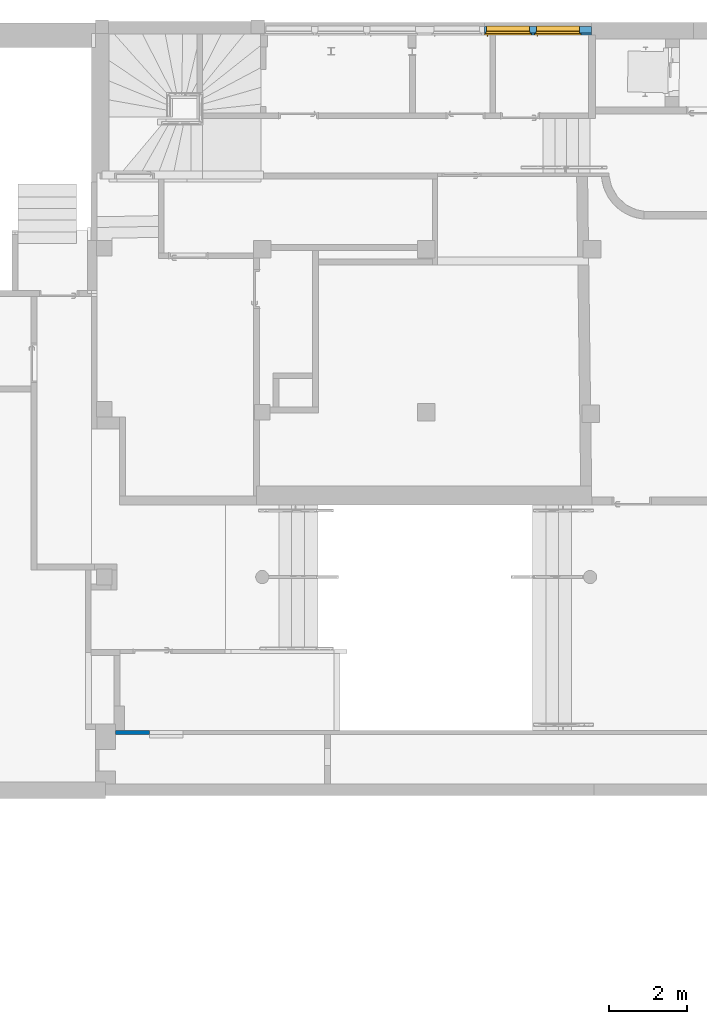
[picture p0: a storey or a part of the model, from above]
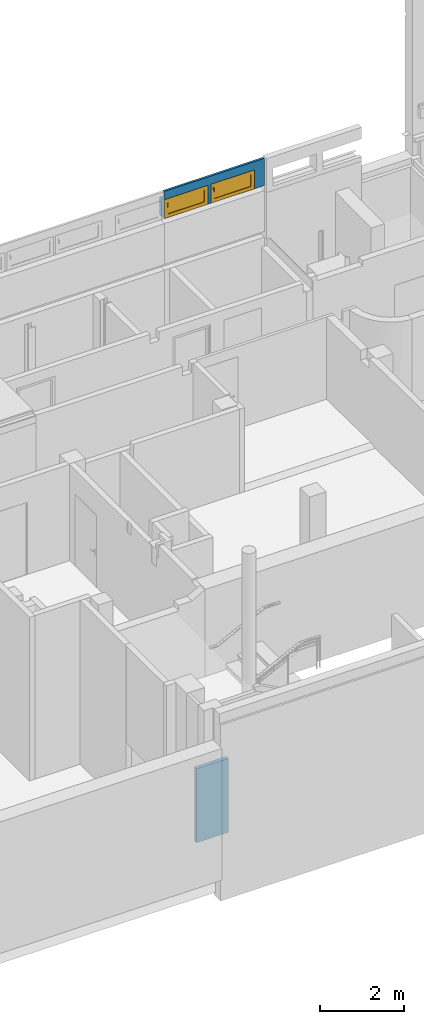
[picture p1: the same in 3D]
Properties of the parts of a building model (IFC4), part 1 of 8

# File
Description: ViewDefinition [ReferenceView_V1.2], ExchangeRequirement []
File name: 0001
Time: 2021-03-12T11:23:30
Author: Y.BENMESSAOUD, y.benmessaoud@geosolutions.pro
Organization: GEOSOLUTIONS
Written by: The EXPRESS Data Manager Version 5.02.0100.07 : 28 Aug 2013
Made in: 21.1.20.44 - Exporter 21.1.20.44 - Interface utilisateur alternative 21.1.20.44
Authorization: Y.B
Comment: STEP Physical File produced by: The EXPRESS Data Manager Version 5.02.0100.07 : 28 Aug 2013 * Module: EDMstepFileFactory/EDMstandAlone * Creation date: Fri Mar 12 11:23:30 2021 * Host: PC016 * Database: C:\Users\Y4B58~1.BEN\AppData\Local\Temp\75d09875-ea6d-4645-b1e7-cd248468171c\5325212e-278c-4a36-abae-7d6a19fac22a\ifc * Database version: 5507 * Database creation date: Fri Mar 12 11:21:37 2021 * Schema: IFC4 * Model: DataRepository.ifc * Model creation date: Fri Mar 12 11:21:38 2021 * Header model: DataRepository.ifc_HeaderModel * Header model creation date: Fri Mar 12 11:21:38 2021 * EDMuser: sdai-user * EDMgroup: sdai-group * License ID and type: 5605 : Permanent license. Expiry date: * EDMstepFileFactory options: 020000

# IfcProject, 0001
LongName: HOTEL CONSULAIRE; Phase: EXISTANT

# IfcSite, Default
RefLatitude: 50, 43, 39, 195556; RefLongitude: 1, 35, 57, 184839; RefElevation: 0 m
Pset_SiteCommon - Reference: Informations sur le projet

# IfcBuilding, HOTEL CONSULAIRE BOULOGNE SUR MER
LongName: HOTEL CONSULAIRE BOULOGNE SUR MER
Pset_BuildingCommon - Reference: Informations sur le projet; NumberOfStoreys: 7
Pset_BuildingElementProxyCommon - Reference: Informations sur le projet; IsExternal: no
Pset_BuildingStoreyCommon - Reference: Informations sur le projet; sets with these values: 2

# IfcBuildingStorey: Niveau:Ligne du Niveau (7)
In: HOTEL CONSULAIRE BOULOGNE SUR MER
Pset_BuildingStoreyCommon - Reference: Ligne du Niveau
Name | LongName | Elevation (m)
SS3 | SS3 | -5.02344
SS2 | SS2 | -4.01003
SS1 | SS1 | -2.70344
Demi-niveau | Demi-niveau | -1.4042
Niveau 0 | Niveau 0 | 1.31982e-13
Niveau 1 | Niveau 1 | 3.62153
Niveau 2 | Niveau 2 | 6.81974

# IfcBeam: Poutre rectangulaire - Béton:120X220 (9)
In: Niveau 0
Type - PredefinedType: BEAM; Material: Béton - Béton coulé sur place
Type - Pset_BeamCommon - IsExternal: no; LoadBearing: yes; Reference: 120X220
Type - Pset_EnvironmentalImpactIndicators - Reference: 120X220
Type - Pset_ReinforcementBarPitchOfBeam - Reference: 120X220
Pset_BeamCommon - Slope: 0 deg; Roll: 0 deg
Pset_EnvironmentalImpactIndicators - sets with these values: 2
Name (Poutre rectangulaire - Béton:120X220:...) | Span (m) | Length (m) | CrossSectionArea (m2) | OuterSurfaceArea (m2) | GrossSurfaceArea (m2) = NetSurfaceArea (m2) | GrossVolume (m3) = NetVolume (m3)
419842 | 0.91 | 0.12 | 0.343695 | 0.277296 | 0.687391 | 0.0246057
419898 | 0.91 | 0.12 | 0.343695 | 0.277296 | 0.687391 | 0.0246057
496445 | 3.734 | 3.70383 | 1.2857 | 2.5186 | 2.5714 | 0.097781
496534 | 1.556 | 1.56879 | 0.559788 | 1.06678 | 1.11958 | 0.041416
497781 | 3.808 | 3.8334 | 1.32976 | 2.60671 | 2.65951 | 0.101202
497919 | 3.809 | 3.8051 | 1.32013 | 2.58747 | 2.64027 | 0.100455
497978 | 1.556 | 1.5814 | 0.564076 | 1.07535 | 1.12815 | 0.041749
522441 | 2.453 | 2.39595 | 0.841024 | 1.62925 | 1.68205 | 0.0632531
522620 | 2.469 | 2.41269 | 0.846715 | 1.64063 | 1.69343 | 0.063695

# IfcBeam: Poutre rectangulaire - Béton:120X320 (2)
In: Niveau 0
Type - PredefinedType: BEAM; Material: Béton - Béton coulé sur place
Type - Pset_BeamCommon - IsExternal: no; LoadBearing: yes; Reference: 120X320
Type - Pset_EnvironmentalImpactIndicators - Reference: 120X320
Type - Pset_ReinforcementBarPitchOfBeam - Reference: 120X320
Pset_BeamCommon - Slope: 0 deg; Roll: 0 deg
Pset_EnvironmentalImpactIndicators - sets with these values: 2
Name (Poutre rectangulaire - Béton:120X320:...) | Span (m) | Length (m) | CrossSectionArea (m2) | OuterSurfaceArea (m2) | GrossSurfaceArea (m2) = NetSurfaceArea (m2) | GrossVolume (m3) = NetVolume (m3)
496558 | 3.69 | 3.7154 | 1.67318 | 3.26955 | 3.34635 | 0.142671
496571 | 3.673 | 3.6984 | 1.6657 | 3.25459 | 3.33139 | 0.142019

# IfcBeam: Poutre rectangulaire - Béton:150X180 (2)
In: Niveau 1
Type - PredefinedType: BEAM; Material: Béton - Béton coulé sur place
Type - Pset_BeamCommon - IsExternal: no; LoadBearing: yes; Reference: 150X180
Type - Pset_EnvironmentalImpactIndicators - Reference: 150X180
Type - Pset_ReinforcementBarPitchOfBeam - Reference: 150X180
Pset_BeamCommon - Slope: 0 deg; Roll: 0 deg
Pset_EnvironmentalImpactIndicators - sets with these values: 2
Name (Poutre rectangulaire - Béton:150X180:...) | Span (m) | Length (m) | CrossSectionArea (m2) | OuterSurfaceArea (m2) | GrossSurfaceArea (m2) = NetSurfaceArea (m2) | GrossVolume (m3) = NetVolume (m3)
509333 | 10.682 | 10.682 | 3.55206 | 7.05012 | 7.10412 | 0.288414
517769 | 10.69 | 10.6904 | 3.55483 | 7.05565 | 7.10965 | 0.28864

# IfcBeam: Poutre rectangulaire - Béton:150X320, Poutre rectangulaire - Béton:150X320:479398
In: SS1
Type - PredefinedType: BEAM; Material: Béton - Béton coulé sur place
Type - Pset_BeamCommon - IsExternal: no; LoadBearing: yes; Reference: 150X320
Type - Pset_EnvironmentalImpactIndicators - Reference: 150X320
Type - Pset_ReinforcementBarPitchOfBeam - Reference: 150X320
Pset_BeamCommon - Slope: 0 deg; Roll: 0 deg; Span: 3.882 m
Pset_EnvironmentalImpactIndicators - sets with these values: 2
Qto_BeamBaseQuantities - CrossSectionArea: 1.63884 m2; NetSurfaceArea: 3.27768 m2; NetVolume: 0.150758 m3

# IfcBeam: Poutre rectangulaire - Béton:150X350, Poutre rectangulaire - Béton:150X350:438477
In: SS1
Type - PredefinedType: BEAM; Material: Béton - Béton coulé sur place
Type - Pset_BeamCommon - IsExternal: no; LoadBearing: yes; Reference: 150X350
Type - Pset_EnvironmentalImpactIndicators - Reference: 150X350
Type - Pset_ReinforcementBarPitchOfBeam - Reference: 150X350
Pset_BeamCommon - Slope: 0 deg; Roll: 0 deg; Span: 1.591 m
Pset_EnvironmentalImpactIndicators - sets with these values: 2
Qto_BeamBaseQuantities - Length: 0.15 m; CrossSectionArea: 0.852494 m2; OuterSurfaceArea: 0.591723 m2; GrossSurfaceArea: 1.70499 m2; NetSurfaceArea: 1.70499 m2; GrossVolume: 0.0834949 m3; NetVolume: 0.0834949 m3

# IfcBeam: Poutre rectangulaire - Béton:150x120, Poutre rectangulaire - Béton:150x120:495247
In: Niveau 0
Type - PredefinedType: BEAM; Material: Béton - Béton coulé sur place
Type - Pset_BeamCommon - IsExternal: no; LoadBearing: yes; Reference: 150x120
Type - Pset_EnvironmentalImpactIndicators - Reference: 150x120
Type - Pset_ReinforcementBarPitchOfBeam - Reference: 150x120
Pset_BeamCommon - Slope: 0 deg; Roll: 0 deg; Span: 5.316 m
Pset_EnvironmentalImpactIndicators - sets with these values: 2
Qto_BeamBaseQuantities - CrossSectionArea: 1.45496 m2; NetSurfaceArea: 2.90992 m2; NetVolume: 0.0956999 m3

# IfcBeam: Poutre rectangulaire - Béton:180X320 (5)
In: SS1
Type - PredefinedType: BEAM; Material: Béton - Béton coulé sur place
Type - Pset_BeamCommon - IsExternal: no; LoadBearing: yes; Reference: 180X320
Type - Pset_EnvironmentalImpactIndicators - Reference: 180X320
Type - Pset_ReinforcementBarPitchOfBeam - Reference: 180X320
Pset_BeamCommon - Slope: 0 deg; Roll: 0 deg
Pset_EnvironmentalImpactIndicators - sets with these values: 2
Name (Poutre rectangulaire - Béton:180X320:...) | Span (m) | CrossSectionArea (m2) | NetSurfaceArea (m2) | NetVolume (m3)
438396 | 1.131 | 0.618873 | 1.23775 | 0.0576957
438448 | 1.591 | 0.85945 | 1.7189 | 0.0923731 | Qto_BeamBaseQuantities - Length: 1.6037 m; OuterSurfaceArea: 1.6037 m2; GrossSurfaceArea: 1.7189 m2; GrossVolume: 0.0923731 m3
438622 | 1.591 | 0.85945 | 1.7189 | 0.0923731 | Qto_BeamBaseQuantities - Length: 1.6037 m; OuterSurfaceArea: 1.6037 m2; GrossSurfaceArea: 1.7189 m2; GrossVolume: 0.0923731 m3
479470 | 3.848 | 1.99374 | 3.98748 | 0.216989
479620 | 3.883 | 1.86644 | 3.73288 | 0.197431

# IfcBeam: Poutre rectangulaire - Béton:180X480, Poutre rectangulaire - Béton:180X480:495458
In: SS1
Type - PredefinedType: BEAM; Material: Béton - Béton coulé sur place
Type - Pset_BeamCommon - IsExternal: no; LoadBearing: yes; Reference: 180X480
Type - Pset_EnvironmentalImpactIndicators - Reference: 180X480
Type - Pset_ReinforcementBarPitchOfBeam - Reference: 180X480
Pset_BeamCommon - Slope: 0 deg; Roll: 0 deg; Span: 2.795 m
Pset_EnvironmentalImpactIndicators - sets with these values: 2
Qto_BeamBaseQuantities - Length: 2.79514 m; CrossSectionArea: 1.93119 m2; OuterSurfaceArea: 3.68958 m2; GrossSurfaceArea: 3.86238 m2; NetSurfaceArea: 3.86238 m2; GrossVolume: 0.2415 m3; NetVolume: 0.2415 m3

# IfcBeam: Poutre rectangulaire - Béton:200x200, Poutre rectangulaire - Béton:200x200:466131
In: Demi-niveau
Type - PredefinedType: BEAM; Material: Béton - Béton coulé sur place
Type - Pset_BeamCommon - IsExternal: no; LoadBearing: yes; Reference: 200x200
Type - Pset_EnvironmentalImpactIndicators - Reference: 200x200
Type - Pset_ReinforcementBarPitchOfBeam - Reference: 200x200
Pset_BeamCommon - Slope: 0 deg; Roll: 0 deg; Span: 1.591 m
Pset_EnvironmentalImpactIndicators - sets with these values: 2
Qto_BeamBaseQuantities - CrossSectionArea: 0.681313 m2; NetSurfaceArea: 1.36263 m2; NetVolume: 0.0641282 m3

# IfcBeam: Poutre rectangulaire - Béton:200x300, Poutre rectangulaire - Béton:200x300:425816
In: SS1
Type - PredefinedType: BEAM; Material: Béton - Béton coulé sur place
Type - Pset_BeamCommon - IsExternal: no; LoadBearing: yes; Reference: 200x300
Type - Pset_EnvironmentalImpactIndicators - Reference: 200x300
Type - Pset_ReinforcementBarPitchOfBeam - Reference: 200x300
Pset_BeamCommon - Slope: 0 deg; Roll: 0 deg; Span: 3.853 m
Pset_EnvironmentalImpactIndicators - sets with these values: 2
Qto_BeamBaseQuantities - Length: 3.8784 m; CrossSectionArea: 1.97881 m2; OuterSurfaceArea: 3.83962 m2; GrossSurfaceArea: 3.95762 m2; NetSurfaceArea: 3.95762 m2; GrossVolume: 0.228826 m3; NetVolume: 0.228826 m3

# IfcBeam: Poutre rectangulaire - Béton:220x150 (6)
In: Niveau 2
Type - PredefinedType: BEAM; Material: Béton - Béton coulé sur place
Type - Pset_BeamCommon - IsExternal: no; LoadBearing: yes; Reference: 220x150
Type - Pset_EnvironmentalImpactIndicators - Reference: 220x150
Type - Pset_ReinforcementBarPitchOfBeam - Reference: 220x150
Pset_BeamCommon - Slope: 0 deg; Roll: 0 deg
Pset_EnvironmentalImpactIndicators - sets with these values: 2
Name (Poutre rectangulaire - Béton:220x150:...) | Span (m) | Length (m) | CrossSectionArea (m2) | OuterSurfaceArea (m2) | GrossSurfaceArea (m2) = NetSurfaceArea (m2) | GrossVolume (m3) = NetVolume (m3)
592660 | 3.119 | 3.33938 | 1.26857 | 2.47114 | 2.53714 | 0.1102
592949 | 3.961 | 4.18067 | 1.57985 | 3.09369 | 3.15969 | 0.137962
593402 | 0.841 | 1.06129 | 0.425677 | 0.785354 | 0.851354 | 0.0350225
593489 | 1.376 | 1.15584 | 0.460659 | 0.855319 | 0.921319 | 0.0381426
593530 | 2.823 | 2.60284 | 0.996049 | 1.9261 | 1.9921 | 0.0858936
593667 | 1.447 | 1.227 | 0.48699 | 0.90798 | 0.97398 | 0.040491

# IfcBeam: Poutre rectangulaire - Béton:220x280, Poutre rectangulaire - Béton:220x280:480112
In: SS1
Type - PredefinedType: BEAM; Material: Béton - Béton coulé sur place
Type - Pset_BeamCommon - IsExternal: no; LoadBearing: yes; Reference: 220x280
Type - Pset_EnvironmentalImpactIndicators - Reference: 220x280
Type - Pset_ReinforcementBarPitchOfBeam - Reference: 220x280
Pset_BeamCommon - Slope: 0 deg; Roll: 0 deg; Span: 1.591 m
Pset_EnvironmentalImpactIndicators - sets with these values: 2
Qto_BeamBaseQuantities - Length: 0.22 m; CrossSectionArea: 0.857457 m2; OuterSurfaceArea: 0.828896 m2; GrossSurfaceArea: 1.70888 m2; NetSurfaceArea: 1.71491 m2; GrossVolume: 0.0967978 m3; NetVolume: 0.0968062 m3

# IfcBeam: Poutre rectangulaire - Béton:250X200., Poutre rectangulaire - Béton:250X200.:419462
In: Niveau 0
Type - PredefinedType: BEAM; Material: Béton - Béton coulé sur place
Type - Pset_BeamCommon - IsExternal: no; LoadBearing: yes; Reference: 250X200.
Type - Pset_EnvironmentalImpactIndicators - Reference: 250X200.
Type - Pset_ReinforcementBarPitchOfBeam - Reference: 250X200.
Pset_BeamCommon - Slope: 0 deg; Roll: 0 deg; Span: 5.84 m
Pset_EnvironmentalImpactIndicators - sets with these values: 2
Qto_BeamBaseQuantities - CrossSectionArea: 2.6234 m2; NetSurfaceArea: 5.2468 m2; NetVolume: 0.277981 m3

# IfcBeam: Poutre rectangulaire - Béton:250X300 (5)
In: SS1
Type - PredefinedType: BEAM; Material: Béton - Béton coulé sur place
Type - Pset_BeamCommon - IsExternal: no; LoadBearing: yes; Reference: 250X300
Type - Pset_EnvironmentalImpactIndicators - Reference: 250X300
Type - Pset_ReinforcementBarPitchOfBeam - Reference: 250X300
Pset_BeamCommon - Slope: 0 deg; Roll: 0 deg
Pset_EnvironmentalImpactIndicators - sets with these values: 2
Name (Poutre rectangulaire - Béton:250X300:...) | Span (m) | CrossSectionArea (m2) | NetSurfaceArea (m2) | NetVolume (m3) | Length (m) | OuterSurfaceArea (m2) | GrossSurfaceArea (m2) | GrossVolume (m3)
443087 | 5.256 | 2.76931 | 5.53862 | 0.346448
445260 | 11.804 | 5.97533 | 11.9507 | 0.757745 | 0.25 | 2.00642 | 4.05524 | 0.256102
479332 | 9.543 | 4.8422 | 9.6844 | 0.59986
479349 | 3.93 | 2.00238 | 4.00476 | 0.239721 | 3.93 | 3.88277 | 4.00476 | 0.239721
479363 | 3.93 | 2.00865 | 4.01731 | 0.240495 | 3.9427 | 3.89531 | 4.01731 | 0.240495

# IfcBeam: Poutre rectangulaire - Béton:250X370, Poutre rectangulaire - Béton:250X370:483398
In: Demi-niveau
Type - PredefinedType: BEAM; Material: Béton - Béton coulé sur place
Type - Pset_BeamCommon - IsExternal: no; LoadBearing: yes; Reference: 250X370
Type - Pset_EnvironmentalImpactIndicators - Reference: 250X370
Type - Pset_ReinforcementBarPitchOfBeam - Reference: 250X370
Pset_BeamCommon - Slope: 0 deg; Roll: 0 deg; Span: 4.268 m
Pset_EnvironmentalImpactIndicators - sets with these values: 2
Qto_BeamBaseQuantities - CrossSectionArea: 2.74314 m2; NetSurfaceArea: 5.48628 m2; NetVolume: 0.371816 m3

# IfcBeam: Poutre rectangulaire - Béton:250X400 (2)
Type - PredefinedType: BEAM; Material: Béton - Béton coulé sur place
Type - Pset_BeamCommon - IsExternal: no; LoadBearing: yes; Reference: 250X400
Type - Pset_EnvironmentalImpactIndicators - Reference: 250X400
Type - Pset_ReinforcementBarPitchOfBeam - Reference: 250X400
Pset_BeamCommon - Slope: 0 deg; Roll: 0 deg
Pset_EnvironmentalImpactIndicators - sets with these values: 2
Name (Poutre rectangulaire - Béton:250X400:...) | In | Span (m) | CrossSectionArea (m2) | NetSurfaceArea (m2) | NetVolume (m3)
437257 | SS1 | 4.2 | 2.5859 | 5.1718 | 0.3741
494699 | Niveau 0 | 5.311 | 3.55705 | 7.1141 | 0.531137

# IfcBeam: Poutre rectangulaire - Béton:250x220 (3)
In: Niveau 0
Type - PredefinedType: BEAM; Material: Béton - Béton coulé sur place
Type - Pset_BeamCommon - IsExternal: no; LoadBearing: yes; Reference: 250x220
Type - Pset_EnvironmentalImpactIndicators - Reference: 250x220
Type - Pset_ReinforcementBarPitchOfBeam - Reference: 250x220
Pset_BeamCommon - Slope: 0 deg; Roll: 0 deg
Pset_EnvironmentalImpactIndicators - sets with these values: 2
Name (Poutre rectangulaire - Béton:250x220:...) | Span (m) | CrossSectionArea (m2) | NetSurfaceArea (m2) | NetVolume (m3) | Length (m) | OuterSurfaceArea (m2) | GrossSurfaceArea (m2) | GrossVolume (m3)
495977 | 12.18 | 5.63001 | 11.26 | 0.629502
496175 | 4.319 | 1.98275 | 3.9655 | 0.225588 | 4.1016 | 3.8555 | 3.9655 | 0.225588
496276 | 4.239 | 1.94515 | 3.8903 | 0.221188 | 4.0216 | 3.7803 | 3.8903 | 0.221188

# IfcBeam: Poutre rectangulaire - Béton:250x270 (2)
In: SS1
Type - PredefinedType: BEAM; Material: Béton - Béton coulé sur place
Type - Pset_BeamCommon - IsExternal: no; LoadBearing: yes; Reference: 250x270
Type - Pset_EnvironmentalImpactIndicators - Reference: 250x270
Type - Pset_ReinforcementBarPitchOfBeam - Reference: 250x270
Pset_BeamCommon - Slope: 0 deg; Roll: 0 deg
Pset_EnvironmentalImpactIndicators - sets with these values: 2
Name (Poutre rectangulaire - Béton:250x270:...) | Span (m) | Length (m) | CrossSectionArea (m2) | OuterSurfaceArea (m2) | GrossSurfaceArea (m2) | NetSurfaceArea (m2) | GrossVolume (m3) | NetVolume (m3)
443327 | 1.841 | 1.8664 | 0.877161 | 1.65733 | 1.75432 | 1.75432 | 0.090516 | 0.090516
479862 | 1.591 | 0.25 | 0.895841 | 0.936927 | 1.78483 | 1.79168 | 0.105988 | 0.105997

# IfcBeam: Poutre rectangulaire - Béton:250x320, Poutre rectangulaire - Béton:250x320:425621
In: SS1
Type - PredefinedType: BEAM; Material: Béton - Béton coulé sur place
Type - Pset_BeamCommon - IsExternal: no; LoadBearing: yes; Reference: 250x320
Type - Pset_EnvironmentalImpactIndicators - Reference: 250x320
Type - Pset_ReinforcementBarPitchOfBeam - Reference: 250x320
Pset_BeamCommon - Slope: 0 deg; Roll: 0 deg; Span: 1.618 m
Pset_EnvironmentalImpactIndicators - sets with these values: 2
Qto_BeamBaseQuantities - Length: 1.4307 m; CrossSectionArea: 0.895499 m2; OuterSurfaceArea: 1.631 m2; GrossSurfaceArea: 1.791 m2; NetSurfaceArea: 1.791 m2; GrossVolume: 0.114456 m3; NetVolume: 0.114456 m3

# IfcBeam: Poutre rectangulaire - Béton:250x340, Poutre rectangulaire - Béton:250x340:597369
In: Niveau 2
Type - PredefinedType: BEAM; Material: Béton - Béton coulé sur place
Type - Pset_BeamCommon - IsExternal: no; LoadBearing: yes; Reference: 250x340
Type - Pset_EnvironmentalImpactIndicators - Reference: 250x340
Type - Pset_ReinforcementBarPitchOfBeam - Reference: 250x340
Pset_BeamCommon - Slope: 0 deg; Roll: 0 deg; Span: 9.624 m
Pset_EnvironmentalImpactIndicators - sets with these values: 2
Qto_BeamBaseQuantities - Length: 0.25 m; CrossSectionArea: 5.77457 m2; OuterSurfaceArea: 5.00569 m2; GrossSurfaceArea: 11.5491 m2; NetSurfaceArea: 11.5491 m2; GrossVolume: 0.817932 m3; NetVolume: 0.817932 m3

# IfcBeam: Poutre rectangulaire - Béton:250x500, Poutre rectangulaire - Béton:250x500:485414
In: SS1
Type - PredefinedType: BEAM; Material: Béton - Béton coulé sur place
Type - Pset_BeamCommon - IsExternal: no; LoadBearing: yes; Reference: 250x500
Type - Pset_EnvironmentalImpactIndicators - Reference: 250x500
Type - Pset_ReinforcementBarPitchOfBeam - Reference: 250x500
Pset_BeamCommon - Slope: 0 deg; Roll: 0 deg; Span: 2.428 m
Pset_EnvironmentalImpactIndicators - sets with these values: 2
Qto_BeamBaseQuantities - CrossSectionArea: 1.79501 m2; NetSurfaceArea: 3.59001 m2; NetVolume: 0.272481 m3

# IfcBeam: Poutre rectangulaire - Béton:260X520 (2)
In: SS1
Type - PredefinedType: BEAM; Material: Béton - Béton coulé sur place
Type - Pset_BeamCommon - IsExternal: no; LoadBearing: yes; Reference: 260X520
Type - Pset_EnvironmentalImpactIndicators - Reference: 260X520
Type - Pset_ReinforcementBarPitchOfBeam - Reference: 260X520
Pset_BeamCommon - Slope: 0 deg; Roll: 0 deg; Span: 5.35 m
Pset_EnvironmentalImpactIndicators - sets with these values: 2
Name (Poutre rectangulaire - Béton:260X520:...) | CrossSectionArea (m2) | NetSurfaceArea (m2) | NetVolume (m3)
436179 | 4.25982 | 8.51964 | 0.617223
486168 | 4.32798 | 8.65596 | 0.714563

# IfcBeam: Poutre rectangulaire - Béton:270x650 (3)
In: Niveau 2
Type - PredefinedType: BEAM; Material: Béton - Béton coulé sur place
Type - Pset_BeamCommon - IsExternal: no; LoadBearing: yes; Reference: 270x650
Type - Pset_EnvironmentalImpactIndicators - Reference: 270x650
Type - Pset_ReinforcementBarPitchOfBeam - Reference: 270x650
Pset_BeamCommon - Slope: 0 deg; Roll: 0 deg
Pset_EnvironmentalImpactIndicators - sets with these values: 2
Name (Poutre rectangulaire - Béton:270x650:...) | Span (m) | Length (m) | CrossSectionArea (m2) | OuterSurfaceArea (m2) | GrossSurfaceArea (m2) | NetSurfaceArea (m2) | GrossVolume (m3) | NetVolume (m3)
568801 | 8.436 | 0.27 | 8.1341 | 5.08621 | 16.2682 | 16.2682 | 1.50957 | 1.50957
568870 | 8.436 | 0.27 | 8.1341 | 5.08621 | 16.2682 | 16.2682 | 1.50957 | 1.50957
580515 | 4.169 |  | 4.03435 |  |  | 8.0687 |  | 0.697556

# IfcBeam: Poutre rectangulaire - Béton:300X320, Poutre rectangulaire - Béton:300X320:485666
In: SS1
Type - PredefinedType: BEAM; Material: Béton - Béton coulé sur place
Type - Pset_BeamCommon - IsExternal: no; LoadBearing: yes; Reference: 300X320
Type - Pset_EnvironmentalImpactIndicators - Reference: 300X320
Type - Pset_ReinforcementBarPitchOfBeam - Reference: 300X320
Pset_BeamCommon - Slope: 0 deg; Roll: 0 deg; Span: 4.033 m
Pset_EnvironmentalImpactIndicators - sets with these values: 2
Qto_BeamBaseQuantities - CrossSectionArea: 2.44328 m2; NetSurfaceArea: 4.88656 m2; NetVolume: 0.252812 m3

# IfcBeam: Poutre rectangulaire - Béton:300X400 (3)
Type - PredefinedType: BEAM; Material: Béton - Béton coulé sur place
Type - Pset_BeamCommon - IsExternal: no; LoadBearing: yes; Reference: 300X400
Type - Pset_EnvironmentalImpactIndicators - Reference: 300X400
Type - Pset_ReinforcementBarPitchOfBeam - Reference: 300X400
Pset_BeamCommon - Slope: 0 deg; Roll: 0 deg
Pset_EnvironmentalImpactIndicators - sets with these values: 2
Name (Poutre rectangulaire - Béton:300X400:...) | In | Span (m) | CrossSectionArea (m2) | NetSurfaceArea (m2) | NetVolume (m3)
521220 | Demi-niveau | 4.409 | 3.18887 | 6.37774 | 0.519366
556946 | Niveau 2 | 4.409 | 3.22408 | 6.44816 | 0.532128 | Qto_BeamBaseQuantities - Length: 4.4344 m; OuterSurfaceArea: 6.20816 m2; GrossSurfaceArea: 6.44816 m2; GrossVolume: 0.532128 m3
587859 | Niveau 2 | 9.679 | 7.71486 | 15.4297 | 1.01394

# IfcBeam: Poutre rectangulaire - Béton:300x300, Poutre rectangulaire - Béton:300x300:449726
In: SS1
Type - PredefinedType: BEAM; Material: Béton - Béton coulé sur place
Type - Pset_BeamCommon - IsExternal: no; LoadBearing: yes; Reference: 300x300
Type - Pset_EnvironmentalImpactIndicators - Reference: 300x300
Type - Pset_ReinforcementBarPitchOfBeam - Reference: 300x300
Pset_BeamCommon - Slope: 0 deg; Roll: 0 deg; Span: 3.85 m
Pset_EnvironmentalImpactIndicators - sets with these values: 2
Qto_BeamBaseQuantities - Length: 3.84949 m; CrossSectionArea: 2.37476 m2; OuterSurfaceArea: 4.57312 m2; GrossSurfaceArea: 4.74952 m2; NetSurfaceArea: 4.74952 m2; GrossVolume: 0.339514 m3; NetVolume: 0.339514 m3

# IfcBeam: Poutre rectangulaire - Béton:300x340 (3)
In: Niveau 2
Type - PredefinedType: BEAM; Material: Béton - Béton coulé sur place
Type - Pset_BeamCommon - IsExternal: no; LoadBearing: yes; Reference: 300x340
Type - Pset_EnvironmentalImpactIndicators - Reference: 300x340
Type - Pset_ReinforcementBarPitchOfBeam - Reference: 300x340
Pset_BeamCommon - Slope: 0 deg; Roll: 0 deg
Pset_EnvironmentalImpactIndicators - sets with these values: 2
Name (Poutre rectangulaire - Béton:300x340:...) | Span (m) | Length (m) | CrossSectionArea (m2) | OuterSurfaceArea (m2) | GrossSurfaceArea (m2) = NetSurfaceArea (m2) | GrossVolume (m3) = NetVolume (m3)
565609 | 10.917 | 10.77 | 6.99483 | 13.7857 | 13.9897 | 1.09854
569971 | 11.121 | 10.9741 | 7.1254 | 14.0468 | 14.2508 | 1.11935
587700 | 9.235 | 9.1163 | 5.93643 | 11.6689 | 11.8729 | 0.929863

# IfcBeam: Poutre rectangulaire - Béton:320x340 (17)
Type - PredefinedType: BEAM; Material: Béton - Béton coulé sur place
Type - Pset_BeamCommon - IsExternal: no; LoadBearing: yes; Reference: 320x340
Type - Pset_EnvironmentalImpactIndicators - Reference: 320x340
Type - Pset_ReinforcementBarPitchOfBeam - Reference: 320x340
Pset_BeamCommon - Slope: 0 deg; Roll: 0 deg
Pset_EnvironmentalImpactIndicators - sets with these values: 2
Name (Poutre rectangulaire - Béton:320x340:...) | In | Span (m) | CrossSectionArea (m2) | NetSurfaceArea (m2) | NetVolume (m3) | Length (m) | OuterSurfaceArea (m2) | GrossSurfaceArea (m2) | GrossVolume (m3)
372262 | Niveau 0 | 19.81 | 13.3147 | 26.6294 | 2.12422
372480 | Niveau 0 | 8.46 | 5.5722 | 11.1444 | 0.835632 | 8.29 | 10.9428 | 11.1444 | 0.835632
372955 | Niveau 0 | 36.463 | 23.9854 | 47.9707 | 3.76658
372963 | Niveau 0 | 19.81 | 12.9652 | 25.9305 | 2.11936 | 19.4794 | 25.7129 | 25.9305 | 2.11936
373407 | Niveau 0 | 10.996 | 7.36643 | 14.7329 | 1.15006
395639 | Niveau 0 | 11.377 | 7.40403 | 14.8081 | 1.18467 | 10.6904 | 14.1113 | 14.3289 | 1.16311
507128 | Niveau 1 | 19.81 | 12.9583 | 25.9167 | 2.11283 | 19.4694 | 25.6997 | 25.9167 | 2.11283
507182 | Niveau 2 | 19.81 | 12.9586 | 25.9173 | 2.11827 | 19.4694 | 25.6997 | 25.9173 | 2.11827
507630 | Niveau 1 | 25.271 | 16.6752 | 33.3504 | 2.72304
507632 | Niveau 1 | 25.271 | 16.6752 | 33.3504 | 2.7309 | 0.32 | 16.2823 | 33.3504 | 2.7309
507637 | Niveau 2 | 25.271 | 16.6752 | 33.3504 | 2.73095 | 25.1006 | 33.1328 | 33.3504 | 2.73095
507639 | Niveau 2 | 25.271 | 16.6752 | 33.3504 | 2.73095 | 25.1006 | 33.1328 | 33.3504 | 2.73095
508130 | Niveau 1 | 19.81 | 12.9586 | 25.9173 | 2.11827 | 19.4694 | 25.6997 | 25.9173 | 2.11827
508134 | Niveau 2 | 19.64 | 12.9586 | 25.9173 | 2.11827 | 19.4694 | 25.6997 | 25.9173 | 2.11827
509055 | Niveau 2 | 10.682 | 7.15892 | 14.3178 | 1.1622 | 10.682 | 14.1002 | 14.3178 | 1.1622
517431 | Niveau 2 | 10.69 | 7.16445 | 14.3289 | 1.16311 | 10.6904 | 14.1113 | 14.3289 | 1.16311
578897 | Niveau 2 | 12.491 | 8.55065 | 17.1013 | 1.39163 | 12.7907 | 16.8837 | 17.1013 | 1.39163

# IfcBeam: Poutre rectangulaire - Béton:350X200., Poutre rectangulaire - Béton:350X200.:419564
In: Niveau 0
Type - PredefinedType: BEAM; Material: Béton - Béton coulé sur place
Type - Pset_BeamCommon - IsExternal: no; LoadBearing: yes; Reference: 350X200.
Type - Pset_EnvironmentalImpactIndicators - Reference: 350X200.
Type - Pset_ReinforcementBarPitchOfBeam - Reference: 350X200.
Pset_BeamCommon - Slope: 0 deg; Roll: 0 deg; Span: 1.42 m
Pset_EnvironmentalImpactIndicators - sets with these values: 2
Qto_BeamBaseQuantities - CrossSectionArea: 0.78773 m2; NetSurfaceArea: 1.57546 m2; NetVolume: 0.0808091 m3

# IfcBeam: Poutre rectangulaire - Béton:350x320, Poutre rectangulaire - Béton:350x320:499010
In: Niveau 0
Type - PredefinedType: BEAM; Material: Béton - Béton coulé sur place
Type - Pset_BeamCommon - IsExternal: no; LoadBearing: yes; Reference: 350x320
Type - Pset_EnvironmentalImpactIndicators - Reference: 350x320
Type - Pset_ReinforcementBarPitchOfBeam - Reference: 350x320
Pset_BeamCommon - Slope: 0 deg; Roll: 0 deg; Span: 4.021 m
Pset_EnvironmentalImpactIndicators - sets with these values: 2
Qto_BeamBaseQuantities - Length: 0.35 m; CrossSectionArea: 2.82144 m2; OuterSurfaceArea: 1.08842 m2; GrossSurfaceArea: 1.82628 m2; NetSurfaceArea: 5.64289 m2; GrossVolume: 0.129125 m3; NetVolume: 0.406841 m3

# IfcBeam: Poutre rectangulaire - Béton:360x640, Poutre rectangulaire - Béton:360x640:557096
In: Niveau 2
Type - PredefinedType: BEAM; Material: Béton - Béton coulé sur place
Type - Pset_BeamCommon - IsExternal: no; LoadBearing: yes; Reference: 360x640
Type - Pset_EnvironmentalImpactIndicators - Reference: 360x640
Type - Pset_ReinforcementBarPitchOfBeam - Reference: 360x640
Pset_BeamCommon - Slope: 0 deg; Roll: 0 deg; Span: 10.093 m
Pset_EnvironmentalImpactIndicators - sets with these values: 2
Qto_BeamBaseQuantities - Length: 3.79888 m; CrossSectionArea: 10.0369 m2; OuterSurfaceArea: 7.59776 m2; GrossSurfaceArea: 8.05856 m2; NetSurfaceArea: 20.0739 m2; GrossVolume: 0.875262 m3; NetVolume: 2.15326 m3

# IfcBeam: Poutre rectangulaire - Béton:360x720, Poutre rectangulaire - Béton:360x720:442139
In: SS1
Type - PredefinedType: BEAM; Material: Béton - Béton coulé sur place
Type - Pset_BeamCommon - IsExternal: no; LoadBearing: yes; Reference: 360x720
Type - Pset_EnvironmentalImpactIndicators - Reference: 360x720
Type - Pset_ReinforcementBarPitchOfBeam - Reference: 360x720
Pset_BeamCommon - Slope: 0 deg; Roll: 0 deg; Span: 1.355 m
Pset_EnvironmentalImpactIndicators - sets with these values: 2
Qto_BeamBaseQuantities - CrossSectionArea: 1.71607 m2; NetSurfaceArea: 3.43215 m2; NetVolume: 0.315977 m3

# IfcBeam: Poutre rectangulaire - Béton:380X610, Poutre rectangulaire - Béton:380X610:461217
In: Niveau 0
Type - PredefinedType: BEAM; Material: Béton - Béton coulé sur place
Type - Pset_BeamCommon - IsExternal: no; LoadBearing: yes; Reference: 380X610
Type - Pset_EnvironmentalImpactIndicators - Reference: 380X610
Type - Pset_ReinforcementBarPitchOfBeam - Reference: 380X610
Pset_BeamCommon - Slope: 0 deg; Roll: 0 deg; Span: 9.36 m
Pset_EnvironmentalImpactIndicators - sets with these values: 2
Qto_BeamBaseQuantities - Length: 9.3854 m; CrossSectionArea: 9.52335 m2; OuterSurfaceArea: 18.5831 m2; GrossSurfaceArea: 19.0467 m2; NetSurfaceArea: 19.0467 m2; GrossVolume: 2.17554 m3; NetVolume: 2.17554 m3

# IfcBeam: Poutre rectangulaire - Béton:400X360, Poutre rectangulaire - Béton:400X360:440370
In: SS1
Type - PredefinedType: BEAM; Material: Béton - Béton coulé sur place
Type - Pset_BeamCommon - IsExternal: no; LoadBearing: yes; Reference: 400X360
Type - Pset_EnvironmentalImpactIndicators - Reference: 400X360
Type - Pset_ReinforcementBarPitchOfBeam - Reference: 400X360
Pset_BeamCommon - Slope: 0 deg; Roll: 0 deg; Span: 4.158 m
Pset_EnvironmentalImpactIndicators - sets with these values: 2
Qto_BeamBaseQuantities - CrossSectionArea: 2.85493 m2; NetSurfaceArea: 5.70986 m2; NetVolume: 0.441436 m3

# IfcBeam: Poutre rectangulaire - Béton:400x220 (3)
In: Niveau 0
Type - PredefinedType: BEAM; Material: Béton - Béton coulé sur place
Type - Pset_BeamCommon - IsExternal: no; LoadBearing: yes; Reference: 400x220
Type - Pset_EnvironmentalImpactIndicators - Reference: 400x220
Type - Pset_ReinforcementBarPitchOfBeam - Reference: 400x220
Pset_BeamCommon - Slope: 0 deg; Roll: 0 deg
Pset_EnvironmentalImpactIndicators - sets with these values: 2
Name (Poutre rectangulaire - Béton:400x220:...) | Span (m) | CrossSectionArea (m2) | NetSurfaceArea (m2) | NetVolume (m3) | Length (m) | OuterSurfaceArea (m2) | GrossSurfaceArea (m2) | GrossVolume (m3)
498307 | 7.837 | 4.82404 | 9.64808 | 0.651843
498462 | 3.692 | 2.3772 | 4.75439 | 0.324918 | 3.69225 | 4.57839 | 4.75439 | 0.324918
498794 | 3.89 | 2.49957 | 4.99914 | 0.342287 | 3.88963 | 4.82314 | 4.99914 | 0.342287

# IfcBeam: Poutre rectangulaire - Béton:420X360, Poutre rectangulaire - Béton:420X360:439983
In: SS1
Type - PredefinedType: BEAM; Material: Béton - Béton coulé sur place
Type - Pset_BeamCommon - IsExternal: no; LoadBearing: yes; Reference: 420X360
Type - Pset_EnvironmentalImpactIndicators - Reference: 420X360
Type - Pset_ReinforcementBarPitchOfBeam - Reference: 420X360
Pset_BeamCommon - Slope: 0 deg; Roll: 0 deg; Span: 3.765 m
Pset_EnvironmentalImpactIndicators - sets with these values: 2
Qto_BeamBaseQuantities - CrossSectionArea: 3.05274 m2; NetSurfaceArea: 6.10548 m2; NetVolume: 0.455951 m3

# IfcBuildingElementProxy: Ascenseur 4 personnes - Mur:1000 x 880mm (6)
Type - Material: <Unnamed>
Type - Pset_BuildingElementProxyCommon - IsExternal: no; Reference: 1000 x 880mm
Type - Pset_EnvironmentalImpactIndicators - Reference: 1000 x 880mm
Name (Ascenseur 4 personnes - Mur:1000 x 880mm:...) | In
299243 | Niveau 0
399313 | Demi-niveau | Pset_EnvironmentalImpactIndicators - sets with these values: 2
443557 | SS3 | Pset_EnvironmentalImpactIndicators - sets with these values: 2
490950 | SS1
550221 | Niveau 1
560473 | Niveau 2

# IfcBuildingElementProxy: Corniche 2:Corniche 2, Corniche 2:Corniche 2:379713
In: Niveau 0
Type - Material: Plâtre
Type - Pset_BuildingElementProxyCommon - IsExternal: no; Reference: Corniche 2
Type - Pset_EnvironmentalImpactIndicators - Reference: Corniche 2

# IfcBuildingElementProxy: Corniche 3:Corniche 3, Corniche 3:Corniche 3:380022
In: Niveau 0
Type - Material: Plâtre
Type - Pset_BuildingElementProxyCommon - IsExternal: no; Reference: Corniche 3
Type - Pset_EnvironmentalImpactIndicators - Reference: Corniche 3

# IfcBuildingElementProxy: Corniche amphithéâtre 2:Corniche amphithéâtre 2, Corniche amphithéâtre 2:Corniche amphithéâtre 2:457076
In: SS1
Type - Material: peinture bleu
Type - Pset_BuildingElementProxyCommon - IsExternal: no; Reference: Corniche amphithéâtre 2
Type - Pset_EnvironmentalImpactIndicators - Reference: Corniche amphithéâtre 2

# IfcBuildingElementProxy: Corniche:Corniche, Corniche:Corniche:379482
In: Niveau 0
Type - Material: Plâtre
Type - Pset_BuildingElementProxyCommon - IsExternal: no; Reference: Corniche
Type - Pset_EnvironmentalImpactIndicators - Reference: Corniche

# IfcBuildingElementProxy: Décoration plafond1:Décoration plafond, Décoration plafond1:Décoration plafond:456437
In: SS1
Type - Material: peinture rouge
Type - Pset_BuildingElementProxyCommon - IsExternal: no; Reference: Décoration plafond
Type - Pset_EnvironmentalImpactIndicators - Reference: Décoration plafond

# IfcBuildingElementProxy: Décoration plafond2:Décoration plafond, Décoration plafond2:Décoration plafond:456461
In: SS1
Type - Material: peinture rouge
Type - Pset_BuildingElementProxyCommon - IsExternal: no; Reference: Décoration plafond
Type - Pset_EnvironmentalImpactIndicators - Reference: Décoration plafond

# IfcBuildingElementProxy: Décoration plafond3:Décoration plafond, Décoration plafond3:Décoration plafond:456527
In: SS1
Type - Material: peinture rouge
Type - Pset_BuildingElementProxyCommon - IsExternal: no; Reference: Décoration plafond
Type - Pset_EnvironmentalImpactIndicators - Reference: Décoration plafond

# IfcBuildingElementProxy: Décoration plafond:Décoration plafond, Décoration plafond:Décoration plafond:456410
In: SS1
Type - Material: peinture rouge
Type - Pset_BuildingElementProxyCommon - IsExternal: no; Reference: Décoration plafond
Type - Pset_EnvironmentalImpactIndicators - Reference: Décoration plafond

# IfcBuildingElementProxy: Elements de façade 2:Elements de façade 2, Elements de façade 2:Elements de façade 2:643688
In: Niveau 1
Type - Material: Finition Peinture - Blanc satiné
Type - Pset_BuildingElementProxyCommon - IsExternal: no; Reference: Elements de façade 2
Type - Pset_EnvironmentalImpactIndicators - Reference: Elements de façade 2

# IfcBuildingElementProxy: Elements de façade10:Elements de façade, Elements de façade10:Elements de façade:643491
In: Niveau 0
Type - Material: alu finifion bleu
Type - Pset_BuildingElementProxyCommon - IsExternal: no; Reference: Elements de façade
Type - Pset_EnvironmentalImpactIndicators - Reference: Elements de façade

# IfcBuildingElementProxy: Elements de façade11:Elements de façade, Elements de façade11:Elements de façade:643509
In: Niveau 0
Type - Material: alu finifion bleu
Type - Pset_BuildingElementProxyCommon - IsExternal: no; Reference: Elements de façade
Type - Pset_EnvironmentalImpactIndicators - Reference: Elements de façade

# IfcBuildingElementProxy: Elements de façade12:Elements de façade, Elements de façade12:Elements de façade:643527
In: Niveau 0
Type - Material: alu finifion bleu
Type - Pset_BuildingElementProxyCommon - IsExternal: no; Reference: Elements de façade
Type - Pset_EnvironmentalImpactIndicators - Reference: Elements de façade

# IfcBuildingElementProxy: Elements de façade1:Elements de façade, Elements de façade1:Elements de façade:643329
In: Niveau 0
Type - Material: alu finifion bleu
Type - Pset_BuildingElementProxyCommon - IsExternal: no; Reference: Elements de façade
Type - Pset_EnvironmentalImpactIndicators - Reference: Elements de façade

# IfcBuildingElementProxy: Elements de façade2:Elements de façade, Elements de façade2:Elements de façade:643347
In: Niveau 0
Type - Material: alu finifion bleu
Type - Pset_BuildingElementProxyCommon - IsExternal: no; Reference: Elements de façade
Type - Pset_EnvironmentalImpactIndicators - Reference: Elements de façade

# IfcBuildingElementProxy: Elements de façade3:Elements de façade, Elements de façade3:Elements de façade:643365
In: Niveau 0
Type - Material: alu finifion bleu
Type - Pset_BuildingElementProxyCommon - IsExternal: no; Reference: Elements de façade
Type - Pset_EnvironmentalImpactIndicators - Reference: Elements de façade

# IfcBuildingElementProxy: Elements de façade4:Elements de façade, Elements de façade4:Elements de façade:643383
In: Niveau 0
Type - Material: alu finifion bleu
Type - Pset_BuildingElementProxyCommon - IsExternal: no; Reference: Elements de façade
Type - Pset_EnvironmentalImpactIndicators - Reference: Elements de façade

# IfcBuildingElementProxy: Elements de façade5:Elements de façade, Elements de façade5:Elements de façade:643401
In: Niveau 0
Type - Material: alu finifion bleu
Type - Pset_BuildingElementProxyCommon - IsExternal: no; Reference: Elements de façade
Type - Pset_EnvironmentalImpactIndicators - Reference: Elements de façade

# IfcBuildingElementProxy: Elements de façade6:Elements de façade, Elements de façade6:Elements de façade:643419
In: Niveau 0
Type - Material: alu finifion bleu
Type - Pset_BuildingElementProxyCommon - IsExternal: no; Reference: Elements de façade
Type - Pset_EnvironmentalImpactIndicators - Reference: Elements de façade

# IfcBuildingElementProxy: Elements de façade7:Elements de façade, Elements de façade7:Elements de façade:643437
In: Niveau 0
Type - Material: alu finifion bleu
Type - Pset_BuildingElementProxyCommon - IsExternal: no; Reference: Elements de façade
Type - Pset_EnvironmentalImpactIndicators - Reference: Elements de façade

# IfcBuildingElementProxy: Elements de façade8:Elements de façade, Elements de façade8:Elements de façade:643455
In: Niveau 0
Type - Material: alu finifion bleu
Type - Pset_BuildingElementProxyCommon - IsExternal: no; Reference: Elements de façade
Type - Pset_EnvironmentalImpactIndicators - Reference: Elements de façade

# IfcBuildingElementProxy: Elements de façade9:Elements de façade, Elements de façade9:Elements de façade:643473
In: Niveau 0
Type - Material: alu finifion bleu
Type - Pset_BuildingElementProxyCommon - IsExternal: no; Reference: Elements de façade
Type - Pset_EnvironmentalImpactIndicators - Reference: Elements de façade

# IfcBuildingElementProxy: Elements de façade:Elements de façade, Elements de façade:Elements de façade:643255
In: Niveau 0
Type - Material: alu finifion bleu
Type - Pset_BuildingElementProxyCommon - IsExternal: no; Reference: Elements de façade
Type - Pset_EnvironmentalImpactIndicators - Reference: Elements de façade

# IfcBuildingElementProxy: Linteau:Linteau, Linteau:Linteau:587304
In: Niveau 2
Type - Material: <Unnamed>, Finition Peinture - Blanc satiné
Type - Pset_BuildingElementProxyCommon - IsExternal: no; LoadBearing: yes; Reference: Linteau
Type - Pset_EnvironmentalImpactIndicators - Reference: Linteau
Material: Finition Peinture - Blanc satiné

# IfcBuildingElementProxy: Modèles génériques 1:Modèles génériques 1, Modèles génériques 1:Modèles génériques 1:354576
In: Niveau 0
Type - Material: Bronze
Type - Pset_BuildingElementProxyCommon - IsExternal: no; Reference: Modèles génériques 1
Type - Pset_EnvironmentalImpactIndicators - Reference: Modèles génériques 1
Material: Bronze, Acier, carbone

# IfcBuildingElementProxy: Modèles génériques 2:Modèles génériques 1, Modèles génériques 2:Modèles génériques 1:356189
In: Niveau 0
Type - Material: Bronze
Type - Pset_BuildingElementProxyCommon - IsExternal: no; Reference: Modèles génériques 1
Type - Pset_EnvironmentalImpactIndicators - Reference: Modèles génériques 1
Material: Bronze, Acier, carbone

# IfcBuildingElementProxy: Modèles génériques 3:Modèles génériques 1, Modèles génériques 3:Modèles génériques 1:356473
In: Niveau 0
Type - Material: Bronze
Type - Pset_BuildingElementProxyCommon - IsExternal: no; Reference: Modèles génériques 1
Type - Pset_EnvironmentalImpactIndicators - Reference: Modèles génériques 1
Material: Bronze, Acier, carbone

# IfcBuildingElementProxy: Modèles génériques 4:Modèles génériques 1, Modèles génériques 4:Modèles génériques 1:356669
In: Niveau 0
Type - Material: Bronze
Type - Pset_BuildingElementProxyCommon - IsExternal: no; Reference: Modèles génériques 1
Type - Pset_EnvironmentalImpactIndicators - Reference: Modèles génériques 1
Material: Bronze, Acier, carbone

# IfcBuildingElementProxy: Modèles génériques 5:Modèles génériques 1, Modèles génériques 5:Modèles génériques 1:356865
In: Niveau 0
Type - Material: Bronze
Type - Pset_BuildingElementProxyCommon - IsExternal: no; Reference: Modèles génériques 1
Type - Pset_EnvironmentalImpactIndicators - Reference: Modèles génériques 1
Material: Bronze, Acier, carbone

# IfcBuildingElementProxy: cabine de projection:cabine de projection, cabine de projection:cabine de projection:460309
In: SS2
Type - Material: PEINTURE ROSE
Type - Pset_BuildingElementProxyCommon - IsExternal: no; Reference: cabine de projection
Type - Pset_EnvironmentalImpactIndicators - Reference: cabine de projection

# IfcBuildingElementProxy: corniche amphithéâtre:corniche amphithéâtre, corniche amphithéâtre:corniche amphithéâtre:456922
In: SS1
Type - Material: peinture bleu
Type - Pset_BuildingElementProxyCommon - IsExternal: no; Reference: corniche amphithéâtre
Type - Pset_EnvironmentalImpactIndicators - Reference: corniche amphithéâtre

# IfcBuildingElementProxy: demi cercle decoratif:demi cercle decoratif, demi cercle decoratif:demi cercle decoratif:643124
In: Niveau 1
Type - Material: peinture bleu
Type - Pset_BuildingElementProxyCommon - IsExternal: no; Reference: demi cercle decoratif
Type - Pset_EnvironmentalImpactIndicators - Reference: demi cercle decoratif

# IfcBuildingElementProxy: décoration1:décoration, décoration1:décoration:622694
In: Niveau 0
Type - Material: Finition Peinture - Blanc satiné
Type - Pset_BuildingElementProxyCommon - IsExternal: no; Reference: décoration
Type - Pset_EnvironmentalImpactIndicators - Reference: décoration

# IfcBuildingElementProxy: décoration2:décoration, décoration2:décoration:622711
In: Niveau 0
Type - Material: Finition Peinture - Blanc satiné
Type - Pset_BuildingElementProxyCommon - IsExternal: no; Reference: décoration
Type - Pset_EnvironmentalImpactIndicators - Reference: décoration

# IfcBuildingElementProxy: décoration3:décoration, décoration3:décoration:622728
In: Niveau 0
Type - Material: Finition Peinture - Blanc satiné
Type - Pset_BuildingElementProxyCommon - IsExternal: no; Reference: décoration
Type - Pset_EnvironmentalImpactIndicators - Reference: décoration

# IfcBuildingElementProxy: décoration4:décoration, décoration4:décoration:622745
In: Niveau 0
Type - Material: Finition Peinture - Blanc satiné
Type - Pset_BuildingElementProxyCommon - IsExternal: no; Reference: décoration
Type - Pset_EnvironmentalImpactIndicators - Reference: décoration

# IfcBuildingElementProxy: décoration5:décoration, décoration5:décoration:622851
In: Niveau 0
Type - Material: Finition Peinture - Blanc satiné
Type - Pset_BuildingElementProxyCommon - IsExternal: no; Reference: décoration
Type - Pset_EnvironmentalImpactIndicators - Reference: décoration

# IfcBuildingElementProxy: décoration6:décoration, décoration6:décoration:622873
In: Niveau 0
Type - Material: Finition Peinture - Blanc satiné
Type - Pset_BuildingElementProxyCommon - IsExternal: no; Reference: décoration
Type - Pset_EnvironmentalImpactIndicators - Reference: décoration

# IfcBuildingElementProxy: décoration7:décoration, décoration7:décoration:622908
In: Niveau 0
Type - Material: Finition Peinture - Blanc satiné
Type - Pset_BuildingElementProxyCommon - IsExternal: no; Reference: décoration
Type - Pset_EnvironmentalImpactIndicators - Reference: décoration

# IfcBuildingElementProxy: décoration8:décoration, décoration8:décoration:622925
In: Niveau 0
Type - Material: Finition Peinture - Blanc satiné
Type - Pset_BuildingElementProxyCommon - IsExternal: no; Reference: décoration
Type - Pset_EnvironmentalImpactIndicators - Reference: décoration

# IfcBuildingElementProxy: décoration9:décoration, décoration9:décoration:622942
In: Niveau 0
Type - Material: Finition Peinture - Blanc satiné
Type - Pset_BuildingElementProxyCommon - IsExternal: no; Reference: décoration
Type - Pset_EnvironmentalImpactIndicators - Reference: décoration

# IfcBuildingElementProxy: décoration:décoration, décoration:décoration:622560
In: Niveau 0
Type - Material: Finition Peinture - Blanc satiné
Type - Pset_BuildingElementProxyCommon - IsExternal: no; Reference: décoration
Type - Pset_EnvironmentalImpactIndicators - Reference: décoration

# IfcBuildingElementProxy: eléments de façade 3:eléments de façade 3, eléments de façade 3:eléments de façade 3:646533
In: Niveau 0
Type - Material: alu finifion bleu
Type - Pset_BuildingElementProxyCommon - IsExternal: no; Reference: eléments de façade 3
Type - Pset_EnvironmentalImpactIndicators - Reference: eléments de façade 3

# IfcColumn: Poteau HE-A:HEA180 (2)
In: SS3
Type - PredefinedType: COLUMN; Material: Acier structurel - S235
Type - Pset_ColumnCommon - IsExternal: no; LoadBearing: yes; Reference: HEA180
Type - Pset_EnvironmentalImpactIndicators - Reference: HEA180
Type - Pset_ReinforcementBarPitchOfColumn - Reference: HEA180
Qto_ColumnBaseQuantities - Length: 2.48 m; CrossSectionArea: 0.0480789 m2; OuterSurfaceArea: 8.64296 m2; GrossVolume: 0.0105946 m3
Pset_EnvironmentalImpactIndicators - sets with these values: 2
Name (Poteau HE-A:HEA180:...)
441759
441840

# IfcColumn: Poteau béton - Arrondi:200mm (10)
In: SS3
Type - PredefinedType: COLUMN; Material: Maçonnerie - Béton coulé sur place, Finition Peinture - Blanc satiné
Type - Pset_ColumnCommon - IsExternal: no; LoadBearing: yes; Reference: 200mm
Type - Pset_EnvironmentalImpactIndicators - Reference: 200mm
Type - Pset_ReinforcementBarPitchOfColumn - Reference: 200mm
Material: Finition Peinture - Blanc satiné
Pset_EnvironmentalImpactIndicators - sets with these values: 2
Name (Poteau béton - Arrondi:200mm:...) | CrossSectionArea (m2) | GrossVolume (m3)
455509 | 0.338046 | 0.178875 | Qto_ColumnBaseQuantities - Length: 5.69434 m; OuterSurfaceArea: 11.7384 m2; Pset_ColumnCommon - Slope: 0 deg
455679 | 0.338046 | 0.178875 | Qto_ColumnBaseQuantities - Length: 5.69434 m; OuterSurfaceArea: 11.7384 m2
455720 | 1.89378 | 0.176102
455735 | 1.89412 | 0.176092
455750 | 1.82134 | 0.174593
455798 | 1.83733 | 0.17664
455800 | 1.83733 | 0.17664
455802 | 0.338046 | 0.178875 | Qto_ColumnBaseQuantities - Length: 5.69434 m; OuterSurfaceArea: 11.7384 m2; Pset_ColumnCommon - Slope: 0 deg
455804 | 0.338046 | 0.178875 | Qto_ColumnBaseQuantities - Length: 5.69434 m; OuterSurfaceArea: 11.7384 m2; Pset_ColumnCommon - Slope: 0 deg
455806 | 1.83897 | 0.172958

# IfcColumn: Poteau béton - Arrondi:340 (16)
Type - PredefinedType: COLUMN; Material: Maçonnerie - Béton coulé sur place
Type - Pset_ColumnCommon - IsExternal: no; Reference: 340; LoadBearing: yes
Type - Pset_EnvironmentalImpactIndicators - Reference: 340
Type - Pset_ReinforcementBarPitchOfColumn - Reference: 340
Qto_ColumnBaseQuantities - CrossSectionArea: 0.977147 m2
Pset_EnvironmentalImpactIndicators - sets with these values: 2
Name (Poteau béton - Arrondi:340:...) | In | Length (m) | OuterSurfaceArea (m2) | GrossVolume (m3)
256860 | Niveau 0 | 3.44153 | 12.0605 | 0.312448 | Pset_ColumnCommon - Slope: 0 deg
256877 | Niveau 0 | 3.42153 | 11.9904 | 0.310633
256892 | Niveau 0 | 3.44153 | 12.0605 | 0.312448
256907 | Niveau 0 | 3.44153 | 12.0605 | 0.312448
256920 | Niveau 0 | 3.44153 | 12.0605 | 0.312448
256957 | Niveau 0 | 3.44153 | 12.0605 | 0.312448
256959 | Niveau 0 | 3.44153 | 12.0605 | 0.312448
256961 | Niveau 0 | 3.44153 | 12.0605 | 0.312448
418933 | SS3 | 4.75344 | 16.6579 | 0.431554
418971 | SS2 | 4.10003 | 14.3682 | 0.372232
418986 | SS3 | 4.75344 | 16.6579 | 0.431554
419020 | SS3 | 4.75344 | 16.6579 | 0.431554
419036 | SS3 | 4.75344 | 16.6579 | 0.431554
419053 | SS2 | 3.74003 | 13.1066 | 0.339555
520718 | Niveau 1 | 3.01021 | 10.549 | 0.273292 | Pset_ColumnCommon - Slope: 0 deg
555389 | Niveau 1 | 3.01021 | 10.549 | 0.273291 | Pset_ColumnCommon - Slope: 0 deg

# IfcColumn: Poteau béton - Arrondi:600mm, Poteau béton - Arrondi:600mm:461395
In: SS3
Type - PredefinedType: COLUMN; Material: Maçonnerie - Béton coulé sur place
Type - Pset_ColumnCommon - IsExternal: no; LoadBearing: yes; Reference: 600mm
Type - Pset_EnvironmentalImpactIndicators - Reference: 600mm
Type - Pset_ReinforcementBarPitchOfColumn - Reference: 600mm
Qto_ColumnBaseQuantities - Length: 4.18924 m; CrossSectionArea: 3.04331 m2; OuterSurfaceArea: 25.9072 m2; GrossVolume: 1.18446 m3
Pset_ColumnCommon - Slope: 0 deg
Pset_EnvironmentalImpactIndicators - sets with these values: 2

# IfcColumn: Poteau béton - Rectangulaire:190x210, Poteau béton - Rectangulaire:190x210:595335
In: Niveau 2
Type - PredefinedType: COLUMN; Material: Maçonnerie - Béton coulé sur place
Type - Pset_ColumnCommon - IsExternal: no; LoadBearing: yes; Reference: 190x210
Type - Pset_EnvironmentalImpactIndicators - Reference: 190x210
Type - Pset_ReinforcementBarPitchOfColumn - Reference: 190x210
Qto_ColumnBaseQuantities - Length: 2.718 m; CrossSectionArea: 0.42948 m2; OuterSurfaceArea: 7.13386 m2; GrossVolume: 0.108448 m3
Pset_ColumnCommon - Slope: 0 deg
Pset_EnvironmentalImpactIndicators - sets with these values: 2

# IfcColumn: Poteau béton - Rectangulaire:220x220, Poteau béton - Rectangulaire:220x220:575922
In: Niveau 2
Type - PredefinedType: COLUMN; Material: Maçonnerie - Béton coulé sur place
Type - Pset_ColumnCommon - IsExternal: no; LoadBearing: yes; Reference: 220x220
Type - Pset_EnvironmentalImpactIndicators - Reference: 220x220
Type - Pset_ReinforcementBarPitchOfColumn - Reference: 220x220
Qto_ColumnBaseQuantities - Length: 2.747 m; CrossSectionArea: 0.520973 m2; OuterSurfaceArea: 7.93097 m2; GrossVolume: 0.132955 m3
Pset_EnvironmentalImpactIndicators - sets with these values: 2

# IfcColumn: Poteau béton - Rectangulaire:250x300 (2)
In: SS1
Type - PredefinedType: COLUMN; Material: Maçonnerie - Béton coulé sur place
Type - Pset_ColumnCommon - IsExternal: no; LoadBearing: yes; Reference: 250x300
Type - Pset_EnvironmentalImpactIndicators - Reference: 250x300
Type - Pset_ReinforcementBarPitchOfColumn - Reference: 250x300
Qto_ColumnBaseQuantities - Length: 2.11945 m; CrossSectionArea: 0.807293 m2; OuterSurfaceArea: 7.64892 m2; GrossVolume: 0.158958 m3
Pset_EnvironmentalImpactIndicators - sets with these values: 2
Name (Poteau béton - Rectangulaire:250x300:...)
490255
490257

# IfcColumn: Poteau béton - Rectangulaire:270x270 (8)
In: Niveau 0
Type - PredefinedType: COLUMN; Material: Maçonnerie - Béton coulé sur place
Type - Pset_ColumnCommon - IsExternal: no; LoadBearing: yes; Reference: 270x270
Type - Pset_EnvironmentalImpactIndicators - Reference: 270x270
Type - Pset_ReinforcementBarPitchOfColumn - Reference: 270x270
Qto_ColumnBaseQuantities - CrossSectionArea: 0.784689 m2
Pset_EnvironmentalImpactIndicators - sets with these values: 2
Name (Poteau béton - Rectangulaire:270x270:...) | Length (m) | OuterSurfaceArea (m2) | GrossVolume (m3)
285984 | 3.37153 | 11.9464 | 0.245784
286092 | 3.07113 | 10.8819 | 0.223885
287235 | 3.40653 | 12.0704 | 0.248336
287267 | 3.44153 | 12.1944 | 0.250887 | Pset_ColumnCommon - Slope: 0 deg
556291 | 3.44153 | 12.1944 | 0.250887 | Pset_ColumnCommon - Slope: 0 deg
556342 | 3.44153 | 12.1944 | 0.250887
556361 | 3.44153 | 12.1944 | 0.250887
556380 | 3.44153 | 12.1944 | 0.250887

# IfcColumn: Poteau béton - Rectangulaire:270x350, Poteau béton - Rectangulaire:270x350:594999
In: Niveau 2
Type - PredefinedType: COLUMN; Material: Maçonnerie - Béton coulé sur place
Type - Pset_ColumnCommon - IsExternal: no; LoadBearing: yes; Reference: 270x350
Type - Pset_EnvironmentalImpactIndicators - Reference: 270x350
Type - Pset_ReinforcementBarPitchOfColumn - Reference: 270x350
Qto_ColumnBaseQuantities - CrossSectionArea: 1.88038 m2; GrossVolume: 0.271492 m3
Pset_EnvironmentalImpactIndicators - sets with these values: 2

# IfcColumn: Poteau béton - Rectangulaire:270x530 (4)
In: Niveau 2
Type - PredefinedType: COLUMN; Material: Maçonnerie - Béton coulé sur place
Type - Pset_ColumnCommon - IsExternal: no; LoadBearing: yes; Reference: 270x530
Type - Pset_EnvironmentalImpactIndicators - Reference: 270x530
Type - Pset_ReinforcementBarPitchOfColumn - Reference: 270x530
Pset_EnvironmentalImpactIndicators - sets with these values: 2
Name (Poteau béton - Rectangulaire:270x530:...) | CrossSectionArea (m2) | GrossVolume (m3)
578270 | 1.54032 | 0.348735 | Qto_ColumnBaseQuantities - Length: 2.437 m; OuterSurfaceArea: 12.7927 m2
578321 | 1.54032 | 0.348735 | Qto_ColumnBaseQuantities - Length: 2.437 m; OuterSurfaceArea: 12.7927 m2
578399 | 2.0927 | 0.344808
578547 | 2.16942 | 0.332685

# IfcColumn: Poteau béton - Rectangulaire:300x300 (6)
In: Niveau 1
Type - PredefinedType: COLUMN; Material: Maçonnerie - Béton coulé sur place
Type - Pset_ColumnCommon - IsExternal: no; LoadBearing: yes; Reference: 300x300
Type - Pset_EnvironmentalImpactIndicators - Reference: 300x300
Type - Pset_ReinforcementBarPitchOfColumn - Reference: 300x300
Qto_ColumnBaseQuantities - CrossSectionArea: 0.968752 m2
Pset_EnvironmentalImpactIndicators - sets with these values: 2
Name (Poteau béton - Rectangulaire:300x300:...) | Length (m) | OuterSurfaceArea (m2) | GrossVolume (m3)
555103 | 3.01021 | 11.8512 | 0.270919
555105 | 3.01021 | 11.8512 | 0.270919
555111 | 3.01021 | 11.8512 | 0.270919
555125 | 3.01021 | 11.8512 | 0.270919 | Pset_ColumnCommon - Slope: 0 deg
555131 | 3.01021 | 11.8512 | 0.270919
555619 | 3.01321 | 11.863 | 0.271189

# IfcColumn: Poteau béton - Rectangulaire:300x350, Poteau béton - Rectangulaire:300x350:587544
In: Niveau 2
Type - PredefinedType: COLUMN; Material: Maçonnerie - Béton coulé sur place, Finition Peinture - Blanc satiné
Type - Pset_ColumnCommon - IsExternal: no; LoadBearing: yes; Reference: 300x350
Type - Pset_EnvironmentalImpactIndicators - Reference: 300x350
Type - Pset_ReinforcementBarPitchOfColumn - Reference: 300x350
Material: Finition Peinture - Blanc satiné
Qto_ColumnBaseQuantities - Length: 2.747 m; CrossSectionArea: 1.13021 m2; OuterSurfaceArea: 11.7162 m2; GrossVolume: 0.288435 m3
Pset_ColumnCommon - Slope: 0 deg
Pset_EnvironmentalImpactIndicators - sets with these values: 2

# IfcColumn: Poteau béton - Rectangulaire:340x340 (7)
Type - PredefinedType: COLUMN; Material: Maçonnerie - Béton coulé sur place
Type - Pset_ColumnCommon - IsExternal: no; LoadBearing: yes; Reference: 340x340
Type - Pset_EnvironmentalImpactIndicators - Reference: 340x340
Type - Pset_ReinforcementBarPitchOfColumn - Reference: 340x340
Pset_EnvironmentalImpactIndicators - sets with these values: 2
Name (Poteau béton - Rectangulaire:340x340:...) | In | Length (m) | CrossSectionArea (m2) | OuterSurfaceArea (m2) | GrossVolume (m3)
306058 | SS2 | 10.892 | 1.24431 | 48.5996 | 1.25912
306181 | Niveau 0 | 6.852 | 1.24431 | 30.5732 | 0.792091
306273 | SS3 |  | 5.61514 |  | 0.932252
306316 | SS3 |  | 8.69269 |  | 1.44898
415134 | SS2 | 2.34113 | 1.24431 | 10.446 | 0.270635
555107 | Niveau 1 | 3.01021 | 1.24431 | 13.4314 | 0.347981
556712 | Niveau 1 | 3.01021 | 1.24431 | 13.4314 | 0.347981

# IfcColumn: Poteau béton - Rectangulaire:340x340 (6)
Type - PredefinedType: COLUMN; Material: Maçonnerie - Béton coulé sur place, Finition Peinture - Blanc satiné
Type - Pset_ColumnCommon - IsExternal: no; LoadBearing: yes; Reference: 340x340
Type - Pset_EnvironmentalImpactIndicators - Reference: 340x340
Type - Pset_ReinforcementBarPitchOfColumn - Reference: 340x340
Material: Finition Peinture - Blanc satiné
Pset_EnvironmentalImpactIndicators - sets with these values: 2
Name (Poteau béton - Rectangulaire:340x340:...) | In | CrossSectionArea (m2) | GrossVolume (m3) | Length (m) | OuterSurfaceArea (m2)
306235 | SS3 | 5.61514 | 0.932252
306345 | SS3 | 1.24431 | 1.45614 | 12.5963 | 56.2041
306509 | Niveau 0 | 1.24431 | 0.378189 | 3.27153 | 14.5974
306536 | Niveau 0 | 1.24431 | 0.792091 | 6.852 | 30.5732 | Pset_ColumnCommon - Slope: 0 deg
566305 | Niveau 2 | 1.24431 | 0.317553 | 2.747 | 12.257 | Pset_ColumnCommon - Slope: 0 deg
653874 | Demi-niveau | 1.24431 | 0.0738915 | 0.6392 | 2.85207 | Pset_ColumnCommon - Slope: 0 deg

# IfcColumn: Poteau béton - Rectangulaire:340x340, Poteau béton - Rectangulaire:340x340:306594
In: Niveau 0
Type - PredefinedType: COLUMN; Material: Maçonnerie - Béton coulé sur place, peinture bleu
Type - Pset_ColumnCommon - IsExternal: no; LoadBearing: yes; Reference: 340x340
Type - Pset_EnvironmentalImpactIndicators - Reference: 340x340
Type - Pset_ReinforcementBarPitchOfColumn - Reference: 340x340
Material: peinture bleu
Qto_ColumnBaseQuantities - Length: 6.852 m; CrossSectionArea: 1.24431 m2; OuterSurfaceArea: 30.5732 m2; GrossVolume: 0.792091 m3
Pset_ColumnCommon - Slope: 0 deg
Pset_EnvironmentalImpactIndicators - sets with these values: 2

# IfcColumn: Poteau béton - Rectangulaire:360x360, Poteau béton - Rectangulaire:360x360:556828
In: Niveau 1
Type - PredefinedType: COLUMN; Material: Maçonnerie - Béton coulé sur place
Type - Pset_ColumnCommon - IsExternal: no; LoadBearing: yes; Reference: 360x360
Type - Pset_EnvironmentalImpactIndicators - Reference: 360x360
Type - Pset_ReinforcementBarPitchOfColumn - Reference: 360x360
Qto_ColumnBaseQuantities - Length: 3.01021 m; CrossSectionArea: 1.395 m2; OuterSurfaceArea: 14.2215 m2; GrossVolume: 0.390124 m3
Pset_EnvironmentalImpactIndicators - sets with these values: 2

# IfcColumn: Poteau béton - Rectangulaire:400x400 (11)
Type - PredefinedType: COLUMN; Material: Maçonnerie - Béton coulé sur place
Type - Pset_ColumnCommon - IsExternal: no; LoadBearing: yes; Reference: 400x400
Type - Pset_EnvironmentalImpactIndicators - Reference: 400x400
Type - Pset_ReinforcementBarPitchOfColumn - Reference: 400x400
Pset_EnvironmentalImpactIndicators - sets with these values: 2
Name (Poteau béton - Rectangulaire:400x400:...) | In | Length (m) | CrossSectionArea (m2) | OuterSurfaceArea (m2) | GrossVolume (m3) | Slope (deg)
424825 | SS3 | 2.75 | 1.72223 | 14.4357 | 0.44 | 0
425199 | SS3 |  | 2.516 |  | 0.457676 | 0
425296 | SS3 | 2.795 | 1.72223 | 14.6719 | 0.4472
450037 | SS3 | 2.15 | 1.72223 | 11.2861 | 0.73335
480302 | SS1 | 2.43344 | 1.72223 | 12.7739 | 0.43895
480308 | SS1 |  | 1.95075 |  | 0.356347 | 0
480314 | SS1 |  | 1.94346 |  | 0.355233 | 0
555068 | SS3 | 4.79344 | 1.72223 | 25.1624 | 0.76695 | 0
556071 | Niveau 1 |  | 2.58124 |  | 0.482715 | 0
557549 | Niveau 1 | 3.04521 | 1.72223 | 15.9854 | 0.487234 | 0
557604 | Niveau 1 | 3.04521 | 1.72223 | 15.9854 | 0.487234

# IfcColumn: Poteau béton - Rectangulaire:450X450 (11)
Type - PredefinedType: COLUMN; Material: Maçonnerie - Béton coulé sur place
Type - Pset_ColumnCommon - IsExternal: no; LoadBearing: yes; Reference: 450X450
Type - Pset_EnvironmentalImpactIndicators - Reference: 450X450
Type - Pset_ReinforcementBarPitchOfColumn - Reference: 450X450
Pset_EnvironmentalImpactIndicators - sets with these values: 2
Name (Poteau béton - Rectangulaire:450X450:...) | In | Length (m) | CrossSectionArea (m2) | OuterSurfaceArea (m2) | GrossVolume (m3)
425126 | SS3 | 2.442 | 2.17969 | 14.4213 | 0.494505
425245 | SS3 |  | 2.86166 |  | 0.541534
425249 | SS3 | 2.795 | 2.17969 | 16.5059 | 0.565987
448976 | SS3 |  | 2.42032 |  | 0.494295 | Pset_ColumnCommon - Slope: 0 deg
480312 | SS1 |  | 2.1815 |  | 0.439245 | Pset_ColumnCommon - Slope: 0 deg
481469 | SS1 | 2.11945 | 2.17969 | 12.5164 | 0.429188 | Pset_ColumnCommon - Slope: 0 deg
481580 | SS1 | 2.11945 | 2.17969 | 12.5164 | 0.429188
481659 | SS3 | 2.11945 | 2.17969 | 12.5164 | 0.928146
481908 | SS1 | 2.11945 | 2.17969 | 12.5164 | 0.429188
497210 | SS3 | 2.464 | 2.17969 | 14.5512 | 0.49896 | Pset_ColumnCommon - Slope: 0 deg
498830 | SS3 | 2.11945 | 2.17969 | 12.5164 | 0.928146

# IfcColumn: Poteau béton - Rectangulaire:500X450, Poteau béton - Rectangulaire:500X450:498562
In: SS1
Type - PredefinedType: COLUMN; Material: Maçonnerie - Béton coulé sur place
Type - Pset_ColumnCommon - IsExternal: no; LoadBearing: yes; Reference: 500X450
Type - Pset_EnvironmentalImpactIndicators - Reference: 500X450
Type - Pset_ReinforcementBarPitchOfColumn - Reference: 500X450
Qto_ColumnBaseQuantities - Length: 2.11945 m; CrossSectionArea: 2.42188 m2; OuterSurfaceArea: 13.2118 m2; GrossVolume: 0.476875 m3
Pset_ColumnCommon - Slope: 0 deg
Pset_EnvironmentalImpactIndicators - sets with these values: 2

# IfcColumn: Poteaux porteurs 100:Poteaux porteurs 1, Poteaux porteurs 100:Poteaux porteurs 1:655382
In: Demi-niveau
Type - PredefinedType: COLUMN; Material: <Unnamed>, Finition Peinture - Blanc satiné
Type - Pset_ColumnCommon - IsExternal: no; LoadBearing: yes; Reference: Poteaux porteurs 1
Type - Pset_EnvironmentalImpactIndicators - Reference: Poteaux porteurs 1
Type - Pset_ReinforcementBarPitchOfColumn - Reference: Poteaux porteurs 1
Material: Finition Peinture - Blanc satiné
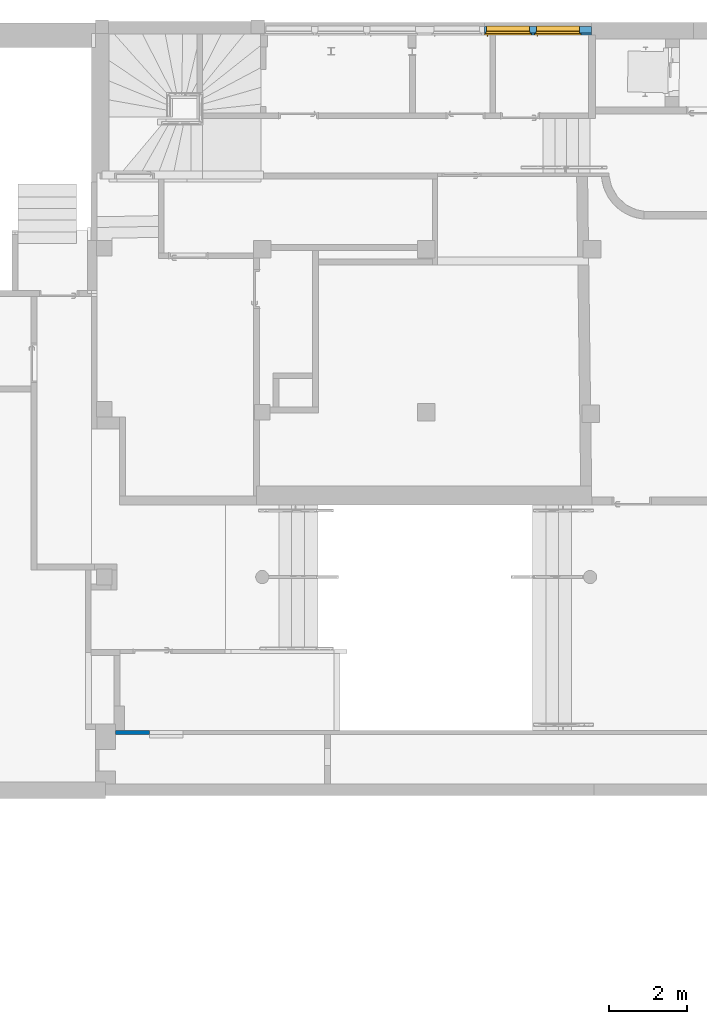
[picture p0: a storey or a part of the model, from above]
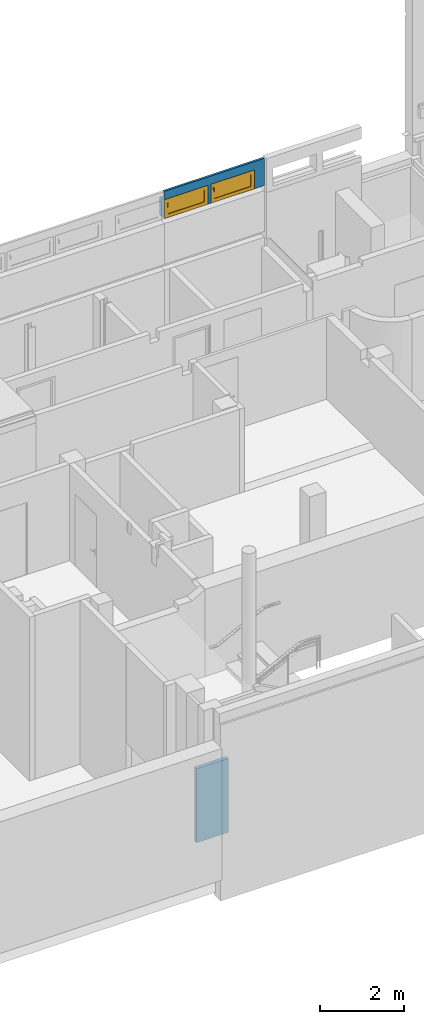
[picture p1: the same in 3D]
Properties of the parts of a building model (IFC4), part 2 of 8

# IfcColumn: Poteaux porteurs 100:Poteaux porteurs 1, Poteaux porteurs 100:Poteaux porteurs 1:655382
Qto_ColumnBaseQuantities - Length: 0.929588 m; CrossSectionArea: 0.329107 m2; OuterSurfaceArea: 2.2709 m2; GrossVolume: 0.0284222 m3
Pset_ColumnCommon - Slope: 0 deg
Pset_EnvironmentalImpactIndicators - sets with these values: 2

# IfcColumn: Poteaux porteurs 101:Poteaux porteurs 1, Poteaux porteurs 101:Poteaux porteurs 1:655401
In: Demi-niveau
Type - PredefinedType: COLUMN; Material: <Unnamed>, Finition Peinture - Blanc satiné
Type - Pset_ColumnCommon - IsExternal: no; LoadBearing: yes; Reference: Poteaux porteurs 1
Type - Pset_EnvironmentalImpactIndicators - Reference: Poteaux porteurs 1
Type - Pset_ReinforcementBarPitchOfColumn - Reference: Poteaux porteurs 1
Material: Finition Peinture - Blanc satiné
Qto_ColumnBaseQuantities - Length: 0.929588 m; CrossSectionArea: 0.329107 m2; OuterSurfaceArea: 2.2709 m2; GrossVolume: 0.0284222 m3
Pset_ColumnCommon - Slope: 0 deg
Pset_EnvironmentalImpactIndicators - sets with these values: 2

# IfcColumn: Poteaux porteurs 102:Poteaux porteurs 1, Poteaux porteurs 102:Poteaux porteurs 1:655420
In: Demi-niveau
Type - PredefinedType: COLUMN; Material: <Unnamed>, Finition Peinture - Blanc satiné
Type - Pset_ColumnCommon - IsExternal: no; LoadBearing: yes; Reference: Poteaux porteurs 1
Type - Pset_EnvironmentalImpactIndicators - Reference: Poteaux porteurs 1
Type - Pset_ReinforcementBarPitchOfColumn - Reference: Poteaux porteurs 1
Material: Finition Peinture - Blanc satiné
Qto_ColumnBaseQuantities - Length: 0.929588 m; CrossSectionArea: 0.329107 m2; OuterSurfaceArea: 2.2709 m2; GrossVolume: 0.0284222 m3
Pset_ColumnCommon - Slope: 0 deg
Pset_EnvironmentalImpactIndicators - sets with these values: 2

# IfcColumn: Poteaux porteurs 103:Poteaux porteurs 1, Poteaux porteurs 103:Poteaux porteurs 1:655448
In: Demi-niveau
Type - PredefinedType: COLUMN; Material: <Unnamed>, Finition Peinture - Blanc satiné
Type - Pset_ColumnCommon - IsExternal: no; LoadBearing: yes; Reference: Poteaux porteurs 1
Type - Pset_EnvironmentalImpactIndicators - Reference: Poteaux porteurs 1
Type - Pset_ReinforcementBarPitchOfColumn - Reference: Poteaux porteurs 1
Material: Finition Peinture - Blanc satiné
Qto_ColumnBaseQuantities - Length: 0.929588 m; CrossSectionArea: 0.329107 m2; OuterSurfaceArea: 2.2709 m2; GrossVolume: 0.0284222 m3
Pset_ColumnCommon - Slope: 0 deg
Pset_EnvironmentalImpactIndicators - sets with these values: 2

# IfcColumn: Poteaux porteurs 104:Poteaux porteurs 1, Poteaux porteurs 104:Poteaux porteurs 1:655476
In: Demi-niveau
Type - PredefinedType: COLUMN; Material: <Unnamed>, Finition Peinture - Blanc satiné
Type - Pset_ColumnCommon - IsExternal: no; LoadBearing: yes; Reference: Poteaux porteurs 1
Type - Pset_EnvironmentalImpactIndicators - Reference: Poteaux porteurs 1
Type - Pset_ReinforcementBarPitchOfColumn - Reference: Poteaux porteurs 1
Material: Finition Peinture - Blanc satiné
Qto_ColumnBaseQuantities - Length: 0.929588 m; CrossSectionArea: 0.329107 m2; OuterSurfaceArea: 2.2709 m2; GrossVolume: 0.0284222 m3
Pset_ColumnCommon - Slope: 0 deg
Pset_EnvironmentalImpactIndicators - sets with these values: 2

# IfcColumn: Poteaux porteurs 105:Poteaux porteurs 1, Poteaux porteurs 105:Poteaux porteurs 1:655937
In: Demi-niveau
Type - PredefinedType: COLUMN; Material: <Unnamed>, Finition Peinture - Blanc satiné
Type - Pset_ColumnCommon - IsExternal: no; LoadBearing: yes; Reference: Poteaux porteurs 1
Type - Pset_EnvironmentalImpactIndicators - Reference: Poteaux porteurs 1
Type - Pset_ReinforcementBarPitchOfColumn - Reference: Poteaux porteurs 1
Material: Finition Peinture - Blanc satiné
Qto_ColumnBaseQuantities - Length: 0.929588 m; CrossSectionArea: 0.29649 m2; OuterSurfaceArea: 2.11977 m2; GrossVolume: 0.0256053 m3
Pset_ColumnCommon - Slope: 0 deg
Pset_EnvironmentalImpactIndicators - sets with these values: 2

# IfcColumn: Poteaux porteurs 106:Poteaux porteurs 1, Poteaux porteurs 106:Poteaux porteurs 1:656002
In: Demi-niveau
Type - PredefinedType: COLUMN; Material: <Unnamed>, Finition Peinture - Blanc satiné
Type - Pset_ColumnCommon - IsExternal: no; LoadBearing: yes; Reference: Poteaux porteurs 1
Type - Pset_EnvironmentalImpactIndicators - Reference: Poteaux porteurs 1
Type - Pset_ReinforcementBarPitchOfColumn - Reference: Poteaux porteurs 1
Material: Finition Peinture - Blanc satiné
Qto_ColumnBaseQuantities - Length: 0.929588 m; CrossSectionArea: 0.29649 m2; OuterSurfaceArea: 2.11977 m2; GrossVolume: 0.0256053 m3
Pset_ColumnCommon - Slope: 0 deg
Pset_EnvironmentalImpactIndicators - sets with these values: 2

# IfcColumn: Poteaux porteurs 107:Poteaux porteurs 1, Poteaux porteurs 107:Poteaux porteurs 1:656056
In: Demi-niveau
Type - PredefinedType: COLUMN; Material: Finition Peinture - Blanc satiné, <Unnamed>
Type - Pset_ColumnCommon - IsExternal: no; LoadBearing: yes; Reference: Poteaux porteurs 1
Type - Pset_EnvironmentalImpactIndicators - Reference: Poteaux porteurs 1
Type - Pset_ReinforcementBarPitchOfColumn - Reference: Poteaux porteurs 1
Material: Finition Peinture - Blanc satiné
Qto_ColumnBaseQuantities - Length: 0.929588 m; CrossSectionArea: 0.29649 m2; OuterSurfaceArea: 2.11977 m2; GrossVolume: 0.0256053 m3
Pset_ColumnCommon - Slope: 0 deg
Pset_EnvironmentalImpactIndicators - sets with these values: 2

# IfcColumn: Poteaux porteurs 108:Poteaux porteurs 1, Poteaux porteurs 108:Poteaux porteurs 1:656073
In: Demi-niveau
Type - PredefinedType: COLUMN; Material: Finition Peinture - Blanc satiné, <Unnamed>
Type - Pset_ColumnCommon - IsExternal: no; LoadBearing: yes; Reference: Poteaux porteurs 1
Type - Pset_EnvironmentalImpactIndicators - Reference: Poteaux porteurs 1
Type - Pset_ReinforcementBarPitchOfColumn - Reference: Poteaux porteurs 1
Material: Finition Peinture - Blanc satiné
Qto_ColumnBaseQuantities - Length: 0.929588 m; CrossSectionArea: 0.29649 m2; OuterSurfaceArea: 2.11977 m2; GrossVolume: 0.0256053 m3
Pset_ColumnCommon - Slope: 0 deg
Pset_EnvironmentalImpactIndicators - sets with these values: 2

# IfcColumn: Poteaux porteurs 109:Poteaux porteurs 1, Poteaux porteurs 109:Poteaux porteurs 1:656090
In: Demi-niveau
Type - PredefinedType: COLUMN; Material: Finition Peinture - Blanc satiné, <Unnamed>
Type - Pset_ColumnCommon - IsExternal: no; LoadBearing: yes; Reference: Poteaux porteurs 1
Type - Pset_EnvironmentalImpactIndicators - Reference: Poteaux porteurs 1
Type - Pset_ReinforcementBarPitchOfColumn - Reference: Poteaux porteurs 1
Material: Finition Peinture - Blanc satiné
Qto_ColumnBaseQuantities - Length: 0.929588 m; CrossSectionArea: 0.29649 m2; OuterSurfaceArea: 2.11977 m2; GrossVolume: 0.0256053 m3
Pset_ColumnCommon - Slope: 0 deg
Pset_EnvironmentalImpactIndicators - sets with these values: 2

# IfcColumn: Poteaux porteurs 10:Poteaux porteurs 1, Poteaux porteurs 10:Poteaux porteurs 1:357879
In: Demi-niveau
Type - PredefinedType: COLUMN; Material: Finition Peinture - Blanc satiné, <Unnamed>
Type - Pset_ColumnCommon - IsExternal: no; LoadBearing: yes; Reference: Poteaux porteurs 1
Type - Pset_EnvironmentalImpactIndicators - Reference: Poteaux porteurs 1
Type - Pset_ReinforcementBarPitchOfColumn - Reference: Poteaux porteurs 1
Material: Finition Peinture - Blanc satiné
Qto_ColumnBaseQuantities - Length: 3.2711 m; CrossSectionArea: 0.623638 m2; OuterSurfaceArea: 10.8188 m2; GrossVolume: 0.189521 m3
Pset_EnvironmentalImpactIndicators - sets with these values: 2

# IfcColumn: Poteaux porteurs 110:Poteaux porteurs 1, Poteaux porteurs 110:Poteaux porteurs 1:656107
In: Demi-niveau
Type - PredefinedType: COLUMN; Material: Finition Peinture - Blanc satiné, <Unnamed>
Type - Pset_ColumnCommon - IsExternal: no; LoadBearing: yes; Reference: Poteaux porteurs 1
Type - Pset_EnvironmentalImpactIndicators - Reference: Poteaux porteurs 1
Type - Pset_ReinforcementBarPitchOfColumn - Reference: Poteaux porteurs 1
Material: Finition Peinture - Blanc satiné
Qto_ColumnBaseQuantities - Length: 0.929588 m; CrossSectionArea: 0.29649 m2; OuterSurfaceArea: 2.11977 m2; GrossVolume: 0.0256053 m3
Pset_ColumnCommon - Slope: 0 deg
Pset_EnvironmentalImpactIndicators - sets with these values: 2

# IfcColumn: Poteaux porteurs 11:Poteaux porteurs 1, Poteaux porteurs 11:Poteaux porteurs 1:357900
In: Demi-niveau
Type - PredefinedType: COLUMN; Material: <Unnamed>, Finition Peinture - Blanc satiné
Type - Pset_ColumnCommon - IsExternal: no; LoadBearing: yes; Reference: Poteaux porteurs 1
Type - Pset_EnvironmentalImpactIndicators - Reference: Poteaux porteurs 1
Type - Pset_ReinforcementBarPitchOfColumn - Reference: Poteaux porteurs 1
Material: Finition Peinture - Blanc satiné
Qto_ColumnBaseQuantities - Length: 3.2711 m; CrossSectionArea: 0.623638 m2; OuterSurfaceArea: 10.8188 m2; GrossVolume: 0.189521 m3
Pset_EnvironmentalImpactIndicators - sets with these values: 2

# IfcColumn: Poteaux porteurs 12:Poteaux porteurs 1, Poteaux porteurs 12:Poteaux porteurs 1:357921
In: Demi-niveau
Type - PredefinedType: COLUMN; Material: Finition Peinture - Blanc satiné, <Unnamed>
Type - Pset_ColumnCommon - IsExternal: no; LoadBearing: yes; Reference: Poteaux porteurs 1
Type - Pset_EnvironmentalImpactIndicators - Reference: Poteaux porteurs 1
Type - Pset_ReinforcementBarPitchOfColumn - Reference: Poteaux porteurs 1
Material: Finition Peinture - Blanc satiné
Qto_ColumnBaseQuantities - Length: 3.2711 m; CrossSectionArea: 0.623638 m2; OuterSurfaceArea: 10.8188 m2; GrossVolume: 0.189521 m3
Pset_EnvironmentalImpactIndicators - sets with these values: 2

# IfcColumn: Poteaux porteurs 13:Poteaux porteurs 1, Poteaux porteurs 13:Poteaux porteurs 1:357942
In: Demi-niveau
Type - PredefinedType: COLUMN; Material: <Unnamed>, Finition Peinture - Blanc satiné
Type - Pset_ColumnCommon - IsExternal: no; LoadBearing: yes; Reference: Poteaux porteurs 1
Type - Pset_EnvironmentalImpactIndicators - Reference: Poteaux porteurs 1
Type - Pset_ReinforcementBarPitchOfColumn - Reference: Poteaux porteurs 1
Material: Finition Peinture - Blanc satiné
Qto_ColumnBaseQuantities - Length: 3.2711 m; CrossSectionArea: 0.623638 m2; OuterSurfaceArea: 10.8188 m2; GrossVolume: 0.189521 m3
Pset_EnvironmentalImpactIndicators - sets with these values: 2

# IfcColumn: Poteaux porteurs 14:Poteaux porteurs 1, Poteaux porteurs 14:Poteaux porteurs 1:398773
In: Demi-niveau
Type - PredefinedType: COLUMN; Material: Finition Peinture - Blanc satiné, <Unnamed>
Type - Pset_ColumnCommon - IsExternal: no; LoadBearing: yes; Reference: Poteaux porteurs 1
Type - Pset_EnvironmentalImpactIndicators - Reference: Poteaux porteurs 1
Type - Pset_ReinforcementBarPitchOfColumn - Reference: Poteaux porteurs 1
Material: Finition Peinture - Blanc satiné
Qto_ColumnBaseQuantities - Length: 3.2711 m; CrossSectionArea: 0.623638 m2; OuterSurfaceArea: 10.8188 m2; GrossVolume: 0.189521 m3
Pset_EnvironmentalImpactIndicators - sets with these values: 2

# IfcColumn: Poteaux porteurs 15:Poteaux porteurs 1, Poteaux porteurs 15:Poteaux porteurs 1:398824
In: Demi-niveau
Type - PredefinedType: COLUMN; Material: Finition Peinture - Blanc satiné, <Unnamed>
Type - Pset_ColumnCommon - IsExternal: no; LoadBearing: yes; Reference: Poteaux porteurs 1
Type - Pset_EnvironmentalImpactIndicators - Reference: Poteaux porteurs 1
Type - Pset_ReinforcementBarPitchOfColumn - Reference: Poteaux porteurs 1
Material: Finition Peinture - Blanc satiné
Qto_ColumnBaseQuantities - Length: 3.2711 m; CrossSectionArea: 0.623638 m2; OuterSurfaceArea: 10.8188 m2; GrossVolume: 0.189521 m3
Pset_EnvironmentalImpactIndicators - sets with these values: 2

# IfcColumn: Poteaux porteurs 16:Poteaux porteurs 1, Poteaux porteurs 16:Poteaux porteurs 1:398909
In: Demi-niveau
Type - PredefinedType: COLUMN; Material: Finition Peinture - Blanc satiné, <Unnamed>
Type - Pset_ColumnCommon - IsExternal: no; LoadBearing: yes; Reference: Poteaux porteurs 1
Type - Pset_EnvironmentalImpactIndicators - Reference: Poteaux porteurs 1
Type - Pset_ReinforcementBarPitchOfColumn - Reference: Poteaux porteurs 1
Material: Finition Peinture - Blanc satiné
Qto_ColumnBaseQuantities - Length: 2.45153 m; CrossSectionArea: 0.623638 m2; OuterSurfaceArea: 8.10818 m2; GrossVolume: 0.142036 m3
Pset_EnvironmentalImpactIndicators - sets with these values: 2

# IfcColumn: Poteaux porteurs 17:Poteaux porteurs 1, Poteaux porteurs 17:Poteaux porteurs 1:398985
In: Demi-niveau
Type - PredefinedType: COLUMN; Material: <Unnamed>, Finition Peinture - Blanc satiné
Type - Pset_ColumnCommon - IsExternal: no; LoadBearing: yes; Reference: Poteaux porteurs 1
Type - Pset_EnvironmentalImpactIndicators - Reference: Poteaux porteurs 1
Type - Pset_ReinforcementBarPitchOfColumn - Reference: Poteaux porteurs 1
Material: Finition Peinture - Blanc satiné
Qto_ColumnBaseQuantities - Length: 2.45153 m; CrossSectionArea: 0.623638 m2; OuterSurfaceArea: 8.10818 m2; GrossVolume: 0.142036 m3
Pset_EnvironmentalImpactIndicators - sets with these values: 2

# IfcColumn: Poteaux porteurs 18:Poteaux porteurs 1, Poteaux porteurs 18:Poteaux porteurs 1:399006
In: Demi-niveau
Type - PredefinedType: COLUMN; Material: <Unnamed>, Finition Peinture - Blanc satiné
Type - Pset_ColumnCommon - IsExternal: no; LoadBearing: yes; Reference: Poteaux porteurs 1
Type - Pset_EnvironmentalImpactIndicators - Reference: Poteaux porteurs 1
Type - Pset_ReinforcementBarPitchOfColumn - Reference: Poteaux porteurs 1
Material: Finition Peinture - Blanc satiné
Qto_ColumnBaseQuantities - Length: 2.45153 m; CrossSectionArea: 0.623638 m2; OuterSurfaceArea: 8.10818 m2; GrossVolume: 0.142036 m3
Pset_EnvironmentalImpactIndicators - sets with these values: 2

# IfcColumn: Poteaux porteurs 19:Poteaux porteurs 1, Poteaux porteurs 19:Poteaux porteurs 1:399027
In: Demi-niveau
Type - PredefinedType: COLUMN; Material: <Unnamed>, Finition Peinture - Blanc satiné
Type - Pset_ColumnCommon - IsExternal: no; LoadBearing: yes; Reference: Poteaux porteurs 1
Type - Pset_EnvironmentalImpactIndicators - Reference: Poteaux porteurs 1
Type - Pset_ReinforcementBarPitchOfColumn - Reference: Poteaux porteurs 1
Material: Finition Peinture - Blanc satiné
Qto_ColumnBaseQuantities - Length: 2.45153 m; CrossSectionArea: 0.623638 m2; OuterSurfaceArea: 8.10818 m2; GrossVolume: 0.142036 m3
Pset_EnvironmentalImpactIndicators - sets with these values: 2

# IfcColumn: Poteaux porteurs 1:Poteaux porteurs 1, Poteaux porteurs 1:Poteaux porteurs 1:309158
In: Demi-niveau
Type - PredefinedType: COLUMN; Material: Finition Peinture - Blanc satiné, <Unnamed>
Type - Pset_ColumnCommon - IsExternal: no; LoadBearing: yes; Reference: Poteaux porteurs 1
Type - Pset_EnvironmentalImpactIndicators - Reference: Poteaux porteurs 1
Type - Pset_ReinforcementBarPitchOfColumn - Reference: Poteaux porteurs 1
Material: Finition Peinture - Blanc satiné
Qto_ColumnBaseQuantities - Length: 3.27113 m; CrossSectionArea: 0.623638 m2; OuterSurfaceArea: 10.8189 m2; GrossVolume: 0.189522 m3
Pset_EnvironmentalImpactIndicators - sets with these values: 2

# IfcColumn: Poteaux porteurs 20:Poteaux porteurs 20, Poteaux porteurs 20:Poteaux porteurs 20:406368
In: SS2
Type - PredefinedType: COLUMN; Material: <Unnamed>, Béton - Béton coulé sur place
Type - Pset_ColumnCommon - IsExternal: no; LoadBearing: yes; Reference: Poteaux porteurs 20
Type - Pset_EnvironmentalImpactIndicators - Reference: Poteaux porteurs 20
Type - Pset_ReinforcementBarPitchOfColumn - Reference: Poteaux porteurs 20
Material: Béton - Béton coulé sur place
Qto_ColumnBaseQuantities - Length: 2.34115 m; CrossSectionArea: 1.68686 m2; OuterSurfaceArea: 13.1422 m2; GrossVolume: 0.366893 m3
Pset_EnvironmentalImpactIndicators - sets with these values: 2

# IfcColumn: Poteaux porteurs 21:Poteaux porteurs 20, Poteaux porteurs 21:Poteaux porteurs 20:406536
In: SS2
Type - PredefinedType: COLUMN; Material: <Unnamed>, Béton - Béton coulé sur place
Type - Pset_ColumnCommon - IsExternal: no; LoadBearing: yes; Reference: Poteaux porteurs 20
Type - Pset_EnvironmentalImpactIndicators - Reference: Poteaux porteurs 20
Type - Pset_ReinforcementBarPitchOfColumn - Reference: Poteaux porteurs 20
Material: Béton - Béton coulé sur place
Qto_ColumnBaseQuantities - Length: 2.34115 m; CrossSectionArea: 1.68686 m2; OuterSurfaceArea: 13.1422 m2; GrossVolume: 0.366893 m3
Pset_EnvironmentalImpactIndicators - sets with these values: 2

# IfcColumn: Poteaux porteurs 22:Poteaux porteurs 22, Poteaux porteurs 22:Poteaux porteurs 22:495063
In: SS1
Type - PredefinedType: COLUMN; Material: <Unnamed>, Béton - Béton coulé sur place
Type - Pset_ColumnCommon - IsExternal: no; LoadBearing: yes; Reference: Poteaux porteurs 22
Type - Pset_EnvironmentalImpactIndicators - Reference: Poteaux porteurs 22
Type - Pset_ReinforcementBarPitchOfColumn - Reference: Poteaux porteurs 22
Material: Béton - Béton coulé sur place
Qto_ColumnBaseQuantities - Length: 2.13945 m; CrossSectionArea: 0.331322 m2; OuterSurfaceArea: 4.83519 m2; GrossVolume: 0.0658539 m3
Pset_EnvironmentalImpactIndicators - sets with these values: 2

# IfcColumn: Poteaux porteurs 23:Poteaux porteurs 1, Poteaux porteurs 23:Poteaux porteurs 1:506848
In: Niveau 0
Type - PredefinedType: COLUMN; Material: Finition Peinture - Blanc satiné, <Unnamed>
Type - Pset_ColumnCommon - IsExternal: no; LoadBearing: yes; Reference: Poteaux porteurs 1
Type - Pset_EnvironmentalImpactIndicators - Reference: Poteaux porteurs 1
Type - Pset_ReinforcementBarPitchOfColumn - Reference: Poteaux porteurs 1
Material: Finition Peinture - Blanc satiné
Qto_ColumnBaseQuantities - Length: 2.9009 m; CrossSectionArea: 0.623638 m2; OuterSurfaceArea: 9.59442 m2; GrossVolume: 0.168072 m3
Pset_EnvironmentalImpactIndicators - sets with these values: 2

# IfcColumn: Poteaux porteurs 24:Poteaux porteurs 1, Poteaux porteurs 24:Poteaux porteurs 1:506863
In: Niveau 0
Type - PredefinedType: COLUMN; Material: Finition Peinture - Blanc satiné, <Unnamed>
Type - Pset_ColumnCommon - IsExternal: no; LoadBearing: yes; Reference: Poteaux porteurs 1
Type - Pset_EnvironmentalImpactIndicators - Reference: Poteaux porteurs 1
Type - Pset_ReinforcementBarPitchOfColumn - Reference: Poteaux porteurs 1
Material: Finition Peinture - Blanc satiné
Qto_ColumnBaseQuantities - Length: 2.9009 m; CrossSectionArea: 0.623638 m2; OuterSurfaceArea: 9.59442 m2; GrossVolume: 0.168072 m3
Pset_EnvironmentalImpactIndicators - sets with these values: 2

# IfcColumn: Poteaux porteurs 25:Poteaux porteurs 1, Poteaux porteurs 25:Poteaux porteurs 1:506878
In: Niveau 0
Type - PredefinedType: COLUMN; Material: <Unnamed>, Finition Peinture - Blanc satiné
Type - Pset_ColumnCommon - IsExternal: no; LoadBearing: yes; Reference: Poteaux porteurs 1
Type - Pset_EnvironmentalImpactIndicators - Reference: Poteaux porteurs 1
Type - Pset_ReinforcementBarPitchOfColumn - Reference: Poteaux porteurs 1
Material: Finition Peinture - Blanc satiné
Qto_ColumnBaseQuantities - Length: 2.9009 m; CrossSectionArea: 0.623638 m2; OuterSurfaceArea: 9.59442 m2; GrossVolume: 0.168072 m3
Pset_EnvironmentalImpactIndicators - sets with these values: 2

# IfcColumn: Poteaux porteurs 26:Poteaux porteurs 1, Poteaux porteurs 26:Poteaux porteurs 1:506893
In: Niveau 0
Type - PredefinedType: COLUMN; Material: <Unnamed>, Finition Peinture - Blanc satiné
Type - Pset_ColumnCommon - IsExternal: no; LoadBearing: yes; Reference: Poteaux porteurs 1
Type - Pset_EnvironmentalImpactIndicators - Reference: Poteaux porteurs 1
Type - Pset_ReinforcementBarPitchOfColumn - Reference: Poteaux porteurs 1
Material: Finition Peinture - Blanc satiné
Qto_ColumnBaseQuantities - Length: 2.9009 m; CrossSectionArea: 0.623638 m2; OuterSurfaceArea: 9.59442 m2; GrossVolume: 0.168072 m3
Pset_EnvironmentalImpactIndicators - sets with these values: 2

# IfcColumn: Poteaux porteurs 27:Poteaux porteurs 1, Poteaux porteurs 27:Poteaux porteurs 1:506908
In: Niveau 0
Type - PredefinedType: COLUMN; Material: <Unnamed>, Finition Peinture - Blanc satiné
Type - Pset_ColumnCommon - IsExternal: no; LoadBearing: yes; Reference: Poteaux porteurs 1
Type - Pset_EnvironmentalImpactIndicators - Reference: Poteaux porteurs 1
Type - Pset_ReinforcementBarPitchOfColumn - Reference: Poteaux porteurs 1
Material: Finition Peinture - Blanc satiné
Qto_ColumnBaseQuantities - Length: 2.9009 m; CrossSectionArea: 0.623638 m2; OuterSurfaceArea: 9.59442 m2; GrossVolume: 0.168072 m3
Pset_EnvironmentalImpactIndicators - sets with these values: 2

# IfcColumn: Poteaux porteurs 28:Poteaux porteurs 1, Poteaux porteurs 28:Poteaux porteurs 1:506923
In: Niveau 0
Type - PredefinedType: COLUMN; Material: <Unnamed>, Finition Peinture - Blanc satiné
Type - Pset_ColumnCommon - IsExternal: no; LoadBearing: yes; Reference: Poteaux porteurs 1
Type - Pset_EnvironmentalImpactIndicators - Reference: Poteaux porteurs 1
Type - Pset_ReinforcementBarPitchOfColumn - Reference: Poteaux porteurs 1
Material: Finition Peinture - Blanc satiné
Qto_ColumnBaseQuantities - Length: 2.9009 m; CrossSectionArea: 0.623638 m2; OuterSurfaceArea: 9.59442 m2; GrossVolume: 0.168072 m3
Pset_EnvironmentalImpactIndicators - sets with these values: 2

# IfcColumn: Poteaux porteurs 29:Poteaux porteurs 1, Poteaux porteurs 29:Poteaux porteurs 1:506938
In: Niveau 0
Type - PredefinedType: COLUMN; Material: Finition Peinture - Blanc satiné, <Unnamed>
Type - Pset_ColumnCommon - IsExternal: no; LoadBearing: yes; Reference: Poteaux porteurs 1
Type - Pset_EnvironmentalImpactIndicators - Reference: Poteaux porteurs 1
Type - Pset_ReinforcementBarPitchOfColumn - Reference: Poteaux porteurs 1
Material: Finition Peinture - Blanc satiné
Qto_ColumnBaseQuantities - Length: 2.9009 m; CrossSectionArea: 0.623638 m2; OuterSurfaceArea: 9.59442 m2; GrossVolume: 0.168072 m3
Pset_EnvironmentalImpactIndicators - sets with these values: 2

# IfcColumn: Poteaux porteurs 2:Poteaux porteurs 1, Poteaux porteurs 2:Poteaux porteurs 1:357680
In: Demi-niveau
Type - PredefinedType: COLUMN; Material: <Unnamed>, Finition Peinture - Blanc satiné
Type - Pset_ColumnCommon - IsExternal: no; LoadBearing: yes; Reference: Poteaux porteurs 1
Type - Pset_EnvironmentalImpactIndicators - Reference: Poteaux porteurs 1
Type - Pset_ReinforcementBarPitchOfColumn - Reference: Poteaux porteurs 1
Material: Finition Peinture - Blanc satiné
Qto_ColumnBaseQuantities - Length: 3.2711 m; CrossSectionArea: 0.623638 m2; OuterSurfaceArea: 10.8188 m2; GrossVolume: 0.189521 m3
Pset_EnvironmentalImpactIndicators - sets with these values: 2

# IfcColumn: Poteaux porteurs 30:Poteaux porteurs 1, Poteaux porteurs 30:Poteaux porteurs 1:506953
In: Niveau 0
Type - PredefinedType: COLUMN; Material: <Unnamed>, Finition Peinture - Blanc satiné
Type - Pset_ColumnCommon - IsExternal: no; LoadBearing: yes; Reference: Poteaux porteurs 1
Type - Pset_EnvironmentalImpactIndicators - Reference: Poteaux porteurs 1
Type - Pset_ReinforcementBarPitchOfColumn - Reference: Poteaux porteurs 1
Material: Finition Peinture - Blanc satiné
Qto_ColumnBaseQuantities - Length: 2.9009 m; CrossSectionArea: 0.623638 m2; OuterSurfaceArea: 9.59442 m2; GrossVolume: 0.168072 m3
Pset_EnvironmentalImpactIndicators - sets with these values: 2

# IfcColumn: Poteaux porteurs 31:Poteaux porteurs 1, Poteaux porteurs 31:Poteaux porteurs 1:506968
In: Niveau 0
Type - PredefinedType: COLUMN; Material: <Unnamed>, Finition Peinture - Blanc satiné
Type - Pset_ColumnCommon - IsExternal: no; LoadBearing: yes; Reference: Poteaux porteurs 1
Type - Pset_EnvironmentalImpactIndicators - Reference: Poteaux porteurs 1
Type - Pset_ReinforcementBarPitchOfColumn - Reference: Poteaux porteurs 1
Material: Finition Peinture - Blanc satiné
Qto_ColumnBaseQuantities - Length: 2.9009 m; CrossSectionArea: 0.623638 m2; OuterSurfaceArea: 9.59442 m2; GrossVolume: 0.168072 m3
Pset_EnvironmentalImpactIndicators - sets with these values: 2

# IfcColumn: Poteaux porteurs 32:Poteaux porteurs 1, Poteaux porteurs 32:Poteaux porteurs 1:506983
In: Niveau 0
Type - PredefinedType: COLUMN; Material: <Unnamed>, Finition Peinture - Blanc satiné
Type - Pset_ColumnCommon - IsExternal: no; LoadBearing: yes; Reference: Poteaux porteurs 1
Type - Pset_EnvironmentalImpactIndicators - Reference: Poteaux porteurs 1
Type - Pset_ReinforcementBarPitchOfColumn - Reference: Poteaux porteurs 1
Material: Finition Peinture - Blanc satiné
Qto_ColumnBaseQuantities - Length: 2.9009 m; CrossSectionArea: 0.623638 m2; OuterSurfaceArea: 9.59442 m2; GrossVolume: 0.168072 m3
Pset_EnvironmentalImpactIndicators - sets with these values: 2

# IfcColumn: Poteaux porteurs 33:Poteaux porteurs 1, Poteaux porteurs 33:Poteaux porteurs 1:506998
In: Niveau 0
Type - PredefinedType: COLUMN; Material: Finition Peinture - Blanc satiné, <Unnamed>
Type - Pset_ColumnCommon - IsExternal: no; LoadBearing: yes; Reference: Poteaux porteurs 1
Type - Pset_EnvironmentalImpactIndicators - Reference: Poteaux porteurs 1
Type - Pset_ReinforcementBarPitchOfColumn - Reference: Poteaux porteurs 1
Material: Finition Peinture - Blanc satiné
Qto_ColumnBaseQuantities - Length: 2.9009 m; CrossSectionArea: 0.623638 m2; OuterSurfaceArea: 9.59442 m2; GrossVolume: 0.168072 m3
Pset_EnvironmentalImpactIndicators - sets with these values: 2

# IfcColumn: Poteaux porteurs 34:Poteaux porteurs 1, Poteaux porteurs 34:Poteaux porteurs 1:507478
In: Niveau 0
Type - PredefinedType: COLUMN; Material: <Unnamed>, Finition Peinture - Blanc satiné
Type - Pset_ColumnCommon - IsExternal: no; LoadBearing: yes; Reference: Poteaux porteurs 1
Type - Pset_EnvironmentalImpactIndicators - Reference: Poteaux porteurs 1
Type - Pset_ReinforcementBarPitchOfColumn - Reference: Poteaux porteurs 1
Material: Finition Peinture - Blanc satiné
Qto_ColumnBaseQuantities - Length: 2.9009 m; CrossSectionArea: 0.623638 m2; OuterSurfaceArea: 9.59442 m2; GrossVolume: 0.168072 m3
Pset_EnvironmentalImpactIndicators - sets with these values: 2

# IfcColumn: Poteaux porteurs 35:Poteaux porteurs 1, Poteaux porteurs 35:Poteaux porteurs 1:507499
In: Niveau 0
Type - PredefinedType: COLUMN; Material: Finition Peinture - Blanc satiné, <Unnamed>
Type - Pset_ColumnCommon - IsExternal: no; LoadBearing: yes; Reference: Poteaux porteurs 1
Type - Pset_EnvironmentalImpactIndicators - Reference: Poteaux porteurs 1
Type - Pset_ReinforcementBarPitchOfColumn - Reference: Poteaux porteurs 1
Material: Finition Peinture - Blanc satiné
Qto_ColumnBaseQuantities - Length: 2.9009 m; CrossSectionArea: 0.623638 m2; OuterSurfaceArea: 9.59442 m2; GrossVolume: 0.168072 m3
Pset_EnvironmentalImpactIndicators - sets with these values: 2

# IfcColumn: Poteaux porteurs 36:Poteaux porteurs 1, Poteaux porteurs 36:Poteaux porteurs 1:508338
In: Niveau 0
Type - PredefinedType: COLUMN; Material: Finition Peinture - Blanc satiné, <Unnamed>
Type - Pset_ColumnCommon - IsExternal: no; LoadBearing: yes; Reference: Poteaux porteurs 1
Type - Pset_EnvironmentalImpactIndicators - Reference: Poteaux porteurs 1
Type - Pset_ReinforcementBarPitchOfColumn - Reference: Poteaux porteurs 1
Material: Finition Peinture - Blanc satiné
Qto_ColumnBaseQuantities - Length: 2.90087 m; CrossSectionArea: 0.623638 m2; OuterSurfaceArea: 9.59434 m2; GrossVolume: 0.16807 m3
Pset_EnvironmentalImpactIndicators - sets with these values: 2

# IfcColumn: Poteaux porteurs 37:Poteaux porteurs 1, Poteaux porteurs 37:Poteaux porteurs 1:508601
In: Niveau 0
Type - PredefinedType: COLUMN; Material: Finition Peinture - Blanc satiné, <Unnamed>
Type - Pset_ColumnCommon - IsExternal: no; LoadBearing: yes; Reference: Poteaux porteurs 1
Type - Pset_EnvironmentalImpactIndicators - Reference: Poteaux porteurs 1
Type - Pset_ReinforcementBarPitchOfColumn - Reference: Poteaux porteurs 1
Material: Finition Peinture - Blanc satiné
Qto_ColumnBaseQuantities - Length: 2.90087 m; CrossSectionArea: 0.623638 m2; OuterSurfaceArea: 9.59434 m2; GrossVolume: 0.16807 m3
Pset_EnvironmentalImpactIndicators - sets with these values: 2

# IfcColumn: Poteaux porteurs 38:Poteaux porteurs 1, Poteaux porteurs 38:Poteaux porteurs 1:508655
In: Niveau 0
Type - PredefinedType: COLUMN; Material: <Unnamed>, Finition Peinture - Blanc satiné
Type - Pset_ColumnCommon - IsExternal: no; LoadBearing: yes; Reference: Poteaux porteurs 1
Type - Pset_EnvironmentalImpactIndicators - Reference: Poteaux porteurs 1
Type - Pset_ReinforcementBarPitchOfColumn - Reference: Poteaux porteurs 1
Material: Finition Peinture - Blanc satiné
Qto_ColumnBaseQuantities - Length: 2.90087 m; CrossSectionArea: 0.623638 m2; OuterSurfaceArea: 9.59434 m2; GrossVolume: 0.16807 m3
Pset_EnvironmentalImpactIndicators - sets with these values: 2

# IfcColumn: Poteaux porteurs 39:Poteaux porteurs 1, Poteaux porteurs 39:Poteaux porteurs 1:508674
In: Niveau 0
Type - PredefinedType: COLUMN; Material: Finition Peinture - Blanc satiné, <Unnamed>
Type - Pset_ColumnCommon - IsExternal: no; LoadBearing: yes; Reference: Poteaux porteurs 1
Type - Pset_EnvironmentalImpactIndicators - Reference: Poteaux porteurs 1
Type - Pset_ReinforcementBarPitchOfColumn - Reference: Poteaux porteurs 1
Material: Finition Peinture - Blanc satiné
Qto_ColumnBaseQuantities - Length: 2.90087 m; CrossSectionArea: 0.623638 m2; OuterSurfaceArea: 9.59434 m2; GrossVolume: 0.16807 m3
Pset_EnvironmentalImpactIndicators - sets with these values: 2

# IfcColumn: Poteaux porteurs 3:Poteaux porteurs 1, Poteaux porteurs 3:Poteaux porteurs 1:309352
In: Demi-niveau
Type - PredefinedType: COLUMN; Material: Finition Peinture - Blanc satiné, <Unnamed>
Type - Pset_ColumnCommon - IsExternal: no; LoadBearing: yes; Reference: Poteaux porteurs 1
Type - Pset_EnvironmentalImpactIndicators - Reference: Poteaux porteurs 1
Type - Pset_ReinforcementBarPitchOfColumn - Reference: Poteaux porteurs 1
Material: Finition Peinture - Blanc satiné
Qto_ColumnBaseQuantities - Length: 3.27113 m; CrossSectionArea: 0.623638 m2; OuterSurfaceArea: 10.8189 m2; GrossVolume: 0.189522 m3
Pset_EnvironmentalImpactIndicators - sets with these values: 2

# IfcColumn: Poteaux porteurs 40:Poteaux porteurs 1, Poteaux porteurs 40:Poteaux porteurs 1:508693
In: Niveau 0
Type - PredefinedType: COLUMN; Material: <Unnamed>, Finition Peinture - Blanc satiné
Type - Pset_ColumnCommon - IsExternal: no; LoadBearing: yes; Reference: Poteaux porteurs 1
Type - Pset_EnvironmentalImpactIndicators - Reference: Poteaux porteurs 1
Type - Pset_ReinforcementBarPitchOfColumn - Reference: Poteaux porteurs 1
Material: Finition Peinture - Blanc satiné
Qto_ColumnBaseQuantities - Length: 2.90087 m; CrossSectionArea: 0.623638 m2; OuterSurfaceArea: 9.59434 m2; GrossVolume: 0.16807 m3
Pset_EnvironmentalImpactIndicators - sets with these values: 2

# IfcColumn: Poteaux porteurs 41:Poteaux porteurs 1, Poteaux porteurs 41:Poteaux porteurs 1:508712
In: Niveau 0
Type - PredefinedType: COLUMN; Material: <Unnamed>, Finition Peinture - Blanc satiné
Type - Pset_ColumnCommon - IsExternal: no; LoadBearing: yes; Reference: Poteaux porteurs 1
Type - Pset_EnvironmentalImpactIndicators - Reference: Poteaux porteurs 1
Type - Pset_ReinforcementBarPitchOfColumn - Reference: Poteaux porteurs 1
Material: Finition Peinture - Blanc satiné
Qto_ColumnBaseQuantities - Length: 2.90087 m; CrossSectionArea: 0.623638 m2; OuterSurfaceArea: 9.59434 m2; GrossVolume: 0.16807 m3
Pset_EnvironmentalImpactIndicators - sets with these values: 2

# IfcColumn: Poteaux porteurs 42:Poteaux porteurs 1, Poteaux porteurs 42:Poteaux porteurs 1:508731
In: Niveau 0
Type - PredefinedType: COLUMN; Material: Finition Peinture - Blanc satiné, <Unnamed>
Type - Pset_ColumnCommon - IsExternal: no; LoadBearing: yes; Reference: Poteaux porteurs 1
Type - Pset_EnvironmentalImpactIndicators - Reference: Poteaux porteurs 1
Type - Pset_ReinforcementBarPitchOfColumn - Reference: Poteaux porteurs 1
Material: Finition Peinture - Blanc satiné
Qto_ColumnBaseQuantities - Length: 2.90087 m; CrossSectionArea: 0.623638 m2; OuterSurfaceArea: 9.59434 m2; GrossVolume: 0.16807 m3
Pset_EnvironmentalImpactIndicators - sets with these values: 2

# IfcColumn: Poteaux porteurs 43:Poteaux porteurs 1, Poteaux porteurs 43:Poteaux porteurs 1:508750
In: Niveau 0
Type - PredefinedType: COLUMN; Material: <Unnamed>, Finition Peinture - Blanc satiné
Type - Pset_ColumnCommon - IsExternal: no; LoadBearing: yes; Reference: Poteaux porteurs 1
Type - Pset_EnvironmentalImpactIndicators - Reference: Poteaux porteurs 1
Type - Pset_ReinforcementBarPitchOfColumn - Reference: Poteaux porteurs 1
Material: Finition Peinture - Blanc satiné
Qto_ColumnBaseQuantities - Length: 2.90087 m; CrossSectionArea: 0.623638 m2; OuterSurfaceArea: 9.59434 m2; GrossVolume: 0.16807 m3
Pset_EnvironmentalImpactIndicators - sets with these values: 2

# IfcColumn: Poteaux porteurs 44:Poteaux porteurs 1, Poteaux porteurs 44:Poteaux porteurs 1:508769
In: Niveau 0
Type - PredefinedType: COLUMN; Material: <Unnamed>, Finition Peinture - Blanc satiné
Type - Pset_ColumnCommon - IsExternal: no; LoadBearing: yes; Reference: Poteaux porteurs 1
Type - Pset_EnvironmentalImpactIndicators - Reference: Poteaux porteurs 1
Type - Pset_ReinforcementBarPitchOfColumn - Reference: Poteaux porteurs 1
Material: Finition Peinture - Blanc satiné
Qto_ColumnBaseQuantities - Length: 2.90087 m; CrossSectionArea: 0.623638 m2; OuterSurfaceArea: 9.59434 m2; GrossVolume: 0.16807 m3
Pset_EnvironmentalImpactIndicators - sets with these values: 2

# IfcColumn: Poteaux porteurs 45:Poteaux porteurs 1, Poteaux porteurs 45:Poteaux porteurs 1:508788
In: Niveau 0
Type - PredefinedType: COLUMN; Material: Finition Peinture - Blanc satiné, <Unnamed>
Type - Pset_ColumnCommon - IsExternal: no; LoadBearing: yes; Reference: Poteaux porteurs 1
Type - Pset_EnvironmentalImpactIndicators - Reference: Poteaux porteurs 1
Type - Pset_ReinforcementBarPitchOfColumn - Reference: Poteaux porteurs 1
Material: Finition Peinture - Blanc satiné
Qto_ColumnBaseQuantities - Length: 2.90087 m; CrossSectionArea: 0.623638 m2; OuterSurfaceArea: 9.59434 m2; GrossVolume: 0.16807 m3
Pset_EnvironmentalImpactIndicators - sets with these values: 2

# IfcColumn: Poteaux porteurs 46:Poteaux porteurs 1, Poteaux porteurs 46:Poteaux porteurs 1:508807
In: Niveau 0
Type - PredefinedType: COLUMN; Material: Finition Peinture - Blanc satiné, <Unnamed>
Type - Pset_ColumnCommon - IsExternal: no; LoadBearing: yes; Reference: Poteaux porteurs 1
Type - Pset_EnvironmentalImpactIndicators - Reference: Poteaux porteurs 1
Type - Pset_ReinforcementBarPitchOfColumn - Reference: Poteaux porteurs 1
Material: Finition Peinture - Blanc satiné
Qto_ColumnBaseQuantities - Length: 2.90087 m; CrossSectionArea: 0.623638 m2; OuterSurfaceArea: 9.59434 m2; GrossVolume: 0.16807 m3
Pset_EnvironmentalImpactIndicators - sets with these values: 2

# IfcColumn: Poteaux porteurs 47:Poteaux porteurs 1, Poteaux porteurs 47:Poteaux porteurs 1:508826
In: Niveau 0
Type - PredefinedType: COLUMN; Material: <Unnamed>, Finition Peinture - Blanc satiné
Type - Pset_ColumnCommon - IsExternal: no; LoadBearing: yes; Reference: Poteaux porteurs 1
Type - Pset_EnvironmentalImpactIndicators - Reference: Poteaux porteurs 1
Type - Pset_ReinforcementBarPitchOfColumn - Reference: Poteaux porteurs 1
Material: Finition Peinture - Blanc satiné
Qto_ColumnBaseQuantities - Length: 2.90087 m; CrossSectionArea: 0.623638 m2; OuterSurfaceArea: 9.59434 m2; GrossVolume: 0.16807 m3
Pset_EnvironmentalImpactIndicators - sets with these values: 2

# IfcColumn: Poteaux porteurs 48:Poteaux porteurs 1, Poteaux porteurs 48:Poteaux porteurs 1:508845
In: Niveau 0
Type - PredefinedType: COLUMN; Material: Finition Peinture - Blanc satiné, <Unnamed>
Type - Pset_ColumnCommon - IsExternal: no; LoadBearing: yes; Reference: Poteaux porteurs 1
Type - Pset_EnvironmentalImpactIndicators - Reference: Poteaux porteurs 1
Type - Pset_ReinforcementBarPitchOfColumn - Reference: Poteaux porteurs 1
Material: Finition Peinture - Blanc satiné
Qto_ColumnBaseQuantities - Length: 2.90087 m; CrossSectionArea: 0.623638 m2; OuterSurfaceArea: 9.59434 m2; GrossVolume: 0.16807 m3
Pset_EnvironmentalImpactIndicators - sets with these values: 2

# IfcColumn: Poteaux porteurs 49:Poteaux porteurs 1, Poteaux porteurs 49:Poteaux porteurs 1:508864
In: Niveau 0
Type - PredefinedType: COLUMN; Material: <Unnamed>, Finition Peinture - Blanc satiné
Type - Pset_ColumnCommon - IsExternal: no; LoadBearing: yes; Reference: Poteaux porteurs 1
Type - Pset_EnvironmentalImpactIndicators - Reference: Poteaux porteurs 1
Type - Pset_ReinforcementBarPitchOfColumn - Reference: Poteaux porteurs 1
Material: Finition Peinture - Blanc satiné
Qto_ColumnBaseQuantities - Length: 2.90087 m; CrossSectionArea: 0.623638 m2; OuterSurfaceArea: 9.59434 m2; GrossVolume: 0.16807 m3
Pset_EnvironmentalImpactIndicators - sets with these values: 2

# IfcColumn: Poteaux porteurs 4:Poteaux porteurs 1, Poteaux porteurs 4:Poteaux porteurs 1:357591
In: Demi-niveau
Type - PredefinedType: COLUMN; Material: Finition Peinture - Blanc satiné, <Unnamed>
Type - Pset_ColumnCommon - IsExternal: no; LoadBearing: yes; Reference: Poteaux porteurs 1
Type - Pset_EnvironmentalImpactIndicators - Reference: Poteaux porteurs 1
Type - Pset_ReinforcementBarPitchOfColumn - Reference: Poteaux porteurs 1
Material: Finition Peinture - Blanc satiné
Qto_ColumnBaseQuantities - Length: 3.2711 m; CrossSectionArea: 0.623638 m2; OuterSurfaceArea: 10.8188 m2; GrossVolume: 0.189521 m3
Pset_EnvironmentalImpactIndicators - sets with these values: 2

# IfcColumn: Poteaux porteurs 50:Poteaux porteurs 1, Poteaux porteurs 50:Poteaux porteurs 1:508883
In: Niveau 0
Type - PredefinedType: COLUMN; Material: Finition Peinture - Blanc satiné, <Unnamed>
Type - Pset_ColumnCommon - IsExternal: no; LoadBearing: yes; Reference: Poteaux porteurs 1
Type - Pset_EnvironmentalImpactIndicators - Reference: Poteaux porteurs 1
Type - Pset_ReinforcementBarPitchOfColumn - Reference: Poteaux porteurs 1
Material: Finition Peinture - Blanc satiné
Qto_ColumnBaseQuantities - Length: 2.90087 m; CrossSectionArea: 0.623638 m2; OuterSurfaceArea: 9.59434 m2; GrossVolume: 0.16807 m3
Pset_EnvironmentalImpactIndicators - sets with these values: 2

# IfcColumn: Poteaux porteurs 51:Poteaux porteurs 1, Poteaux porteurs 51:Poteaux porteurs 1:508902
In: Niveau 0
Type - PredefinedType: COLUMN; Material: <Unnamed>, Finition Peinture - Blanc satiné
Type - Pset_ColumnCommon - IsExternal: no; LoadBearing: yes; Reference: Poteaux porteurs 1
Type - Pset_EnvironmentalImpactIndicators - Reference: Poteaux porteurs 1
Type - Pset_ReinforcementBarPitchOfColumn - Reference: Poteaux porteurs 1
Material: Finition Peinture - Blanc satiné
Qto_ColumnBaseQuantities - Length: 2.90087 m; CrossSectionArea: 0.623638 m2; OuterSurfaceArea: 9.59434 m2; GrossVolume: 0.16807 m3
Pset_EnvironmentalImpactIndicators - sets with these values: 2

# IfcColumn: Poteaux porteurs 52:Poteaux porteurs 1, Poteaux porteurs 52:Poteaux porteurs 1:516546
In: Niveau 0
Type - PredefinedType: COLUMN; Material: Finition Peinture - Blanc satiné, <Unnamed>
Type - Pset_ColumnCommon - IsExternal: no; LoadBearing: yes; Reference: Poteaux porteurs 1
Type - Pset_EnvironmentalImpactIndicators - Reference: Poteaux porteurs 1
Type - Pset_ReinforcementBarPitchOfColumn - Reference: Poteaux porteurs 1
Material: Finition Peinture - Blanc satiné
Qto_ColumnBaseQuantities - Length: 3.988 m; CrossSectionArea: 0.623638 m2; OuterSurfaceArea: 13.1899 m2; GrossVolume: 0.231056 m3
Pset_EnvironmentalImpactIndicators - sets with these values: 2

# IfcColumn: Poteaux porteurs 53:Poteaux porteurs 1, Poteaux porteurs 53:Poteaux porteurs 1:516644
In: Niveau 0
Type - PredefinedType: COLUMN; Material: Finition Peinture - Blanc satiné, <Unnamed>
Type - Pset_ColumnCommon - IsExternal: no; LoadBearing: yes; Reference: Poteaux porteurs 1
Type - Pset_EnvironmentalImpactIndicators - Reference: Poteaux porteurs 1
Type - Pset_ReinforcementBarPitchOfColumn - Reference: Poteaux porteurs 1
Material: Finition Peinture - Blanc satiné
Qto_ColumnBaseQuantities - Length: 2.90087 m; CrossSectionArea: 0.623638 m2; OuterSurfaceArea: 9.59434 m2; GrossVolume: 0.16807 m3
Pset_EnvironmentalImpactIndicators - sets with these values: 2

# IfcColumn: Poteaux porteurs 54:Poteaux porteurs 1, Poteaux porteurs 54:Poteaux porteurs 1:516659
In: Niveau 0
Type - PredefinedType: COLUMN; Material: <Unnamed>, Finition Peinture - Blanc satiné
Type - Pset_ColumnCommon - IsExternal: no; LoadBearing: yes; Reference: Poteaux porteurs 1
Type - Pset_EnvironmentalImpactIndicators - Reference: Poteaux porteurs 1
Type - Pset_ReinforcementBarPitchOfColumn - Reference: Poteaux porteurs 1
Material: Finition Peinture - Blanc satiné
Qto_ColumnBaseQuantities - Length: 2.90087 m; CrossSectionArea: 0.623638 m2; OuterSurfaceArea: 9.59434 m2; GrossVolume: 0.16807 m3
Pset_EnvironmentalImpactIndicators - sets with these values: 2

# IfcColumn: Poteaux porteurs 55:Poteaux porteurs 1, Poteaux porteurs 55:Poteaux porteurs 1:516674
In: Niveau 0
Type - PredefinedType: COLUMN; Material: <Unnamed>, Finition Peinture - Blanc satiné
Type - Pset_ColumnCommon - IsExternal: no; LoadBearing: yes; Reference: Poteaux porteurs 1
Type - Pset_EnvironmentalImpactIndicators - Reference: Poteaux porteurs 1
Type - Pset_ReinforcementBarPitchOfColumn - Reference: Poteaux porteurs 1
Material: Finition Peinture - Blanc satiné
Qto_ColumnBaseQuantities - Length: 3.988 m; CrossSectionArea: 0.623638 m2; OuterSurfaceArea: 13.1899 m2; GrossVolume: 0.231056 m3
Pset_EnvironmentalImpactIndicators - sets with these values: 2

# IfcColumn: Poteaux porteurs 56:Poteaux porteurs 1, Poteaux porteurs 56:Poteaux porteurs 1:516689
In: Niveau 0
Type - PredefinedType: COLUMN; Material: Finition Peinture - Blanc satiné, <Unnamed>
Type - Pset_ColumnCommon - IsExternal: no; LoadBearing: yes; Reference: Poteaux porteurs 1
Type - Pset_EnvironmentalImpactIndicators - Reference: Poteaux porteurs 1
Type - Pset_ReinforcementBarPitchOfColumn - Reference: Poteaux porteurs 1
Material: Finition Peinture - Blanc satiné
Qto_ColumnBaseQuantities - Length: 3.988 m; CrossSectionArea: 0.623638 m2; OuterSurfaceArea: 13.1899 m2; GrossVolume: 0.231056 m3
Pset_EnvironmentalImpactIndicators - sets with these values: 2

# IfcColumn: Poteaux porteurs 57:Poteaux porteurs 1, Poteaux porteurs 57:Poteaux porteurs 1:516704
In: Niveau 0
Type - PredefinedType: COLUMN; Material: Finition Peinture - Blanc satiné, <Unnamed>
Type - Pset_ColumnCommon - IsExternal: no; LoadBearing: yes; Reference: Poteaux porteurs 1
Type - Pset_EnvironmentalImpactIndicators - Reference: Poteaux porteurs 1
Type - Pset_ReinforcementBarPitchOfColumn - Reference: Poteaux porteurs 1
Material: Finition Peinture - Blanc satiné
Qto_ColumnBaseQuantities - Length: 3.988 m; CrossSectionArea: 0.623638 m2; OuterSurfaceArea: 13.1899 m2; GrossVolume: 0.231056 m3
Pset_EnvironmentalImpactIndicators - sets with these values: 2

# IfcColumn: Poteaux porteurs 58:Poteaux porteurs 1, Poteaux porteurs 58:Poteaux porteurs 1:516761
In: Niveau 0
Type - PredefinedType: COLUMN; Material: <Unnamed>, Finition Peinture - Blanc satiné
Type - Pset_ColumnCommon - IsExternal: no; LoadBearing: yes; Reference: Poteaux porteurs 1
Type - Pset_EnvironmentalImpactIndicators - Reference: Poteaux porteurs 1
Type - Pset_ReinforcementBarPitchOfColumn - Reference: Poteaux porteurs 1
Material: Finition Peinture - Blanc satiné
Qto_ColumnBaseQuantities - Length: 2.90087 m; CrossSectionArea: 0.623638 m2; OuterSurfaceArea: 9.59434 m2; GrossVolume: 0.16807 m3
Pset_EnvironmentalImpactIndicators - sets with these values: 2

# IfcColumn: Poteaux porteurs 59:Poteaux porteurs 1, Poteaux porteurs 59:Poteaux porteurs 1:516812
In: Niveau 0
Type - PredefinedType: COLUMN; Material: Finition Peinture - Blanc satiné, <Unnamed>
Type - Pset_ColumnCommon - IsExternal: no; LoadBearing: yes; Reference: Poteaux porteurs 1
Type - Pset_EnvironmentalImpactIndicators - Reference: Poteaux porteurs 1
Type - Pset_ReinforcementBarPitchOfColumn - Reference: Poteaux porteurs 1
Material: Finition Peinture - Blanc satiné
Qto_ColumnBaseQuantities - Length: 2.90087 m; CrossSectionArea: 0.623638 m2; OuterSurfaceArea: 9.59434 m2; GrossVolume: 0.16807 m3
Pset_EnvironmentalImpactIndicators - sets with these values: 2

# IfcColumn: Poteaux porteurs 5:Poteaux porteurs 1, Poteaux porteurs 5:Poteaux porteurs 1:357795
In: Demi-niveau
Type - PredefinedType: COLUMN; Material: Finition Peinture - Blanc satiné, <Unnamed>
Type - Pset_ColumnCommon - IsExternal: no; LoadBearing: yes; Reference: Poteaux porteurs 1
Type - Pset_EnvironmentalImpactIndicators - Reference: Poteaux porteurs 1
Type - Pset_ReinforcementBarPitchOfColumn - Reference: Poteaux porteurs 1
Material: Finition Peinture - Blanc satiné
Qto_ColumnBaseQuantities - Length: 3.2711 m; CrossSectionArea: 0.623638 m2; OuterSurfaceArea: 10.8188 m2; GrossVolume: 0.189521 m3
Pset_EnvironmentalImpactIndicators - sets with these values: 2

# IfcColumn: Poteaux porteurs 60:Poteaux porteurs 1, Poteaux porteurs 60:Poteaux porteurs 1:516863
In: Niveau 0
Type - PredefinedType: COLUMN; Material: <Unnamed>, Finition Peinture - Blanc satiné
Type - Pset_ColumnCommon - IsExternal: no; LoadBearing: yes; Reference: Poteaux porteurs 1
Type - Pset_EnvironmentalImpactIndicators - Reference: Poteaux porteurs 1
Type - Pset_ReinforcementBarPitchOfColumn - Reference: Poteaux porteurs 1
Material: Finition Peinture - Blanc satiné
Qto_ColumnBaseQuantities - Length: 2.90087 m; CrossSectionArea: 0.623638 m2; OuterSurfaceArea: 9.59434 m2; GrossVolume: 0.16807 m3
Pset_EnvironmentalImpactIndicators - sets with these values: 2

# IfcColumn: Poteaux porteurs 61:Poteaux porteurs 1, Poteaux porteurs 61:Poteaux porteurs 1:517021
In: Niveau 0
Type - PredefinedType: COLUMN; Material: Finition Peinture - Blanc satiné, <Unnamed>
Type - Pset_ColumnCommon - IsExternal: no; LoadBearing: yes; Reference: Poteaux porteurs 1
Type - Pset_EnvironmentalImpactIndicators - Reference: Poteaux porteurs 1
Type - Pset_ReinforcementBarPitchOfColumn - Reference: Poteaux porteurs 1
Material: Finition Peinture - Blanc satiné
Qto_ColumnBaseQuantities - Length: 2.90087 m; CrossSectionArea: 0.623638 m2; OuterSurfaceArea: 9.59434 m2; GrossVolume: 0.16807 m3
Pset_EnvironmentalImpactIndicators - sets with these values: 2

# IfcColumn: Poteaux porteurs 62:Poteaux porteurs 1, Poteaux porteurs 62:Poteaux porteurs 1:517036
In: Niveau 0
Type - PredefinedType: COLUMN; Material: Finition Peinture - Blanc satiné, <Unnamed>
Type - Pset_ColumnCommon - IsExternal: no; LoadBearing: yes; Reference: Poteaux porteurs 1
Type - Pset_EnvironmentalImpactIndicators - Reference: Poteaux porteurs 1
Type - Pset_ReinforcementBarPitchOfColumn - Reference: Poteaux porteurs 1
Material: Finition Peinture - Blanc satiné
Qto_ColumnBaseQuantities - Length: 2.90087 m; CrossSectionArea: 0.623638 m2; OuterSurfaceArea: 9.59434 m2; GrossVolume: 0.16807 m3
Pset_EnvironmentalImpactIndicators - sets with these values: 2

# IfcColumn: Poteaux porteurs 63:Poteaux porteurs 1, Poteaux porteurs 63:Poteaux porteurs 1:517051
In: Niveau 0
Type - PredefinedType: COLUMN; Material: <Unnamed>, Finition Peinture - Blanc satiné
Type - Pset_ColumnCommon - IsExternal: no; LoadBearing: yes; Reference: Poteaux porteurs 1
Type - Pset_EnvironmentalImpactIndicators - Reference: Poteaux porteurs 1
Type - Pset_ReinforcementBarPitchOfColumn - Reference: Poteaux porteurs 1
Material: Finition Peinture - Blanc satiné
Qto_ColumnBaseQuantities - Length: 2.90087 m; CrossSectionArea: 0.623638 m2; OuterSurfaceArea: 9.59434 m2; GrossVolume: 0.16807 m3
Pset_EnvironmentalImpactIndicators - sets with these values: 2

# IfcColumn: Poteaux porteurs 64:Poteaux porteurs 1, Poteaux porteurs 64:Poteaux porteurs 1:517066
In: Niveau 0
Type - PredefinedType: COLUMN; Material: <Unnamed>, Finition Peinture - Blanc satiné
Type - Pset_ColumnCommon - IsExternal: no; LoadBearing: yes; Reference: Poteaux porteurs 1
Type - Pset_EnvironmentalImpactIndicators - Reference: Poteaux porteurs 1
Type - Pset_ReinforcementBarPitchOfColumn - Reference: Poteaux porteurs 1
Material: Finition Peinture - Blanc satiné
Qto_ColumnBaseQuantities - Length: 2.90087 m; CrossSectionArea: 0.623638 m2; OuterSurfaceArea: 9.59434 m2; GrossVolume: 0.16807 m3
Pset_EnvironmentalImpactIndicators - sets with these values: 2

# IfcColumn: Poteaux porteurs 65:Poteaux porteurs 1, Poteaux porteurs 65:Poteaux porteurs 1:517100
In: Niveau 0
Type - PredefinedType: COLUMN; Material: <Unnamed>, Finition Peinture - Blanc satiné
Type - Pset_ColumnCommon - IsExternal: no; LoadBearing: yes; Reference: Poteaux porteurs 1
Type - Pset_EnvironmentalImpactIndicators - Reference: Poteaux porteurs 1
Type - Pset_ReinforcementBarPitchOfColumn - Reference: Poteaux porteurs 1
Material: Finition Peinture - Blanc satiné
Qto_ColumnBaseQuantities - Length: 2.90087 m; CrossSectionArea: 0.623638 m2; OuterSurfaceArea: 9.59434 m2; GrossVolume: 0.16807 m3
Pset_EnvironmentalImpactIndicators - sets with these values: 2

# IfcColumn: Poteaux porteurs 66:Poteaux porteurs 1, Poteaux porteurs 66:Poteaux porteurs 1:517115
In: Niveau 0
Type - PredefinedType: COLUMN; Material: <Unnamed>, Finition Peinture - Blanc satiné
Type - Pset_ColumnCommon - IsExternal: no; LoadBearing: yes; Reference: Poteaux porteurs 1
Type - Pset_EnvironmentalImpactIndicators - Reference: Poteaux porteurs 1
Type - Pset_ReinforcementBarPitchOfColumn - Reference: Poteaux porteurs 1
Material: Finition Peinture - Blanc satiné
Qto_ColumnBaseQuantities - Length: 2.90087 m; CrossSectionArea: 0.623638 m2; OuterSurfaceArea: 9.59434 m2; GrossVolume: 0.16807 m3
Pset_EnvironmentalImpactIndicators - sets with these values: 2

# IfcColumn: Poteaux porteurs 67:Poteaux porteurs 1, Poteaux porteurs 67:Poteaux porteurs 1:517152
In: Niveau 0
Type - PredefinedType: COLUMN; Material: Finition Peinture - Blanc satiné, <Unnamed>
Type - Pset_ColumnCommon - IsExternal: no; LoadBearing: yes; Reference: Poteaux porteurs 1
Type - Pset_EnvironmentalImpactIndicators - Reference: Poteaux porteurs 1
Type - Pset_ReinforcementBarPitchOfColumn - Reference: Poteaux porteurs 1
Material: Finition Peinture - Blanc satiné
Qto_ColumnBaseQuantities - Length: 2.90087 m; CrossSectionArea: 0.623638 m2; OuterSurfaceArea: 9.59434 m2; GrossVolume: 0.16807 m3
Pset_EnvironmentalImpactIndicators - sets with these values: 2

# IfcColumn: Poteaux porteurs 68:Poteaux porteurs 1, Poteaux porteurs 68:Poteaux porteurs 1:517171
In: Niveau 0
Type - PredefinedType: COLUMN; Material: <Unnamed>, Finition Peinture - Blanc satiné
Type - Pset_ColumnCommon - IsExternal: no; LoadBearing: yes; Reference: Poteaux porteurs 1
Type - Pset_EnvironmentalImpactIndicators - Reference: Poteaux porteurs 1
Type - Pset_ReinforcementBarPitchOfColumn - Reference: Poteaux porteurs 1
Material: Finition Peinture - Blanc satiné
Qto_ColumnBaseQuantities - Length: 2.90087 m; CrossSectionArea: 0.623638 m2; OuterSurfaceArea: 9.59434 m2; GrossVolume: 0.16807 m3
Pset_EnvironmentalImpactIndicators - sets with these values: 2

# IfcColumn: Poteaux porteurs 69:Poteaux porteurs 1, Poteaux porteurs 69:Poteaux porteurs 1:517190
In: Niveau 0
Type - PredefinedType: COLUMN; Material: <Unnamed>, Finition Peinture - Blanc satiné
Type - Pset_ColumnCommon - IsExternal: no; LoadBearing: yes; Reference: Poteaux porteurs 1
Type - Pset_EnvironmentalImpactIndicators - Reference: Poteaux porteurs 1
Type - Pset_ReinforcementBarPitchOfColumn - Reference: Poteaux porteurs 1
Material: Finition Peinture - Blanc satiné
Qto_ColumnBaseQuantities - Length: 2.90087 m; CrossSectionArea: 0.623638 m2; OuterSurfaceArea: 9.59434 m2; GrossVolume: 0.16807 m3
Pset_EnvironmentalImpactIndicators - sets with these values: 2

# IfcColumn: Poteaux porteurs 6:Poteaux porteurs 1, Poteaux porteurs 6:Poteaux porteurs 1:357722
In: Demi-niveau
Type - PredefinedType: COLUMN; Material: <Unnamed>, Finition Peinture - Blanc satiné
Type - Pset_ColumnCommon - IsExternal: no; LoadBearing: yes; Reference: Poteaux porteurs 1
Type - Pset_EnvironmentalImpactIndicators - Reference: Poteaux porteurs 1
Type - Pset_ReinforcementBarPitchOfColumn - Reference: Poteaux porteurs 1
Material: Finition Peinture - Blanc satiné
Qto_ColumnBaseQuantities - Length: 3.2711 m; CrossSectionArea: 0.623638 m2; OuterSurfaceArea: 10.8188 m2; GrossVolume: 0.189521 m3
Pset_EnvironmentalImpactIndicators - sets with these values: 2

# IfcColumn: Poteaux porteurs 70:Poteaux porteurs 1, Poteaux porteurs 70:Poteaux porteurs 1:517209
In: Niveau 0
Type - PredefinedType: COLUMN; Material: <Unnamed>, Finition Peinture - Blanc satiné
Type - Pset_ColumnCommon - IsExternal: no; LoadBearing: yes; Reference: Poteaux porteurs 1
Type - Pset_EnvironmentalImpactIndicators - Reference: Poteaux porteurs 1
Type - Pset_ReinforcementBarPitchOfColumn - Reference: Poteaux porteurs 1
Material: Finition Peinture - Blanc satiné
Qto_ColumnBaseQuantities - Length: 2.90087 m; CrossSectionArea: 0.623638 m2; OuterSurfaceArea: 9.59434 m2; GrossVolume: 0.16807 m3
Pset_EnvironmentalImpactIndicators - sets with these values: 2

# IfcColumn: Poteaux porteurs 71:Poteaux porteurs 1, Poteaux porteurs 71:Poteaux porteurs 1:517228
In: Niveau 0
Type - PredefinedType: COLUMN; Material: Finition Peinture - Blanc satiné, <Unnamed>
Type - Pset_ColumnCommon - IsExternal: no; LoadBearing: yes; Reference: Poteaux porteurs 1
Type - Pset_EnvironmentalImpactIndicators - Reference: Poteaux porteurs 1
Type - Pset_ReinforcementBarPitchOfColumn - Reference: Poteaux porteurs 1
Material: Finition Peinture - Blanc satiné
Qto_ColumnBaseQuantities - Length: 2.90087 m; CrossSectionArea: 0.623638 m2; OuterSurfaceArea: 9.59434 m2; GrossVolume: 0.16807 m3
Pset_EnvironmentalImpactIndicators - sets with these values: 2

# IfcColumn: Poteaux porteurs 72:Poteaux porteurs 1, Poteaux porteurs 72:Poteaux porteurs 1:517247
In: Niveau 0
Type - PredefinedType: COLUMN; Material: <Unnamed>, Finition Peinture - Blanc satiné
Type - Pset_ColumnCommon - IsExternal: no; LoadBearing: yes; Reference: Poteaux porteurs 1
Type - Pset_EnvironmentalImpactIndicators - Reference: Poteaux porteurs 1
Type - Pset_ReinforcementBarPitchOfColumn - Reference: Poteaux porteurs 1
Material: Finition Peinture - Blanc satiné
Qto_ColumnBaseQuantities - Length: 2.90087 m; CrossSectionArea: 0.623638 m2; OuterSurfaceArea: 9.59434 m2; GrossVolume: 0.16807 m3
Pset_EnvironmentalImpactIndicators - sets with these values: 2

# IfcColumn: Poteaux porteurs 73:Poteaux porteurs 1, Poteaux porteurs 73:Poteaux porteurs 1:565329
In: Niveau 2
Type - PredefinedType: COLUMN; Material: Finition Peinture - Blanc satiné, <Unnamed>
Type - Pset_ColumnCommon - IsExternal: no; LoadBearing: yes; Reference: Poteaux porteurs 1
Type - Pset_EnvironmentalImpactIndicators - Reference: Poteaux porteurs 1
Type - Pset_ReinforcementBarPitchOfColumn - Reference: Poteaux porteurs 1
Material: Finition Peinture - Blanc satiné
Qto_ColumnBaseQuantities - Length: 2.747 m; CrossSectionArea: 0.484376 m2; OuterSurfaceArea: 8.11122 m2; GrossVolume: 0.123615 m3
Pset_EnvironmentalImpactIndicators - sets with these values: 2

# IfcColumn: Poteaux porteurs 74:Poteaux porteurs 1, Poteaux porteurs 74:Poteaux porteurs 1:565348
In: Niveau 2
Type - PredefinedType: COLUMN; Material: <Unnamed>, Finition Peinture - Blanc satiné
Type - Pset_ColumnCommon - IsExternal: no; LoadBearing: yes; Reference: Poteaux porteurs 1
Type - Pset_EnvironmentalImpactIndicators - Reference: Poteaux porteurs 1
Type - Pset_ReinforcementBarPitchOfColumn - Reference: Poteaux porteurs 1
Material: Finition Peinture - Blanc satiné
Qto_ColumnBaseQuantities - Length: 2.747 m; CrossSectionArea: 0.484376 m2; OuterSurfaceArea: 8.11122 m2; GrossVolume: 0.123615 m3
Pset_EnvironmentalImpactIndicators - sets with these values: 2

# IfcColumn: Poteaux porteurs 75:Poteaux porteurs 1, Poteaux porteurs 75:Poteaux porteurs 1:565367
In: Niveau 2
Type - PredefinedType: COLUMN; Material: Finition Peinture - Blanc satiné, <Unnamed>
Type - Pset_ColumnCommon - IsExternal: no; LoadBearing: yes; Reference: Poteaux porteurs 1
Type - Pset_EnvironmentalImpactIndicators - Reference: Poteaux porteurs 1
Type - Pset_ReinforcementBarPitchOfColumn - Reference: Poteaux porteurs 1
Material: Finition Peinture - Blanc satiné
Qto_ColumnBaseQuantities - Length: 2.747 m; CrossSectionArea: 0.484376 m2; OuterSurfaceArea: 8.11122 m2; GrossVolume: 0.123615 m3
Pset_EnvironmentalImpactIndicators - sets with these values: 2

# IfcColumn: Poteaux porteurs 76:Poteaux porteurs 1, Poteaux porteurs 76:Poteaux porteurs 1:565132
In: Niveau 2
Type - PredefinedType: COLUMN; Material: <Unnamed>, Finition Peinture - Blanc satiné
Type - Pset_ColumnCommon - IsExternal: no; LoadBearing: yes; Reference: Poteaux porteurs 1
Type - Pset_EnvironmentalImpactIndicators - Reference: Poteaux porteurs 1
Type - Pset_ReinforcementBarPitchOfColumn - Reference: Poteaux porteurs 1
Material: Finition Peinture - Blanc satiné
Qto_ColumnBaseQuantities - Length: 2.747 m; CrossSectionArea: 0.484376 m2; OuterSurfaceArea: 8.11122 m2; GrossVolume: 0.123615 m3
Pset_EnvironmentalImpactIndicators - sets with these values: 2

# IfcColumn: Poteaux porteurs 77:Poteaux porteurs 1, Poteaux porteurs 77:Poteaux porteurs 1:566482
In: Niveau 2
Type - PredefinedType: COLUMN; Material: <Unnamed>, Finition Peinture - Blanc satiné
Type - Pset_ColumnCommon - IsExternal: no; LoadBearing: yes; Reference: Poteaux porteurs 1
Type - Pset_EnvironmentalImpactIndicators - Reference: Poteaux porteurs 1
Type - Pset_ReinforcementBarPitchOfColumn - Reference: Poteaux porteurs 1
Material: Finition Peinture - Blanc satiné
Qto_ColumnBaseQuantities - Length: 2.712 m; CrossSectionArea: 0.484376 m2; OuterSurfaceArea: 8.00787 m2; GrossVolume: 0.12204 m3
Pset_EnvironmentalImpactIndicators - sets with these values: 2

# IfcColumn: Poteaux porteurs 78:Poteaux porteurs 1, Poteaux porteurs 78:Poteaux porteurs 1:566512
In: Niveau 2
Type - PredefinedType: COLUMN; Material: <Unnamed>, Finition Peinture - Blanc satiné
Type - Pset_ColumnCommon - IsExternal: no; LoadBearing: yes; Reference: Poteaux porteurs 1
Type - Pset_EnvironmentalImpactIndicators - Reference: Poteaux porteurs 1
Type - Pset_ReinforcementBarPitchOfColumn - Reference: Poteaux porteurs 1
Material: Finition Peinture - Blanc satiné
Qto_ColumnBaseQuantities - Length: 2.712 m; CrossSectionArea: 0.484376 m2; OuterSurfaceArea: 8.00787 m2; GrossVolume: 0.12204 m3
Pset_ColumnCommon - Slope: 0 deg
Pset_EnvironmentalImpactIndicators - sets with these values: 2

# IfcColumn: Poteaux porteurs 79:Poteaux porteurs 1, Poteaux porteurs 79:Poteaux porteurs 1:566529
In: Niveau 2
Type - PredefinedType: COLUMN; Material: <Unnamed>, Finition Peinture - Blanc satiné
Type - Pset_ColumnCommon - IsExternal: no; LoadBearing: yes; Reference: Poteaux porteurs 1
Type - Pset_EnvironmentalImpactIndicators - Reference: Poteaux porteurs 1
Type - Pset_ReinforcementBarPitchOfColumn - Reference: Poteaux porteurs 1
Material: Finition Peinture - Blanc satiné
Qto_ColumnBaseQuantities - Length: 2.712 m; CrossSectionArea: 0.484376 m2; OuterSurfaceArea: 8.00787 m2; GrossVolume: 0.12204 m3
Pset_ColumnCommon - Slope: 0 deg
Pset_EnvironmentalImpactIndicators - sets with these values: 2

# IfcColumn: Poteaux porteurs 7:Poteaux porteurs 1, Poteaux porteurs 7:Poteaux porteurs 1:357816
In: Demi-niveau
Type - PredefinedType: COLUMN; Material: Finition Peinture - Blanc satiné, <Unnamed>
Type - Pset_ColumnCommon - IsExternal: no; LoadBearing: yes; Reference: Poteaux porteurs 1
Type - Pset_EnvironmentalImpactIndicators - Reference: Poteaux porteurs 1
Type - Pset_ReinforcementBarPitchOfColumn - Reference: Poteaux porteurs 1
Material: Finition Peinture - Blanc satiné
Qto_ColumnBaseQuantities - Length: 3.2711 m; CrossSectionArea: 0.623638 m2; OuterSurfaceArea: 10.8188 m2; GrossVolume: 0.189521 m3
Pset_EnvironmentalImpactIndicators - sets with these values: 2

# IfcColumn: Poteaux porteurs 80:Poteaux porteurs 1, Poteaux porteurs 80:Poteaux porteurs 1:566580
In: Niveau 2
Type - PredefinedType: COLUMN; Material: Finition Peinture - Blanc satiné, <Unnamed>
Type - Pset_ColumnCommon - IsExternal: no; LoadBearing: yes; Reference: Poteaux porteurs 1
Type - Pset_EnvironmentalImpactIndicators - Reference: Poteaux porteurs 1
Type - Pset_ReinforcementBarPitchOfColumn - Reference: Poteaux porteurs 1
Material: Finition Peinture - Blanc satiné
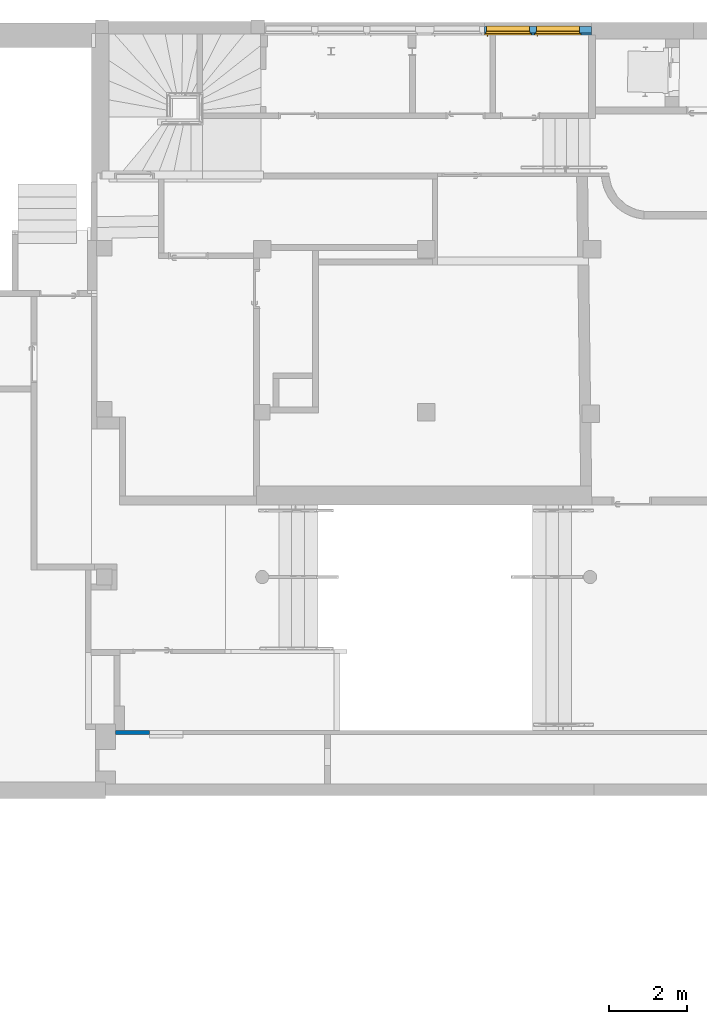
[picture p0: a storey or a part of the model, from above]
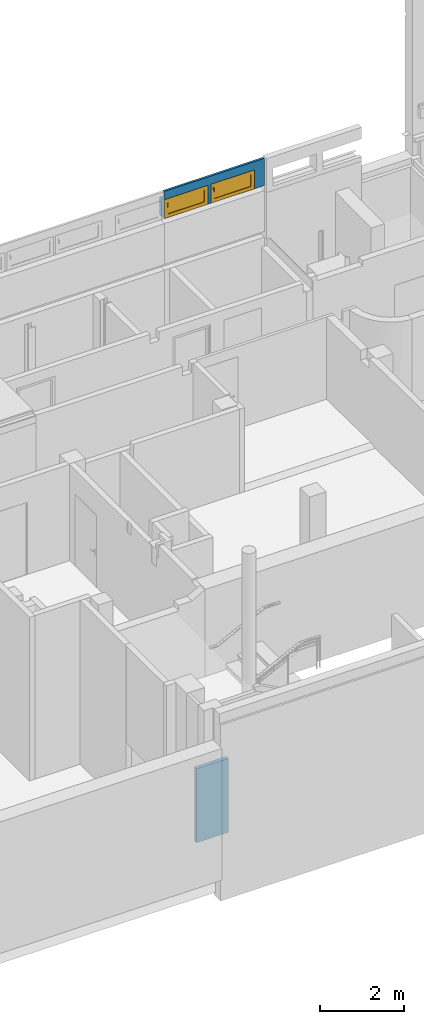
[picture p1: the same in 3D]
Properties of the parts of a building model (IFC4), part 3 of 8

# IfcColumn: Poteaux porteurs 80:Poteaux porteurs 1, Poteaux porteurs 80:Poteaux porteurs 1:566580
Qto_ColumnBaseQuantities - Length: 2.712 m; CrossSectionArea: 0.432709 m2; OuterSurfaceArea: 7.72315 m2; GrossVolume: 0.109022 m3
Pset_ColumnCommon - Slope: 0 deg
Pset_EnvironmentalImpactIndicators - sets with these values: 2

# IfcColumn: Poteaux porteurs 81:Poteaux porteurs 1, Poteaux porteurs 81:Poteaux porteurs 1:587212
In: Niveau 2
Type - PredefinedType: COLUMN; Material: Finition Peinture - Blanc satiné, <Unnamed>
Type - Pset_ColumnCommon - IsExternal: no; LoadBearing: yes; Reference: Poteaux porteurs 1
Type - Pset_EnvironmentalImpactIndicators - Reference: Poteaux porteurs 1
Type - Pset_ReinforcementBarPitchOfColumn - Reference: Poteaux porteurs 1
Material: Finition Peinture - Blanc satiné
Qto_ColumnBaseQuantities - Length: 2.71889 m; CrossSectionArea: 0.267362 m2; OuterSurfaceArea: 6.24233 m2; GrossVolume: 0.067534 m3
Pset_ColumnCommon - Slope: 0 deg
Pset_EnvironmentalImpactIndicators - sets with these values: 2

# IfcColumn: Poteaux porteurs 82:Poteaux porteurs 1, Poteaux porteurs 82:Poteaux porteurs 1:566897
In: Niveau 2
Type - PredefinedType: COLUMN; Material: <Unnamed>, Finition Peinture - Blanc satiné
Type - Pset_ColumnCommon - IsExternal: no; LoadBearing: yes; Reference: Poteaux porteurs 1
Type - Pset_EnvironmentalImpactIndicators - Reference: Poteaux porteurs 1
Type - Pset_ReinforcementBarPitchOfColumn - Reference: Poteaux porteurs 1
Material: Finition Peinture - Blanc satiné
Qto_ColumnBaseQuantities - Length: 2.71889 m; CrossSectionArea: 0.267362 m2; OuterSurfaceArea: 6.24233 m2; GrossVolume: 0.067534 m3
Pset_ColumnCommon - Slope: 0 deg
Pset_EnvironmentalImpactIndicators - sets with these values: 2

# IfcColumn: Poteaux porteurs 83:Poteaux porteurs 1, Poteaux porteurs 83:Poteaux porteurs 1:566952
In: Niveau 2
Type - PredefinedType: COLUMN; Material: <Unnamed>, Finition Peinture - Blanc satiné
Type - Pset_ColumnCommon - IsExternal: no; LoadBearing: yes; Reference: Poteaux porteurs 1
Type - Pset_EnvironmentalImpactIndicators - Reference: Poteaux porteurs 1
Type - Pset_ReinforcementBarPitchOfColumn - Reference: Poteaux porteurs 1
Material: Finition Peinture - Blanc satiné
Qto_ColumnBaseQuantities - Length: 2.71889 m; CrossSectionArea: 0.386934 m2; OuterSurfaceArea: 7.07852 m2; GrossVolume: 0.0977369 m3
Pset_EnvironmentalImpactIndicators - sets with these values: 2

# IfcColumn: Poteaux porteurs 84:Poteaux porteurs 1, Poteaux porteurs 84:Poteaux porteurs 1:567256
In: Niveau 2
Type - PredefinedType: COLUMN; Material: <Unnamed>, Finition Peinture - Blanc satiné
Type - Pset_ColumnCommon - IsExternal: no; LoadBearing: yes; Reference: Poteaux porteurs 1
Type - Pset_EnvironmentalImpactIndicators - Reference: Poteaux porteurs 1
Type - Pset_ReinforcementBarPitchOfColumn - Reference: Poteaux porteurs 1
Material: Finition Peinture - Blanc satiné
Qto_ColumnBaseQuantities - Length: 2.71889 m; CrossSectionArea: 0.386934 m2; OuterSurfaceArea: 7.07852 m2; GrossVolume: 0.0977369 m3
Pset_EnvironmentalImpactIndicators - sets with these values: 2

# IfcColumn: Poteaux porteurs 85:Poteaux porteurs 1, Poteaux porteurs 85:Poteaux porteurs 1:567273
In: Niveau 2
Type - PredefinedType: COLUMN; Material: <Unnamed>, Finition Peinture - Blanc satiné
Type - Pset_ColumnCommon - IsExternal: no; LoadBearing: yes; Reference: Poteaux porteurs 1
Type - Pset_EnvironmentalImpactIndicators - Reference: Poteaux porteurs 1
Type - Pset_ReinforcementBarPitchOfColumn - Reference: Poteaux porteurs 1
Material: Finition Peinture - Blanc satiné
Qto_ColumnBaseQuantities - Length: 2.71889 m; CrossSectionArea: 0.386934 m2; OuterSurfaceArea: 7.07852 m2; GrossVolume: 0.0977369 m3
Pset_EnvironmentalImpactIndicators - sets with these values: 2

# IfcColumn: Poteaux porteurs 86:Poteaux porteurs 1, Poteaux porteurs 86:Poteaux porteurs 1:567290
In: Niveau 2
Type - PredefinedType: COLUMN; Material: <Unnamed>, Finition Peinture - Blanc satiné
Type - Pset_ColumnCommon - IsExternal: no; LoadBearing: yes; Reference: Poteaux porteurs 1
Type - Pset_EnvironmentalImpactIndicators - Reference: Poteaux porteurs 1
Type - Pset_ReinforcementBarPitchOfColumn - Reference: Poteaux porteurs 1
Material: Finition Peinture - Blanc satiné
Qto_ColumnBaseQuantities - Length: 2.712 m; CrossSectionArea: 0.386934 m2; OuterSurfaceArea: 7.06057 m2; GrossVolume: 0.0974891 m3
Pset_EnvironmentalImpactIndicators - sets with these values: 2

# IfcColumn: Poteaux porteurs 87:Poteaux porteurs 1, Poteaux porteurs 87:Poteaux porteurs 1:567307
In: Niveau 2
Type - PredefinedType: COLUMN; Material: Finition Peinture - Blanc satiné, <Unnamed>
Type - Pset_ColumnCommon - IsExternal: no; LoadBearing: yes; Reference: Poteaux porteurs 1
Type - Pset_EnvironmentalImpactIndicators - Reference: Poteaux porteurs 1
Type - Pset_ReinforcementBarPitchOfColumn - Reference: Poteaux porteurs 1
Material: Finition Peinture - Blanc satiné
Qto_ColumnBaseQuantities - Length: 2.71889 m; CrossSectionArea: 0.386934 m2; OuterSurfaceArea: 7.07852 m2; GrossVolume: 0.0977369 m3
Pset_EnvironmentalImpactIndicators - sets with these values: 2

# IfcColumn: Poteaux porteurs 88:Poteaux porteurs 1, Poteaux porteurs 88:Poteaux porteurs 1:567324
In: Niveau 2
Type - PredefinedType: COLUMN; Material: <Unnamed>, Finition Peinture - Blanc satiné, Béton, coulé sur place
Type - Pset_ColumnCommon - IsExternal: no; LoadBearing: yes; Reference: Poteaux porteurs 1
Type - Pset_EnvironmentalImpactIndicators - Reference: Poteaux porteurs 1
Type - Pset_ReinforcementBarPitchOfColumn - Reference: Poteaux porteurs 1
Material: Béton, coulé sur place
Qto_ColumnBaseQuantities - Length: 2.71889 m; CrossSectionArea: 0.386934 m2; OuterSurfaceArea: 7.07852 m2; GrossVolume: 0.0977369 m3
Pset_EnvironmentalImpactIndicators - sets with these values: 2

# IfcColumn: Poteaux porteurs 89:Poteaux porteurs 1, Poteaux porteurs 89:Poteaux porteurs 1:569729
In: Niveau 2
Type - PredefinedType: COLUMN; Material: <Unnamed>, Finition Peinture - Blanc satiné
Type - Pset_ColumnCommon - IsExternal: no; LoadBearing: yes; Reference: Poteaux porteurs 1
Type - Pset_EnvironmentalImpactIndicators - Reference: Poteaux porteurs 1
Type - Pset_ReinforcementBarPitchOfColumn - Reference: Poteaux porteurs 1
Material: Finition Peinture - Blanc satiné
Qto_ColumnBaseQuantities - Length: 2.712 m; CrossSectionArea: 0.274139 m2; OuterSurfaceArea: 6.84931 m2; GrossVolume: 0.0690703 m3
Pset_ColumnCommon - Slope: 0 deg
Pset_EnvironmentalImpactIndicators - sets with these values: 2

# IfcColumn: Poteaux porteurs 8:Poteaux porteurs 1, Poteaux porteurs 8:Poteaux porteurs 1:357837
In: Demi-niveau
Type - PredefinedType: COLUMN; Material: Finition Peinture - Blanc satiné, <Unnamed>
Type - Pset_ColumnCommon - IsExternal: no; LoadBearing: yes; Reference: Poteaux porteurs 1
Type - Pset_EnvironmentalImpactIndicators - Reference: Poteaux porteurs 1
Type - Pset_ReinforcementBarPitchOfColumn - Reference: Poteaux porteurs 1
Material: Finition Peinture - Blanc satiné
Qto_ColumnBaseQuantities - Length: 3.2711 m; CrossSectionArea: 0.623638 m2; OuterSurfaceArea: 10.8188 m2; GrossVolume: 0.189521 m3
Pset_EnvironmentalImpactIndicators - sets with these values: 2

# IfcColumn: Poteaux porteurs 90:Poteaux porteurs 1, Poteaux porteurs 90:Poteaux porteurs 1:578811
In: Niveau 2
Type - PredefinedType: COLUMN; Material: Finition Peinture - Blanc satiné, <Unnamed>
Type - Pset_ColumnCommon - IsExternal: no; LoadBearing: yes; Reference: Poteaux porteurs 1
Type - Pset_EnvironmentalImpactIndicators - Reference: Poteaux porteurs 1
Type - Pset_ReinforcementBarPitchOfColumn - Reference: Poteaux porteurs 1
Material: Finition Peinture - Blanc satiné
Qto_ColumnBaseQuantities - Length: 2.747 m; CrossSectionArea: 0.284167 m2; OuterSurfaceArea: 6.99367 m2; GrossVolume: 0.0725208 m3
Pset_EnvironmentalImpactIndicators - sets with these values: 2

# IfcColumn: Poteaux porteurs 91:Poteaux porteurs 1, Poteaux porteurs 91:Poteaux porteurs 1:594776
In: Niveau 2
Type - PredefinedType: COLUMN; Material: Finition Peinture - Blanc satiné, <Unnamed>
Type - Pset_ColumnCommon - IsExternal: no; LoadBearing: yes; Reference: Poteaux porteurs 1
Type - Pset_EnvironmentalImpactIndicators - Reference: Poteaux porteurs 1
Type - Pset_ReinforcementBarPitchOfColumn - Reference: Poteaux porteurs 1
Material: Finition Peinture - Blanc satiné
Qto_ColumnBaseQuantities - Length: 2.74 m; CrossSectionArea: 0.386934 m2; OuterSurfaceArea: 7.13346 m2; GrossVolume: 0.0984956 m3
Pset_EnvironmentalImpactIndicators - sets with these values: 2

# IfcColumn: Poteaux porteurs 92:Poteaux porteurs 1, Poteaux porteurs 92:Poteaux porteurs 1:655174
In: Demi-niveau
Type - PredefinedType: COLUMN; Material: <Unnamed>, Finition Peinture - Blanc satiné
Type - Pset_ColumnCommon - IsExternal: no; LoadBearing: yes; Reference: Poteaux porteurs 1
Type - Pset_EnvironmentalImpactIndicators - Reference: Poteaux porteurs 1
Type - Pset_ReinforcementBarPitchOfColumn - Reference: Poteaux porteurs 1
Material: Finition Peinture - Blanc satiné
Qto_ColumnBaseQuantities - Length: 0.929588 m; CrossSectionArea: 0.329107 m2; OuterSurfaceArea: 2.2709 m2; GrossVolume: 0.0284222 m3
Pset_ColumnCommon - Slope: 0 deg
Pset_EnvironmentalImpactIndicators - sets with these values: 2

# IfcColumn: Poteaux porteurs 93:Poteaux porteurs 1, Poteaux porteurs 93:Poteaux porteurs 1:655220
In: Demi-niveau
Type - PredefinedType: COLUMN; Material: Finition Peinture - Blanc satiné, <Unnamed>
Type - Pset_ColumnCommon - IsExternal: no; LoadBearing: yes; Reference: Poteaux porteurs 1
Type - Pset_EnvironmentalImpactIndicators - Reference: Poteaux porteurs 1
Type - Pset_ReinforcementBarPitchOfColumn - Reference: Poteaux porteurs 1
Material: Finition Peinture - Blanc satiné
Qto_ColumnBaseQuantities - Length: 0.929588 m; CrossSectionArea: 0.329107 m2; OuterSurfaceArea: 2.2709 m2; GrossVolume: 0.0284222 m3
Pset_ColumnCommon - Slope: 0 deg
Pset_EnvironmentalImpactIndicators - sets with these values: 2

# IfcColumn: Poteaux porteurs 94:Poteaux porteurs 1, Poteaux porteurs 94:Poteaux porteurs 1:654562
In: Demi-niveau
Type - PredefinedType: COLUMN; Material: Finition Peinture - Blanc satiné, <Unnamed>
Type - Pset_ColumnCommon - IsExternal: no; LoadBearing: yes; Reference: Poteaux porteurs 1
Type - Pset_EnvironmentalImpactIndicators - Reference: Poteaux porteurs 1
Type - Pset_ReinforcementBarPitchOfColumn - Reference: Poteaux porteurs 1
Material: Finition Peinture - Blanc satiné
Qto_ColumnBaseQuantities - Length: 0.929588 m; CrossSectionArea: 0.329107 m2; OuterSurfaceArea: 2.2709 m2; GrossVolume: 0.0284222 m3
Pset_ColumnCommon - Slope: 0 deg
Pset_EnvironmentalImpactIndicators - sets with these values: 2

# IfcColumn: Poteaux porteurs 95:Poteaux porteurs 1, Poteaux porteurs 95:Poteaux porteurs 1:655237
In: Demi-niveau
Type - PredefinedType: COLUMN; Material: <Unnamed>, Finition Peinture - Blanc satiné
Type - Pset_ColumnCommon - IsExternal: no; LoadBearing: yes; Reference: Poteaux porteurs 1
Type - Pset_EnvironmentalImpactIndicators - Reference: Poteaux porteurs 1
Type - Pset_ReinforcementBarPitchOfColumn - Reference: Poteaux porteurs 1
Material: Finition Peinture - Blanc satiné
Qto_ColumnBaseQuantities - Length: 0.929588 m; CrossSectionArea: 0.329107 m2; OuterSurfaceArea: 2.2709 m2; GrossVolume: 0.0284222 m3
Pset_ColumnCommon - Slope: 0 deg
Pset_EnvironmentalImpactIndicators - sets with these values: 2

# IfcColumn: Poteaux porteurs 96:Poteaux porteurs 1, Poteaux porteurs 96:Poteaux porteurs 1:655290
In: Demi-niveau
Type - PredefinedType: COLUMN; Material: Finition Peinture - Blanc satiné, <Unnamed>
Type - Pset_ColumnCommon - IsExternal: no; LoadBearing: yes; Reference: Poteaux porteurs 1
Type - Pset_EnvironmentalImpactIndicators - Reference: Poteaux porteurs 1
Type - Pset_ReinforcementBarPitchOfColumn - Reference: Poteaux porteurs 1
Material: Finition Peinture - Blanc satiné
Qto_ColumnBaseQuantities - Length: 0.929588 m; CrossSectionArea: 0.329107 m2; OuterSurfaceArea: 2.2709 m2; GrossVolume: 0.0284222 m3
Pset_ColumnCommon - Slope: 0 deg
Pset_EnvironmentalImpactIndicators - sets with these values: 2

# IfcColumn: Poteaux porteurs 97:Poteaux porteurs 1, Poteaux porteurs 97:Poteaux porteurs 1:655307
In: Demi-niveau
Type - PredefinedType: COLUMN; Material: <Unnamed>, Finition Peinture - Blanc satiné
Type - Pset_ColumnCommon - IsExternal: no; LoadBearing: yes; Reference: Poteaux porteurs 1
Type - Pset_EnvironmentalImpactIndicators - Reference: Poteaux porteurs 1
Type - Pset_ReinforcementBarPitchOfColumn - Reference: Poteaux porteurs 1
Material: Finition Peinture - Blanc satiné
Qto_ColumnBaseQuantities - Length: 0.929588 m; CrossSectionArea: 0.329107 m2; OuterSurfaceArea: 2.2709 m2; GrossVolume: 0.0284222 m3
Pset_ColumnCommon - Slope: 0 deg
Pset_EnvironmentalImpactIndicators - sets with these values: 2

# IfcColumn: Poteaux porteurs 98:Poteaux porteurs 1, Poteaux porteurs 98:Poteaux porteurs 1:655324
In: Demi-niveau
Type - PredefinedType: COLUMN; Material: <Unnamed>, Finition Peinture - Blanc satiné
Type - Pset_ColumnCommon - IsExternal: no; LoadBearing: yes; Reference: Poteaux porteurs 1
Type - Pset_EnvironmentalImpactIndicators - Reference: Poteaux porteurs 1
Type - Pset_ReinforcementBarPitchOfColumn - Reference: Poteaux porteurs 1
Material: Finition Peinture - Blanc satiné
Qto_ColumnBaseQuantities - Length: 0.929588 m; CrossSectionArea: 0.329107 m2; OuterSurfaceArea: 2.2709 m2; GrossVolume: 0.0284222 m3
Pset_ColumnCommon - Slope: 0 deg
Pset_EnvironmentalImpactIndicators - sets with these values: 2

# IfcColumn: Poteaux porteurs 99:Poteaux porteurs 1, Poteaux porteurs 99:Poteaux porteurs 1:655341
In: Demi-niveau
Type - PredefinedType: COLUMN; Material: Finition Peinture - Blanc satiné, <Unnamed>
Type - Pset_ColumnCommon - IsExternal: no; LoadBearing: yes; Reference: Poteaux porteurs 1
Type - Pset_EnvironmentalImpactIndicators - Reference: Poteaux porteurs 1
Type - Pset_ReinforcementBarPitchOfColumn - Reference: Poteaux porteurs 1
Material: Finition Peinture - Blanc satiné
Qto_ColumnBaseQuantities - Length: 0.929588 m; CrossSectionArea: 0.329107 m2; OuterSurfaceArea: 2.2709 m2; GrossVolume: 0.0284222 m3
Pset_ColumnCommon - Slope: 0 deg
Pset_EnvironmentalImpactIndicators - sets with these values: 2

# IfcColumn: Poteaux porteurs 9:Poteaux porteurs 1, Poteaux porteurs 9:Poteaux porteurs 1:357858
In: Demi-niveau
Type - PredefinedType: COLUMN; Material: <Unnamed>, Finition Peinture - Blanc satiné
Type - Pset_ColumnCommon - IsExternal: no; LoadBearing: yes; Reference: Poteaux porteurs 1
Type - Pset_EnvironmentalImpactIndicators - Reference: Poteaux porteurs 1
Type - Pset_ReinforcementBarPitchOfColumn - Reference: Poteaux porteurs 1
Material: Finition Peinture - Blanc satiné
Qto_ColumnBaseQuantities - Length: 3.2711 m; CrossSectionArea: 0.623638 m2; OuterSurfaceArea: 10.8188 m2; GrossVolume: 0.189521 m3
Pset_EnvironmentalImpactIndicators - sets with these values: 2

# IfcColumn: poteau1:poteau, poteau1:poteau:593936
In: Niveau 2
Type - PredefinedType: COLUMN; Material: Acier
Type - Pset_ColumnCommon - IsExternal: no; Reference: poteau
Type - Pset_EnvironmentalImpactIndicators - Reference: poteau
Type - Pset_ReinforcementBarPitchOfColumn - Reference: poteau
Qto_ColumnBaseQuantities - Length: 0.3931 m; CrossSectionArea: 0.142084 m2; OuterSurfaceArea: 0.593261 m2; GrossVolume: 0.00518892 m3
Pset_EnvironmentalImpactIndicators - sets with these values: 2

# IfcColumn: poteau2:poteau, poteau2:poteau:593857
In: Niveau 2
Type - PredefinedType: COLUMN; Material: Acier
Type - Pset_ColumnCommon - IsExternal: no; Reference: poteau
Type - Pset_EnvironmentalImpactIndicators - Reference: poteau
Type - Pset_ReinforcementBarPitchOfColumn - Reference: poteau
Qto_ColumnBaseQuantities - Length: 0.3931 m; CrossSectionArea: 0.142084 m2; OuterSurfaceArea: 0.593261 m2; GrossVolume: 0.00518892 m3
Pset_EnvironmentalImpactIndicators - sets with these values: 2

# IfcColumn: poteau3:poteau, poteau3:poteau:593948
In: Niveau 2
Type - PredefinedType: COLUMN; Material: Acier
Type - Pset_ColumnCommon - IsExternal: no; Reference: poteau
Type - Pset_EnvironmentalImpactIndicators - Reference: poteau
Type - Pset_ReinforcementBarPitchOfColumn - Reference: poteau
Qto_ColumnBaseQuantities - Length: 0.3931 m; CrossSectionArea: 0.142084 m2; OuterSurfaceArea: 0.593261 m2; GrossVolume: 0.00518892 m3
Pset_EnvironmentalImpactIndicators - sets with these values: 2

# IfcColumn: poteau4:poteau, poteau4:poteau:593966
In: Niveau 2
Type - PredefinedType: COLUMN; Material: Acier
Type - Pset_ColumnCommon - IsExternal: no; Reference: poteau
Type - Pset_EnvironmentalImpactIndicators - Reference: poteau
Type - Pset_ReinforcementBarPitchOfColumn - Reference: poteau
Qto_ColumnBaseQuantities - Length: 0.3931 m; CrossSectionArea: 0.142084 m2; OuterSurfaceArea: 0.593261 m2; GrossVolume: 0.00518892 m3
Pset_EnvironmentalImpactIndicators - sets with these values: 2

# IfcColumn: poteau5:poteau, poteau5:poteau:593978
In: Niveau 2
Type - PredefinedType: COLUMN; Material: Acier
Type - Pset_ColumnCommon - IsExternal: no; Reference: poteau
Type - Pset_EnvironmentalImpactIndicators - Reference: poteau
Type - Pset_ReinforcementBarPitchOfColumn - Reference: poteau
Qto_ColumnBaseQuantities - Length: 0.3931 m; CrossSectionArea: 0.142084 m2; OuterSurfaceArea: 0.593261 m2; GrossVolume: 0.00518892 m3
Pset_EnvironmentalImpactIndicators - sets with these values: 2

# IfcColumn: poteau6:poteau, poteau6:poteau:594332
In: Niveau 2
Type - PredefinedType: COLUMN; Material: Acier
Type - Pset_ColumnCommon - IsExternal: no; Reference: poteau
Type - Pset_EnvironmentalImpactIndicators - Reference: poteau
Type - Pset_ReinforcementBarPitchOfColumn - Reference: poteau
Qto_ColumnBaseQuantities - Length: 0.3931 m; CrossSectionArea: 0.142084 m2; OuterSurfaceArea: 0.593261 m2; GrossVolume: 0.00518892 m3
Pset_EnvironmentalImpactIndicators - sets with these values: 2

# IfcColumn: poteau7:poteau, poteau7:poteau:594235
In: Niveau 2
Type - PredefinedType: COLUMN; Material: Acier
Type - Pset_ColumnCommon - IsExternal: no; Reference: poteau
Type - Pset_EnvironmentalImpactIndicators - Reference: poteau
Type - Pset_ReinforcementBarPitchOfColumn - Reference: poteau
Qto_ColumnBaseQuantities - Length: 0.3931 m; CrossSectionArea: 0.142084 m2; OuterSurfaceArea: 0.593261 m2; GrossVolume: 0.00518892 m3
Pset_EnvironmentalImpactIndicators - sets with these values: 2

# IfcColumn: poteau8:poteau, poteau8:poteau:594550
In: Niveau 2
Type - PredefinedType: COLUMN; Material: Acier
Type - Pset_ColumnCommon - IsExternal: no; Reference: poteau
Type - Pset_EnvironmentalImpactIndicators - Reference: poteau
Type - Pset_ReinforcementBarPitchOfColumn - Reference: poteau
Qto_ColumnBaseQuantities - Length: 0.3931 m; CrossSectionArea: 0.142084 m2; OuterSurfaceArea: 0.593261 m2; GrossVolume: 0.00518892 m3
Pset_EnvironmentalImpactIndicators - sets with these values: 2

# IfcColumn: poteau9:poteau, poteau9:poteau:594634
In: Niveau 2
Type - PredefinedType: COLUMN; Material: Acier
Type - Pset_ColumnCommon - IsExternal: no; Reference: poteau
Type - Pset_EnvironmentalImpactIndicators - Reference: poteau
Type - Pset_ReinforcementBarPitchOfColumn - Reference: poteau
Qto_ColumnBaseQuantities - Length: 0.3931 m; CrossSectionArea: 0.142084 m2; OuterSurfaceArea: 0.593261 m2; GrossVolume: 0.00518892 m3
Pset_EnvironmentalImpactIndicators - sets with these values: 2

# IfcColumn: poteau:poteau, poteau:poteau:593799
In: Niveau 2
Type - PredefinedType: COLUMN; Material: Acier
Type - Pset_ColumnCommon - IsExternal: no; Reference: poteau
Type - Pset_EnvironmentalImpactIndicators - Reference: poteau
Type - Pset_ReinforcementBarPitchOfColumn - Reference: poteau
Qto_ColumnBaseQuantities - Length: 0.3931 m; CrossSectionArea: 0.142084 m2; OuterSurfaceArea: 0.593261 m2; GrossVolume: 0.00518892 m3
Pset_EnvironmentalImpactIndicators - sets with these values: 2

# IfcCovering: Plafond de base:Plafond 600 mm x 1200 mm (96)
Type - PredefinedType: CEILING
Type - Pset_CoveringCommon - IsExternal: no; Reference: Plafond 600 mm x 1200 mm
Type - Pset_EnvironmentalImpactIndicators - Reference: Plafond 600 mm x 1200 mm
Material: Faux-plafond - Trame 600 x 600 0 m
Name (Plafond de base:Plafond 600 mm x 1200 mm:...) | In | NetArea (m2)
609574 | SS2 | 24.5941
609806 | SS2 | 4.6822
610008 | SS2 | 35.2582
610057 | SS2 | 9.73664
610065 | SS2 | 8.7761
615464 | SS2 | 9.55547
615607 | SS2 | 16.924
616175 | SS3 | 2.98556
616646 | SS1 | 82.9473
616709 | SS3 | 2.827
616716 | SS3 | 9.61772
616752 | SS3 | 13.6897
617006 | SS2 | 26.7487
617340 | SS1 | 76.9032
617843 | SS1 | 4.47896
618105 | SS3 | 2.78665
619370 | Demi-niveau | 2.90839
619498 | SS1 | 8.7994
619729 | SS1 | 2.46325
619801 | SS1 | 3.1639
619977 | SS1 | 0.950366
620240 | SS2 | 3.0732
620438 | SS1 | 6.5954
620477 | SS1 | 1.19903
620961 | SS1 | 3.51015
620970 | SS1 | 5.8442
621000 | SS1 | 1.85547
621254 | Niveau 0 | 2.93118
621264 | Niveau 0 | 21.8906
621380 | Niveau 0 | 156.005
621506 | Niveau 0 | 7.0396
621635 | Niveau 0 | 17.1512
621722 | Niveau 0 | 21.8906
621835 | Niveau 0 | 9.8005
621978 | Niveau 0 | 2.89264
621999 | Niveau 0 | 5.97025
622052 | Niveau 0 | 2.2939
622062 | Niveau 0 | 1.09963
622159 | Niveau 0 | 188.137
623545 | Niveau 1 | 11.164
624459 | Niveau 0 | 8.36466
624566 | Niveau 1 | 22.2264
624579 | Niveau 1 | 17.3854
624589 | Niveau 1 | 11.318
624611 | Niveau 1 | 17.2649
624623 | Niveau 1 | 14.9644
624636 | Niveau 1 | 18.5461
624646 | Niveau 1 | 20.7366
624662 | Niveau 1 | 27.0209
624694 | Niveau 1 | 4.88508
624706 | Niveau 1 | 8.74193
624715 | Niveau 1 | 15.7512
624726 | Niveau 1 | 9.99391
624738 | Niveau 1 | 2.3697
624748 | Niveau 1 | 7.64424
624766 | Niveau 1 | 3.12565
624776 | Niveau 1 | 3.86296
624786 | Niveau 1 | 2.39356
624794 | Niveau 1 | 5.19976
624802 | Niveau 1 | 2.33902
624810 | Niveau 1 | 1.25524
624820 | Niveau 1 | 4.9205
624840 | Niveau 1 | 35.7262
624879 | Niveau 1 | 1.03341
625714 | Niveau 1 | 11.6674
625858 | Niveau 1 | 2.77504
625980 | Niveau 1 | 2.43749
626066 | Niveau 1 | 64.049
626360 | Niveau 1 | 1.91829
626368 | Niveau 1 | 1.5296
626381 | Niveau 1 | 0.791369
626559 | Niveau 1 | 3.94873
626590 | Niveau 1 | 40.5031
626646 | Niveau 1 | 11.3962
626691 | Niveau 1 | 4.30687
626700 | Niveau 1 | 16.3144
627177 | Niveau 1 | 3.15087
627966 | Niveau 2 | 12.1245
627974 | Niveau 2 | 12.1191
627984 | Niveau 2 | 11.498
627992 | Niveau 2 | 3.11603
628000 | Niveau 2 | 9.88885
628141 | Niveau 2 | 3.58979
628193 | Niveau 2 | 12.6831
628265 | Niveau 2 | 3.70916
628296 | Niveau 2 | 18.5454
628753 | Niveau 2 | 34.3599
628916 | Niveau 2 | 4.56054
628990 | Niveau 2 | 15.0665
629070 | Niveau 2 | 14.8496
629081 | Niveau 2 | 16.9016
629141 | Niveau 2 | 2.37526
637102 | Niveau 1 | 10.8026
647123 | SS1 | 2.73674
648315 | Niveau 1 | 4.49798
648406 | Niveau 1 | 4.04233

# IfcCovering: Plafonds 1:Plafonds 1, Plafonds 1:Plafonds 1:616071
In: SS1
Type - Pset_CoveringCommon - IsExternal: no; Reference: Plafonds 1
Type - Pset_EnvironmentalImpactIndicators - Reference: Plafonds 1
Material: Acrylique, transparent
Qto_CoveringBaseQuantities - NetArea: 0.350212 m2

# IfcCovering: Plafonds 2:Plafonds 2, Plafonds 2:Plafonds 2:623260
In: Niveau 1
Type - Pset_CoveringCommon - IsExternal: no; Reference: Plafonds 2
Type - Pset_EnvironmentalImpactIndicators - Reference: Plafonds 2
Material: Faux-plafond - Trame 600 x 600
Qto_CoveringBaseQuantities - NetArea: 8.56242 m2

# IfcCurtainWall: Mur-rideau:Simple panneau (133)
Type - Pset_CurtainWallCommon - IsExternal: no; Reference: Simple panneau
Type - Pset_EnvironmentalImpactIndicators - Reference: Simple panneau
Name (Mur-rideau:Simple panneau:...) | In
302268 | Niveau 0 | Pset_EnvironmentalImpactIndicators - sets with these values: 2
304274 | Niveau 0 | Pset_EnvironmentalImpactIndicators - sets with these values: 2
312663 | Niveau 0
312978 | Niveau 0
313076 | Niveau 0
313256 | Niveau 0
313420 | Niveau 0
313541 | Niveau 0
313850 | Niveau 0
313923 | Niveau 0
314823 | Niveau 1
314960 | Niveau 1 | Pset_EnvironmentalImpactIndicators - sets with these values: 2
314965 | Niveau 1
314967 | Niveau 1
324081 | Niveau 0
326337 | Niveau 1
326475 | Niveau 0
336082 | Niveau 0
336118 | Niveau 0
340724 | Niveau 0
340790 | Niveau 0
340838 | Niveau 0
369555 | Niveau 0
369849 | Niveau 0
369872 | Niveau 0
369895 | Niveau 0
369918 | Niveau 0
369941 | Niveau 0
369964 | Niveau 0
369987 | Niveau 0
370010 | Niveau 0
370033 | Niveau 0
388348 | Niveau 0 | Pset_EnvironmentalImpactIndicators - sets with these values: 2
392092 | Niveau 0 | Pset_EnvironmentalImpactIndicators - sets with these values: 2
392159 | Niveau 0 | Pset_EnvironmentalImpactIndicators - sets with these values: 2
404726 | Niveau 0
404762 | Niveau 0
404855 | Niveau 0
406692 | SS2
413493 | SS2 | Pset_EnvironmentalImpactIndicators - sets with these values: 2
415285 | SS2 | Pset_EnvironmentalImpactIndicators - sets with these values: 2
415293 | SS2 | Pset_EnvironmentalImpactIndicators - sets with these values: 2
415300 | SS2 | Pset_EnvironmentalImpactIndicators - sets with these values: 2
415342 | SS2 | Pset_EnvironmentalImpactIndicators - sets with these values: 2
415722 | SS2 | Pset_EnvironmentalImpactIndicators - sets with these values: 2
415804 | SS2 | Pset_EnvironmentalImpactIndicators - sets with these values: 2
415952 | SS2 | Pset_EnvironmentalImpactIndicators - sets with these values: 2
511210 | Niveau 1
511220 | Niveau 1
511230 | Niveau 1
511240 | Niveau 1
511250 | Niveau 1
511260 | Niveau 1
511270 | Niveau 1
511280 | Niveau 1
511290 | Niveau 1
511300 | Niveau 1
511310 | Niveau 1
511320 | Niveau 1
511330 | Niveau 1
511340 | Niveau 1
512588 | Niveau 1
512765 | Niveau 1
512993 | Niveau 1
513009 | Niveau 1
513025 | Niveau 1
513041 | Niveau 1
513057 | Niveau 1
513073 | Niveau 1
513089 | Niveau 1
513105 | Niveau 1
513121 | Niveau 1
513137 | Niveau 1
513153 | Niveau 1
513169 | Niveau 1
513185 | Niveau 1
513201 | Niveau 1
513719 | Niveau 1
514541 | Niveau 1
518365 | Niveau 1
518436 | Niveau 1
518557 | Niveau 1
518575 | Niveau 1
518593 | Niveau 1
518611 | Niveau 1
518627 | Niveau 1
518645 | Niveau 1
518663 | Niveau 1
518681 | Niveau 1
518699 | Niveau 1
518717 | Niveau 1
518735 | Niveau 1
518753 | Niveau 1
518771 | Niveau 1
518825 | Niveau 1
519492 | Niveau 1
519531 | Niveau 1
519656 | Niveau 1
519717 | Niveau 1
519775 | Niveau 1
532431 | Niveau 1 | Pset_EnvironmentalImpactIndicators - sets with these values: 2
539587 | Niveau 1
540485 | Niveau 1
541267 | Niveau 1
541450 | Niveau 1
541485 | Niveau 1
554085 | Niveau 1
554580 | Niveau 1 | Pset_EnvironmentalImpactIndicators - sets with these values: 2
561132 | Niveau 2
561699 | Niveau 2
564061 | Niveau 2
570274 | Niveau 2
579227 | Niveau 2
579886 | Niveau 2
582839 | Niveau 2
583079 | Niveau 2
583095 | Niveau 2
583225 | Niveau 2
583402 | Niveau 2
583418 | Niveau 2
583434 | Niveau 2
589585 | Niveau 2 | Pset_EnvironmentalImpactIndicators - sets with these values: 2
590433 | Niveau 2
591098 | Niveau 2
591393 | Niveau 2
595772 | Niveau 2 | Pset_EnvironmentalImpactIndicators - sets with these values: 2
595975 | Niveau 2 | Pset_EnvironmentalImpactIndicators - sets with these values: 2
596341 | Niveau 2 | Pset_EnvironmentalImpactIndicators - sets with these values: 2
623680 | Niveau 1
623764 | Niveau 1
623770 | Niveau 1
623885 | Niveau 1
627728 | Niveau 2 | Pset_EnvironmentalImpactIndicators - sets with these values: 2

# IfcDoor: Coulissante vitrée1:Coulissante vitrée1, Coulissante vitrée1:Coulissante vitrée1:324082
In: Niveau 0
Type - PredefinedType: DOOR; Material: PVC - Blanc (2)
Type - Pset_DoorCommon - IsExternal: no; Reference: Coulissante vitrée1; ThermalTransmittance: 3.6886 kg/K/s3
Type - Pset_EnvironmentalImpactIndicators - Reference: Coulissante vitrée1
OverallHeight: 2.316 m; OverallWidth: 4.01796 m; Material: PVC - Blanc, Verre
Pset_DoorCommon - IsExternal: yes
Qto_DoorBaseQuantities - Height: 2.316 m; Width: 4.01796 m; Area: 9.3056 m2

# IfcDoor: Coulissante vitrée2:Coulissante vitrée2, Coulissante vitrée2:Coulissante vitrée2:326476
In: Niveau 0
Type - PredefinedType: DOOR; Material: PVC - Blanc (2)
Type - Pset_DoorCommon - IsExternal: no; Reference: Coulissante vitrée2; ThermalTransmittance: 3.6886 kg/K/s3
Type - Pset_EnvironmentalImpactIndicators - Reference: Coulissante vitrée2
OverallHeight: 2.316 m; OverallWidth: 4.48017 m; Material: PVC - Blanc, Verre
Pset_DoorCommon - IsExternal: yes
Qto_DoorBaseQuantities - Height: 2.316 m; Width: 4.47729 m; Area: 10.3694 m2

# IfcDoor: Double (R):1.10x2.04, Double (R):1.10x2.04:283497
In: Niveau 0
Type - PredefinedType: DOOR; OperationType: DOUBLE_DOOR_SINGLE_SWING; Material: Porte - Panneau, Porte - Cadre, Porte - Poignée
Type - Double (R):1.10x2.04:283497 - PanelOperation: SWINGING
Type - Pset_DoorCommon - IsExternal: no; Reference: 1.10x2.04; ThermalTransmittance: 2.1944 kg/K/s3
Type - Pset_EnvironmentalImpactIndicators - Reference: 1.10x2.04
OverallHeight: 2.075 m; OverallWidth: 1.17 m; Material: Porte - Poignée, Porte - Cadre, Porte - Panneau
Qto_DoorBaseQuantities - Height: 2.04 m; Width: 1.1 m; Area: 2.244 m2

# IfcDoor: Double (R):1.43m x 2.04m 2, Double (R):1.43m x 2.04m 2:548234
In: Niveau 1
Type - PredefinedType: DOOR; OperationType: DOUBLE_DOOR_SINGLE_SWING; Material: Porte - Poignée, Porte - Cadre, Porte - Panneau
Type - Double (R):1.43m x 2.04m 2:548234 - PanelOperation: SWINGING
Type - Pset_DoorCommon - IsExternal: no; Reference: 1.43m x 2.04m 2; ThermalTransmittance: 3.7021 kg/K/s3
Type - Pset_EnvironmentalImpactIndicators - Reference: 1.43m x 2.04m 2
OverallHeight: 2.075 m; OverallWidth: 1.52 m
Qto_DoorBaseQuantities - Height: 2.04 m; Width: 1.45 m; Area: 2.958 m2

# IfcDoor: Double (R):1.63m x 2.04m, Double (R):1.63m x 2.04m:457793
In: SS3
Type - PredefinedType: DOOR; OperationType: DOUBLE_DOOR_SINGLE_SWING; Material: Porte - Panneau, Porte - Poignée, Porte - Cadre
Type - Double (R):1.63m x 2.04m:457793 - PanelOperation: SWINGING
Type - Pset_DoorCommon - IsExternal: no; Reference: 1.63m x 2.04m; ThermalTransmittance: 3.7021 kg/K/s3
Type - Pset_EnvironmentalImpactIndicators - Reference: 1.63m x 2.04m
OverallHeight: 2.075 m; OverallWidth: 1.7 m; Material: Porte - Poignée, Porte - Cadre, Porte - Panneau
Qto_DoorBaseQuantities - Height: 2.04 m; Width: 1.63 m; Area: 3.3252 m2

# IfcDoor: Double (R):1.63m x 2.04m (2)
In: SS3
Type - PredefinedType: DOOR; OperationType: DOUBLE_DOOR_SINGLE_SWING; Material: Porte - Poignée, Porte - Panneau, Porte - Cadre
Type - Double (R):1.63m x 2.04m:457368 - PanelOperation: SWINGING
Type - Pset_DoorCommon - IsExternal: no; Reference: 1.63m x 2.04m; ThermalTransmittance: 3.7021 kg/K/s3
Type - Pset_EnvironmentalImpactIndicators - Reference: 1.63m x 2.04m
OverallHeight: 2.075 m; OverallWidth: 1.7 m; Material: Porte - Poignée, Porte - Cadre, Porte - Panneau
Qto_DoorBaseQuantities - Height: 2.04 m; Width: 1.63 m; Area: 3.3252 m2
Name (Double (R):1.63m x 2.04m:...)
457368
457454

# IfcDoor: Double (R):1.83X2.25, Double (R):1.83X2.25:457834
In: SS3
Type - PredefinedType: DOOR; OperationType: DOUBLE_DOOR_SINGLE_SWING; Material: Porte - Cadre, Porte - Poignée, Porte - Panneau
Type - Double (R):1.83X2.25:457834 - PanelOperation: SWINGING
Type - Pset_DoorCommon - IsExternal: no; Reference: 1.83X2.25; ThermalTransmittance: 3.7021 kg/K/s3
Type - Pset_EnvironmentalImpactIndicators - Reference: 1.83X2.25
OverallHeight: 2.285 m; OverallWidth: 1.9 m; Material: Porte - Poignée, Porte - Cadre, Porte - Panneau
Qto_DoorBaseQuantities - Height: 2.25 m; Width: 1.83 m; Area: 4.1175 m2

# IfcDoor: Double (R):1.93x2.05 pvc blanc, Double (R):1.93x2.05 pvc blanc:375545
In: Demi-niveau
Type - PredefinedType: DOOR; OperationType: DOUBLE_DOOR_SINGLE_SWING; Material: PVC - Blanc (3)
Type - Double (R):1.93x2.05 pvc blanc:375545 - PanelOperation: SWINGING
Type - Pset_DoorCommon - IsExternal: no; Reference: 1.93x2.05 pvc blanc; ThermalTransmittance: 3.7021 kg/K/s3
Type - Pset_EnvironmentalImpactIndicators - Reference: 1.93x2.05 pvc blanc
OverallHeight: 2.085 m; OverallWidth: 2 m; Material: PVC - Blanc
Qto_DoorBaseQuantities - Height: 2.05 m; Width: 1.93 m; Area: 3.9565 m2

# IfcDoor: Double vitrée1:Double vitrée1 (3)
Type - PredefinedType: DOOR; OperationType: SWING_FIXED_RIGHT; Material: PVC, souple (3)
Type - Pset_DoorCommon - IsExternal: no; Reference: Double vitrée1
Type - Pset_EnvironmentalImpactIndicators - Reference: Double vitrée1
Material: PVC, souple, Verre
Pset_DoorCommon - IsExternal: yes
Name (Double vitrée1:Double vitrée1:...) | In | OverallHeight (m) = Height (m) | OverallWidth (m) = Width (m) | Area (m2)
302269 | Niveau 0 | 2.13792 | 1.89707 | 4.05578
305705 | Niveau 0 | 2.13792 | 1.86691 | 3.99129
407822 | SS2 | 2.26 | 1.70999 | 3.86459

# IfcDoor: Int. Simple:0.53x1.85 (5)
In: Niveau 2
Type - PredefinedType: DOOR; Material: Bois - Cadre de porte (2), Bois - Panneau de porte, Finition Peinture - Blanc satiné
Type - Pset_DoorCommon - IsExternal: no; Reference: 0.53x1.85
Type - Pset_EnvironmentalImpactIndicators - Reference: 0.53x1.85
OverallHeight: 1.885 m; OverallWidth: 0.6 m; Material: Finition Peinture - Blanc satiné, Bois - Panneau de porte, Bois - Cadre de porte
Qto_DoorBaseQuantities - Height: 1.85 m; Width: 0.53 m; Area: 0.9805 m2
Name (Int. Simple:0.53x1.85:...)
599361 | Pset_EnvironmentalImpactIndicators - sets with these values: 2
599719
599817
599818
599819

# IfcDoor: Int. Simple:0.65x1.25, Int. Simple:0.65x1.25:375898
In: Demi-niveau
Type - PredefinedType: DOOR; Material: Bois - Panneau de porte, Bois - Cadre de porte (2), Finition Peinture - Blanc satiné
Type - Pset_DoorCommon - IsExternal: no; Reference: 0.65x1.25
Type - Pset_EnvironmentalImpactIndicators - Reference: 0.65x1.25
OverallHeight: 1.185 m; OverallWidth: 0.72 m; Material: Finition Peinture - Blanc satiné, Bois - Panneau de porte, Bois - Cadre de porte
Pset_DoorCommon - IsExternal: yes
Qto_DoorBaseQuantities - Height: 1.15 m; Width: 0.65 m; Area: 0.7475 m2

# IfcDoor: Int. Simple:0.70x2.04, Int. Simple:0.70x2.04:581741
In: Niveau 2
Type - PredefinedType: DOOR; Material: Bois - Panneau de porte, Finition Peinture - Blanc satiné, Bois - Cadre de porte (2)
Type - Pset_DoorCommon - IsExternal: no; Reference: 0.70x2.04
Type - Pset_EnvironmentalImpactIndicators - Reference: 0.70x2.04
OverallHeight: 2.075 m; OverallWidth: 0.77 m; Material: Finition Peinture - Blanc satiné, Bois - Panneau de porte, Bois - Cadre de porte
Pset_DoorCommon - IsExternal: yes
Qto_DoorBaseQuantities - Height: 2.04 m; Width: 0.7 m; Area: 1.428 m2

# IfcDoor: Int. Simple:0.83x1.87, Int. Simple:0.83x1.87:494050
In: SS1
Type - PredefinedType: DOOR; Material: Bois - Panneau de porte, Finition Peinture - Blanc satiné, Bois - Cadre de porte (2)
Type - Pset_DoorCommon - IsExternal: no; Reference: 0.83x1.87
Type - Pset_EnvironmentalImpactIndicators - Reference: 0.83x1.87
OverallHeight: 1.905 m; OverallWidth: 0.9 m; Material: Finition Peinture - Blanc satiné, Bois - Panneau de porte, Bois - Cadre de porte
Qto_DoorBaseQuantities - Height: 1.87 m; Width: 0.83 m; Area: 1.5521 m2

# IfcDoor: Int. Simple:0.93x1.87, Int. Simple:0.93x1.87:493698
In: SS1
Type - PredefinedType: DOOR; Material: Bois - Panneau de porte, Bois - Cadre de porte (2), Finition Peinture - Blanc satiné
Type - Pset_DoorCommon - IsExternal: no; Reference: 0.93x1.87
Type - Pset_EnvironmentalImpactIndicators - Reference: 0.93x1.87
OverallHeight: 1.905 m; OverallWidth: 1 m; Material: Finition Peinture - Blanc satiné, Bois - Panneau de porte, Bois - Cadre de porte
Pset_EnvironmentalImpactIndicators - sets with these values: 2
Qto_DoorBaseQuantities - Height: 1.87 m; Width: 0.93 m; Area: 1.7391 m2

# IfcDoor: Int. Simple:1.13x2.04 vitrée, Int. Simple:1.13x2.04 vitrée:293850
In: Niveau 0
Type - PredefinedType: DOOR; Material: Verre, PVC, souple (2), Finition Peinture - Blanc satiné
Type - Pset_DoorCommon - IsExternal: no; Reference: 1.13x2.04 vitrée
Type - Pset_EnvironmentalImpactIndicators - Reference: 1.13x2.04 vitrée
OverallHeight: 2.075 m; OverallWidth: 1.2 m; Material: Finition Peinture - Blanc satiné, Verre, PVC, souple
Qto_DoorBaseQuantities - Height: 2.04 m; Width: 1.13 m; Area: 2.3052 m2

# IfcDoor: Int. Simple:Ext 0.95X2.04 (2)
Type - PredefinedType: DOOR; Material: Acier inoxydable (4)
Type - Pset_DoorCommon - IsExternal: no; Reference: Ext 0.95X2.04
Type - Pset_EnvironmentalImpactIndicators - Reference: Ext 0.95X2.04
OverallHeight: 2.075 m; OverallWidth: 1.02 m; Material: Acier inoxydable
Pset_DoorCommon - IsExternal: yes
Qto_DoorBaseQuantities - Height: 2.04 m; Width: 0.95 m; Area: 1.938 m2
Name (Int. Simple:Ext 0.95X2.04:...) | In
418591 | SS2
421118 | SS3

# IfcDoor: Int. Simple:PP (0.63m x 1.85m), Int. Simple:PP (0.63m x 1.85m):493644
In: SS1
Type - PredefinedType: DOOR; Material: Bois - Cadre de porte (2), Finition Peinture - Blanc satiné, Bois - Panneau de porte
Type - Pset_DoorCommon - IsExternal: no; Reference: PP (0.63m x 1.85m)
Type - Pset_EnvironmentalImpactIndicators - Reference: PP (0.63m x 1.85m)
OverallHeight: 1.885 m; OverallWidth: 0.7 m; Material: Finition Peinture - Blanc satiné, Bois - Panneau de porte, Bois - Cadre de porte
Qto_DoorBaseQuantities - Height: 1.85 m; Width: 0.63 m; Area: 1.1655 m2

# IfcDoor: Int. Simple:PP (0.63m x 2.04m) (7)
Type - PredefinedType: DOOR; Material: Bois - Cadre de porte (2), Bois - Panneau de porte, Finition Peinture - Blanc satiné
Type - Pset_DoorCommon - IsExternal: no; Reference: PP (0.63m x 2.04m)
Type - Pset_EnvironmentalImpactIndicators - Reference: PP (0.63m x 2.04m)
OverallHeight: 2.075 m; OverallWidth: 0.7 m; Material: Finition Peinture - Blanc satiné, Bois - Panneau de porte, Bois - Cadre de porte
Qto_DoorBaseQuantities - Height: 2.04 m; Width: 0.63 m; Area: 1.2852 m2
Name (Int. Simple:PP (0.63m x 2.04m):...) | In
301925 | Niveau 0 | Pset_EnvironmentalImpactIndicators - sets with these values: 2
487359 | SS1
487400 | SS1
487722 | SS1
526662 | Niveau 1
529448 | Niveau 1
588964 | Niveau 2

# IfcDoor: Int. Simple:PP (0.63m x 2.04m) (2)
Type - PredefinedType: DOOR; Material: Bois - Cadre de porte (2), Finition Peinture - Blanc satiné, Bois - Panneau de porte
Type - Pset_DoorCommon - IsExternal: no; Reference: PP (0.63m x 2.04m)
Type - Pset_EnvironmentalImpactIndicators - Reference: PP (0.63m x 2.04m)
OverallHeight: 2.075 m; OverallWidth: 0.7 m; Material: Finition Peinture - Blanc satiné, Bois - Panneau de porte, Bois - Cadre de porte
Qto_DoorBaseQuantities - Height: 2.04 m; Width: 0.63 m; Area: 1.2852 m2
Name (Int. Simple:PP (0.63m x 2.04m):...) | In
543264 | Niveau 1
581530 | Niveau 2

# IfcDoor: Int. Simple:PP (0.63m x 2.04m) (2)
In: Niveau 1
Type - PredefinedType: DOOR; Material: Bois - Panneau de porte, Bois - Cadre de porte (2), Finition Peinture - Blanc satiné
Type - Pset_DoorCommon - IsExternal: no; Reference: PP (0.63m x 2.04m)
Type - Pset_EnvironmentalImpactIndicators - Reference: PP (0.63m x 2.04m)
OverallHeight: 2.075 m; OverallWidth: 0.7 m; Material: Finition Peinture - Blanc satiné, Bois - Panneau de porte, Bois - Cadre de porte
Qto_DoorBaseQuantities - Height: 2.04 m; Width: 0.63 m; Area: 1.2852 m2
Name (Int. Simple:PP (0.63m x 2.04m):...)
527076
531658

# IfcDoor: Int. Simple:PP (0.63m x 2.04m), Int. Simple:PP (0.63m x 2.04m):618625
In: SS1
Type - PredefinedType: DOOR; Material: Bois - Panneau de porte, Finition Peinture - Blanc satiné, Bois - Cadre de porte (2)
Type - Pset_DoorCommon - IsExternal: no; Reference: PP (0.63m x 2.04m)
Type - Pset_EnvironmentalImpactIndicators - Reference: PP (0.63m x 2.04m)
OverallHeight: 2.075 m; OverallWidth: 0.7 m; Material: Finition Peinture - Blanc satiné, Bois - Panneau de porte, Bois - Cadre de porte
Qto_DoorBaseQuantities - Height: 2.04 m; Width: 0.63 m; Area: 1.2852 m2

# IfcDoor: Int. Simple:PP (0.63m x 2.04m) (2)
Type - PredefinedType: DOOR; Material: Finition Peinture - Blanc satiné, Bois - Panneau de porte, Bois - Cadre de porte (2)
Type - Pset_DoorCommon - IsExternal: no; Reference: PP (0.63m x 2.04m)
Type - Pset_EnvironmentalImpactIndicators - Reference: PP (0.63m x 2.04m)
OverallHeight: 2.075 m; OverallWidth: 0.7 m; Material: Finition Peinture - Blanc satiné, Bois - Panneau de porte, Bois - Cadre de porte
Qto_DoorBaseQuantities - Height: 2.04 m; Width: 0.63 m; Area: 1.2852 m2
Name (Int. Simple:PP (0.63m x 2.04m):...) | In
290711 | Niveau 0
458630 | SS1

# IfcDoor: Int. Simple:PP (0.63m x 2.10m) (2)
Type - PredefinedType: DOOR; Material: Bois - Panneau de porte, Finition Peinture - Blanc satiné, Bois - Cadre de porte (2)
Type - Pset_DoorCommon - IsExternal: no; Reference: PP (0.63m x 2.10m)
Type - Pset_EnvironmentalImpactIndicators - Reference: PP (0.63m x 2.10m)
OverallHeight: 2.135 m; OverallWidth: 0.7 m; Material: Finition Peinture - Blanc satiné, Bois - Panneau de porte, Bois - Cadre de porte
Qto_DoorBaseQuantities - Height: 2.1 m; Width: 0.63 m; Area: 1.323 m2
Name (Int. Simple:PP (0.63m x 2.10m):...) | In
339820 | Niveau 0
548021 | Niveau 1

# IfcDoor: Int. Simple:PP (0.73m x 2.04m), Int. Simple:PP (0.73m x 2.04m):459388
In: SS1
Type - PredefinedType: DOOR; Material: Bois - Panneau de porte, Bois - Cadre de porte (2), Finition Peinture - Blanc satiné
Type - Pset_DoorCommon - IsExternal: no; Reference: PP (0.73m x 2.04m); ThermalTransmittance: 3.7021 kg/K/s3
Type - Pset_EnvironmentalImpactIndicators - Reference: PP (0.73m x 2.04m)
OverallHeight: 2.075 m; OverallWidth: 0.8 m; Material: Finition Peinture - Blanc satiné, Bois - Panneau de porte, Bois - Cadre de porte
Qto_DoorBaseQuantities - Height: 2.04 m; Width: 0.73 m; Area: 1.4892 m2

# IfcDoor: Int. Simple:PP (0.73m x 2.04m), Int. Simple:PP (0.73m x 2.04m):286400
In: Niveau 0
Type - PredefinedType: DOOR; Material: Finition Peinture - Blanc satiné, Bois - Panneau de porte, Bois - Cadre de porte (2)
Type - Pset_DoorCommon - IsExternal: no; Reference: PP (0.73m x 2.04m); ThermalTransmittance: 3.7021 kg/K/s3
Type - Pset_EnvironmentalImpactIndicators - Reference: PP (0.73m x 2.04m)
OverallHeight: 2.075 m; OverallWidth: 0.8 m; Material: Finition Peinture - Blanc satiné, Bois - Panneau de porte, Bois - Cadre de porte
Qto_DoorBaseQuantities - Height: 2.04 m; Width: 0.73 m; Area: 1.4892 m2

# IfcDoor: Int. Simple:PP (0.83m x 1.95, Int. Simple:PP (0.83m x 1.95:485297
In: SS1
Type - PredefinedType: DOOR; Material: Bois - Cadre de porte (2), Finition Peinture - Blanc satiné, Bois - Panneau de porte
Type - Pset_DoorCommon - IsExternal: no; Reference: PP (0.83m x 1.95
Type - Pset_EnvironmentalImpactIndicators - Reference: PP (0.83m x 1.95
OverallHeight: 1.985 m; OverallWidth: 0.9 m; Material: Finition Peinture - Blanc satiné, Bois - Panneau de porte, Bois - Cadre de porte
Qto_DoorBaseQuantities - Height: 1.95 m; Width: 0.83 m; Area: 1.6185 m2

# IfcDoor: Int. Simple:PP (0.83m x 1.95, Int. Simple:PP (0.83m x 1.95:485751
In: SS1
Type - PredefinedType: DOOR; Material: Bois - Panneau de porte, Bois - Cadre de porte (2), Finition Peinture - Blanc satiné
Type - Pset_DoorCommon - IsExternal: no; Reference: PP (0.83m x 1.95
Type - Pset_EnvironmentalImpactIndicators - Reference: PP (0.83m x 1.95
OverallHeight: 1.985 m; OverallWidth: 0.9 m; Material: Finition Peinture - Blanc satiné, Bois - Panneau de porte, Bois - Cadre de porte
Qto_DoorBaseQuantities - Height: 1.95 m; Width: 0.83 m; Area: 1.6185 m2

# IfcDoor: Int. Simple:PP (0.83m x 2.04m) (22)
Type - PredefinedType: DOOR; Material: Bois - Cadre de porte (2), Bois - Panneau de porte, Finition Peinture - Blanc satiné
Type - Pset_DoorCommon - IsExternal: no; Reference: PP (0.83m x 2.04m); ThermalTransmittance: 3.7021 kg/K/s3
Type - Pset_EnvironmentalImpactIndicators - Reference: PP (0.83m x 2.04m)
OverallHeight: 2.075 m; OverallWidth: 0.9 m; Material: Finition Peinture - Blanc satiné, Bois - Panneau de porte, Bois - Cadre de porte
Qto_DoorBaseQuantities - Height: 2.04 m; Width: 0.83 m; Area: 1.6932 m2
Name (Int. Simple:PP (0.83m x 2.04m):...) | In
281242 | Niveau 0 | Pset_EnvironmentalImpactIndicators - sets with these values: 2
290643 | Niveau 0
299277 | Niveau 0
487208 | SS1
527842 | Niveau 1
528255 | Niveau 1
528559 | Niveau 1
531480 | Niveau 1
531521 | Niveau 1
531594 | Niveau 1 | Pset_EnvironmentalImpactIndicators - sets with these values: 2
531909 | Niveau 1
532087 | Niveau 1
532131 | Niveau 1
532270 | Niveau 1
543814 | Niveau 1
546527 | Niveau 1
548188 | Niveau 1
548435 | Niveau 1
550759 | Niveau 1
550886 | Niveau 1 | Pset_EnvironmentalImpactIndicators - sets with these values: 2
568387 | Niveau 2
581246 | Niveau 2

# IfcDoor: Int. Simple:PP (0.83m x 2.04m) (2)
Type - PredefinedType: DOOR; Material: Bois - Cadre de porte (2), Finition Peinture - Blanc satiné, Bois - Panneau de porte
Type - Pset_DoorCommon - IsExternal: no; Reference: PP (0.83m x 2.04m); ThermalTransmittance: 3.7021 kg/K/s3
Type - Pset_EnvironmentalImpactIndicators - Reference: PP (0.83m x 2.04m)
OverallHeight: 2.075 m; OverallWidth: 0.9 m; Material: Finition Peinture - Blanc satiné, Bois - Panneau de porte, Bois - Cadre de porte
Qto_DoorBaseQuantities - Height: 2.04 m; Width: 0.83 m; Area: 1.6932 m2
Name (Int. Simple:PP (0.83m x 2.04m):...) | In
301212 | Niveau 0 | Pset_EnvironmentalImpactIndicators - sets with these values: 2
531554 | Niveau 1

# IfcDoor: Int. Simple:PP (0.83m x 2.04m) (7)
Type - PredefinedType: DOOR; Material: Bois - Panneau de porte, Bois - Cadre de porte (2), Finition Peinture - Blanc satiné
Type - Pset_DoorCommon - IsExternal: no; Reference: PP (0.83m x 2.04m); ThermalTransmittance: 3.7021 kg/K/s3
Type - Pset_EnvironmentalImpactIndicators - Reference: PP (0.83m x 2.04m)
OverallHeight: 2.075 m; OverallWidth: 0.9 m; Material: Finition Peinture - Blanc satiné, Bois - Panneau de porte, Bois - Cadre de porte
Qto_DoorBaseQuantities - Height: 2.04 m; Width: 0.83 m; Area: 1.6932 m2
Name (Int. Simple:PP (0.83m x 2.04m):...) | In
339741 | Niveau 0
476649 | SS1
487281 | SS1
490806 | SS1
528217 | Niveau 1
546734 | Niveau 1
552238 | Niveau 1

# IfcDoor: Int. Simple:PP (0.83m x 2.04m) (9)
Type - PredefinedType: DOOR; Material: Bois - Panneau de porte, Finition Peinture - Blanc satiné, Bois - Cadre de porte (2)
Type - Pset_DoorCommon - IsExternal: no; Reference: PP (0.83m x 2.04m); ThermalTransmittance: 3.7021 kg/K/s3
Type - Pset_EnvironmentalImpactIndicators - Reference: PP (0.83m x 2.04m)
OverallHeight: 2.075 m; OverallWidth: 0.9 m; Material: Finition Peinture - Blanc satiné, Bois - Panneau de porte, Bois - Cadre de porte
Qto_DoorBaseQuantities - Height: 2.04 m; Width: 0.83 m; Area: 1.6932 m2
Name (Int. Simple:PP (0.83m x 2.04m):...) | In
281249 | Niveau 0
492301 | SS1
492395 | SS1
527954 | Niveau 1
528909 | Niveau 1 | Pset_EnvironmentalImpactIndicators - sets with these values: 2
542970 | Niveau 1
543457 | Niveau 1
560499 | Niveau 2
579660 | Niveau 2

# IfcDoor: Int. Simple:PP0.93x2.04, Int. Simple:PP0.93x2.04:268812
In: Niveau 0
Type - PredefinedType: DOOR; Material: Bois - Cadre de porte (2), Bois - Panneau de porte, Finition Peinture - Blanc satiné
Type - Pset_DoorCommon - IsExternal: no; Reference: PP0.93x2.04
Type - Pset_EnvironmentalImpactIndicators - Reference: PP0.93x2.04
OverallHeight: 2.075 m; OverallWidth: 1 m; Material: Finition Peinture - Blanc satiné, Bois - Panneau de porte, Bois - Cadre de porte
Qto_DoorBaseQuantities - Height: 2.04 m; Width: 0.93 m; Area: 1.8972 m2

# IfcDoor: Int. Simple:PP0.93x2.04 (6)
Type - PredefinedType: DOOR; Material: Bois - Cadre de porte (2), Finition Peinture - Blanc satiné, Bois - Panneau de porte
Type - Pset_DoorCommon - IsExternal: no; Reference: PP0.93x2.04
Type - Pset_EnvironmentalImpactIndicators - Reference: PP0.93x2.04
OverallHeight: 2.075 m; OverallWidth: 1 m; Material: Finition Peinture - Blanc satiné, Bois - Panneau de porte, Bois - Cadre de porte
Qto_DoorBaseQuantities - Height: 2.04 m; Width: 0.93 m; Area: 1.8972 m2
Name (Int. Simple:PP0.93x2.04:...) | In
296976 | Niveau 0
435752 | SS3
447111 | SS3
491258 | SS1
491489 | SS3
560240 | Niveau 2

# IfcDoor: Int. Simple:PP0.93x2.04 (7)
Type - PredefinedType: DOOR; Material: Bois - Panneau de porte, Bois - Cadre de porte (2), Finition Peinture - Blanc satiné
Type - Pset_DoorCommon - IsExternal: no; Reference: PP0.93x2.04
Type - Pset_EnvironmentalImpactIndicators - Reference: PP0.93x2.04
OverallHeight: 2.075 m; OverallWidth: 1 m; Material: Finition Peinture - Blanc satiné, Bois - Panneau de porte, Bois - Cadre de porte
Qto_DoorBaseQuantities - Height: 2.04 m; Width: 0.93 m; Area: 1.8972 m2
Name (Int. Simple:PP0.93x2.04:...) | In
268018 | Niveau 0
269505 | Niveau 0
457500 | SS3
527735 | Niveau 1
544037 | Niveau 1
552062 | Niveau 1
582250 | Niveau 2

# IfcDoor: Int. Simple:PP0.93x2.04 (5)
Type - PredefinedType: DOOR; Material: Bois - Panneau de porte, Finition Peinture - Blanc satiné, Bois - Cadre de porte (2)
Type - Pset_DoorCommon - IsExternal: no; Reference: PP0.93x2.04
Type - Pset_EnvironmentalImpactIndicators - Reference: PP0.93x2.04
OverallHeight: 2.075 m; OverallWidth: 1 m; Material: Finition Peinture - Blanc satiné, Bois - Panneau de porte, Bois - Cadre de porte
Qto_DoorBaseQuantities - Height: 2.04 m; Width: 0.93 m; Area: 1.8972 m2
Name (Int. Simple:PP0.93x2.04:...) | In
453413 | SS3
457731 | SS3
549520 | Niveau 1
549891 | Niveau 1
549915 | Niveau 1

# IfcDoor: Int. Simple:PP0.93x2.04 (7)
Type - PredefinedType: DOOR; Material: Finition Peinture - Blanc satiné, Bois - Cadre de porte (2), Bois - Panneau de porte
Type - Pset_DoorCommon - IsExternal: no; Reference: PP0.93x2.04
Type - Pset_EnvironmentalImpactIndicators - Reference: PP0.93x2.04
OverallHeight: 2.075 m; OverallWidth: 1 m; Material: Finition Peinture - Blanc satiné, Bois - Panneau de porte, Bois - Cadre de porte
Qto_DoorBaseQuantities - Height: 2.04 m; Width: 0.93 m; Area: 1.8972 m2
Name (Int. Simple:PP0.93x2.04:...) | In
437693 | SS3
438859 | SS3
441441 | SS3
442730 | SS3
489815 | SS1
492427 | SS1
549853 | Niveau 1

# IfcDoor: Int. Simple:PP0.93x2.10, Int. Simple:PP0.93x2.10:445601
In: SS3
Type - PredefinedType: DOOR; Material: Finition Peinture - Blanc satiné, Bois - Cadre de porte (2), Bois - Panneau de porte
Type - Pset_DoorCommon - IsExternal: no; Reference: PP0.93x2.10
Type - Pset_EnvironmentalImpactIndicators - Reference: PP0.93x2.10
OverallHeight: 2.135 m; OverallWidth: 1 m; Material: Finition Peinture - Blanc satiné, Bois - Panneau de porte, Bois - Cadre de porte
Qto_DoorBaseQuantities - Height: 2.1 m; Width: 0.93 m; Area: 1.953 m2

# IfcDoor: Int. Simple:PP0.95x2.04 2, Int. Simple:PP0.95x2.04 2:420238
In: SS3
Type - PredefinedType: DOOR; Material: Bois - Cadre de porte (2), Bois - Panneau de porte, Finition Peinture - Blanc satiné
Type - Pset_DoorCommon - IsExternal: no; Reference: PP0.95x2.04 2
Type - Pset_EnvironmentalImpactIndicators - Reference: PP0.95x2.04 2
OverallHeight: 2.075 m; OverallWidth: 1.02 m; Material: Finition Peinture - Blanc satiné, Bois - Panneau de porte, Bois - Cadre de porte
Qto_DoorBaseQuantities - Height: 2.04 m; Width: 0.95 m; Area: 1.938 m2

# IfcDoor: Int. Simple:PP0.95x2.04 2 (3)
In: SS3
Type - PredefinedType: DOOR; Material: Bois - Cadre de porte (2), Finition Peinture - Blanc satiné, Bois - Panneau de porte
Type - Pset_DoorCommon - IsExternal: no; Reference: PP0.95x2.04 2
Type - Pset_EnvironmentalImpactIndicators - Reference: PP0.95x2.04 2
OverallHeight: 2.075 m; OverallWidth: 1.02 m; Material: Finition Peinture - Blanc satiné, Bois - Panneau de porte, Bois - Cadre de porte
Qto_DoorBaseQuantities - Height: 2.04 m; Width: 0.95 m; Area: 1.938 m2
Name (Int. Simple:PP0.95x2.04 2:...)
420991
432642
441158

# IfcDoor: Int. Tierce:1.33X1.96, Int. Tierce:1.33X1.96:601236
In: Niveau 2
Type - PredefinedType: DOOR; OperationType: DOUBLE_DOOR_SINGLE_SWING; Material: PVC - Blanc (3), Verre
Type - Int. Tierce:1.33X1.96:601236 - PanelOperation: SWINGING
Type - Pset_DoorCommon - IsExternal: no; Reference: 1.33X1.96; ThermalTransmittance: 5.5617 kg/K/s3
Type - Pset_EnvironmentalImpactIndicators - Reference: 1.33X1.96
OverallHeight: 2 m; OverallWidth: 1.4 m; Material: PVC - Blanc, Verre
Qto_DoorBaseQuantities - Height: 1.965 m; Width: 1.33 m; Area: 2.61345 m2

# IfcDoor: Mur mobile:Mur mobile (2)
In: Niveau 0
Type - PredefinedType: DOOR; Material: Aluminium, Porte - Panneau, Finition Peinture - Blanc satiné
Type - Pset_DoorCommon - IsExternal: no; Reference: Mur mobile
Type - Pset_EnvironmentalImpactIndicators - Reference: Mur mobile
OverallHeight: 2.875 m; OverallWidth: 8.15 m; Material: Finition Peinture - Blanc satiné, Bois - Panneau de porte, Aluminium, Porte - Panneau
Qto_DoorBaseQuantities - Height: 2.8 m; Width: 8 m; Area: 22.4 m2
Name (Mur mobile:Mur mobile:...)
378760
378873

# IfcDoor: PVC Panneau Vitré :0.73m x 2.24, PVC Panneau Vitré :0.73m x 2.24:416178
In: SS2
Type - PredefinedType: DOOR; OperationType: SINGLE_SWING_LEFT; Material: PVC - Blanc (3)
Type - PVC Panneau Vitré :0.73m x 2.24:416178 - PanelOperation: SWINGING
Type - Pset_DoorCommon - IsExternal: no; Reference: 0.73m x 2.24; ThermalTransmittance: 5.5617 kg/K/s3
Type - Pset_EnvironmentalImpactIndicators - Reference: 0.73m x 2.24
OverallHeight: 2.29 m; OverallWidth: 0.83 m; Material: PVC - Blanc, Verre
Pset_EnvironmentalImpactIndicators - sets with these values: 2
Qto_DoorBaseQuantities - Height: 2.24 m; Width: 0.73 m; Area: 1.6352 m2

# IfcDoor: PVC Panneau Vitré :0.73m x 2.24, PVC Panneau Vitré :0.73m x 2.24:414452
In: SS2
Type - PredefinedType: DOOR; OperationType: SINGLE_SWING_RIGHT; Material: PVC - Blanc (3)
Type - PVC Panneau Vitré :0.73m x 2.24:414452 - PanelOperation: SWINGING
Type - Pset_DoorCommon - IsExternal: no; Reference: 0.73m x 2.24; ThermalTransmittance: 5.5617 kg/K/s3
Type - Pset_EnvironmentalImpactIndicators - Reference: 0.73m x 2.24
OverallHeight: 2.29 m; OverallWidth: 0.83 m; Material: PVC - Blanc, Verre
Qto_DoorBaseQuantities - Height: 2.24 m; Width: 0.73 m; Area: 1.6352 m2

# IfcDoor: PVC Panneau Vitré :0.83m x 2.24 (2)
In: SS2
Type - PredefinedType: DOOR; OperationType: SINGLE_SWING_LEFT; Material: PVC - Blanc (3)
Type - PVC Panneau Vitré :0.83m x 2.24:414399 - PanelOperation: SWINGING
Type - Pset_DoorCommon - IsExternal: no; Reference: 0.83m x 2.24; ThermalTransmittance: 5.5617 kg/K/s3
Type - Pset_EnvironmentalImpactIndicators - Reference: 0.83m x 2.24
OverallHeight: 2.29 m; OverallWidth: 0.93 m; Material: PVC - Blanc, Verre
Qto_DoorBaseQuantities - Height: 2.24 m; Width: 0.83 m; Area: 1.8592 m2
Name (PVC Panneau Vitré :0.83m x 2.24:...)
414399
416036

# IfcDoor: PVC Panneau Vitré :0.83m x 2.24, PVC Panneau Vitré :0.83m x 2.24:413302
In: SS2
Type - PredefinedType: DOOR; OperationType: SINGLE_SWING_RIGHT; Material: PVC - Blanc (3)
Type - PVC Panneau Vitré :0.83m x 2.24:413302 - PanelOperation: SWINGING
Type - Pset_DoorCommon - IsExternal: no; Reference: 0.83m x 2.24; ThermalTransmittance: 5.5617 kg/K/s3
Type - Pset_EnvironmentalImpactIndicators - Reference: 0.83m x 2.24
OverallHeight: 2.29 m; OverallWidth: 0.93 m; Material: PVC - Blanc, Verre
Qto_DoorBaseQuantities - Height: 2.24 m; Width: 0.83 m; Area: 1.8592 m2

# IfcDoor: PVC Panneau Vitré :0.93m x 2.10m, PVC Panneau Vitré :0.93m x 2.10m:396579
In: Demi-niveau
Type - PredefinedType: DOOR; OperationType: SINGLE_SWING_LEFT; Material: PVC - Blanc (3)
Type - PVC Panneau Vitré :0.93m x 2.10m:396579 - PanelOperation: SWINGING
Type - Pset_DoorCommon - IsExternal: no; Reference: 0.93m x 2.10m; ThermalTransmittance: 5.5617 kg/K/s3
Type - Pset_EnvironmentalImpactIndicators - Reference: 0.93m x 2.10m
OverallHeight: 2.15 m; OverallWidth: 1.03 m; Material: PVC - Blanc, Verre
Qto_DoorBaseQuantities - Height: 2.1 m; Width: 0.93 m; Area: 1.953 m2

# IfcDoor: Placard coulissante - 2 panneaux:1.65x2.75, Placard coulissante - 2 panneaux:1.65x2.75:285139
In: Niveau 0
Type - PredefinedType: DOOR; OperationType: SLIDING_TO_LEFT; Material: Placard - Porte, Placard - Profil, Placard - Encadrement
Type - Placard coulissante - 2 panneaux:1.65x2.75:285139 - PanelOperation: SLIDING
Type - Pset_DoorCommon - IsExternal: no; Reference: 1.65x2.75; ThermalTransmittance: 3.7021 kg/K/s3
Type - Pset_EnvironmentalImpactIndicators - Reference: 1.65x2.75
OverallHeight: 2.75 m; OverallWidth: 1.7 m; Material: Placard - Profil, Placard - Encadrement, Placard - Porte
Qto_DoorBaseQuantities - Height: 2.75 m; Width: 1.7 m; Area: 4.675 m2

# IfcDoor: Placard coulissante - 3 panneaux:2.45X2.5, Placard coulissante - 3 panneaux:2.45X2.5:553684
In: Niveau 1
Type - PredefinedType: DOOR; OperationType: SLIDING_TO_RIGHT; Material: Placard - Profil, Placard - Porte, Placard - Encadrement
Type - Placard coulissante - 3 panneaux:2.45X2.5:553684 - PanelOperation: SLIDING
Type - Pset_DoorCommon - IsExternal: no; Reference: 2.45X2.5; ThermalTransmittance: 3.7021 kg/K/s3
Type - Pset_EnvironmentalImpactIndicators - Reference: 2.45X2.5
OverallHeight: 2.67 m; OverallWidth: 2.4 m; Material: Placard - Profil, Placard - Encadrement, Placard - Porte
Qto_DoorBaseQuantities - Height: 2.67 m; Width: 2.4 m; Area: 6.408 m2

# IfcDoor: Placard coulissante - 3 panneaux:3.2x2.7, Placard coulissante - 3 panneaux:3.2x2.7:579547
In: Niveau 2
Type - PredefinedType: DOOR; OperationType: SLIDING_TO_RIGHT; Material: Placard - Encadrement, Placard - Profil, Placard - Porte
Type - Placard coulissante - 3 panneaux:3.2x2.7:579547 - PanelOperation: SLIDING
Type - Pset_DoorCommon - IsExternal: no; Reference: 3.2x2.7; ThermalTransmittance: 3.7021 kg/K/s3
Type - Pset_EnvironmentalImpactIndicators - Reference: 3.2x2.7
OverallHeight: 2.7 m; OverallWidth: 3.2 m; Material: Placard - Profil, Placard - Encadrement, Placard - Porte
Qto_DoorBaseQuantities - Height: 2.7 m; Width: 3.2 m; Area: 8.64 m2

# IfcDoor: Porte simple:Porte simple, Porte simple:Porte simple:579238
In: Niveau 2
Type - PredefinedType: DOOR; OperationType: SINGLE_SWING_LEFT; Material: PVC - Blanc (3), Porte - Panneau
Type - Porte simple:Porte simple:579238 - PanelOperation: SWINGING
Type - Pset_DoorCommon - IsExternal: no; Reference: Porte simple; ThermalTransmittance: 3.6886 kg/K/s3
Type - Pset_EnvironmentalImpactIndicators - Reference: Porte simple
OverallHeight: 2.021 m; OverallWidth: 0.942 m; Material: PVC - Blanc, Porte - Panneau
Pset_DoorCommon - IsExternal: yes
Qto_DoorBaseQuantities - Height: 2.021 m; Width: 0.942 m; Area: 1.90378 m2

# IfcDoor: Porte simple:Porte simple, Porte simple:Porte simple:589590
In: Niveau 2
Type - PredefinedType: DOOR; OperationType: SINGLE_SWING_LEFT; Material: PVC - Blanc (3), Porte - Panneau
Type - Porte simple:Porte simple:589590 - PanelOperation: SWINGING
Type - Pset_DoorCommon - IsExternal: no; Reference: Porte simple; ThermalTransmittance: 3.6886 kg/K/s3
Type - Pset_EnvironmentalImpactIndicators - Reference: Porte simple
OverallHeight: 2.021 m; OverallWidth: 0.852609 m; Material: PVC - Blanc, Porte - Panneau
Pset_DoorCommon - IsExternal: yes
Qto_DoorBaseQuantities - Height: 2.021 m; Width: 0.852609 m; Area: 1.72312 m2

# IfcDoor: Porte simple:Porte simple, Porte simple:Porte simple:570275
In: Niveau 2
Type - PredefinedType: DOOR; OperationType: SINGLE_SWING_RIGHT; Material: PVC - Blanc (3), Porte - Panneau
Type - Porte simple:Porte simple:570275 - PanelOperation: SWINGING
Type - Pset_DoorCommon - IsExternal: no; Reference: Porte simple; ThermalTransmittance: 3.6886 kg/K/s3
Type - Pset_EnvironmentalImpactIndicators - Reference: Porte simple
OverallHeight: 2.021 m; OverallWidth: 0.861 m; Material: PVC - Blanc, Porte - Panneau
Pset_DoorCommon - IsExternal: yes
Qto_DoorBaseQuantities - Height: 2.021 m; Width: 0.861 m; Area: 1.74008 m2

# IfcDoor: Porte simple:Porte simple, Porte simple:Porte simple:570659
In: Niveau 2
Type - PredefinedType: DOOR; OperationType: SINGLE_SWING_RIGHT; Material: PVC - Blanc (3), Porte - Panneau
Type - Porte simple:Porte simple:570659 - PanelOperation: SWINGING
Type - Pset_DoorCommon - IsExternal: no; Reference: Porte simple; ThermalTransmittance: 3.6886 kg/K/s3
Type - Pset_EnvironmentalImpactIndicators - Reference: Porte simple
OverallHeight: 2.021 m; OverallWidth: 0.88755 m; Material: PVC - Blanc, Porte - Panneau
Pset_DoorCommon - IsExternal: yes
Qto_DoorBaseQuantities - Height: 2.021 m; Width: 0.88755 m; Area: 1.79374 m2

# IfcDoor: Simple vitrée 1:Simple vitrée 1, Simple vitrée 1:Simple vitrée 1:304275
In: Niveau 0
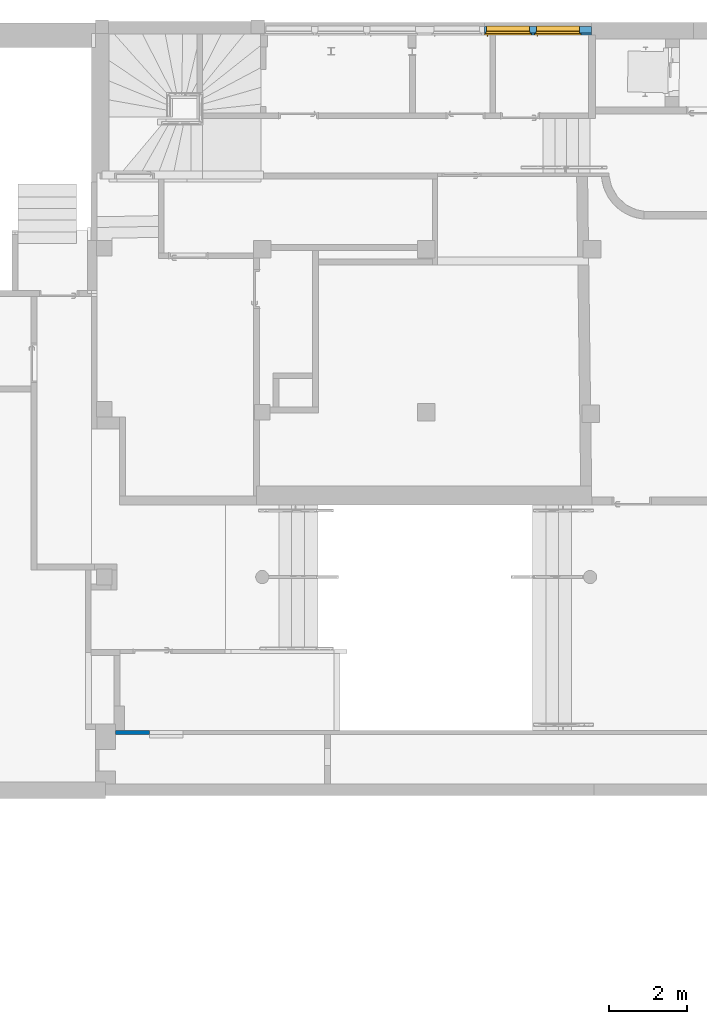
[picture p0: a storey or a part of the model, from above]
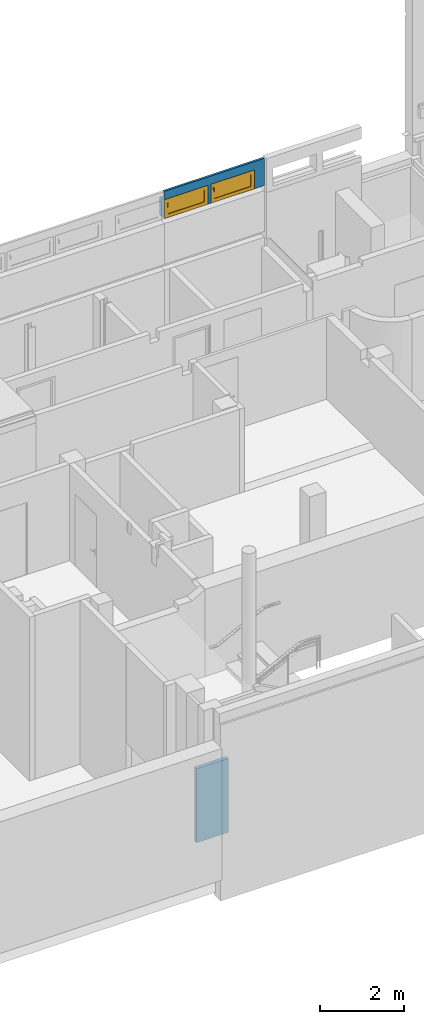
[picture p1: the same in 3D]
Properties of the parts of a building model (IFC4), part 4 of 8

# IfcDoor: Simple vitrée 1:Simple vitrée 1, Simple vitrée 1:Simple vitrée 1:304275
Type - PredefinedType: DOOR; OperationType: SINGLE_SWING_RIGHT; Material: PVC, souple (3)
Type - Simple vitrée 1:Simple vitrée 1:304275 - PanelOperation: SWINGING
Type - Pset_DoorCommon - IsExternal: no; Reference: Simple vitrée 1; ThermalTransmittance: 3.6886 kg/K/s3
Type - Pset_EnvironmentalImpactIndicators - Reference: Simple vitrée 1
OverallHeight: 2.13792 m; OverallWidth: 0.895954 m; Material: PVC, souple, Verre
Pset_DoorCommon - IsExternal: yes
Qto_DoorBaseQuantities - Height: 2.13792 m; Width: 0.895954 m; Area: 1.91547 m2

# IfcDoor: Simple vitrée 2:Simple vitrée 2, Simple vitrée 2:Simple vitrée 2:532432
In: Niveau 1
Type - PredefinedType: DOOR; OperationType: SINGLE_SWING_LEFT; Material: PVC, souple (2), Porte - Panneau, Verre
Type - Simple vitrée 2:Simple vitrée 2:532432 - PanelOperation: SWINGING
Type - Pset_DoorCommon - IsExternal: no; Reference: Simple vitrée 2; ThermalTransmittance: 3.6886 kg/K/s3
Type - Pset_EnvironmentalImpactIndicators - Reference: Simple vitrée 2
OverallHeight: 2.01096 m; OverallWidth: 0.808 m; Material: PVC, souple, Verre
Pset_DoorCommon - IsExternal: yes
Qto_DoorBaseQuantities - Height: 2.01096 m; Width: 0.808 m; Area: 1.62486 m2

# IfcDoor: Simple vitrée 2:Simple vitrée 2, Simple vitrée 2:Simple vitrée 2:532769
In: Niveau 1
Type - PredefinedType: DOOR; OperationType: SINGLE_SWING_LEFT; Material: PVC, souple (2), Porte - Panneau, Verre
Type - Simple vitrée 2:Simple vitrée 2:532769 - PanelOperation: SWINGING
Type - Pset_DoorCommon - IsExternal: no; Reference: Simple vitrée 2; ThermalTransmittance: 3.6886 kg/K/s3
Type - Pset_EnvironmentalImpactIndicators - Reference: Simple vitrée 2
OverallHeight: 2.01096 m; OverallWidth: 0.884 m; Material: PVC, souple, Verre
Pset_DoorCommon - IsExternal: yes
Qto_DoorBaseQuantities - Height: 2.01096 m; Width: 0.884 m; Area: 1.77769 m2

# IfcDoor: Simple vitrée 2:Simple vitrée 2, Simple vitrée 2:Simple vitrée 2:541358
In: Niveau 1
Type - PredefinedType: DOOR; OperationType: SINGLE_SWING_LEFT; Material: PVC, souple (2), Verre, Porte - Panneau
Type - Simple vitrée 2:Simple vitrée 2:541358 - PanelOperation: SWINGING
Type - Pset_DoorCommon - IsExternal: no; Reference: Simple vitrée 2; ThermalTransmittance: 3.6886 kg/K/s3
Type - Pset_EnvironmentalImpactIndicators - Reference: Simple vitrée 2
OverallHeight: 2.01096 m; OverallWidth: 0.829657 m; Material: PVC, souple, Verre
Pset_DoorCommon - IsExternal: yes
Qto_DoorBaseQuantities - Height: 2.01096 m; Width: 0.829657 m; Area: 1.66841 m2

# IfcDoor: Simple vitrée 2:Simple vitrée 2, Simple vitrée 2:Simple vitrée 2:554581
In: Niveau 1
Type - PredefinedType: DOOR; OperationType: SINGLE_SWING_RIGHT; Material: PVC, souple (2), Porte - Panneau, Verre
Type - Simple vitrée 2:Simple vitrée 2:554581 - PanelOperation: SWINGING
Type - Pset_DoorCommon - IsExternal: no; Reference: Simple vitrée 2; ThermalTransmittance: 3.6886 kg/K/s3
Type - Pset_EnvironmentalImpactIndicators - Reference: Simple vitrée 2
OverallHeight: 2.1084 m; OverallWidth: 0.867 m; Material: PVC, souple, Verre
Pset_DoorCommon - IsExternal: yes
Qto_DoorBaseQuantities - Height: 2.1084 m; Width: 0.867 m; Area: 1.82798 m2

# IfcDoor: Simple vitrée 2:Simple vitrée 2, Simple vitrée 2:Simple vitrée 2:532657
In: Niveau 1
Type - PredefinedType: DOOR; OperationType: SINGLE_SWING_RIGHT; Material: PVC, souple (2), Verre, Porte - Panneau
Type - Simple vitrée 2:Simple vitrée 2:532657 - PanelOperation: SWINGING
Type - Pset_DoorCommon - IsExternal: no; Reference: Simple vitrée 2; ThermalTransmittance: 3.6886 kg/K/s3
Type - Pset_EnvironmentalImpactIndicators - Reference: Simple vitrée 2
OverallHeight: 2.01096 m; OverallWidth: 0.833 m; Material: PVC, souple, Verre
Pset_DoorCommon - IsExternal: yes
Qto_DoorBaseQuantities - Height: 2.01096 m; Width: 0.833 m; Area: 1.67513 m2

# IfcDoor: Simple vitrée 2:Simple vitrée 2, Simple vitrée 2:Simple vitrée 2:532748
In: Niveau 1
Type - PredefinedType: DOOR; OperationType: SINGLE_SWING_RIGHT; Material: PVC, souple (2), Verre, Porte - Panneau
Type - Simple vitrée 2:Simple vitrée 2:532748 - PanelOperation: SWINGING
Type - Pset_DoorCommon - IsExternal: no; Reference: Simple vitrée 2; ThermalTransmittance: 3.6886 kg/K/s3
Type - Pset_EnvironmentalImpactIndicators - Reference: Simple vitrée 2
OverallHeight: 2.01096 m; OverallWidth: 0.847 m; Material: PVC, souple, Verre
Pset_DoorCommon - IsExternal: yes
Qto_DoorBaseQuantities - Height: 2.01096 m; Width: 0.847 m; Area: 1.70328 m2

# IfcDoor: Verre - simple:Verre - simple (8)
In: SS1
Type - PredefinedType: DOOR; OperationType: SINGLE_SWING_RIGHT; Material: Métal - Aluminium, Porte - Poignée
Type - Verre - simple:Verre - simple:476560 - PanelOperation: SWINGING
Type - Pset_DoorCommon - IsExternal: no; Reference: Verre - simple; ThermalTransmittance: 5.5617 kg/K/s3
Type - Pset_EnvironmentalImpactIndicators - Reference: Verre - simple
OverallHeight: 1.95 m; OverallWidth: 0.97 m; Material: Métal - Aluminium, Verre
Qto_DoorBaseQuantities - Height: 1.95 m; Width: 0.93 m; Area: 1.8135 m2
Name (Verre - simple:Verre - simple:...)
476560
476561
476562
476563
476564
476565
476566
476567

# IfcDoor: ouverture simple:ouverture simple, ouverture simple:ouverture simple:589596
In: Niveau 2
Type - PredefinedType: DOOR; OperationType: SINGLE_SWING_LEFT; Material: PVC - Blanc (3), Porte - Panneau
Type - ouverture simple:ouverture simple:589596 - PanelOperation: SWINGING
Type - Pset_DoorCommon - IsExternal: no; Reference: ouverture simple; ThermalTransmittance: 3.6886 kg/K/s3
Type - Pset_EnvironmentalImpactIndicators - Reference: ouverture simple
OverallHeight: 2.021 m; OverallWidth: 0.93 m; Material: PVC - Blanc
Pset_DoorCommon - IsExternal: yes
Qto_DoorBaseQuantities - Height: 2.021 m; Width: 0.93 m; Area: 1.87953 m2

# IfcFlowTerminal: Lavabo mural - 02:500mm x 500mm (5)
Type - Material: Porcelaine - Blanche
Type - Pset_EnvironmentalImpactIndicators - Reference: 500mm x 500mm
Pset_EnvironmentalImpactIndicators - sets with these values: 2
Name (Lavabo mural - 02:500mm x 500mm:...) | In
292195 | Niveau 0
487553 | SS1
487558 | SS1
487918 | SS1
543887 | Niveau 1

# IfcFlowTerminal: Lavabo mural - 05:440mm x 350mm (4)
Type - Material: Métal - Chrome poli, Porcelaine - Blanche
Type - Pset_EnvironmentalImpactIndicators - Reference: 440mm x 350mm
Pset_EnvironmentalImpactIndicators - sets with these values: 2
Name (Lavabo mural - 05:440mm x 350mm:...) | In
290633 | Niveau 0
527600 | Niveau 1
543186 | Niveau 1
589197 | Niveau 2

# IfcFlowTerminal: Lavabo sur pied:Lavabo sur pied (2)
In: Niveau 1
Type - Material: Porcelaine - Lin (2), Métal - Chrome
Type - Pset_EnvironmentalImpactIndicators - Reference: Lavabo sur pied
Material: Porcelaine - Lin, Métal - Chrome
Pset_EnvironmentalImpactIndicators - sets with these values: 2
Name (Lavabo sur pied:Lavabo sur pied:...)
546424
546784

# IfcFlowTerminal: Receveur d'angle - Vidange en angle:920 x 900mm, Receveur d'angle - Vidange en angle:920 x 900mm:547994
In: Niveau 1
Type - Classification: D2010710 Showers (Uniformat); Material: Céramique - Blanche
Type - Pset_EnvironmentalImpactIndicators - Reference: 920 x 900mm
Pset_EnvironmentalImpactIndicators - sets with these values: 2

# IfcFlowTerminal: Urinoir:Urinoir (4)
In: SS1
Type - Material: Métal - Chrome poli, Porcelaine - Blanche
Type - Pset_EnvironmentalImpactIndicators - Reference: Urinoir
Pset_EnvironmentalImpactIndicators - sets with these values: 2
Name (Urinoir:Urinoir:...)
489048
489074
489093
489116

# IfcFlowTerminal: WC à réservoir:WC à réservoir (10)
Type - Material: Métal - Chrome, Porcelaine - Blanche
Type - Pset_EnvironmentalImpactIndicators - Reference: WC à réservoir
Material: Porcelaine - Blanche, Métal - Chrome
Name (WC à réservoir:WC à réservoir:...) | In | sets with these values
288770 | Niveau 0
290876 | Niveau 0 | 2
487649 | SS1 | 2
487698 | SS1 | 2
487794 | SS1 | 2
527341 | Niveau 1 | 2
543445 | Niveau 1 | 2
544014 | Niveau 1 | 2
546686 | Niveau 1 | 2
589185 | Niveau 2 | 2

# IfcFurniture: Placard:Placard, Placard:Placard:575654
In: Niveau 2
Type - Material: Résineux, bois de construction
Type - Pset_EnvironmentalImpactIndicators - Reference: Placard
Type - Pset_FurnitureTypeCommon - Reference: Placard
Pset_EnvironmentalImpactIndicators - sets with these values: 2

# IfcMember: Meneau rectangulaire:100 x 25mm (8)
In: Niveau 0
Type - PredefinedType: MULLION; Material: PVC, souple
Type - Pset_EnvironmentalImpactIndicators - Reference: 100 x 25mm
Type - Pset_MemberCommon - IsExternal: no; Reference: 100 x 25mm
Name (Meneau rectangulaire:100 x 25mm:...) | Span (m) | CrossSectionArea (m2) | NetSurfaceArea (m2) | NetVolume (m3)
302270 | 2.18792 | 0.333187 | 0.666375 | 0.0109396
302271 | 1.89707 | 0.289561 | 0.579122 | 0.00948537
302272 | 2.18792 | 0.333187 | 0.666375 | 0.0109396
304276 | 2.13792 | 0.325687 | 0.651375 | 0.0106896
304277 | 2.13792 | 0.325687 | 0.651375 | 0.0106896
304278 | 1.94191 | 0.296286 | 0.587572 | 0.00970954
305711 | 0.970954 | 0.150643 | 0.296286 | 0.00485477
305736 | 2.13792 | 0.325687 | 0.651375 | 0.0106896

# IfcMember: Meneau rectangulaire:50 x 125 mm (2)
In: Niveau 2
Type - PredefinedType: MULLION; Material: PVC - Blanc
Type - Pset_EnvironmentalImpactIndicators - Reference: 50 x 125 mm
Type - Pset_MemberCommon - IsExternal: no; Reference: 50 x 125 mm
Pset_MemberCommon - Span: 0.311 m
Qto_MemberBaseQuantities - CrossSectionArea: 0.024575 m2; NetSurfaceArea: 0.04915 m2; NetVolume: 0.00038875 m3
Name (Meneau rectangulaire:50 x 125 mm:...)
572348
572486

# IfcMember: Meneau rectangulaire:50 x 25mm (164)
Type - PredefinedType: MULLION; Material: PVC - Blanc
Type - Pset_EnvironmentalImpactIndicators - Reference: 50 x 25mm
Type - Pset_MemberCommon - IsExternal: no; Reference: 50 x 25mm
Name (Meneau rectangulaire:50 x 25mm:...) | In | Span (m) | CrossSectionArea (m2) | NetSurfaceArea (m2) | NetVolume (m3)
312757 | Niveau 0 | 2.25 | 0.2275 | 0.455 | 0.005625
314727 | Niveau 0 | 2.25 | 0.2275 | 0.455 | 0.005625
314720 | Niveau 0 | 3.06462 | 0.308962 | 0.617924 | 0.00766155
314721 | Niveau 0 | 0.631255 | 0.0656255 | 0.131251 | 0.00157814
314722 | Niveau 0 | 3.06462 | 0.308962 | 0.617924 | 0.00766155
314723 | Niveau 0 | 0.631255 | 0.0656255 | 0.131251 | 0.00157814
313291 | Niveau 0 | 2.25 | 0.2275 | 0.455 | 0.005625
314735 | Niveau 0 | 2.25 | 0.2275 | 0.455 | 0.005625
314695 | Niveau 0 | 3.06462 | 0.308962 | 0.617924 | 0.00766155
314696 | Niveau 0 | 0.652 | 0.0677 | 0.1354 | 0.00163
314697 | Niveau 0 | 3.06462 | 0.308962 | 0.617924 | 0.00766155
314698 | Niveau 0 | 0.652 | 0.0677 | 0.1354 | 0.00163
314711 | Niveau 0 | 3.06462 | 0.308962 | 0.617924 | 0.00766155
314712 | Niveau 0 | 0.673875 | 0.0698875 | 0.139775 | 0.00168469
314713 | Niveau 0 | 3.06462 | 0.308962 | 0.617924 | 0.00766155
314714 | Niveau 0 | 0.673875 | 0.0698875 | 0.139775 | 0.00168469
314704 | Niveau 0 | 3.06462 | 0.308962 | 0.617924 | 0.00766155
314705 | Niveau 0 | 0.676134 | 0.0701134 | 0.140227 | 0.00169034
314706 | Niveau 0 | 3.06462 | 0.308962 | 0.617924 | 0.00766155
314707 | Niveau 0 | 0.676134 | 0.0701134 | 0.140227 | 0.00169034
314825 | Niveau 1 | 1.517 | 0.1542 | 0.3059 | 0.0037925
314826 | Niveau 1 | 0.642527 | 0.0667527 | 0.133505 | 0.00160632
314827 | Niveau 1 | 2.74446 | 0.276946 | 0.551392 | 0.00686115
335795 | Niveau 1 | 2.74446 | 0.276946 | 0.551392 | 0.00686115
335796 | Niveau 1 | 1.517 | 0.1542 | 0.3059 | 0.0037925
314961 | Niveau 1 | 2.925 | 0.295 | 0.5875 | 0.0073125
314962 | Niveau 1 | 0.642527 | 0.0667527 | 0.133505 | 0.00160632
314963 | Niveau 1 | 2.486 | 0.2511 | 0.4997 | 0.006215
335663 | Niveau 1 | 2.805 | 0.283 | 0.561 | 0.0070125
335664 | Niveau 1 | 2.925 | 0.295 | 0.5875 | 0.0073125
335715 | Niveau 1 | 2.805 | 0.283 | 0.561 | 0.0070125
335716 | Niveau 1 | 2.486 | 0.2511 | 0.4997 | 0.006215
314969 | Niveau 1 | 0.742527 | 0.0767527 | 0.153505 | 0.00185632
314970 | Niveau 1 | 0.233 | 0.0258 | 0.0516 | 0.0005825
314972 | Niveau 1 | 0.233 | 0.0258 | 0.0516 | 0.0005825
314973 | Niveau 1 | 0.742527 | 0.0767527 | 0.153505 | 0.00185632
314974 | Niveau 1 | 0.251777 | 0.0276777 | 0.0553553 | 0.000629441
314976 | Niveau 1 | 0.251777 | 0.0276777 | 0.0553553 | 0.000629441
326373 | Niveau 1 | 0.642527 | 0.0667527 | 0.133505 | 0.00160632
326374 | Niveau 1 | 1.231 | 0.1256 | 0.2487 | 0.0030775
326375 | Niveau 1 | 0.642527 | 0.0667527 | 0.133505 | 0.00160632
326376 | Niveau 1 | 1.226 | 0.1251 | 0.2477 | 0.003065
335309 | Niveau 1 | 1.39472 | 0.141972 | 0.278944 | 0.0034868
335310 | Niveau 1 | 1.231 | 0.1256 | 0.2487 | 0.0030775
335354 | Niveau 1 | 1.39472 | 0.141972 | 0.278944 | 0.0034868
335355 | Niveau 1 | 1.226 | 0.1251 | 0.2477 | 0.003065
336305 | Niveau 0 | 0.748619 | 0.0773619 | 0.154724 | 0.00187155
336306 | Niveau 0 | 2.15675 | 0.218175 | 0.436349 | 0.00539186
336307 | Niveau 0 | 0.748619 | 0.0773619 | 0.154724 | 0.00187155
336308 | Niveau 0 | 2.15675 | 0.218175 | 0.436349 | 0.00539186
336296 | Niveau 0 | 0.748619 | 0.0773619 | 0.154724 | 0.00187155
336297 | Niveau 0 | 2.14712 | 0.217212 | 0.434425 | 0.00536781
336298 | Niveau 0 | 0.748619 | 0.0773619 | 0.154724 | 0.00187155
336299 | Niveau 0 | 2.14712 | 0.217212 | 0.434425 | 0.00536781
404733 | Niveau 0 | 1.941 | 0.1966 | 0.3907 | 0.0048525
404734 | Niveau 0 | 1.79856 | 0.182356 | 0.362212 | 0.0044964
404735 | Niveau 0 | 0.709 | 0.0734 | 0.1443 | 0.0017725
404736 | Niveau 0 | 0.789369 | 0.0814369 | 0.160374 | 0.00197342
404737 | Niveau 0 | 0.709 | 0.0734 | 0.1443 | 0.0017725
404738 | Niveau 0 | 0.714369 | 0.0739369 | 0.147874 | 0.00178592
404739 | Niveau 0 | 1.79856 | 0.182356 | 0.362212 | 0.0044964
404740 | Niveau 0 | 1.941 | 0.1966 | 0.3907 | 0.0048525
404741 | Niveau 0 | 0.789369 | 0.0814369 | 0.160374 | 0.00197342
404742 | Niveau 0 | 0.709 | 0.0734 | 0.1443 | 0.0017725
404743 | Niveau 0 | 1.941 | 0.1966 | 0.3907 | 0.0048525
404769 | Niveau 0 | 1.941 | 0.1966 | 0.3907 | 0.0048525
404770 | Niveau 0 | 1.79856 | 0.182356 | 0.362212 | 0.0044964
404771 | Niveau 0 | 0.709 | 0.0734 | 0.1443 | 0.0017725
404772 | Niveau 0 | 0.833086 | 0.0858086 | 0.169117 | 0.00208272
404773 | Niveau 0 | 0.709 | 0.0734 | 0.1443 | 0.0017725
404774 | Niveau 0 | 0.758086 | 0.0783086 | 0.156617 | 0.00189522
404775 | Niveau 0 | 1.79856 | 0.182356 | 0.362212 | 0.0044964
404776 | Niveau 0 | 1.941 | 0.1966 | 0.3907 | 0.0048525
404777 | Niveau 0 | 0.833086 | 0.0858086 | 0.169117 | 0.00208272
404778 | Niveau 0 | 0.709 | 0.0734 | 0.1443 | 0.0017725
404779 | Niveau 0 | 1.941 | 0.1966 | 0.3907 | 0.0048525
404862 | Niveau 0 | 1.941 | 0.1966 | 0.3907 | 0.0048525
404863 | Niveau 0 | 1.79856 | 0.182356 | 0.362212 | 0.0044964
404864 | Niveau 0 | 0.709 | 0.0734 | 0.1443 | 0.0017725
404865 | Niveau 0 | 0.801439 | 0.0826439 | 0.162788 | 0.0020036
404866 | Niveau 0 | 0.709 | 0.0734 | 0.1443 | 0.0017725
404867 | Niveau 0 | 0.726439 | 0.0751439 | 0.150288 | 0.0018161
404868 | Niveau 0 | 1.79856 | 0.182356 | 0.362212 | 0.0044964
404869 | Niveau 0 | 1.941 | 0.1966 | 0.3907 | 0.0048525
404870 | Niveau 0 | 0.801439 | 0.0826439 | 0.162788 | 0.0020036
404871 | Niveau 0 | 0.709 | 0.0734 | 0.1443 | 0.0017725
404872 | Niveau 0 | 1.941 | 0.1966 | 0.3907 | 0.0048525
513721 | Niveau 1 | 1.517 | 0.1542 | 0.3059 | 0.0037925
513722 | Niveau 1 | 0.642527 | 0.0667527 | 0.133505 | 0.00160632
513723 | Niveau 1 | 2.74446 | 0.276946 | 0.551392 | 0.00686115
513727 | Niveau 1 | 2.74446 | 0.276946 | 0.551392 | 0.00686115
513728 | Niveau 1 | 1.517 | 0.1542 | 0.3059 | 0.0037925
514543 | Niveau 1 | 1.517 | 0.1542 | 0.3059 | 0.0037925
514544 | Niveau 1 | 0.642527 | 0.0667527 | 0.133505 | 0.00160632
514545 | Niveau 1 | 2.71482 | 0.273982 | 0.545465 | 0.00678706
514549 | Niveau 1 | 2.71482 | 0.273982 | 0.545465 | 0.00678706
514550 | Niveau 1 | 1.517 | 0.1542 | 0.3059 | 0.0037925
554362 | Niveau 1 | 1.30317 | 0.132817 | 0.263134 | 0.00325792
554363 | Niveau 1 | 1.199 | 0.1224 | 0.2398 | 0.0029975
554364 | Niveau 1 | 1.312 | 0.1337 | 0.2649 | 0.00328
554371 | Niveau 1 | 0.180515 | 0.0205515 | 0.0386029 | 0.000451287
554372 | Niveau 1 | 1.30317 | 0.132817 | 0.263134 | 0.00325792
554373 | Niveau 1 | 1.106 | 0.1131 | 0.2237 | 0.002765
554374 | Niveau 1 | 1.106 | 0.1131 | 0.2237 | 0.002765
554375 | Niveau 1 | 1.106 | 0.1131 | 0.2237 | 0.002765
554376 | Niveau 1 | 1.237 | 0.1262 | 0.2524 | 0.0030925
554377 | Niveau 1 | 1.149 | 0.1174 | 0.2348 | 0.0028725
554378 | Niveau 1 | 1.22817 | 0.125317 | 0.250634 | 0.00307042
554379 | Niveau 1 | 1.237 | 0.1262 | 0.2524 | 0.0030925
554380 | Niveau 1 | 1.149 | 0.1174 | 0.2348 | 0.0028725
554381 | Niveau 1 | 1.22817 | 0.125317 | 0.250634 | 0.00307042
554382 | Niveau 1 | 0.9837 | 0.10087 | 0.19674 | 0.00245925
554383 | Niveau 1 | 0.180515 | 0.0205515 | 0.0386029 | 0.000451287
554384 | Niveau 1 | 1.312 | 0.1337 | 0.2649 | 0.00328
554385 | Niveau 1 | 1.199 | 0.1224 | 0.2398 | 0.0029975
554386 | Niveau 1 | 1.106 | 0.1131 | 0.2237 | 0.002765
554387 | Niveau 1 | 0.9837 | 0.10087 | 0.19674 | 0.00245925
554388 | Niveau 1 | 0.9837 | 0.10087 | 0.19674 | 0.00245925
554389 | Niveau 1 | 0.180515 | 0.0205515 | 0.0386029 | 0.000451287
554390 | Niveau 1 | 0.9837 | 0.10087 | 0.19674 | 0.00245925
554391 | Niveau 1 | 0.180515 | 0.0205515 | 0.0386029 | 0.000451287
554894 | Niveau 1 | 0.892 | 0.0917 | 0.1809 | 0.00223
554895 | Niveau 1 | 0.76 | 0.0785 | 0.152 | 0.0019
554896 | Niveau 1 | 0.86 | 0.0885 | 0.1745 | 0.00215
554903 | Niveau 1 | 0.71 | 0.0735 | 0.147 | 0.001775
554904 | Niveau 1 | 0.785 | 0.081 | 0.162 | 0.0019625
554905 | Niveau 1 | 0.867 | 0.0892 | 0.1784 | 0.0021675
554915 | Niveau 1 | 0.1837 | 0.02087 | 0.03924 | 0.00045925
554916 | Niveau 1 | 0.936 | 0.0961 | 0.1872 | 0.00234
554917 | Niveau 1 | 1.1474 | 0.11724 | 0.231979 | 0.00286849
554931 | Niveau 1 | 0.71 | 0.0735 | 0.147 | 0.001775
554932 | Niveau 1 | 0.785 | 0.081 | 0.162 | 0.0019625
554940 | Niveau 1 | 0.1837 | 0.02087 | 0.03924 | 0.00045925
554941 | Niveau 1 | 0.936 | 0.0961 | 0.1872 | 0.00234
554942 | Niveau 1 | 1.1474 | 0.11724 | 0.231979 | 0.00286849
554952 | Niveau 1 | 0.1837 | 0.02087 | 0.03924 | 0.00045925
554953 | Niveau 1 | 0.936 | 0.0961 | 0.1872 | 0.00234
554954 | Niveau 1 | 1.1474 | 0.11724 | 0.231979 | 0.00286849
554983 | Niveau 1 | 0.785 | 0.081 | 0.1595 | 0.0019625
554987 | Niveau 1 | 0.86 | 0.0885 | 0.1745 | 0.00215
572395 | Niveau 2 | 0.477 | 0.0502 | 0.1004 | 0.0011925
572396 | Niveau 2 | 0.86255 | 0.088755 | 0.17751 | 0.00215637
572397 | Niveau 2 | 0.836 | 0.0861 | 0.1722 | 0.00209
572435 | Niveau 2 | 0.935 | 0.096 | 0.187 | 0.0023375
572436 | Niveau 2 | 0.286 | 0.0311 | 0.0597 | 0.000715
572437 | Niveau 2 | 1.041 | 0.1066 | 0.2107 | 0.0026025
572446 | Niveau 2 | 0.477 | 0.0502 | 0.1004 | 0.0011925
572447 | Niveau 2 | 2.371 | 0.2396 | 0.4792 | 0.0059275
579247 | Niveau 2 | 1.041 | 0.1066 | 0.2107 | 0.0026025
579248 | Niveau 2 | 0.935 | 0.096 | 0.187 | 0.0023375
579249 | Niveau 2 | 0.286 | 0.0311 | 0.0597 | 0.000715
579263 | Niveau 2 | 0.942 | 0.0967 | 0.1934 | 0.002355
579264 | Niveau 2 | 0.843 | 0.0868 | 0.1736 | 0.0021075
579268 | Niveau 2 | 2.513 | 0.2538 | 0.5076 | 0.0062825
579269 | Niveau 2 | 2.92975 | 0.295475 | 0.590949 | 0.00732436
580257 | Niveau 2 | 3.13888 | 0.316388 | 0.632777 | 0.00784721
589605 | Niveau 2 | 1.041 | 0.1066 | 0.2107 | 0.0026025
589606 | Niveau 2 | 0.935 | 0.096 | 0.187 | 0.0023375
589607 | Niveau 2 | 0.286 | 0.0311 | 0.0597 | 0.000715
589621 | Niveau 2 | 0.93 | 0.0955 | 0.191 | 0.002325
589622 | Niveau 2 | 0.852609 | 0.0877609 | 0.175522 | 0.00213152
589626 | Niveau 2 | 2.513 | 0.2538 | 0.5076 | 0.0062825
589627 | Niveau 2 | 2.981 | 0.3006 | 0.6012 | 0.0074525
627840 | Niveau 2 | 2.825 | 0.285 | 0.57 | 0.0070625

# IfcMember: Meneau rectangulaire:50 x 25mm pvc gris (26)
In: Niveau 1
Type - PredefinedType: MULLION; Material: PVC, souple
Type - Pset_EnvironmentalImpactIndicators - Reference: 50 x 25mm pvc gris
Type - Pset_MemberCommon - IsExternal: no; Reference: 50 x 25mm pvc gris
Name (Meneau rectangulaire:50 x 25mm pvc gris:...) | Span (m) | CrossSectionArea (m2) | NetSurfaceArea (m2) | NetVolume (m3)
533987 | 0.576 | 0.0601 | 0.1177 | 0.00144
533992 | 1.32 | 0.1345 | 0.264 | 0.0033
533996 | 1.46 | 0.1485 | 0.292 | 0.00365
534000 | 1 | 0.1025 | 0.2 | 0.0025
534004 | 0.885 | 0.091 | 0.1795 | 0.0022125
534008 | 1.034 | 0.1059 | 0.2093 | 0.002585
534011 | 0.91 | 0.0935 | 0.1845 | 0.002275
534015 | 0.975645 | 0.100065 | 0.197629 | 0.00243911
534018 | 0.99629 | 0.102129 | 0.199258 | 0.00249073
534022 | 0.982692 | 0.100769 | 0.196538 | 0.00245673
534161 | 0.142308 | 0.0167308 | 0.0309616 | 0.00035577
540370 | 0.321 | 0.0346 | 0.0667 | 0.0008025
540371 | 0.535 | 0.056 | 0.107 | 0.0013375
540372 | 1.06648 | 0.109148 | 0.213296 | 0.00266619
540373 | 1.112 | 0.1137 | 0.2224 | 0.00278
540374 | 1.054 | 0.1079 | 0.2133 | 0.002635
541016 | 0.948003 | 0.0973003 | 0.189601 | 0.00237001
541017 | 0.938475 | 0.0963475 | 0.190195 | 0.00234619
541018 | 0.917 | 0.0942 | 0.1834 | 0.0022925
541019 | 1.003 | 0.1028 | 0.2006 | 0.0025075
541020 | 0.282 | 0.0307 | 0.0589 | 0.000705
542352 | 0.231 | 0.0256 | 0.0512 | 0.0005775
542358 | 1.0114 | 0.10364 | 0.20478 | 0.0025285
542361 | 1.0114 | 0.10364 | 0.20228 | 0.0025285
542365 | 1.0114 | 0.10364 | 0.20478 | 0.0025285
542355 | 0.536363 | 0.0561363 | 0.112273 | 0.00134091

# IfcMember: Meneau rectangulaire:50 x 30 (77)
In: Niveau 2
Type - PredefinedType: MULLION; Material: PVC - Blanc
Type - Pset_EnvironmentalImpactIndicators - Reference: 50 x 30
Type - Pset_MemberCommon - IsExternal: no; Reference: 50 x 30
Name (Meneau rectangulaire:50 x 30:...) | Span (m) | CrossSectionArea (m2) | NetSurfaceArea (m2) | NetVolume (m3)
582974 | 1.342 | 0.15062 | 0.29824 | 0.004026
582975 | 0.526894 | 0.0609583 | 0.118917 | 0.00158068
582980 | 0.526894 | 0.0609583 | 0.118917 | 0.00158068
582981 | 1.342 | 0.15062 | 0.29824 | 0.004026
583083 | 1.342 | 0.15062 | 0.29824 | 0.004026
583084 | 0.526894 | 0.0609583 | 0.118917 | 0.00158068
583085 | 0.526894 | 0.0609583 | 0.118917 | 0.00158068
583086 | 1.342 | 0.15062 | 0.29824 | 0.004026
583099 | 1.342 | 0.15062 | 0.29824 | 0.004026
583100 | 0.52 | 0.0602 | 0.1174 | 0.00156
583101 | 0.52 | 0.0602 | 0.1174 | 0.00156
583102 | 1.342 | 0.15062 | 0.29824 | 0.004026
583229 | 0.771 | 0.08781 | 0.17262 | 0.002313
583230 | 1.09789 | 0.123768 | 0.244537 | 0.00329368
583231 | 1.09789 | 0.123768 | 0.244537 | 0.00329368
583232 | 0.771 | 0.08781 | 0.17262 | 0.002313
583406 | 1.342 | 0.15062 | 0.29824 | 0.004026
583407 | 0.526894 | 0.0609583 | 0.118917 | 0.00158068
583408 | 0.526894 | 0.0609583 | 0.118917 | 0.00158068
583409 | 1.342 | 0.15062 | 0.29824 | 0.004026
583422 | 1.342 | 0.15062 | 0.29824 | 0.004026
583423 | 0.526894 | 0.0609583 | 0.118917 | 0.00158068
583424 | 0.526894 | 0.0609583 | 0.118917 | 0.00158068
583425 | 1.342 | 0.15062 | 0.29824 | 0.004026
583438 | 1.342 | 0.15062 | 0.29824 | 0.004026
583439 | 0.526894 | 0.0609583 | 0.118917 | 0.00158068
583440 | 0.526894 | 0.0609583 | 0.118917 | 0.00158068
583441 | 1.342 | 0.15062 | 0.29824 | 0.004026
590787 | 1.06 | 0.1196 | 0.2332 | 0.00318
590788 | 0.366 | 0.04326 | 0.08352 | 0.001098
590789 | 0.462 | 0.05382 | 0.10464 | 0.001386
590841 | 0.462 | 0.05382 | 0.10464 | 0.001386
590842 | 1.06 | 0.1196 | 0.2332 | 0.00318
590843 | 0.366 | 0.04326 | 0.08352 | 0.001098
590850 | 1 | 0.113 | 0.223 | 0.003
590851 | 1.028 | 0.11608 | 0.22616 | 0.003084
590852 | 0.749 | 0.08539 | 0.16778 | 0.002247
591050 | 0.958 | 0.10838 | 0.21676 | 0.002874
591051 | 0.649 | 0.07439 | 0.14878 | 0.001947
591052 | 0.91 | 0.1031 | 0.2062 | 0.00273
591065 | 0.396 | 0.04656 | 0.09312 | 0.001188
591115 | 1.06 | 0.1196 | 0.2332 | 0.00318
591116 | 0.366 | 0.04326 | 0.08352 | 0.001098
591117 | 0.462 | 0.05382 | 0.10464 | 0.001386
591118 | 0.462 | 0.05382 | 0.10464 | 0.001386
591119 | 1.06 | 0.1196 | 0.2332 | 0.00318
591120 | 0.366 | 0.04326 | 0.08352 | 0.001098
591121 | 1 | 0.113 | 0.223 | 0.003
591122 | 0.996 | 0.11256 | 0.21912 | 0.002988
591123 | 0.709 | 0.08099 | 0.15898 | 0.002127
591128 | 0.926 | 0.10486 | 0.20972 | 0.002778
591129 | 0.609 | 0.06999 | 0.13998 | 0.001827
591130 | 0.91 | 0.1031 | 0.2062 | 0.00273
591131 | 0.396 | 0.04656 | 0.09312 | 0.001188
591530 | 0.652629 | 0.0747892 | 0.149578 | 0.00195789
591533 | 0.652629 | 0.0747892 | 0.149578 | 0.00195789
591536 | 1.588 | 0.17768 | 0.35236 | 0.004764
591537 | 1.137 | 0.12807 | 0.25314 | 0.003411
591560 | 0.652629 | 0.0747892 | 0.149578 | 0.00195789
595830 | 1.244 | 0.13984 | 0.27668 | 0.003732
595831 | 0.506 | 0.05866 | 0.11432 | 0.001518
595836 | 0.506 | 0.05866 | 0.11432 | 0.001518
595837 | 1.244 | 0.13984 | 0.27668 | 0.003732
595847 | 1.03318 | 0.116649 | 0.233299 | 0.00309953
595852 | 0.913176 | 0.103449 | 0.206899 | 0.00273953
595978 | 1.244 | 0.13984 | 0.27668 | 0.003732
595979 | 0.506 | 0.05866 | 0.11432 | 0.001518
595980 | 0.506 | 0.05866 | 0.11432 | 0.001518
595981 | 1.244 | 0.13984 | 0.27668 | 0.003732
595983 | 1.00475 | 0.113522 | 0.227044 | 0.00301424
595984 | 0.884745 | 0.100322 | 0.200644 | 0.00265424
596419 | 0.506 | 0.05866 | 0.11432 | 0.001518
596420 | 1.26926 | 0.142618 | 0.285236 | 0.00380777
596421 | 1.244 | 0.13984 | 0.27668 | 0.003732
596423 | 1.14926 | 0.129418 | 0.258836 | 0.00344777
596424 | 0.506 | 0.05866 | 0.11432 | 0.001518
596425 | 1.244 | 0.13984 | 0.27668 | 0.003732

# IfcMember: Meneau rectangulaire:50 x 35 (542)
Type - PredefinedType: MULLION; Material: PVC - Blanc
Type - Pset_EnvironmentalImpactIndicators - Reference: 50 x 35
Type - Pset_MemberCommon - IsExternal: no; Reference: 50 x 35
Name (Meneau rectangulaire:50 x 35:...) | In | Span (m) | CrossSectionArea (m2) | NetSurfaceArea (m2) | NetVolume (m3)
369792 | Niveau 0 | 0.459 | 0.05858 | 0.11366 | 0.0016065
369793 | Niveau 0 | 1.2636 | 0.155132 | 0.310264 | 0.0044226
369794 | Niveau 0 | 0.647 | 0.08114 | 0.15878 | 0.0022645
369795 | Niveau 0 | 1.2636 | 0.155132 | 0.310264 | 0.0044226
369796 | Niveau 0 | 1.1236 | 0.138332 | 0.276664 | 0.0039326
369797 | Niveau 0 | 1.1236 | 0.138332 | 0.276664 | 0.0039326
369798 | Niveau 0 | 1.504 | 0.18398 | 0.36096 | 0.005264
369799 | Niveau 0 | 0.459 | 0.05858 | 0.11366 | 0.0016065
369800 | Niveau 0 | 0.647 | 0.08114 | 0.15878 | 0.0022645
369801 | Niveau 0 | 1.504 | 0.18398 | 0.36096 | 0.005264
369855 | Niveau 0 | 0.459 | 0.05858 | 0.11366 | 0.0016065
369856 | Niveau 0 | 1.2 | 0.1475 | 0.295 | 0.0042
369857 | Niveau 0 | 0.647 | 0.08114 | 0.15878 | 0.0022645
369858 | Niveau 0 | 1.2 | 0.1475 | 0.295 | 0.0042
369859 | Niveau 0 | 1.06 | 0.1307 | 0.2614 | 0.00371
369860 | Niveau 0 | 1.06 | 0.1307 | 0.2614 | 0.00371
369861 | Niveau 0 | 1.504 | 0.18398 | 0.36096 | 0.005264
369862 | Niveau 0 | 0.459 | 0.05858 | 0.11366 | 0.0016065
369863 | Niveau 0 | 0.647 | 0.08114 | 0.15878 | 0.0022645
369864 | Niveau 0 | 1.504 | 0.18398 | 0.36096 | 0.005264
369878 | Niveau 0 | 0.459 | 0.05858 | 0.11366 | 0.0016065
369879 | Niveau 0 | 1.2 | 0.1475 | 0.295 | 0.0042
369880 | Niveau 0 | 0.647 | 0.08114 | 0.15878 | 0.0022645
369881 | Niveau 0 | 1.2 | 0.1475 | 0.295 | 0.0042
369882 | Niveau 0 | 1.06 | 0.1307 | 0.2614 | 0.00371
369883 | Niveau 0 | 1.06 | 0.1307 | 0.2614 | 0.00371
369884 | Niveau 0 | 1.504 | 0.18398 | 0.36096 | 0.005264
369885 | Niveau 0 | 0.459 | 0.05858 | 0.11366 | 0.0016065
369886 | Niveau 0 | 0.647 | 0.08114 | 0.15878 | 0.0022645
369887 | Niveau 0 | 1.504 | 0.18398 | 0.36096 | 0.005264
369901 | Niveau 0 | 0.459 | 0.05858 | 0.11366 | 0.0016065
369902 | Niveau 0 | 1.2 | 0.1475 | 0.295 | 0.0042
369903 | Niveau 0 | 0.647 | 0.08114 | 0.15878 | 0.0022645
369904 | Niveau 0 | 1.2 | 0.1475 | 0.295 | 0.0042
369905 | Niveau 0 | 1.06 | 0.1307 | 0.2614 | 0.00371
369906 | Niveau 0 | 1.06 | 0.1307 | 0.2614 | 0.00371
369907 | Niveau 0 | 1.504 | 0.18398 | 0.36096 | 0.005264
369908 | Niveau 0 | 0.459 | 0.05858 | 0.11366 | 0.0016065
369909 | Niveau 0 | 0.647 | 0.08114 | 0.15878 | 0.0022645
369910 | Niveau 0 | 1.504 | 0.18398 | 0.36096 | 0.005264
369924 | Niveau 0 | 0.459 | 0.05858 | 0.11366 | 0.0016065
369925 | Niveau 0 | 1.2 | 0.1475 | 0.295 | 0.0042
369926 | Niveau 0 | 0.647 | 0.08114 | 0.15878 | 0.0022645
369927 | Niveau 0 | 1.2 | 0.1475 | 0.295 | 0.0042
369928 | Niveau 0 | 1.06 | 0.1307 | 0.2614 | 0.00371
369929 | Niveau 0 | 1.06 | 0.1307 | 0.2614 | 0.00371
369930 | Niveau 0 | 1.504 | 0.18398 | 0.36096 | 0.005264
369931 | Niveau 0 | 0.459 | 0.05858 | 0.11366 | 0.0016065
369932 | Niveau 0 | 0.647 | 0.08114 | 0.15878 | 0.0022645
369933 | Niveau 0 | 1.504 | 0.18398 | 0.36096 | 0.005264
369947 | Niveau 0 | 0.459 | 0.05858 | 0.11366 | 0.0016065
369948 | Niveau 0 | 1.2 | 0.1475 | 0.295 | 0.0042
369949 | Niveau 0 | 0.647 | 0.08114 | 0.15878 | 0.0022645
369950 | Niveau 0 | 1.2 | 0.1475 | 0.295 | 0.0042
369951 | Niveau 0 | 1.06 | 0.1307 | 0.2614 | 0.00371
369952 | Niveau 0 | 1.06 | 0.1307 | 0.2614 | 0.00371
369953 | Niveau 0 | 1.504 | 0.18398 | 0.36096 | 0.005264
369954 | Niveau 0 | 0.459 | 0.05858 | 0.11366 | 0.0016065
369955 | Niveau 0 | 0.647 | 0.08114 | 0.15878 | 0.0022645
369956 | Niveau 0 | 1.504 | 0.18398 | 0.36096 | 0.005264
369970 | Niveau 0 | 0.459 | 0.05858 | 0.11366 | 0.0016065
369971 | Niveau 0 | 1.2 | 0.1475 | 0.295 | 0.0042
369972 | Niveau 0 | 0.647 | 0.08114 | 0.15878 | 0.0022645
369973 | Niveau 0 | 1.2 | 0.1475 | 0.295 | 0.0042
369974 | Niveau 0 | 1.06 | 0.1307 | 0.2614 | 0.00371
369975 | Niveau 0 | 1.06 | 0.1307 | 0.2614 | 0.00371
369976 | Niveau 0 | 1.504 | 0.18398 | 0.36096 | 0.005264
369977 | Niveau 0 | 0.459 | 0.05858 | 0.11366 | 0.0016065
369978 | Niveau 0 | 0.647 | 0.08114 | 0.15878 | 0.0022645
369979 | Niveau 0 | 1.504 | 0.18398 | 0.36096 | 0.005264
369993 | Niveau 0 | 0.459 | 0.05858 | 0.11366 | 0.0016065
369994 | Niveau 0 | 1.2 | 0.1475 | 0.295 | 0.0042
369995 | Niveau 0 | 0.647 | 0.08114 | 0.15878 | 0.0022645
369996 | Niveau 0 | 1.2 | 0.1475 | 0.295 | 0.0042
369997 | Niveau 0 | 1.06 | 0.1307 | 0.2614 | 0.00371
369998 | Niveau 0 | 1.06 | 0.1307 | 0.2614 | 0.00371
369999 | Niveau 0 | 1.504 | 0.18398 | 0.36096 | 0.005264
370000 | Niveau 0 | 0.459 | 0.05858 | 0.11366 | 0.0016065
370001 | Niveau 0 | 0.647 | 0.08114 | 0.15878 | 0.0022645
370002 | Niveau 0 | 1.504 | 0.18398 | 0.36096 | 0.005264
370016 | Niveau 0 | 0.459 | 0.05858 | 0.11366 | 0.0016065
370017 | Niveau 0 | 1.2 | 0.1475 | 0.295 | 0.0042
370018 | Niveau 0 | 0.647 | 0.08114 | 0.15878 | 0.0022645
370019 | Niveau 0 | 1.2 | 0.1475 | 0.295 | 0.0042
370020 | Niveau 0 | 1.06 | 0.1307 | 0.2614 | 0.00371
370021 | Niveau 0 | 1.06 | 0.1307 | 0.2614 | 0.00371
370022 | Niveau 0 | 1.504 | 0.18398 | 0.36096 | 0.005264
370023 | Niveau 0 | 0.459 | 0.05858 | 0.11366 | 0.0016065
370024 | Niveau 0 | 0.647 | 0.08114 | 0.15878 | 0.0022645
370025 | Niveau 0 | 1.504 | 0.18398 | 0.36096 | 0.005264
370039 | Niveau 0 | 0.459 | 0.05858 | 0.11366 | 0.0016065
370040 | Niveau 0 | 1.16113 | 0.142835 | 0.28567 | 0.00406394
370041 | Niveau 0 | 0.647 | 0.08114 | 0.15878 | 0.0022645
370042 | Niveau 0 | 1.16113 | 0.142835 | 0.28567 | 0.00406394
370043 | Niveau 0 | 1.02113 | 0.126035 | 0.25207 | 0.00357394
370044 | Niveau 0 | 1.02113 | 0.126035 | 0.25207 | 0.00357394
370045 | Niveau 0 | 1.504 | 0.18398 | 0.36096 | 0.005264
370046 | Niveau 0 | 0.459 | 0.05858 | 0.11366 | 0.0016065
370047 | Niveau 0 | 0.647 | 0.08114 | 0.15878 | 0.0022645
370048 | Niveau 0 | 1.504 | 0.18398 | 0.36096 | 0.005264
388490 | Niveau 0 | 0.951266 | 0.117652 | 0.231804 | 0.00332943
388491 | Niveau 0 | 1.18133 | 0.145259 | 0.287019 | 0.00413465
388492 | Niveau 0 | 0.32 | 0.0419 | 0.0803 | 0.00112
388493 | Niveau 0 | 1.24173 | 0.152508 | 0.301515 | 0.00434606
388494 | Niveau 0 | 1.13673 | 0.139908 | 0.279815 | 0.00397856
388495 | Niveau 0 | 1.07633 | 0.132659 | 0.265319 | 0.00376715
388496 | Niveau 0 | 1.10489 | 0.136087 | 0.272174 | 0.00386712
388497 | Niveau 0 | 0.32 | 0.0419 | 0.0803 | 0.00112
388498 | Niveau 0 | 0.32 | 0.0419 | 0.0803 | 0.00112
388499 | Niveau 0 | 1.18133 | 0.145259 | 0.287019 | 0.00413465
388500 | Niveau 0 | 1.17489 | 0.144487 | 0.281974 | 0.00411212
388501 | Niveau 0 | 0.951266 | 0.117652 | 0.231804 | 0.00332943
388502 | Niveau 0 | 1.17489 | 0.144487 | 0.281974 | 0.00411212
388503 | Niveau 0 | 1.24173 | 0.152508 | 0.301515 | 0.00434606
388504 | Niveau 0 | 0.32 | 0.0419 | 0.0803 | 0.00112
388505 | Niveau 0 | 0.951266 | 0.117652 | 0.231804 | 0.00332943
388506 | Niveau 0 | 0.951266 | 0.117652 | 0.231804 | 0.00332943
392102 | Niveau 0 | 0.983266 | 0.121492 | 0.239484 | 0.00344143
392103 | Niveau 0 | 1.128 | 0.13886 | 0.27422 | 0.003948
392104 | Niveau 0 | 0.288 | 0.03806 | 0.07262 | 0.001008
392105 | Niveau 0 | 1.33564 | 0.163777 | 0.324055 | 0.00467475
392106 | Niveau 0 | 0.288 | 0.03806 | 0.07262 | 0.001008
392107 | Niveau 0 | 0.288 | 0.03806 | 0.07262 | 0.001008
392108 | Niveau 0 | 1.23064 | 0.151177 | 0.302355 | 0.00430725
392109 | Niveau 0 | 1.023 | 0.12626 | 0.25252 | 0.0035805
392110 | Niveau 0 | 1.27764 | 0.156817 | 0.313635 | 0.00447175
392111 | Niveau 0 | 1.128 | 0.13886 | 0.27422 | 0.003948
392112 | Niveau 0 | 1.34764 | 0.165217 | 0.323435 | 0.00471675
392113 | Niveau 0 | 0.983266 | 0.121492 | 0.239484 | 0.00344143
392114 | Niveau 0 | 1.34764 | 0.165217 | 0.323435 | 0.00471675
392115 | Niveau 0 | 1.33564 | 0.163777 | 0.324055 | 0.00467475
392116 | Niveau 0 | 0.288 | 0.03806 | 0.07262 | 0.001008
392117 | Niveau 0 | 0.983266 | 0.121492 | 0.239484 | 0.00344143
392118 | Niveau 0 | 0.983266 | 0.121492 | 0.239484 | 0.00344143
392169 | Niveau 0 | 0.983266 | 0.121492 | 0.239484 | 0.00344143
392170 | Niveau 0 | 1.2425 | 0.1526 | 0.3017 | 0.00434875
392171 | Niveau 0 | 0.288 | 0.03806 | 0.07262 | 0.001008
392172 | Niveau 0 | 1.2425 | 0.1526 | 0.3017 | 0.00434875
392175 | Niveau 0 | 1.1375 | 0.14 | 0.28 | 0.00398125
392180 | Niveau 0 | 0.983266 | 0.121492 | 0.239484 | 0.00344143
392183 | Niveau 0 | 0.288 | 0.03806 | 0.07262 | 0.001008
392394 | Niveau 0 | 1.2425 | 0.1526 | 0.3017 | 0.00434875
392395 | Niveau 0 | 1.2425 | 0.1526 | 0.3017 | 0.00434875
392396 | Niveau 0 | 1.1375 | 0.14 | 0.28 | 0.00398125
392420 | Niveau 0 | 0.983266 | 0.121492 | 0.239484 | 0.00344143
392421 | Niveau 0 | 0.288 | 0.03806 | 0.07262 | 0.001008
511214 | Niveau 1 | 1.22588 | 0.150606 | 0.301212 | 0.0042906
511215 | Niveau 1 | 0.278 | 0.03686 | 0.07022 | 0.000973
511216 | Niveau 1 | 1.22588 | 0.150606 | 0.301212 | 0.0042906
511217 | Niveau 1 | 1.08588 | 0.133806 | 0.267612 | 0.0038006
511218 | Niveau 1 | 1.46086 | 0.178803 | 0.354107 | 0.00511301
511219 | Niveau 1 | 0.313 | 0.04106 | 0.08212 | 0.0010955
511224 | Niveau 1 | 1.2 | 0.1475 | 0.295 | 0.0042
511225 | Niveau 1 | 0.278 | 0.03686 | 0.07022 | 0.000973
511226 | Niveau 1 | 1.2 | 0.1475 | 0.295 | 0.0042
511227 | Niveau 1 | 1.06 | 0.1307 | 0.2614 | 0.00371
511228 | Niveau 1 | 1.46086 | 0.178803 | 0.354107 | 0.00511301
511229 | Niveau 1 | 0.313 | 0.04106 | 0.08212 | 0.0010955
511234 | Niveau 1 | 1.2 | 0.1475 | 0.295 | 0.0042
511235 | Niveau 1 | 0.278 | 0.03686 | 0.07022 | 0.000973
511236 | Niveau 1 | 1.2 | 0.1475 | 0.295 | 0.0042
511237 | Niveau 1 | 1.06 | 0.1307 | 0.2614 | 0.00371
511238 | Niveau 1 | 1.46086 | 0.178803 | 0.354107 | 0.00511301
511239 | Niveau 1 | 0.313 | 0.04106 | 0.08212 | 0.0010955
511244 | Niveau 1 | 1.2 | 0.1475 | 0.295 | 0.0042
511245 | Niveau 1 | 0.278 | 0.03686 | 0.07022 | 0.000973
511246 | Niveau 1 | 1.2 | 0.1475 | 0.295 | 0.0042
511247 | Niveau 1 | 1.06 | 0.1307 | 0.2614 | 0.00371
511248 | Niveau 1 | 1.46086 | 0.178803 | 0.354107 | 0.00511301
511249 | Niveau 1 | 0.313 | 0.04106 | 0.08212 | 0.0010955
511254 | Niveau 1 | 1.2 | 0.1475 | 0.295 | 0.0042
511255 | Niveau 1 | 0.278 | 0.03686 | 0.07022 | 0.000973
511256 | Niveau 1 | 1.2 | 0.1475 | 0.295 | 0.0042
511257 | Niveau 1 | 1.06 | 0.1307 | 0.2614 | 0.00371
511258 | Niveau 1 | 1.46086 | 0.178803 | 0.354107 | 0.00511301
511259 | Niveau 1 | 0.313 | 0.04106 | 0.08212 | 0.0010955
511264 | Niveau 1 | 1.2 | 0.1475 | 0.295 | 0.0042
511265 | Niveau 1 | 0.278 | 0.03686 | 0.07022 | 0.000973
511266 | Niveau 1 | 1.2 | 0.1475 | 0.295 | 0.0042
511267 | Niveau 1 | 1.06 | 0.1307 | 0.2614 | 0.00371
511268 | Niveau 1 | 1.46086 | 0.178803 | 0.354107 | 0.00511301
511269 | Niveau 1 | 0.313 | 0.04106 | 0.08212 | 0.0010955
511274 | Niveau 1 | 1.08113 | 0.133235 | 0.26647 | 0.00378394
511275 | Niveau 1 | 0.278 | 0.03686 | 0.07022 | 0.000973
511276 | Niveau 1 | 1.08113 | 0.133235 | 0.26647 | 0.00378394
511277 | Niveau 1 | 0.941126 | 0.116435 | 0.23287 | 0.00329394
511278 | Niveau 1 | 1.46086 | 0.178803 | 0.354107 | 0.00511301
511279 | Niveau 1 | 0.313 | 0.04106 | 0.08212 | 0.0010955
511284 | Niveau 1 | 1.2 | 0.1475 | 0.295 | 0.0042
511285 | Niveau 1 | 0.278 | 0.03686 | 0.07022 | 0.000973
511286 | Niveau 1 | 1.2 | 0.1475 | 0.295 | 0.0042
511287 | Niveau 1 | 1.06 | 0.1307 | 0.2614 | 0.00371
511288 | Niveau 1 | 1.46086 | 0.178803 | 0.354107 | 0.00511301
511289 | Niveau 1 | 0.313 | 0.04106 | 0.08212 | 0.0010955
511294 | Niveau 1 | 1.2 | 0.1475 | 0.295 | 0.0042
511295 | Niveau 1 | 0.278 | 0.03686 | 0.07022 | 0.000973
511296 | Niveau 1 | 1.2 | 0.1475 | 0.295 | 0.0042
511297 | Niveau 1 | 1.06 | 0.1307 | 0.2614 | 0.00371
511298 | Niveau 1 | 1.46086 | 0.178803 | 0.354107 | 0.00511301
511299 | Niveau 1 | 0.313 | 0.04106 | 0.08212 | 0.0010955
511304 | Niveau 1 | 1.2 | 0.1475 | 0.295 | 0.0042
511305 | Niveau 1 | 0.278 | 0.03686 | 0.07022 | 0.000973
511306 | Niveau 1 | 1.2 | 0.1475 | 0.295 | 0.0042
511307 | Niveau 1 | 1.06 | 0.1307 | 0.2614 | 0.00371
511308 | Niveau 1 | 1.46086 | 0.178803 | 0.354107 | 0.00511301
511309 | Niveau 1 | 0.313 | 0.04106 | 0.08212 | 0.0010955
511314 | Niveau 1 | 1.23219 | 0.151363 | 0.302726 | 0.00431267
511315 | Niveau 1 | 0.278 | 0.03686 | 0.07022 | 0.000973
511316 | Niveau 1 | 1.23219 | 0.151363 | 0.302726 | 0.00431267
511317 | Niveau 1 | 1.09219 | 0.134563 | 0.269126 | 0.00382267
511318 | Niveau 1 | 1.46086 | 0.178803 | 0.354107 | 0.00511301
511319 | Niveau 1 | 0.313 | 0.04106 | 0.08212 | 0.0010955
511324 | Niveau 1 | 1.2 | 0.1475 | 0.295 | 0.0042
511325 | Niveau 1 | 0.278 | 0.03686 | 0.07022 | 0.000973
511326 | Niveau 1 | 1.2 | 0.1475 | 0.295 | 0.0042
511327 | Niveau 1 | 1.06 | 0.1307 | 0.2614 | 0.00371
511328 | Niveau 1 | 1.46086 | 0.178803 | 0.354107 | 0.00511301
511329 | Niveau 1 | 0.313 | 0.04106 | 0.08212 | 0.0010955
511334 | Niveau 1 | 1.28865 | 0.155863 | 0.311727 | 0.00442279
511335 | Niveau 1 | 0.278 | 0.03686 | 0.07022 | 0.000973
511336 | Niveau 1 | 1.28865 | 0.155863 | 0.311727 | 0.00442279
511337 | Niveau 1 | 1.09865 | 0.135339 | 0.270677 | 0.00384529
511338 | Niveau 1 | 1.46086 | 0.178803 | 0.354107 | 0.00511301
511339 | Niveau 1 | 0.313 | 0.04106 | 0.08212 | 0.0010955
511344 | Niveau 1 | 1.2 | 0.1475 | 0.295 | 0.0042
511345 | Niveau 1 | 0.278 | 0.03686 | 0.07022 | 0.000973
511346 | Niveau 1 | 1.2 | 0.1475 | 0.295 | 0.0042
511347 | Niveau 1 | 1.06 | 0.1307 | 0.2614 | 0.00371
511348 | Niveau 1 | 1.46086 | 0.178803 | 0.354107 | 0.00511301
511349 | Niveau 1 | 0.313 | 0.04106 | 0.08212 | 0.0010955
512592 | Niveau 1 | 1.46086 | 0.178803 | 0.354107 | 0.00511301
512593 | Niveau 1 | 1.29568 | 0.156706 | 0.313413 | 0.00444738
512594 | Niveau 1 | 0.278 | 0.03686 | 0.07022 | 0.000973
512595 | Niveau 1 | 1.29568 | 0.156706 | 0.313413 | 0.00444738
512596 | Niveau 1 | 1.10568 | 0.136182 | 0.272363 | 0.00386988
512597 | Niveau 1 | 1.46086 | 0.178803 | 0.354107 | 0.00511301
512598 | Niveau 1 | 0.278 | 0.03686 | 0.07022 | 0.000973
512769 | Niveau 1 | 1.46086 | 0.178803 | 0.354107 | 0.00511301
512770 | Niveau 1 | 1.2 | 0.1475 | 0.295 | 0.0042
512771 | Niveau 1 | 0.278 | 0.03686 | 0.07022 | 0.000973
512772 | Niveau 1 | 1.2 | 0.1475 | 0.295 | 0.0042
512773 | Niveau 1 | 1.06 | 0.1307 | 0.2614 | 0.00371
512774 | Niveau 1 | 1.46086 | 0.178803 | 0.354107 | 0.00511301
512775 | Niveau 1 | 0.278 | 0.03686 | 0.07022 | 0.000973
512997 | Niveau 1 | 1.46086 | 0.178803 | 0.354107 | 0.00511301
512998 | Niveau 1 | 1.21702 | 0.149542 | 0.299084 | 0.00425956
512999 | Niveau 1 | 0.278 | 0.03686 | 0.07022 | 0.000973
513000 | Niveau 1 | 1.21702 | 0.149542 | 0.299084 | 0.00425956
513001 | Niveau 1 | 1.07702 | 0.132742 | 0.265484 | 0.00376956
513002 | Niveau 1 | 1.46086 | 0.178803 | 0.354107 | 0.00511301
513003 | Niveau 1 | 0.278 | 0.03686 | 0.07022 | 0.000973
513013 | Niveau 1 | 1.46086 | 0.178803 | 0.354107 | 0.00511301
513014 | Niveau 1 | 1.26298 | 0.155058 | 0.310116 | 0.00442044
513015 | Niveau 1 | 0.278 | 0.03686 | 0.07022 | 0.000973
513016 | Niveau 1 | 1.26298 | 0.155058 | 0.310116 | 0.00442044
513017 | Niveau 1 | 1.12298 | 0.138258 | 0.276516 | 0.00393044
513018 | Niveau 1 | 1.46086 | 0.178803 | 0.354107 | 0.00511301
513019 | Niveau 1 | 0.278 | 0.03686 | 0.07022 | 0.000973
513029 | Niveau 1 | 1.46086 | 0.178803 | 0.354107 | 0.00511301
513030 | Niveau 1 | 1.2 | 0.1475 | 0.295 | 0.0042
513031 | Niveau 1 | 0.278 | 0.03686 | 0.07022 | 0.000973
513032 | Niveau 1 | 1.2 | 0.1475 | 0.295 | 0.0042
513033 | Niveau 1 | 1.06 | 0.1307 | 0.2614 | 0.00371
513034 | Niveau 1 | 1.46086 | 0.178803 | 0.354107 | 0.00511301
513035 | Niveau 1 | 0.278 | 0.03686 | 0.07022 | 0.000973
513045 | Niveau 1 | 1.46086 | 0.178803 | 0.354107 | 0.00511301
513046 | Niveau 1 | 1.23428 | 0.151613 | 0.303226 | 0.00431997
513047 | Niveau 1 | 0.278 | 0.03686 | 0.07022 | 0.000973
513048 | Niveau 1 | 1.23428 | 0.151613 | 0.303226 | 0.00431997
513049 | Niveau 1 | 1.09428 | 0.134813 | 0.269626 | 0.00382997
513050 | Niveau 1 | 1.46086 | 0.178803 | 0.354107 | 0.00511301
513051 | Niveau 1 | 0.278 | 0.03686 | 0.07022 | 0.000973
513061 | Niveau 1 | 1.46086 | 0.178803 | 0.354107 | 0.00511301
513062 | Niveau 1 | 1.26572 | 0.155387 | 0.310774 | 0.00443003
513063 | Niveau 1 | 0.278 | 0.03686 | 0.07022 | 0.000973
513064 | Niveau 1 | 1.26572 | 0.155387 | 0.310774 | 0.00443003
513065 | Niveau 1 | 1.12572 | 0.138587 | 0.277174 | 0.00394003
513066 | Niveau 1 | 1.46086 | 0.178803 | 0.354107 | 0.00511301
513067 | Niveau 1 | 0.278 | 0.03686 | 0.07022 | 0.000973
513077 | Niveau 1 | 1.46086 | 0.178803 | 0.354107 | 0.00511301
513078 | Niveau 1 | 1.2 | 0.1475 | 0.295 | 0.0042
513079 | Niveau 1 | 0.278 | 0.03686 | 0.07022 | 0.000973
513080 | Niveau 1 | 1.2 | 0.1475 | 0.295 | 0.0042
513081 | Niveau 1 | 1.06 | 0.1307 | 0.2614 | 0.00371
513082 | Niveau 1 | 1.46086 | 0.178803 | 0.354107 | 0.00511301
513083 | Niveau 1 | 0.278 | 0.03686 | 0.07022 | 0.000973
513093 | Niveau 1 | 1.46086 | 0.178803 | 0.354107 | 0.00511301
513094 | Niveau 1 | 1.21728 | 0.149573 | 0.299146 | 0.00426046
513095 | Niveau 1 | 0.278 | 0.03686 | 0.07022 | 0.000973
513096 | Niveau 1 | 1.21728 | 0.149573 | 0.299146 | 0.00426046
513097 | Niveau 1 | 1.07728 | 0.132773 | 0.265546 | 0.00377046
513098 | Niveau 1 | 1.46086 | 0.178803 | 0.354107 | 0.00511301
513099 | Niveau 1 | 0.278 | 0.03686 | 0.07022 | 0.000973
513109 | Niveau 1 | 1.46086 | 0.178803 | 0.354107 | 0.00511301
513110 | Niveau 1 | 1.30272 | 0.159827 | 0.319654 | 0.00455954
513111 | Niveau 1 | 0.278 | 0.03686 | 0.07022 | 0.000973
513112 | Niveau 1 | 1.30272 | 0.159827 | 0.319654 | 0.00455954
513113 | Niveau 1 | 1.16272 | 0.143027 | 0.286054 | 0.00406954
513114 | Niveau 1 | 1.46086 | 0.178803 | 0.354107 | 0.00511301
513115 | Niveau 1 | 0.278 | 0.03686 | 0.07022 | 0.000973
513125 | Niveau 1 | 1.46086 | 0.178803 | 0.354107 | 0.00511301
513126 | Niveau 1 | 1.2 | 0.1475 | 0.295 | 0.0042
513127 | Niveau 1 | 0.278 | 0.03686 | 0.07022 | 0.000973
513128 | Niveau 1 | 1.2 | 0.1475 | 0.295 | 0.0042
513129 | Niveau 1 | 1.06 | 0.1307 | 0.2614 | 0.00371
513130 | Niveau 1 | 1.46086 | 0.178803 | 0.354107 | 0.00511301
513131 | Niveau 1 | 0.278 | 0.03686 | 0.07022 | 0.000973
513141 | Niveau 1 | 1.46086 | 0.178803 | 0.354107 | 0.00511301
513142 | Niveau 1 | 1.2 | 0.1475 | 0.295 | 0.0042
513143 | Niveau 1 | 0.278 | 0.03686 | 0.07022 | 0.000973
513144 | Niveau 1 | 1.2 | 0.1475 | 0.295 | 0.0042
513145 | Niveau 1 | 1.06 | 0.1307 | 0.2614 | 0.00371
513146 | Niveau 1 | 1.46086 | 0.178803 | 0.354107 | 0.00511301
513147 | Niveau 1 | 0.278 | 0.03686 | 0.07022 | 0.000973
513157 | Niveau 1 | 1.46086 | 0.178803 | 0.354107 | 0.00511301
513158 | Niveau 1 | 1.21 | 0.1487 | 0.2974 | 0.004235
513159 | Niveau 1 | 0.278 | 0.03686 | 0.07022 | 0.000973
513160 | Niveau 1 | 1.21 | 0.1487 | 0.2974 | 0.004235
513161 | Niveau 1 | 1.07 | 0.1319 | 0.2638 | 0.003745
513162 | Niveau 1 | 1.46086 | 0.178803 | 0.354107 | 0.00511301
513163 | Niveau 1 | 0.278 | 0.03686 | 0.07022 | 0.000973
513173 | Niveau 1 | 1.46037 | 0.178744 | 0.353989 | 0.0051113
513174 | Niveau 1 | 1.265 | 0.1553 | 0.3106 | 0.0044275
513175 | Niveau 1 | 0.954 | 0.11798 | 0.23246 | 0.003339
513176 | Niveau 1 | 1.265 | 0.1553 | 0.3106 | 0.0044275
513177 | Niveau 1 | 1.125 | 0.1385 | 0.277 | 0.0039375
513178 | Niveau 1 | 1.46037 | 0.178744 | 0.353989 | 0.0051113
513179 | Niveau 1 | 0.954 | 0.11798 | 0.23246 | 0.003339
513189 | Niveau 1 | 1.46037 | 0.178744 | 0.353989 | 0.0051113
513190 | Niveau 1 | 1.2 | 0.1475 | 0.295 | 0.0042
513191 | Niveau 1 | 0.954 | 0.11798 | 0.23246 | 0.003339
513192 | Niveau 1 | 1.2 | 0.1475 | 0.295 | 0.0042
513193 | Niveau 1 | 1.06 | 0.1307 | 0.2614 | 0.00371
513194 | Niveau 1 | 1.46037 | 0.178744 | 0.353989 | 0.0051113
513195 | Niveau 1 | 0.954 | 0.11798 | 0.23246 | 0.003339
513205 | Niveau 1 | 1.46037 | 0.178744 | 0.353989 | 0.0051113
513206 | Niveau 1 | 1.2 | 0.1475 | 0.295 | 0.0042
513207 | Niveau 1 | 0.954 | 0.11798 | 0.23246 | 0.003339
513208 | Niveau 1 | 1.2 | 0.1475 | 0.295 | 0.0042
513209 | Niveau 1 | 1.06 | 0.1307 | 0.2614 | 0.00371
513210 | Niveau 1 | 1.46037 | 0.178744 | 0.353989 | 0.0051113
513211 | Niveau 1 | 0.954 | 0.11798 | 0.23246 | 0.003339
518369 | Niveau 1 | 1.11256 | 0.137007 | 0.274015 | 0.00389396
518370 | Niveau 1 | 1.46086 | 0.178803 | 0.354107 | 0.00511301
518371 | Niveau 1 | 1.25256 | 0.153807 | 0.307615 | 0.00438396
518372 | Niveau 1 | 0.278 | 0.03686 | 0.07022 | 0.000973
518373 | Niveau 1 | 1.25256 | 0.153807 | 0.307615 | 0.00438396
518374 | Niveau 1 | 1.46086 | 0.178803 | 0.354107 | 0.00511301
518375 | Niveau 1 | 0.278 | 0.03686 | 0.07022 | 0.000973
518440 | Niveau 1 | 1.06 | 0.1307 | 0.2614 | 0.00371
518441 | Niveau 1 | 1.46086 | 0.178803 | 0.354107 | 0.00511301
518442 | Niveau 1 | 1.2 | 0.1475 | 0.295 | 0.0042
518443 | Niveau 1 | 0.278 | 0.03686 | 0.07022 | 0.000973
518444 | Niveau 1 | 1.2 | 0.1475 | 0.295 | 0.0042
518445 | Niveau 1 | 1.46086 | 0.178803 | 0.354107 | 0.00511301
518446 | Niveau 1 | 0.278 | 0.03686 | 0.07022 | 0.000973
518561 | Niveau 1 | 1.06 | 0.1307 | 0.2614 | 0.00371
518562 | Niveau 1 | 1.46086 | 0.178803 | 0.354107 | 0.00511301
518563 | Niveau 1 | 1.2 | 0.1475 | 0.295 | 0.0042
518564 | Niveau 1 | 0.278 | 0.03686 | 0.07022 | 0.000973
518565 | Niveau 1 | 1.2 | 0.1475 | 0.295 | 0.0042
518566 | Niveau 1 | 1.46086 | 0.178803 | 0.354107 | 0.00511301
518567 | Niveau 1 | 0.278 | 0.03686 | 0.07022 | 0.000973
518579 | Niveau 1 | 1.06 | 0.1307 | 0.2614 | 0.00371
518580 | Niveau 1 | 1.46086 | 0.178803 | 0.354107 | 0.00511301
518581 | Niveau 1 | 1.2 | 0.1475 | 0.295 | 0.0042
518582 | Niveau 1 | 0.278 | 0.03686 | 0.07022 | 0.000973
518583 | Niveau 1 | 1.2 | 0.1475 | 0.295 | 0.0042
518584 | Niveau 1 | 1.46086 | 0.178803 | 0.354107 | 0.00511301
518585 | Niveau 1 | 0.278 | 0.03686 | 0.07022 | 0.000973
518597 | Niveau 1 | 1.06 | 0.1307 | 0.2614 | 0.00371
518598 | Niveau 1 | 1.46086 | 0.178803 | 0.354107 | 0.00511301
518599 | Niveau 1 | 1.2 | 0.1475 | 0.295 | 0.0042
518600 | Niveau 1 | 0.278 | 0.03686 | 0.07022 | 0.000973
518601 | Niveau 1 | 1.2 | 0.1475 | 0.295 | 0.0042
518602 | Niveau 1 | 1.46086 | 0.178803 | 0.354107 | 0.00511301
518603 | Niveau 1 | 0.278 | 0.03686 | 0.07022 | 0.000973
518615 | Niveau 1 | 1.08165 | 0.133298 | 0.266595 | 0.00378576
518616 | Niveau 1 | 1.46086 | 0.178803 | 0.354107 | 0.00511301
518617 | Niveau 1 | 1.22165 | 0.150098 | 0.300195 | 0.00427576
518618 | Niveau 1 | 0.278 | 0.03686 | 0.07022 | 0.000973
518619 | Niveau 1 | 1.22165 | 0.150098 | 0.300195 | 0.00427576
518620 | Niveau 1 | 1.46086 | 0.178803 | 0.354107 | 0.00511301
518621 | Niveau 1 | 0.278 | 0.03686 | 0.07022 | 0.000973
518631 | Niveau 1 | 1.06 | 0.1307 | 0.2614 | 0.00371
518632 | Niveau 1 | 1.46086 | 0.178803 | 0.354107 | 0.00511301
518633 | Niveau 1 | 1.2 | 0.1475 | 0.295 | 0.0042
518634 | Niveau 1 | 0.278 | 0.03686 | 0.07022 | 0.000973
518635 | Niveau 1 | 1.2 | 0.1475 | 0.295 | 0.0042
518636 | Niveau 1 | 1.46086 | 0.178803 | 0.354107 | 0.00511301
518637 | Niveau 1 | 0.278 | 0.03686 | 0.07022 | 0.000973
518649 | Niveau 1 | 1.06 | 0.1307 | 0.2614 | 0.00371
518650 | Niveau 1 | 1.46086 | 0.178803 | 0.354107 | 0.00511301
518651 | Niveau 1 | 1.2 | 0.1475 | 0.295 | 0.0042
518652 | Niveau 1 | 0.278 | 0.03686 | 0.07022 | 0.000973
518653 | Niveau 1 | 1.2 | 0.1475 | 0.295 | 0.0042
518654 | Niveau 1 | 1.46086 | 0.178803 | 0.354107 | 0.00511301
518655 | Niveau 1 | 0.278 | 0.03686 | 0.07022 | 0.000973
518667 | Niveau 1 | 1.06 | 0.1307 | 0.2614 | 0.00371
518668 | Niveau 1 | 1.46086 | 0.178803 | 0.354107 | 0.00511301
518669 | Niveau 1 | 1.2 | 0.1475 | 0.295 | 0.0042
518670 | Niveau 1 | 0.278 | 0.03686 | 0.07022 | 0.000973
518671 | Niveau 1 | 1.2 | 0.1475 | 0.295 | 0.0042
518672 | Niveau 1 | 1.46086 | 0.178803 | 0.354107 | 0.00511301
518673 | Niveau 1 | 0.278 | 0.03686 | 0.07022 | 0.000973
518685 | Niveau 1 | 1.05735 | 0.130382 | 0.260764 | 0.00370073
518686 | Niveau 1 | 1.46086 | 0.178803 | 0.354107 | 0.00511301
518687 | Niveau 1 | 1.19735 | 0.147182 | 0.294364 | 0.00419073
518688 | Niveau 1 | 0.278 | 0.03686 | 0.07022 | 0.000973
518689 | Niveau 1 | 1.19735 | 0.147182 | 0.294364 | 0.00419073
518690 | Niveau 1 | 1.46086 | 0.178803 | 0.354107 | 0.00511301
518691 | Niveau 1 | 0.278 | 0.03686 | 0.07022 | 0.000973
518703 | Niveau 1 | 1.06 | 0.1307 | 0.2614 | 0.00371
518704 | Niveau 1 | 1.46086 | 0.178803 | 0.354107 | 0.00511301
518705 | Niveau 1 | 1.2 | 0.1475 | 0.295 | 0.0042
518706 | Niveau 1 | 0.278 | 0.03686 | 0.07022 | 0.000973
518707 | Niveau 1 | 1.2 | 0.1475 | 0.295 | 0.0042
518708 | Niveau 1 | 1.46086 | 0.178803 | 0.354107 | 0.00511301
518709 | Niveau 1 | 0.278 | 0.03686 | 0.07022 | 0.000973
518721 | Niveau 1 | 1.06 | 0.1307 | 0.2614 | 0.00371
518722 | Niveau 1 | 1.46086 | 0.178803 | 0.354107 | 0.00511301
518723 | Niveau 1 | 1.2 | 0.1475 | 0.295 | 0.0042
518724 | Niveau 1 | 0.278 | 0.03686 | 0.07022 | 0.000973
518725 | Niveau 1 | 1.2 | 0.1475 | 0.295 | 0.0042
518726 | Niveau 1 | 1.46086 | 0.178803 | 0.354107 | 0.00511301
518727 | Niveau 1 | 0.278 | 0.03686 | 0.07022 | 0.000973
518739 | Niveau 1 | 1.06 | 0.1307 | 0.2614 | 0.00371
518740 | Niveau 1 | 1.46086 | 0.178803 | 0.354107 | 0.00511301
518741 | Niveau 1 | 1.2 | 0.1475 | 0.295 | 0.0042
518742 | Niveau 1 | 0.278 | 0.03686 | 0.07022 | 0.000973
518743 | Niveau 1 | 1.2 | 0.1475 | 0.295 | 0.0042
518744 | Niveau 1 | 1.46086 | 0.178803 | 0.354107 | 0.00511301
518745 | Niveau 1 | 0.278 | 0.03686 | 0.07022 | 0.000973
518757 | Niveau 1 | 1.06 | 0.1307 | 0.2614 | 0.00371
518758 | Niveau 1 | 1.46086 | 0.178803 | 0.354107 | 0.00511301
518759 | Niveau 1 | 1.2 | 0.1475 | 0.295 | 0.0042
518760 | Niveau 1 | 0.278 | 0.03686 | 0.07022 | 0.000973
518761 | Niveau 1 | 1.2 | 0.1475 | 0.295 | 0.0042
518762 | Niveau 1 | 1.46086 | 0.178803 | 0.354107 | 0.00511301
518763 | Niveau 1 | 0.278 | 0.03686 | 0.07022 | 0.000973
518775 | Niveau 1 | 1.06 | 0.1307 | 0.2614 | 0.00371
518776 | Niveau 1 | 1.46086 | 0.178803 | 0.354107 | 0.00511301
518777 | Niveau 1 | 1.2 | 0.1475 | 0.295 | 0.0042
518778 | Niveau 1 | 0.278 | 0.03686 | 0.07022 | 0.000973
518779 | Niveau 1 | 1.2 | 0.1475 | 0.295 | 0.0042
518780 | Niveau 1 | 1.46086 | 0.178803 | 0.354107 | 0.00511301
518781 | Niveau 1 | 0.278 | 0.03686 | 0.07022 | 0.000973
518829 | Niveau 1 | 1.2559 | 0.154208 | 0.308416 | 0.00439565
518830 | Niveau 1 | 1.46086 | 0.178803 | 0.354107 | 0.00511301
518831 | Niveau 1 | 1.3959 | 0.171008 | 0.342016 | 0.00488565
518832 | Niveau 1 | 0.278 | 0.03686 | 0.07022 | 0.000973
518833 | Niveau 1 | 1.3959 | 0.171008 | 0.342016 | 0.00488565
518834 | Niveau 1 | 1.46086 | 0.178803 | 0.354107 | 0.00511301
518835 | Niveau 1 | 0.278 | 0.03686 | 0.07022 | 0.000973
520106 | Niveau 1 | 2.80936 | 0.340624 | 0.681247 | 0.00983277
520107 | Niveau 1 | 2.47316 | 0.300279 | 0.600559 | 0.00865606
520108 | Niveau 1 | 2.80936 | 0.340624 | 0.681247 | 0.00983277
520109 | Niveau 1 | 2.47316 | 0.300279 | 0.600559 | 0.00865606
520136 | Niveau 1 | 2.80936 | 0.340624 | 0.681247 | 0.00983277
520137 | Niveau 1 | 2.49184 | 0.302521 | 0.605041 | 0.00872144
520138 | Niveau 1 | 2.80936 | 0.340624 | 0.681247 | 0.00983277
520139 | Niveau 1 | 2.49184 | 0.302521 | 0.605041 | 0.00872144
520129 | Niveau 1 | 2.80936 | 0.340624 | 0.681247 | 0.00983277
520130 | Niveau 1 | 0.854509 | 0.106041 | 0.212082 | 0.00299078
520131 | Niveau 1 | 2.80936 | 0.340624 | 0.681247 | 0.00983277
520132 | Niveau 1 | 0.854509 | 0.106041 | 0.212082 | 0.00299078
520122 | Niveau 1 | 2.80936 | 0.340624 | 0.681247 | 0.00983277
520123 | Niveau 1 | 2.46351 | 0.299121 | 0.598242 | 0.00862228
520124 | Niveau 1 | 2.80936 | 0.340624 | 0.681247 | 0.00983277
520125 | Niveau 1 | 2.46351 | 0.299121 | 0.598242 | 0.00862228
520115 | Niveau 1 | 2.80936 | 0.340624 | 0.681247 | 0.00983277
520116 | Niveau 1 | 0.858526 | 0.106523 | 0.213046 | 0.00300484
520117 | Niveau 1 | 2.80936 | 0.340624 | 0.681247 | 0.00983277
520118 | Niveau 1 | 0.858526 | 0.106523 | 0.213046 | 0.00300484
607867 | Niveau 2 | 1.53629 | 0.187854 | 0.375709 | 0.00537701
572407 | Niveau 2 | 0.96 | 0.1187 | 0.2339 | 0.00336
572408 | Niveau 2 | 1.041 | 0.12842 | 0.25334 | 0.0036435
572416 | Niveau 2 | 0.935 | 0.1157 | 0.2244 | 0.0032725
572417 | Niveau 2 | 0.286 | 0.03782 | 0.07214 | 0.001001
572418 | Niveau 2 | 1.041 | 0.12842 | 0.25334 | 0.0036435
572497 | Niveau 2 | 0.896 | 0.11102 | 0.21854 | 0.003136
572498 | Niveau 2 | 0.547 | 0.06914 | 0.13128 | 0.0019145
572499 | Niveau 2 | 2.431 | 0.29522 | 0.58344 | 0.0085085
572500 | Niveau 2 | 0.91255 | 0.113006 | 0.222512 | 0.00319392
572534 | Niveau 2 | 2.456 | 0.29822 | 0.59294 | 0.008596
572539 | Niveau 2 | 0.582 | 0.07334 | 0.14318 | 0.002037
579245 | Niveau 2 | 2.653 | 0.32186 | 0.64372 | 0.0092855
579246 | Niveau 2 | 3.04975 | 0.369469 | 0.738939 | 0.0106741
579250 | Niveau 2 | 3.01475 | 0.365269 | 0.727039 | 0.0105516
579251 | Niveau 2 | 1.012 | 0.12494 | 0.24288 | 0.003542
579252 | Niveau 2 | 2.583 | 0.31346 | 0.61992 | 0.0090405
579253 | Niveau 2 | 0.948 | 0.11726 | 0.23102 | 0.003318
579254 | Niveau 2 | 0.935 | 0.1157 | 0.2244 | 0.0032725
579255 | Niveau 2 | 0.286 | 0.03782 | 0.07214 | 0.001001
579256 | Niveau 2 | 1.041 | 0.12842 | 0.25334 | 0.0036435
579257 | Niveau 2 | 0.935 | 0.1157 | 0.2244 | 0.0032725
579258 | Niveau 2 | 0.286 | 0.03782 | 0.07214 | 0.001001
579259 | Niveau 2 | 1.041 | 0.12842 | 0.25334 | 0.0036435
579260 | Niveau 2 | 0.935 | 0.1157 | 0.2244 | 0.0032725
579261 | Niveau 2 | 0.286 | 0.03782 | 0.07214 | 0.001001
579262 | Niveau 2 | 1.041 | 0.12842 | 0.25334 | 0.0036435
579265 | Niveau 2 | 0.935 | 0.1157 | 0.2244 | 0.0032725
579266 | Niveau 2 | 0.286 | 0.03782 | 0.07214 | 0.001001
579267 | Niveau 2 | 1.111 | 0.13682 | 0.27014 | 0.0038885
580029 | Niveau 2 | 3.27888 | 0.396966 | 0.793932 | 0.0114761
580032 | Niveau 2 | 1.221 | 0.15002 | 0.29654 | 0.0042735
580036 | Niveau 2 | 1.041 | 0.12842 | 0.25334 | 0.0036435
580040 | Niveau 2 | 3.27888 | 0.396966 | 0.793932 | 0.0114761
580183 | Niveau 2 | 1.041 | 0.12842 | 0.25334 | 0.0036435
580184 | Niveau 2 | 1.221 | 0.15002 | 0.29654 | 0.0042735
589603 | Niveau 2 | 2.653 | 0.32186 | 0.64372 | 0.0092855
589604 | Niveau 2 | 3.101 | 0.37562 | 0.75124 | 0.0108535
589608 | Niveau 2 | 3.066 | 0.37142 | 0.73934 | 0.010731
589609 | Niveau 2 | 1 | 0.1235 | 0.24 | 0.0035
589610 | Niveau 2 | 2.583 | 0.31346 | 0.61992 | 0.0090405
589611 | Niveau 2 | 0.957609 | 0.118413 | 0.233326 | 0.00335163
589612 | Niveau 2 | 0.935 | 0.1157 | 0.2244 | 0.0032725
589613 | Niveau 2 | 0.286 | 0.03782 | 0.07214 | 0.001001
589614 | Niveau 2 | 1.041 | 0.12842 | 0.25334 | 0.0036435
589615 | Niveau 2 | 0.935 | 0.1157 | 0.2244 | 0.0032725
589616 | Niveau 2 | 0.286 | 0.03782 | 0.07214 | 0.001001
589617 | Niveau 2 | 1.041 | 0.12842 | 0.25334 | 0.0036435
589618 | Niveau 2 | 0.935 | 0.1157 | 0.2244 | 0.0032725
589619 | Niveau 2 | 0.286 | 0.03782 | 0.07214 | 0.001001
589620 | Niveau 2 | 1.041 | 0.12842 | 0.25334 | 0.0036435
589623 | Niveau 2 | 0.935 | 0.1157 | 0.2244 | 0.0032725
589624 | Niveau 2 | 0.286 | 0.03782 | 0.07214 | 0.001001
589625 | Niveau 2 | 1.111 | 0.13682 | 0.27014 | 0.0038885
590769 | Niveau 2 | 1.028 | 0.12686 | 0.24672 | 0.003598
590770 | Niveau 2 | 0.749 | 0.09338 | 0.18326 | 0.0026215
590771 | Niveau 2 | 1 | 0.1235 | 0.2435 | 0.0035
591112 | Niveau 2 | 0.996 | 0.12302 | 0.23904 | 0.003486
591113 | Niveau 2 | 0.709 | 0.08858 | 0.17366 | 0.0024815
591114 | Niveau 2 | 1 | 0.1235 | 0.2435 | 0.0035
591544 | Niveau 2 | 1.137 | 0.13994 | 0.27638 | 0.0039795
591545 | Niveau 2 | 1.588 | 0.19406 | 0.38462 | 0.005558
627836 | Niveau 2 | 1.221 | 0.15002 | 0.29654 | 0.0042735
627837 | Niveau 2 | 2.965 | 0.3593 | 0.7186 | 0.0103775
627838 | Niveau 2 | 1.041 | 0.12842 | 0.25334 | 0.0036435
627839 | Niveau 2 | 2.965 | 0.3593 | 0.7186 | 0.0103775
627841 | Niveau 2 | 1.221 | 0.15002 | 0.29654 | 0.0042735
627842 | Niveau 2 | 1.041 | 0.12842 | 0.25334 | 0.0036435

# IfcMember: Meneau rectangulaire:50 x 35 Alu bleu (28)
Type - PredefinedType: MULLION; Material: alu finifion bleu
Type - Pset_EnvironmentalImpactIndicators - Reference: 50 x 35 Alu bleu
Type - Pset_MemberCommon - IsExternal: no; Reference: 50 x 35 Alu bleu
Name (Meneau rectangulaire:50 x 35 Alu bleu:...) | In | Span (m) | CrossSectionArea (m2) | NetSurfaceArea (m2) | NetVolume (m3)
340726 | Niveau 0 | 1.92945 | 0.235034 | 0.470068 | 0.00675307
340727 | Niveau 0 | 2.49 | 0.3023 | 0.6046 | 0.008715
340728 | Niveau 0 | 1.92945 | 0.235034 | 0.470068 | 0.00675307
340729 | Niveau 0 | 2.49 | 0.3023 | 0.6046 | 0.008715
340792 | Niveau 0 | 1.92945 | 0.235034 | 0.470068 | 0.00675307
340793 | Niveau 0 | 2.49505 | 0.302907 | 0.605813 | 0.00873269
340794 | Niveau 0 | 1.92945 | 0.235034 | 0.470068 | 0.00675307
340795 | Niveau 0 | 2.49505 | 0.302907 | 0.605813 | 0.00873269
340840 | Niveau 0 | 1.92945 | 0.235034 | 0.470068 | 0.00675307
340841 | Niveau 0 | 2.52321 | 0.306286 | 0.612572 | 0.00883125
340842 | Niveau 0 | 1.92945 | 0.235034 | 0.470068 | 0.00675307
340843 | Niveau 0 | 2.52321 | 0.306286 | 0.612572 | 0.00883125
623682 | Niveau 1 | 2.81504 | 0.341304 | 0.682609 | 0.00985262
623683 | Niveau 1 | 2.49505 | 0.302907 | 0.605813 | 0.00873269
623684 | Niveau 1 | 2.81504 | 0.341304 | 0.682609 | 0.00985262
623685 | Niveau 1 | 2.49505 | 0.302907 | 0.605813 | 0.00873269
623766 | Niveau 1 | 2.81504 | 0.341304 | 0.682609 | 0.00985262
623767 | Niveau 1 | 2.49 | 0.3023 | 0.6046 | 0.008715
623768 | Niveau 1 | 2.81504 | 0.341304 | 0.682609 | 0.00985262
623769 | Niveau 1 | 2.49 | 0.3023 | 0.6046 | 0.008715
623772 | Niveau 1 | 2.81504 | 0.341304 | 0.682609 | 0.00985262
623773 | Niveau 1 | 2.52321 | 0.306286 | 0.612572 | 0.00883125
623774 | Niveau 1 | 2.81504 | 0.341304 | 0.682609 | 0.00985262
623775 | Niveau 1 | 2.52321 | 0.306286 | 0.612572 | 0.00883125
623887 | Niveau 1 | 2.81504 | 0.341304 | 0.682609 | 0.00985262
623888 | Niveau 1 | 2.49 | 0.3023 | 0.6046 | 0.008715
623889 | Niveau 1 | 2.81504 | 0.341304 | 0.682609 | 0.00985262
623890 | Niveau 1 | 2.49 | 0.3023 | 0.6046 | 0.008715

# IfcMember: Meneau rectangulaire:50 x 35 pvc gris (233)
Type - PredefinedType: MULLION; Material: PVC, souple
Type - Pset_EnvironmentalImpactIndicators - Reference: 50 x 35 pvc gris
Type - Pset_MemberCommon - IsExternal: no; Reference: 50 x 35 pvc gris
Name (Meneau rectangulaire:50 x 35 pvc gris:...) | In | Span (m) | CrossSectionArea (m2) | NetSurfaceArea (m2) | NetVolume (m3)
533488 | Niveau 1 | 0.581 | 0.07322 | 0.14294 | 0.0020335
533491 | Niveau 1 | 0.964 | 0.11918 | 0.23136 | 0.003374
533495 | Niveau 1 | 0.97696 | 0.120735 | 0.237971 | 0.00341936
533498 | Niveau 1 | 0.105 | 0.0161 | 0.0252 | 0.0003675
533503 | Niveau 1 | 0.92696 | 0.114735 | 0.225971 | 0.00324436
533507 | Niveau 1 | 0.105 | 0.0161 | 0.0252 | 0.0003675
533512 | Niveau 1 | 0.964 | 0.11918 | 0.23136 | 0.003374
533517 | Niveau 1 | 0.581 | 0.07322 | 0.14294 | 0.0020335
533522 | Niveau 1 | 0.581 | 0.07322 | 0.14294 | 0.0020335
533526 | Niveau 1 | 0.964 | 0.11918 | 0.23136 | 0.003374
533530 | Niveau 1 | 0.105 | 0.0161 | 0.0252 | 0.0003675
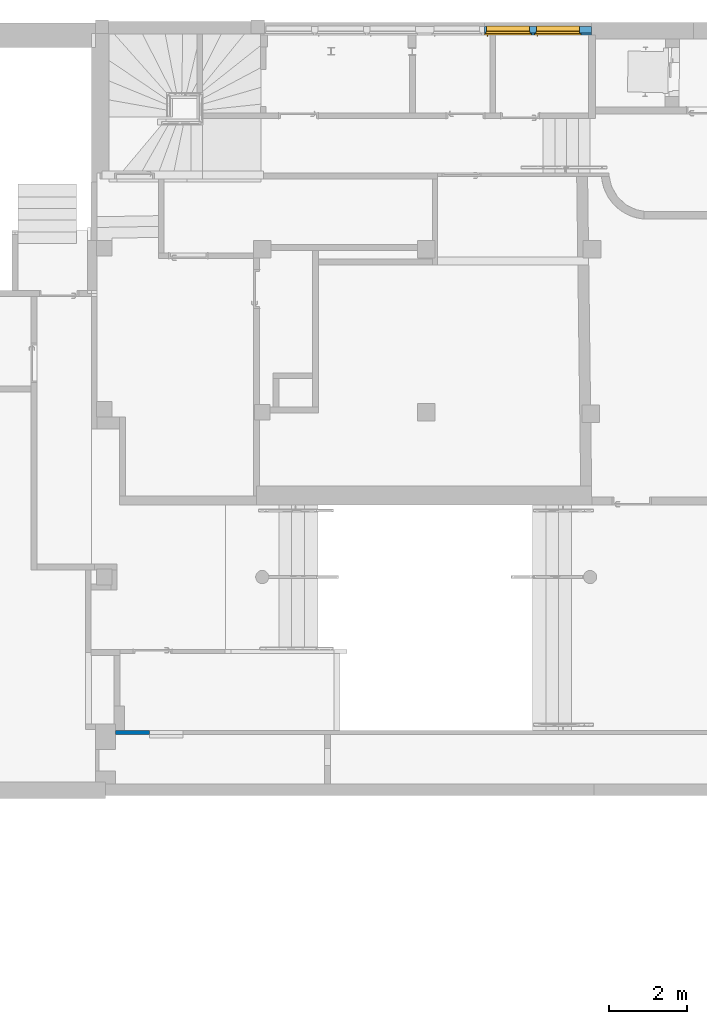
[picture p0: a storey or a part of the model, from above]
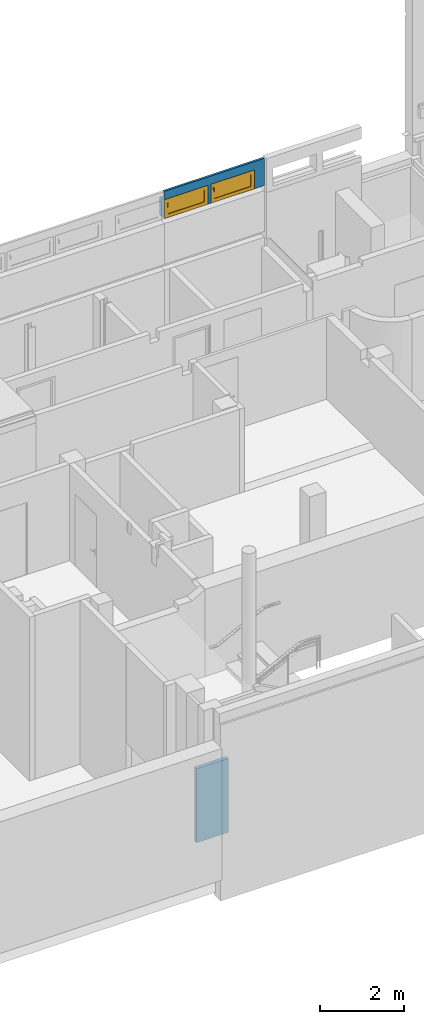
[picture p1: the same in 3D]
Properties of the parts of a building model (IFC4), part 5 of 8

# IfcMember: Meneau rectangulaire:50 x 35 pvc gris (233)
Name (Meneau rectangulaire:50 x 35 pvc gris:...) | In | Span (m) | CrossSectionArea (m2) | NetSurfaceArea (m2) | NetVolume (m3)
533534 | Niveau 1 | 0.92696 | 0.114735 | 0.225971 | 0.00324436
533537 | Niveau 1 | 0.0373082 | 0.00797698 | 0.015954 | 0.000130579
533538 | Niveau 1 | 0.912692 | 0.113023 | 0.226046 | 0.00319442
533539 | Niveau 1 | 0.92629 | 0.114655 | 0.22931 | 0.00324202
533540 | Niveau 1 | 0.870645 | 0.107977 | 0.215955 | 0.00304726
533541 | Niveau 1 | 0.805 | 0.1001 | 0.2002 | 0.0028175
533542 | Niveau 1 | 0.929 | 0.11498 | 0.22996 | 0.0032515
533543 | Niveau 1 | 0.78 | 0.0971 | 0.1942 | 0.00273
533544 | Niveau 1 | 0.93 | 0.1151 | 0.2302 | 0.003255
533545 | Niveau 1 | 1.39 | 0.1703 | 0.3406 | 0.004865
533546 | Niveau 1 | 1.25 | 0.1535 | 0.307 | 0.004375
533579 | Niveau 1 | 0.0373082 | 0.00797698 | 0.015954 | 0.000130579
533580 | Niveau 1 | 0.912692 | 0.113023 | 0.226046 | 0.00319442
533581 | Niveau 1 | 0.92629 | 0.114655 | 0.22931 | 0.00324202
533582 | Niveau 1 | 0.870645 | 0.107977 | 0.215955 | 0.00304726
533583 | Niveau 1 | 0.884 | 0.10958 | 0.21916 | 0.003094
533584 | Niveau 1 | 0.847 | 0.10514 | 0.21028 | 0.0029645
533585 | Niveau 1 | 0.805 | 0.1001 | 0.2002 | 0.0028175
533586 | Niveau 1 | 0.929 | 0.11498 | 0.22996 | 0.0032515
533587 | Niveau 1 | 0.833 | 0.10346 | 0.20692 | 0.0029155
533588 | Niveau 1 | 0.78 | 0.0971 | 0.1942 | 0.00273
533589 | Niveau 1 | 0.93 | 0.1151 | 0.2302 | 0.003255
533590 | Niveau 1 | 1.39 | 0.1703 | 0.3406 | 0.004865
533591 | Niveau 1 | 1.25 | 0.1535 | 0.307 | 0.004375
533592 | Niveau 1 | 0.471 | 0.06002 | 0.12004 | 0.0016485
533593 | Niveau 1 | 0.808 | 0.10046 | 0.20092 | 0.002828
533637 | Niveau 1 | 0.105 | 0.0161 | 0.0252 | 0.0003675
533638 | Niveau 1 | 0.964 | 0.11918 | 0.23136 | 0.003374
533639 | Niveau 1 | 0.581 | 0.07322 | 0.14294 | 0.0020335
533640 | Niveau 1 | 0.92696 | 0.114735 | 0.225971 | 0.00324436
533649 | Niveau 1 | 0.105 | 0.0161 | 0.0252 | 0.0003675
533650 | Niveau 1 | 0.964 | 0.11918 | 0.23136 | 0.003374
533651 | Niveau 1 | 0.581 | 0.07322 | 0.14294 | 0.0020335
533652 | Niveau 1 | 0.92696 | 0.114735 | 0.225971 | 0.00324436
533739 | Niveau 1 | 0.105 | 0.0161 | 0.0252 | 0.0003675
533740 | Niveau 1 | 0.964 | 0.11918 | 0.23136 | 0.003374
533741 | Niveau 1 | 0.581 | 0.07322 | 0.14294 | 0.0020335
533742 | Niveau 1 | 0.92696 | 0.114735 | 0.225971 | 0.00324436
533752 | Niveau 1 | 0.105 | 0.0161 | 0.0252 | 0.0003675
533753 | Niveau 1 | 0.964 | 0.11918 | 0.23136 | 0.003374
533754 | Niveau 1 | 0.581 | 0.07322 | 0.14294 | 0.0020335
533755 | Niveau 1 | 0.92696 | 0.114735 | 0.225971 | 0.00324436
533763 | Niveau 1 | 0.105 | 0.0161 | 0.0252 | 0.0003675
533764 | Niveau 1 | 0.964 | 0.11918 | 0.23136 | 0.003374
533765 | Niveau 1 | 0.581 | 0.07322 | 0.14294 | 0.0020335
533766 | Niveau 1 | 0.92696 | 0.114735 | 0.225971 | 0.00324436
533774 | Niveau 1 | 0.105 | 0.0161 | 0.0252 | 0.0003675
533775 | Niveau 1 | 0.964 | 0.11918 | 0.23136 | 0.003374
533776 | Niveau 1 | 0.581 | 0.07322 | 0.14294 | 0.0020335
533777 | Niveau 1 | 0.92696 | 0.114735 | 0.225971 | 0.00324436
533787 | Niveau 1 | 0.105 | 0.0161 | 0.0252 | 0.0003675
533788 | Niveau 1 | 0.964 | 0.11918 | 0.23136 | 0.003374
533789 | Niveau 1 | 0.581 | 0.07322 | 0.14294 | 0.0020335
533790 | Niveau 1 | 0.92696 | 0.114735 | 0.225971 | 0.00324436
533810 | Niveau 1 | 0.105 | 0.0161 | 0.0252 | 0.0003675
533811 | Niveau 1 | 0.964 | 0.11918 | 0.23136 | 0.003374
533812 | Niveau 1 | 0.581 | 0.07322 | 0.14294 | 0.0020335
533813 | Niveau 1 | 0.92696 | 0.114735 | 0.225971 | 0.00324436
533822 | Niveau 1 | 0.105 | 0.0161 | 0.0252 | 0.0003675
533823 | Niveau 1 | 0.964 | 0.11918 | 0.23136 | 0.003374
533824 | Niveau 1 | 0.581 | 0.07322 | 0.14294 | 0.0020335
533825 | Niveau 1 | 0.92696 | 0.114735 | 0.225971 | 0.00324436
533834 | Niveau 1 | 0.105 | 0.0161 | 0.0252 | 0.0003675
533835 | Niveau 1 | 0.964 | 0.11918 | 0.23136 | 0.003374
533836 | Niveau 1 | 0.581 | 0.07322 | 0.14294 | 0.0020335
533837 | Niveau 1 | 0.92696 | 0.114735 | 0.225971 | 0.00324436
533847 | Niveau 1 | 0.105 | 0.0161 | 0.0252 | 0.0003675
533848 | Niveau 1 | 0.964 | 0.11918 | 0.23136 | 0.003374
533849 | Niveau 1 | 0.581 | 0.07322 | 0.14294 | 0.0020335
533850 | Niveau 1 | 0.92696 | 0.114735 | 0.225971 | 0.00324436
533859 | Niveau 1 | 0.982692 | 0.121423 | 0.235846 | 0.00343942
533860 | Niveau 1 | 0.99629 | 0.123055 | 0.23911 | 0.00348702
533861 | Niveau 1 | 0.940645 | 0.116377 | 0.225755 | 0.00329226
533862 | Niveau 1 | 0.954 | 0.11798 | 0.22896 | 0.003339
533863 | Niveau 1 | 0.917 | 0.11354 | 0.22008 | 0.0032095
533864 | Niveau 1 | 0.875 | 0.1085 | 0.21 | 0.0030625
533865 | Niveau 1 | 0.999 | 0.12338 | 0.23976 | 0.0034965
533866 | Niveau 1 | 0.903 | 0.11186 | 0.21672 | 0.0031605
533867 | Niveau 1 | 0.85 | 0.1055 | 0.204 | 0.002975
533868 | Niveau 1 | 1 | 0.1235 | 0.24 | 0.0035
533869 | Niveau 1 | 1.46 | 0.1787 | 0.3504 | 0.00511
533870 | Niveau 1 | 1.32 | 0.1619 | 0.3168 | 0.00462
533871 | Niveau 1 | 0.541 | 0.06842 | 0.12984 | 0.0018935
533872 | Niveau 1 | 0.913 | 0.11306 | 0.22262 | 0.0031955
533873 | Niveau 1 | 0.142308 | 0.020577 | 0.037654 | 0.000498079
533907 | Niveau 1 | 0.105 | 0.0161 | 0.0252 | 0.0003675
533908 | Niveau 1 | 0.964 | 0.11918 | 0.23136 | 0.003374
533909 | Niveau 1 | 0.581 | 0.07322 | 0.14294 | 0.0020335
533910 | Niveau 1 | 0.97696 | 0.120735 | 0.237971 | 0.00341936
533919 | Niveau 1 | 0.105 | 0.0161 | 0.0252 | 0.0003675
533920 | Niveau 1 | 0.964 | 0.11918 | 0.23136 | 0.003374
533921 | Niveau 1 | 0.581 | 0.07322 | 0.14294 | 0.0020335
533922 | Niveau 1 | 0.92696 | 0.114735 | 0.225971 | 0.00324436
533932 | Niveau 1 | 0.471 | 0.06002 | 0.12004 | 0.0016485
540246 | Niveau 1 | 0.535 | 0.0677 | 0.1284 | 0.0018725
540247 | Niveau 1 | 1.06648 | 0.131477 | 0.255955 | 0.00373267
540248 | Niveau 1 | 1.112 | 0.13694 | 0.26688 | 0.003892
540249 | Niveau 1 | 1.054 | 0.12998 | 0.25646 | 0.003689
540250 | Niveau 1 | 0.321 | 0.04202 | 0.08054 | 0.0011235
540261 | Niveau 1 | 0.216 | 0.02942 | 0.05884 | 0.000756
540262 | Niveau 1 | 0.465 | 0.0593 | 0.1186 | 0.0016275
540263 | Niveau 1 | 0.996478 | 0.123077 | 0.246155 | 0.00348767
540264 | Niveau 1 | 1.042 | 0.12854 | 0.25708 | 0.003647
540265 | Niveau 1 | 0.949 | 0.11738 | 0.23476 | 0.0033215
540281 | Niveau 1 | 0.216 | 0.02942 | 0.05884 | 0.000756
540282 | Niveau 1 | 0.465 | 0.0593 | 0.1186 | 0.0016275
540283 | Niveau 1 | 0.996478 | 0.123077 | 0.246155 | 0.00348767
540284 | Niveau 1 | 1.042 | 0.12854 | 0.25708 | 0.003647
540285 | Niveau 1 | 0.949 | 0.11738 | 0.23476 | 0.0033215
540296 | Niveau 1 | 0.927 | 0.11474 | 0.22598 | 0.0032445
540297 | Niveau 1 | 1.06896 | 0.131775 | 0.256551 | 0.00374136
540298 | Niveau 1 | 0.581 | 0.07322 | 0.14294 | 0.0020335
540306 | Niveau 1 | 1.06896 | 0.131775 | 0.256551 | 0.00374136
540307 | Niveau 1 | 0.581 | 0.07322 | 0.14294 | 0.0020335
540308 | Niveau 1 | 0.92696 | 0.114735 | 0.225971 | 0.00324436
540321 | Niveau 1 | 1.06896 | 0.131775 | 0.256551 | 0.00374136
540322 | Niveau 1 | 0.581 | 0.07322 | 0.14294 | 0.0020335
540323 | Niveau 1 | 0.92696 | 0.114735 | 0.225971 | 0.00324436
540334 | Niveau 1 | 1.06896 | 0.131775 | 0.256551 | 0.00374136
540335 | Niveau 1 | 0.581 | 0.07322 | 0.14294 | 0.0020335
540336 | Niveau 1 | 0.92696 | 0.114735 | 0.225971 | 0.00324436
540347 | Niveau 1 | 1.06896 | 0.131775 | 0.256551 | 0.00374136
540348 | Niveau 1 | 0.581 | 0.07322 | 0.14294 | 0.0020335
540349 | Niveau 1 | 0.92696 | 0.114735 | 0.225971 | 0.00324436
540360 | Niveau 1 | 1.06896 | 0.131775 | 0.256551 | 0.00374136
540361 | Niveau 1 | 0.581 | 0.07322 | 0.14294 | 0.0020335
540362 | Niveau 1 | 0.92696 | 0.114735 | 0.225971 | 0.00324436
541031 | Niveau 1 | 0.927 | 0.11474 | 0.22598 | 0.0032445
541032 | Niveau 1 | 1.06896 | 0.131775 | 0.256551 | 0.00374136
541033 | Niveau 1 | 0.581 | 0.07322 | 0.14294 | 0.0020335
541041 | Niveau 1 | 0.878003 | 0.10886 | 0.217721 | 0.00307301
541042 | Niveau 1 | 0.833475 | 0.103517 | 0.207034 | 0.00291716
541043 | Niveau 1 | 0.847 | 0.10514 | 0.21028 | 0.0029645
541044 | Niveau 1 | 0.933 | 0.11546 | 0.23092 | 0.0032655
541045 | Niveau 1 | 0.177 | 0.02474 | 0.04948 | 0.0006195
541062 | Niveau 1 | 1.06896 | 0.131775 | 0.256551 | 0.00374136
541063 | Niveau 1 | 0.581 | 0.07322 | 0.14294 | 0.0020335
541064 | Niveau 1 | 0.92696 | 0.114735 | 0.225971 | 0.00324436
541077 | Niveau 1 | 0.878003 | 0.10886 | 0.217721 | 0.00307301
541078 | Niveau 1 | 0.833475 | 0.103517 | 0.207034 | 0.00291716
541079 | Niveau 1 | 0.847 | 0.10514 | 0.21028 | 0.0029645
541080 | Niveau 1 | 0.933 | 0.11546 | 0.23092 | 0.0032655
541081 | Niveau 1 | 0.177 | 0.02474 | 0.04948 | 0.0006195
541094 | Niveau 1 | 0.282 | 0.03734 | 0.07118 | 0.000987
541095 | Niveau 1 | 0.917 | 0.11354 | 0.22008 | 0.0032095
541096 | Niveau 1 | 1.003 | 0.12386 | 0.24072 | 0.0035105
541097 | Niveau 1 | 0.948003 | 0.11726 | 0.227521 | 0.00331801
541098 | Niveau 1 | 0.938475 | 0.116117 | 0.228734 | 0.00328466
541109 | Niveau 1 | 1.06896 | 0.131775 | 0.256551 | 0.00374136
541110 | Niveau 1 | 0.581 | 0.07322 | 0.14294 | 0.0020335
541111 | Niveau 1 | 0.92696 | 0.114735 | 0.225971 | 0.00324436
541124 | Niveau 1 | 1.06896 | 0.131775 | 0.256551 | 0.00374136
541125 | Niveau 1 | 0.581 | 0.07322 | 0.14294 | 0.0020335
541126 | Niveau 1 | 0.92696 | 0.114735 | 0.225971 | 0.00324436
541139 | Niveau 1 | 1.06896 | 0.131775 | 0.256551 | 0.00374136
541140 | Niveau 1 | 0.581 | 0.07322 | 0.14294 | 0.0020335
541141 | Niveau 1 | 0.92696 | 0.114735 | 0.225971 | 0.00324436
541151 | Niveau 1 | 1.06896 | 0.131775 | 0.256551 | 0.00374136
541152 | Niveau 1 | 0.581 | 0.07322 | 0.14294 | 0.0020335
541153 | Niveau 1 | 0.92696 | 0.114735 | 0.225971 | 0.00324436
542312 | Niveau 1 | 0.864657 | 0.107259 | 0.211018 | 0.0030263
542313 | Niveau 1 | 0.196 | 0.02702 | 0.05054 | 0.000686
542318 | Niveau 1 | 1.06896 | 0.131775 | 0.256551 | 0.00374136
542319 | Niveau 1 | 0.581 | 0.07322 | 0.14294 | 0.0020335
542320 | Niveau 1 | 0.92696 | 0.114735 | 0.225971 | 0.00324436
542330 | Niveau 1 | 0.091 | 0.01442 | 0.02884 | 0.0003185
542331 | Niveau 1 | 0.829657 | 0.103059 | 0.206118 | 0.0029038
542339 | Niveau 1 | 1.06896 | 0.131775 | 0.256551 | 0.00374136
542340 | Niveau 1 | 0.581 | 0.07322 | 0.14294 | 0.0020335
542341 | Niveau 1 | 0.92696 | 0.114735 | 0.225971 | 0.00324436
542349 | Niveau 1 | 0.091 | 0.01442 | 0.02884 | 0.0003185
542236 | Niveau 1 | 1.0114 | 0.124868 | 0.242736 | 0.00353989
542237 | Niveau 1 | 1.0114 | 0.124868 | 0.246236 | 0.00353989
542238 | Niveau 1 | 1.0114 | 0.124868 | 0.246236 | 0.00353989
542243 | Niveau 1 | 0.906398 | 0.112268 | 0.224536 | 0.00317239
542244 | Niveau 1 | 0.941398 | 0.116468 | 0.232936 | 0.00329489
542245 | Niveau 1 | 0.906398 | 0.112268 | 0.224536 | 0.00317239
542251 | Niveau 1 | 0.906398 | 0.112268 | 0.224536 | 0.00317239
542252 | Niveau 1 | 0.941398 | 0.116468 | 0.232936 | 0.00329489
542253 | Niveau 1 | 0.906398 | 0.112268 | 0.224536 | 0.00317239
542256 | Niveau 1 | 0.581 | 0.07322 | 0.14294 | 0.0020335
542257 | Niveau 1 | 1.06896 | 0.131775 | 0.256551 | 0.00374136
542258 | Niveau 1 | 0.92696 | 0.114735 | 0.225971 | 0.00324436
542267 | Niveau 1 | 1.06896 | 0.131775 | 0.256551 | 0.00374136
542268 | Niveau 1 | 0.927 | 0.11474 | 0.22598 | 0.0032445
542269 | Niveau 1 | 0.581 | 0.07322 | 0.14294 | 0.0020335
542276 | Niveau 1 | 0.581 | 0.07322 | 0.14294 | 0.0020335
542277 | Niveau 1 | 1.06896 | 0.131775 | 0.256551 | 0.00374136
542278 | Niveau 1 | 0.92696 | 0.114735 | 0.225971 | 0.00324436
542286 | Niveau 1 | 0.581 | 0.07322 | 0.14294 | 0.0020335
542287 | Niveau 1 | 1.06896 | 0.131775 | 0.256551 | 0.00374136
542288 | Niveau 1 | 0.92696 | 0.114735 | 0.225971 | 0.00324436
542291 | Niveau 1 | 1.06896 | 0.131775 | 0.256551 | 0.00374136
542292 | Niveau 1 | 0.581 | 0.07322 | 0.14294 | 0.0020335
542293 | Niveau 1 | 0.92696 | 0.114735 | 0.225971 | 0.00324436
542300 | Niveau 1 | 0.466363 | 0.0594636 | 0.118927 | 0.00163227
542305 | Niveau 1 | 0.466363 | 0.0594636 | 0.118927 | 0.00163227
542309 | Niveau 1 | 0.536363 | 0.0678636 | 0.135727 | 0.00187727
564339 | Niveau 2 | 1.53629 | 0.187854 | 0.375709 | 0.00537701
564340 | Niveau 2 | 1.80111 | 0.219634 | 0.435767 | 0.0063039
564341 | Niveau 2 | 1.53629 | 0.187854 | 0.375709 | 0.00537701
564342 | Niveau 2 | 0.965 | 0.1193 | 0.2351 | 0.0033775
607808 | Niveau 2 | 0.965 | 0.1193 | 0.2351 | 0.0033775
607809 | Niveau 2 | 1.80111 | 0.219634 | 0.435767 | 0.0063039
562101 | Niveau 2 | 1.54129 | 0.188454 | 0.376909 | 0.00539451
562102 | Niveau 2 | 1.832 | 0.22334 | 0.44318 | 0.006412
562103 | Niveau 2 | 1.54129 | 0.188454 | 0.376909 | 0.00539451
562104 | Niveau 2 | 1.15412 | 0.141994 | 0.280488 | 0.00403941
562105 | Niveau 2 | 1.54129 | 0.188454 | 0.376909 | 0.00539451
562107 | Niveau 2 | 1.832 | 0.22334 | 0.44318 | 0.006412
562108 | Niveau 2 | 1.004 | 0.12398 | 0.24096 | 0.003514
562109 | Niveau 2 | 1.004 | 0.12398 | 0.24096 | 0.003514
562110 | Niveau 2 | 1.15412 | 0.141994 | 0.280488 | 0.00403941
564066 | Niveau 2 | 1.54129 | 0.188454 | 0.376909 | 0.00539451
564067 | Niveau 2 | 1.832 | 0.22334 | 0.44318 | 0.006412
564068 | Niveau 2 | 1.54129 | 0.188454 | 0.376909 | 0.00539451
564069 | Niveau 2 | 1.15442 | 0.14203 | 0.28056 | 0.00404046
564070 | Niveau 2 | 1.54129 | 0.188454 | 0.376909 | 0.00539451
564072 | Niveau 2 | 1.832 | 0.22334 | 0.44318 | 0.006412
564073 | Niveau 2 | 1.004 | 0.12398 | 0.24096 | 0.003514
564074 | Niveau 2 | 1.004 | 0.12398 | 0.24096 | 0.003514
564075 | Niveau 2 | 1.15442 | 0.14203 | 0.28056 | 0.00404046

# IfcMember: Meneau rectangulaire:50 x 40 (15)
In: Niveau 2
Type - PredefinedType: MULLION; Material: PVC - Blanc
Type - Pset_EnvironmentalImpactIndicators - Reference: 50 x 40
Type - Pset_MemberCommon - IsExternal: no; Reference: 50 x 40
Name (Meneau rectangulaire:50 x 40:...) | Span (m) | CrossSectionArea (m2) | NetSurfaceArea (m2) | NetVolume (m3)
582986 | 1.02674 | 0.137476 | 0.274952 | 0.00410696
583087 | 1.14 | 0.1522 | 0.3044 | 0.00456
583103 | 1.14 | 0.1522 | 0.3044 | 0.00456
583233 | 1.16697 | 0.155705 | 0.311411 | 0.00466786
583410 | 1.18303 | 0.157795 | 0.315589 | 0.00473214
583426 | 1.14 | 0.1522 | 0.3044 | 0.00456
583442 | 1.20773 | 0.161005 | 0.32201 | 0.00483093
590860 | 0.988 | 0.13244 | 0.26088 | 0.003952
590861 | 0.94 | 0.1262 | 0.2484 | 0.00376
590882 | 0.462 | 0.06406 | 0.12412 | 0.001848
590883 | 1.09 | 0.1457 | 0.2874 | 0.00436
591124 | 0.956 | 0.12828 | 0.25256 | 0.003824
591125 | 0.94 | 0.1262 | 0.2484 | 0.00376
591126 | 0.462 | 0.06406 | 0.12412 | 0.001848
591127 | 1.09 | 0.1457 | 0.2874 | 0.00436

# IfcMember: Meneau rectangulaire:50 x 45 (17)
In: Niveau 2
Type - PredefinedType: MULLION; Material: PVC - Blanc
Type - Pset_EnvironmentalImpactIndicators - Reference: 50 x 45
Type - Pset_MemberCommon - IsExternal: no; Reference: 50 x 45
Name (Meneau rectangulaire:50 x 45:...) | Span (m) | CrossSectionArea (m2) | NetSurfaceArea (m2) | NetVolume (m3)
583018 | 1.14674 | 0.165044 | 0.330087 | 0.00516033
583023 | 1.14674 | 0.165044 | 0.330087 | 0.00516033
583088 | 1.26 | 0.1809 | 0.3618 | 0.00567
583089 | 1.26 | 0.1809 | 0.3618 | 0.00567
583104 | 1.26 | 0.1809 | 0.3618 | 0.00567
583105 | 1.26 | 0.1809 | 0.3618 | 0.00567
583234 | 1.28697 | 0.184675 | 0.36935 | 0.00579134
583235 | 1.28697 | 0.184675 | 0.36935 | 0.00579134
583411 | 1.30303 | 0.186925 | 0.37385 | 0.00586366
583412 | 1.30303 | 0.186925 | 0.37385 | 0.00586366
583427 | 1.26 | 0.1809 | 0.3618 | 0.00567
583428 | 1.26 | 0.1809 | 0.3618 | 0.00567
583443 | 1.32773 | 0.190382 | 0.380765 | 0.00597479
583444 | 1.32773 | 0.190382 | 0.380765 | 0.00597479
595842 | 1.03318 | 0.149145 | 0.298289 | 0.00464929
595982 | 1.00475 | 0.145164 | 0.290329 | 0.00452135
596422 | 1.26926 | 0.182196 | 0.364392 | 0.00571165

# IfcMember: Meneau rectangulaire:50 x 50 mm (21)
Type - PredefinedType: MULLION; Material: PVC - Blanc
Type - Pset_EnvironmentalImpactIndicators - Reference: 50 x 50 mm
Type - Pset_MemberCommon - IsExternal: no; Reference: 50 x 50 mm
Name (Meneau rectangulaire:50 x 50 mm:...) | In | Span (m) | CrossSectionArea (m2) | NetSurfaceArea (m2) | NetVolume (m3)
312758 | Niveau 0 | 8.08521 | 1.21778 | 2.43556 | 0.040426
312759 | Niveau 0 | 2.25 | 0.3425 | 0.685 | 0.01125
314728 | Niveau 0 | 0.233 | 0.03995 | 0.0799 | 0.001165
314729 | Niveau 0 | 2.25 | 0.3425 | 0.685 | 0.01125
313295 | Niveau 0 | 4.11146 | 0.621719 | 1.24344 | 0.0205573
313298 | Niveau 0 | 2.25 | 0.3425 | 0.685 | 0.01125
314736 | Niveau 0 | 0.251777 | 0.0427665 | 0.085533 | 0.00125888
314737 | Niveau 0 | 2.25 | 0.3425 | 0.685 | 0.01125
314828 | Niveau 1 | 0.642527 | 0.101379 | 0.202758 | 0.00321263
335817 | Niveau 1 | 0.642527 | 0.101379 | 0.202758 | 0.00321263
314964 | Niveau 1 | 0.642527 | 0.101379 | 0.202758 | 0.00321263
335755 | Niveau 1 | 0.642527 | 0.101379 | 0.202758 | 0.00321263
335763 | Niveau 1 | 0.642527 | 0.101379 | 0.202758 | 0.00321263
314971 | Niveau 1 | 0.742527 | 0.116379 | 0.232758 | 0.00371263
314975 | Niveau 1 | 0.742527 | 0.116379 | 0.232758 | 0.00371263
335522 | Niveau 1 | 0.642527 | 0.101379 | 0.202758 | 0.00321263
335530 | Niveau 1 | 0.642527 | 0.101379 | 0.202758 | 0.00321263
513724 | Niveau 1 | 0.642527 | 0.101379 | 0.202758 | 0.00321263
513729 | Niveau 1 | 0.642527 | 0.101379 | 0.202758 | 0.00321263
514546 | Niveau 1 | 0.642527 | 0.101379 | 0.202758 | 0.00321263
514551 | Niveau 1 | 0.642527 | 0.101379 | 0.202758 | 0.00321263

# IfcMember: Meneau rectangulaire:50 x 65 pvc gris (2)
In: Niveau 2
Type - PredefinedType: MULLION; Material: PVC, souple
Type - Pset_EnvironmentalImpactIndicators - Reference: 50 x 65 pvc gris
Type - Pset_MemberCommon - IsExternal: no; Reference: 50 x 65 pvc gris
Pset_MemberCommon - Span: 1.54129 m
Qto_MemberBaseQuantities - CrossSectionArea: 0.283932 m2; NetSurfaceArea: 0.567863 m2; NetVolume: 0.0100184 m3
Name (Meneau rectangulaire:50 x 65 pvc gris:...)
562106
564071

# IfcMember: Meneau rectangulaire:50x30 (6)
In: SS2
Type - PredefinedType: MULLION; Material: PVC - Blanc
Type - Pset_EnvironmentalImpactIndicators - Reference: 50x30
Type - Pset_MemberCommon - IsExternal: no; Reference: 50x30
Name (Meneau rectangulaire:50x30:...) | Span (m) | CrossSectionArea (m2) | NetSurfaceArea (m2) | NetVolume (m3)
416890 | 1.29409 | 0.105027 | 0.210055 | 0.00194114
416802 | 1.32927 | 0.107841 | 0.215683 | 0.0019939
416686 | 1.32927 | 0.107841 | 0.215683 | 0.0019939
416585 | 1.32927 | 0.107841 | 0.215683 | 0.0019939
415732 | 1.32927 | 0.107841 | 0.215683 | 0.0019939
415733 | 1.32927 | 0.107841 | 0.215683 | 0.0019939

# IfcMember: Meneau rectangulaire:50x50 PVC BLANC (44)
In: SS2
Type - PredefinedType: MULLION; Material: PVC - Blanc
Type - Pset_EnvironmentalImpactIndicators - Reference: 50x50 PVC BLANC
Type - Pset_MemberCommon - IsExternal: no; Reference: 50x50 PVC BLANC
Name (Meneau rectangulaire:50x50 PVC BLANC:...) | Span (m) | CrossSectionArea (m2) | NetSurfaceArea (m2) | NetVolume (m3)
413732 | 1.42927 | 0.145427 | 0.290853 | 0.00357317
413733 | 0.172 | 0.0197 | 0.0394 | 0.00043
413734 | 1.42927 | 0.145427 | 0.290853 | 0.00357317
413735 | 0.172 | 0.0197 | 0.0394 | 0.00043
416886 | 1.29409 | 0.131909 | 0.263819 | 0.00323523
416887 | 1.04903 | 0.107403 | 0.212305 | 0.00262256
416888 | 1.29409 | 0.131909 | 0.263819 | 0.00323523
416889 | 0.614128 | 0.0639128 | 0.125326 | 0.00153532
416891 | 1.04903 | 0.107403 | 0.212305 | 0.00262256
416892 | 0.614128 | 0.0639128 | 0.125326 | 0.00153532
416798 | 1.32927 | 0.135427 | 0.270853 | 0.00332317
416799 | 0.90601 | 0.093101 | 0.183702 | 0.00226502
416800 | 1.32927 | 0.135427 | 0.270853 | 0.00332317
416801 | 0.89901 | 0.092401 | 0.182302 | 0.00224752
416803 | 0.90601 | 0.093101 | 0.183702 | 0.00226502
416804 | 0.89901 | 0.092401 | 0.182302 | 0.00224752
416682 | 1.32927 | 0.135427 | 0.270853 | 0.00332317
416683 | 1.1115 | 0.11365 | 0.2248 | 0.00277875
416684 | 1.32927 | 0.135427 | 0.270853 | 0.00332317
416685 | 1.1115 | 0.11365 | 0.2248 | 0.00277875
416687 | 1.1115 | 0.11365 | 0.2248 | 0.00277875
416688 | 1.1115 | 0.11365 | 0.2248 | 0.00277875
416581 | 1.32927 | 0.135427 | 0.270853 | 0.00332317
416582 | 0.878422 | 0.0903422 | 0.178184 | 0.00219606
416583 | 1.32927 | 0.135427 | 0.270853 | 0.00332317
416584 | 0.878422 | 0.0903422 | 0.178184 | 0.00219606
416586 | 0.878422 | 0.0903422 | 0.178184 | 0.00219606
416587 | 0.878422 | 0.0903422 | 0.178184 | 0.00219606
415728 | 1.32927 | 0.135427 | 0.270853 | 0.00332317
415729 | 1.10785 | 0.113285 | 0.22407 | 0.00276962
415730 | 1.32927 | 0.135427 | 0.270853 | 0.00332317
415731 | 0.763 | 0.0788 | 0.1551 | 0.0019075
415734 | 1.10785 | 0.113285 | 0.22407 | 0.00276962
415735 | 1.06 | 0.1085 | 0.212 | 0.00265
415736 | 1.06 | 0.1085 | 0.212 | 0.00265
415737 | 0.763 | 0.0788 | 0.1551 | 0.0019075
416491 | 1.42927 | 0.145427 | 0.290853 | 0.00357317
416492 | 1.157 | 0.1182 | 0.2364 | 0.0028925
416493 | 1.42927 | 0.145427 | 0.290853 | 0.00357317
416494 | 1.157 | 0.1182 | 0.2364 | 0.0028925
416498 | 1.42927 | 0.145427 | 0.290853 | 0.00357317
416499 | 0.905584 | 0.0930584 | 0.186117 | 0.00226396
416500 | 1.42927 | 0.145427 | 0.290853 | 0.00357317
416501 | 0.905584 | 0.0930584 | 0.186117 | 0.00226396

# IfcMember: Meneau rectangulaire:70x70 (4)
In: Niveau 0
Type - PredefinedType: MULLION; Material: PVC - Blanc
Type - Pset_EnvironmentalImpactIndicators - Reference: 70x70
Type - Pset_MemberCommon - IsExternal: no; Reference: 70x70
Name (Meneau rectangulaire:70x70:...) | Span (m) | CrossSectionArea (m2) | NetSurfaceArea (m2) | NetVolume (m3)
312706 | 8.08521 | 1.70769 | 3.41539 | 0.079235
314730 | 0.233 | 0.05873 | 0.11746 | 0.0022834
313288 | 4.11146 | 0.873207 | 1.74641 | 0.0402923
314738 | 0.251777 | 0.0626731 | 0.125346 | 0.00246741

# IfcMember: Meneau rectangulaire:90x50 (9)
In: SS2
Type - PredefinedType: MULLION; Material: PVC, souple
Type - Pset_EnvironmentalImpactIndicators - Reference: 90x50
Type - Pset_MemberCommon - IsExternal: no; Reference: 90x50
Name (Meneau rectangulaire:90x50:...) | Span (m) | CrossSectionArea (m2) | NetSurfaceArea (m2) | NetVolume (m3)
407610 | 1.79999 | 0.256499 | 0.503998 | 0.00809997
407612 | 0.690571 | 0.10118 | 0.19786 | 0.00310757
407619 | 1.35357 | 0.193999 | 0.387999 | 0.00609106
407623 | 0.710435 | 0.103961 | 0.207922 | 0.00319696
407633 | 2.26 | 0.3209 | 0.6418 | 0.01017
407638 | 0.645571 | 0.0948799 | 0.18976 | 0.00290507
407641 | 1.35357 | 0.193999 | 0.387999 | 0.00609106
407827 | 0.755435 | 0.110261 | 0.216022 | 0.00339946
407851 | 2.26 | 0.3209 | 0.6418 | 0.01017

# IfcOpeningElement: Opening (222)
PredefinedType: OPENING
Name | In | Depth (m) | Height (m) | Width (m)
Int. Simple:PP (0.63m x 2.04m):618625:1 | SS1 | 0.07 | 0.7 | 2.075
Mur de base:Générique - Int. 70 mm:269643 | Niveau 0 | 0.9 | 2.075 | 0.07 | Pset_EnvironmentalImpactIndicators - Reference: PP (0.83m x 2.04m); sets with these values: 2
Mur de base:Int. Plâtre 70 mm:281226:1 | Niveau 0 | Pset_EnvironmentalImpactIndicators - Reference: Int. Plâtre 70 mm; sets with these values: 2
Mur de base:Int. Plâtre 70 mm:286139:1 | Niveau 0 | Pset_EnvironmentalImpactIndicators - Reference: Int. Plâtre 70 mm; sets with these values: 2
Mur de base:Générique - Int. 100 mm:287014:1 | Niveau 0 | Pset_EnvironmentalImpactIndicators - Reference: Générique - Int. 100 mm; sets with these values: 2
Mur de base:Générique - Int. 100 mm:297194:1 | Niveau 0 | Pset_EnvironmentalImpactIndicators - Reference: Générique - Int. 100 mm; sets with these values: 2
Mur de base:Générique - Int. 360:299546:1 | Demi-niveau | Pset_EnvironmentalImpactIndicators - Reference: Générique - Int. 360; sets with these values: 2
Mur de base:Générique - Int. 360:299546 | Demi-niveau | 3.048 | 2 | 1.25501 | Pset_EnvironmentalImpactIndicators - Reference: 1000 x 880mm; sets with these values: 2
Mur de base:Générique - Ext.480 mm:300032 | Niveau 0 | 0.9 | 2.075 | 0.27 | Pset_EnvironmentalImpactIndicators - Reference: PP (0.83m x 2.04m); sets with these values: 2
Mur de base:Générique - Int. 100 mm:300909 | Niveau 0 | 0.7 | 2.075 | 0.07 | Pset_EnvironmentalImpactIndicators - Reference: PP (0.63m x 2.04m); sets with these values: 2
Mur de base:Générique - Int. 650:301504 | Niveau 0 | 0.9548 | 1.99707 | 2.18792 | Pset_EnvironmentalImpactIndicators - Reference: Simple panneau; sets with these values: 2
Mur de base:Générique - Int. 650:303721 | Niveau 0 | 0.9548 | 2.18792 | 2.91286 | Pset_EnvironmentalImpactIndicators - Reference: Simple panneau; sets with these values: 2
Int. Simple:PP (0.63m x 2.04m):588964:1 | Niveau 2 | 0.08 | 0.7 | 2.075
Int. Simple:PP0.93x2.04:582250:1 | Niveau 2 | 0.07 | 1 | 2.075
Int. Simple:0.70x2.04:581741:1 | Niveau 2 | 0.15 | 0.77 | 2.075
Int. Simple:PP (0.63m x 2.04m):581530:1 | Niveau 2 | 0.1 | 0.7 | 2.075
Int. Simple:PP (0.83m x 2.04m):581246:1 | Niveau 2 | 0.09 | 0.9 | 2.075
Mur de base:Générique - Int.120:314682 | Niveau 0 | 0.4248 | 8.23521 | 2.25 | Pset_EnvironmentalImpactIndicators - Reference: Simple panneau; sets with these values: 2
Mur de base:Générique - Int.120:314682 | Niveau 0 | 0.4248 | 8.216 | 0.742527 | Pset_EnvironmentalImpactIndicators - Reference: Simple panneau; sets with these values: 2
Int. Simple:PP (0.83m x 2.04m):579660:1 | Niveau 2 | 0.07 | 0.9 | 2.075
Placard coulissante - 3 panneaux:3.2x2.7:579547:1 | Niveau 2 | 0.07 | 3.2 | 2.7
Int. Tierce:1.33X1.96:601236:1 | Niveau 2 | 0.2 | 1.4 | 2
Int. Simple:0.53x1.85:599719:1 | Niveau 2 | 0.08 | 0.6 | 1.885
Int. Simple:0.53x1.85:599817:1 | Niveau 2 | 0.08 | 0.6 | 1.885
Int. Simple:0.53x1.85:599818:1 | Niveau 2 | 0.08 | 0.6 | 1.885
Int. Simple:0.53x1.85:599819:1 | Niveau 2 | 0.08 | 0.6 | 1.885
Mur de base:Générique - Int.180:286717 | Niveau 0 |  | 0.37 | 1.63003 | Pset_EnvironmentalImpactIndicators - Reference: Générique - Int.180; sets with these values: 2
Mur de base:Générique - Int. 150 mm:354071:1 | Niveau 0 | Pset_EnvironmentalImpactIndicators - Reference: Générique - Int. 150 mm; sets with these values: 2
Int. Simple:0.53x1.85:599361:1 | Niveau 2 | 0.08 | 0.6 | 1.885
Int. Simple:PP (0.83m x 2.04m):568387:1 | Niveau 2 | 0.08 | 0.9 | 2.075
Int. Simple:PP (0.83m x 2.04m):560499:1 | Niveau 2 | 0.33 | 0.9 | 2.075
Int. Simple:PP0.93x2.04:560240:1 | Niveau 2 | 0.15 | 1 | 2.075
Placard coulissante - 3 panneaux:2.45X2.5:553684:1 | Niveau 1 | 0.07 | 2.4 | 2.67
Int. Simple:PP (0.83m x 2.04m):552238:1 | Niveau 1 | 0.07 | 0.9 | 2.075
Int. Simple:PP0.93x2.04:552062:1 | Niveau 1 | 0.07 | 1 | 2.075
Int. Simple:PP (0.83m x 2.04m):550886:1 | Niveau 1 | 0.09 | 0.9 | 2.075
Mur de base:Générique - Ext.370:373610 | Niveau 0 | 0.6748 | 3.81129 | 1.41127 | Pset_EnvironmentalImpactIndicators - Reference: Simple panneau; sets with these values: 2
Int. Simple:PP (0.83m x 2.04m):550759:1 | Niveau 1 | 0.1 | 0.9 | 2.075
Mur de base:Générique - Ext.370:373610 | Niveau 0 | 0.6748 | 2.485 | 1.41127 | Pset_EnvironmentalImpactIndicators - Reference: Simple panneau; sets with these values: 2
Mur de base:Générique - Ext.370:374217 | Demi-niveau | 0.6748 | 3.59795 | 1.41127 | Pset_EnvironmentalImpactIndicators - Reference: Simple panneau; sets with these values: 2
Mur de base:Générique - Int. 150 mm:269857 | Niveau 0 | Pset_EnvironmentalImpactIndicators - Reference: Générique - Int. 150 mm; sets with these values: 2; Qto_OpeningElementBaseQuantities - Area: 2.31659 m2
Mur de base:Générique - Int. 150 mm:269857 | Niveau 0 |  | 2.095 | 0.928583 | Pset_EnvironmentalImpactIndicators - Reference: Générique - Int. 150 mm; sets with these values: 2
Int. Simple:PP0.93x2.04:549915:1 | Niveau 1 | 0.1 | 1 | 2.075
Int. Simple:PP0.93x2.04:549891:1 | Niveau 1 | 0.1 | 1 | 2.075
Int. Simple:PP0.93x2.04:549520:1 | Niveau 1 | 0.1 | 1 | 2.075
Double (R):1.43m x 2.04m 2:548234:1 | Niveau 1 | 0.08 | 1.52 | 2.075
Int. Simple:PP (0.83m x 2.04m):548188:1 | Niveau 1 | 0.12 | 0.9 | 2.075
Mur de base:Générique - Ext.460:395177 | Niveau 0 |  | 1.28306 | 1.0426 | Pset_EnvironmentalImpactIndicators - Reference: Générique - Ext.460; sets with these values: 2
Mur de base:Générique - Int. 90:268293 | SS1 | Pset_EnvironmentalImpactIndicators - Reference: Générique - Int. 90; sets with these values: 2; Qto_OpeningElementBaseQuantities - Area: 0.974341 m2
Int. Simple:PP (0.83m x 2.04m):546734:1 | Niveau 1 | 0.1 | 0.9 | 2.075
Int. Simple:PP (0.83m x 2.04m):546527:1 | Niveau 1 | 0.09 | 0.9 | 2.075
Int. Simple:PP0.93x2.04:544037:1 | Niveau 1 | 0.13 | 1 | 2.075
Int. Simple:PP (0.83m x 2.04m):543814:1 | Niveau 1 | 0.13 | 0.9 | 2.075
Int. Simple:PP (0.63m x 2.10m):548021:1 | Niveau 1 | 0.15 | 0.7 | 2.135
Mur de base:Générique - Ext. 360:411205 | SS2 | Pset_EnvironmentalImpactIndicators - Reference: Générique - Ext. 360; sets with these values: 2; Qto_OpeningElementBaseQuantities - Area: 2.02241 m2
Mur de base:Générique - Int. 70 mm:412951 | SS2 | 0.3748 | 0.272 | 1.42927 | Pset_EnvironmentalImpactIndicators - Reference: Simple panneau; sets with these values: 2
Mur de base:Générique - Int. 70 mm:413010 | SS2 | 0.3748 | 2.93085 | 1.42927 | Pset_EnvironmentalImpactIndicators - Reference: Simple panneau; sets with these values: 2
Mur de base:Générique - Int. 70 mm:413057 | SS2 | 0.3748 | 2.223 | 1.42927 | Pset_EnvironmentalImpactIndicators - Reference: Simple panneau; sets with these values: 2
Int. Simple:PP (0.83m x 2.04m):543457:1 | Niveau 1 | 0.13 | 0.9 | 2.075
Mur de base:Générique - Int. 70 mm:414738 | SS2 | 0.3748 | 1.66315 | 1.39409 | Pset_EnvironmentalImpactIndicators - Reference: Simple panneau; sets with these values: 2
Mur de base:Générique - Int. 70 mm:415202 | SS2 | 0.3748 | 1.80502 | 1.42927 | Pset_EnvironmentalImpactIndicators - Reference: Simple panneau; sets with these values: 2
Mur de base:Générique - Int. 70 mm:415258 | SS2 | 0.3748 | 1.75684 | 1.42927 | Pset_EnvironmentalImpactIndicators - Reference: Simple panneau; sets with these values: 2
Mur de base:Générique - Int. 70 mm:415258 | SS2 | 0.3748 | 1.257 | 1.42927 | Pset_EnvironmentalImpactIndicators - Reference: Simple panneau; sets with these values: 2
Mur de base:Générique - Int. 70 mm:415258 | SS2 | 0.3748 | 1.00558 | 1.42927 | Pset_EnvironmentalImpactIndicators - Reference: Simple panneau; sets with these values: 2
Mur de base:Générique - Int. 70 mm:415258 | SS2 | Pset_EnvironmentalImpactIndicators - Reference: 0.73m x 2.24; sets with these values: 2
Int. Simple:PP (0.63m x 2.04m):543264:1 | Niveau 1 | 0.1 | 0.7 | 2.075
Int. Simple:PP (0.83m x 2.04m):542970:1 | Niveau 1 | 0.13 | 0.9 | 2.075
Int. Simple:PP (0.83m x 2.04m):532270:1 | Niveau 1 | 0.12 | 0.9 | 2.075
Int. Simple:PP (0.83m x 2.04m):532131:1 | Niveau 1 | 0.12 | 0.9 | 2.075
Int. Simple:PP (0.83m x 2.04m):532087:1 | Niveau 1 | 0.07 | 0.9 | 2.075
Mur de base:Générique - Int. 150 mm:417363:1 | SS3 | Pset_EnvironmentalImpactIndicators - Reference: Générique - Int. 150 mm; sets with these values: 2
Mur de base:Générique - Int. 150 mm:420924:1 | SS3 | Pset_EnvironmentalImpactIndicators - Reference: Générique - Int. 150 mm; sets with these values: 2
Mur de base:Générique - Int.230:423598 | SS3 | Pset_EnvironmentalImpactIndicators - Reference: Générique - Int.230; sets with these values: 2; Qto_OpeningElementBaseQuantities - Area: 0.472057 m2
Int. Simple:PP (0.83m x 2.04m):531909:1 | Niveau 1 | 0.07 | 0.9 | 2.075
Mur de base:Générique - Int.200:431583 | SS3 |  | 0.0896459 | 1.56949 | Pset_EnvironmentalImpactIndicators - Reference: Générique - Int.200; sets with these values: 2
Mur de base:Générique - Int.230:423598 | Demi-niveau | Pset_EnvironmentalImpactIndicators - Reference: Générique - Int.230; sets with these values: 2; Qto_OpeningElementBaseQuantities - Area: 2.17456 m2
Mur de base:Générique - Int. 360:443555 | SS3 | 3.048 | 2 | 1.25501 | Pset_EnvironmentalImpactIndicators - Reference: 1000 x 880mm; sets with these values: 2
Mur de base:Générique - Int. 100 mm:268142 | SS3 |  | 0.2793 | 0.0356667 | Pset_EnvironmentalImpactIndicators - Reference: Générique - Int. 100 mm; sets with these values: 2
Mur de base:Générique - Int. 100 mm:268142 | SS3 | Pset_EnvironmentalImpactIndicators - Reference: Générique - Int. 100 mm; sets with these values: 2; Qto_OpeningElementBaseQuantities - Area: 0.14859 m2
Mur de base:Générique - Int. 80:454885:1 | SS3 | Pset_EnvironmentalImpactIndicators - Reference: Générique - Int. 80; sets with these values: 2
Int. Simple:PP (0.63m x 2.04m):531658:1 | Niveau 1 | 0.08 | 0.7 | 2.075
Mur de base:Générique - Int. 80:476637:1 | SS1 | Pset_EnvironmentalImpactIndicators - Reference: Générique - Int. 80; sets with these values: 2
Mur de base:Générique - Int. 480 mm:296669 | SS1 | Pset_EnvironmentalImpactIndicators - Reference: Générique - Int. 480 mm; sets with these values: 2; Qto_OpeningElementBaseQuantities - Area: 0.495869 m2
Int. Simple:PP (0.83m x 2.04m):531554:1 | Niveau 1 | 0.08 | 0.9 | 2.075
Mur de base:Générique - Int. 80:483706:1 | SS1 | Pset_EnvironmentalImpactIndicators - Reference: Générique - Int. 80; sets with these values: 2
Mur de base:Générique - Int. 70 mm:489998 | SS1 | 0.9 | 1.985 | 0.1 | Pset_EnvironmentalImpactIndicators - Reference: PP (0.83m x 1.95; Pset_DoorCommon - IsExternal: no; Reference: PP (0.83m x 1.95
Mur de base:Générique - Int.180:491488 | SS3 | 3.048 | 2 | 1.25501 | Pset_EnvironmentalImpactIndicators - Reference: 1000 x 880mm; Pset_BuildingElementProxyCommon - IsExternal: no; Reference: 1000 x 880mm
Mur de base:Générique - Int.180:493605 | SS1 | 3.048 | 1.905 | 1 | Pset_EnvironmentalImpactIndicators - Reference: 0.93x1.87; sets with these values: 2
Int. Simple:PP (0.83m x 2.04m):531521:1 | Niveau 1 | 0.1 | 0.9 | 2.075
Mur de base:Générique - Int. 130 mm:496119:1 | SS1 | Pset_EnvironmentalImpactIndicators - Reference: Générique - Int. 130 mm; sets with these values: 2
Mur de base:Générique - Int. 130 mm:496119:2 | SS1 | Pset_EnvironmentalImpactIndicators - Reference: Générique - Int. 130 mm; sets with these values: 2
Mur de base:Générique - Int. 130 mm:496119:3 | SS1 | Pset_EnvironmentalImpactIndicators - Reference: Générique - Int. 130 mm; sets with these values: 2
Int. Simple:PP (0.83m x 2.04m):531480:1 | Niveau 1 | 0.07 | 0.9 | 2.075
Int. Simple:PP (0.83m x 2.04m):531594:1 | Niveau 1 | 0.1 | 0.9 | 2.075
Int. Simple:PP (0.63m x 2.04m):529448:1 | Niveau 1 | 0.05 | 0.7 | 2.075
Int. Simple:PP (0.83m x 2.04m):528909:1 | Niveau 1 | 0.07 | 0.9 | 2.075
Int. Simple:PP (0.83m x 2.04m):528559:1 | Niveau 1 | 0.08 | 0.9 | 2.075
Int. Simple:PP (0.83m x 2.04m):528255:1 | Niveau 1 | 0.1 | 0.9 | 2.075
Int. Simple:PP (0.83m x 2.04m):528217:1 | Niveau 1 | 0.1 | 0.9 | 2.075
Int. Simple:PP (0.83m x 2.04m):527954:1 | Niveau 1 | 0.13 | 0.9 | 2.075
Int. Simple:PP (0.83m x 2.04m):527842:1 | Niveau 1 | 0.13 | 0.9 | 2.075
Int. Simple:PP0.93x2.04:527735:1 | Niveau 1 | 0.42 | 1 | 2.075
Int. Simple:PP (0.63m x 2.04m):527076:1 | Niveau 1 | 0.08 | 0.7 | 2.075
Int. Simple:PP (0.63m x 2.04m):526662:1 | Niveau 1 | 0.08 | 0.7 | 2.075
Int. Simple:PP0.93x2.04:549853:1 | Niveau 1 | 0.08 | 1 | 2.075
Int. Simple:PP (0.83m x 2.04m):548435:1 | Niveau 1 | 0.08 | 0.9 | 2.075
2 x Mur de base:Générique - Ext. 220 mm:503856 | SS3
4 x Mur de base:Générique - Ext. 220 mm:503844 | SS3
Int. Simple:0.83x1.87:494050:1 | SS1 | 0.07 | 0.9 | 1.905
Int. Simple:0.93x1.87:493698:1 | SS1 | 0.08 | 1 | 1.905
Int. Simple:PP (0.63m x 1.85m):493644:1 | SS1 | 0.08 | 0.7 | 1.885
Int. Simple:PP0.93x2.04:492427:1 | SS1 | 0.07 | 1 | 2.075
Int. Simple:PP (0.83m x 2.04m):492395:1 | SS1 | 0.07 | 0.9 | 2.075
Mur de base:Générique - Ext. 300 mm:523170:1 | SS3 | Pset_EnvironmentalImpactIndicators - Reference: Générique - Ext. 300 mm; sets with these values: 2
Mur de base:Générique - Ext. 300 mm:523170:2 | SS3 | Pset_EnvironmentalImpactIndicators - Reference: Générique - Ext. 300 mm; sets with these values: 2
Mur de base:Générique - Int. 80:526133 | Niveau 1 | 0.08 | 2.26528 | 1.29011 | Pset_EnvironmentalImpactIndicators - Reference: Générique - Int. 80; sets with these values: 2
Mur de base:Générique - Int.550:526641:1 | Niveau 1 | 3.01021 | 0.817 | 0.55 | Pset_EnvironmentalImpactIndicators - Reference: Générique - Int.550; sets with these values: 2
Mur de base:Int. Plâtre 70 mm:528633 | Niveau 1 | 0.9 | 2.075 | 0.07 | Pset_EnvironmentalImpactIndicators - Reference: PP (0.83m x 2.04m); sets with these values: 2
Mur de base:Int. Plâtre 70 mm:29322 | Niveau 1 |  | 0.826613 | 0.283962 | Pset_EnvironmentalImpactIndicators - Reference: Int. Plâtre 70 mm; sets with these values: 2
Mur de base:Générique - Int. 100 mm:531175 | Niveau 1 | 0.9 | 2.075 | 0.1 | Pset_EnvironmentalImpactIndicators - Reference: PP (0.83m x 2.04m); sets with these values: 2
Mur de base:Générique - Int. 100 mm:268142 | Niveau 1 |  | 0.826613 | 0.353962 | Pset_EnvironmentalImpactIndicators - Reference: Générique - Int. 100 mm; sets with these values: 2
Mur de base:Générique - Int. 70 mm:29644 | Niveau 1 |  | 0.22 | 0.826613 | Pset_EnvironmentalImpactIndicators - Reference: Générique - Int. 70 mm; sets with these values: 2
Mur de base:Générique - Int. 90:532425 | Niveau 1 | 0.3948 | 13.7939 | 2.69696 | Pset_EnvironmentalImpactIndicators - Reference: Simple panneau; sets with these values: 2
Int. Simple:PP (0.83m x 2.04m):492301:1 | SS1 | 0.07 | 0.9 | 2.075
Int. Simple:PP0.93x2.04:491489:1 | SS3 | 0.18 | 1 | 2.075
Int. Simple:PP0.93x2.04:491258:1 | SS1 | 0.15 | 1 | 2.075
Int. Simple:PP (0.83m x 2.04m):490806:1 | SS1 | 0.07 | 0.9 | 2.075
Int. Simple:PP0.93x2.04:489815:1 | SS1 | 0.07 | 1 | 2.075
Int. Simple:PP (0.63m x 2.04m):487722:1 | SS1 | 0.08 | 0.7 | 2.075
Int. Simple:PP (0.63m x 2.04m):487400:1 | SS1 | 0.08 | 0.7 | 2.075
Int. Simple:PP (0.63m x 2.04m):487359:1 | SS1 | 0.08 | 0.7 | 2.075
Int. Simple:PP (0.83m x 2.04m):487281:1 | SS1 | 0.1 | 0.9 | 2.075
Int. Simple:PP (0.83m x 1.95:485751:1 | Demi-niveau | 0.1 | 0.9 | 1.985
Int. Simple:PP (0.83m x 1.95:485297:1 | SS1 | 0.07 | 0.9 | 1.985
Int. Simple:PP (0.83m x 2.04m):487208:1 | SS1 | 0.1 | 0.9 | 2.075
Int. Simple:PP (0.83m x 2.04m):476649:1 | SS1 | 0.18 | 0.9 | 2.075
Verre - simple:Verre - simple:476560:1 | SS1 | 0.1 | 0.97 | 1.95
Mur de base:Générique - Int. 70 mm:29644 | Niveau 1 |  | 0.345003 | 0.826613 | Pset_EnvironmentalImpactIndicators - Reference: Générique - Int. 70 mm; sets with these values: 2
Verre - simple:Verre - simple:476567:1 | SS1 | 0.1 | 0.97 | 1.95
Verre - simple:Verre - simple:476561:1 | SS1 | 0.1 | 0.97 | 1.95
Verre - simple:Verre - simple:476562:1 | SS1 | 0.1 | 0.97 | 1.95
Verre - simple:Verre - simple:476563:1 | SS1 | 0.1 | 0.97 | 1.95
Verre - simple:Verre - simple:476564:1 | SS1 | 0.1 | 0.97 | 1.95
Verre - simple:Verre - simple:476565:1 | SS1 | 0.1 | 0.97 | 1.95
Verre - simple:Verre - simple:476566:1 | SS1 | 0.1 | 0.97 | 1.95
Int. Simple:PP (0.73m x 2.04m):459388:1 | SS1 | 0.09 | 0.8 | 2.075
Int. Simple:PP (0.63m x 2.04m):458630:1 | SS1 | 0.09 | 0.7 | 2.075
Double (R):1.83X2.25:457834:1 | SS3 | 0.3 | 1.9 | 2.285
Double (R):1.63m x 2.04m:457793:1 | SS3 | 0.3 | 1.7 | 2.075
Int. Simple:PP0.93x2.04:457731:1 | SS3 | 0.3 | 1 | 2.075
Int. Simple:PP0.93x2.04:457500:1 | SS3 | 0.2 | 1 | 2.075
Mur de base:Générique - Int. 150 mm:542559:1 | Niveau 1 | Pset_EnvironmentalImpactIndicators - Reference: Générique - Int. 150 mm; sets with these values: 2
Mur de base:Générique - Int. 130 mm:286294 | Niveau 1 |  | 0.826613 | 0.369656 | Pset_EnvironmentalImpactIndicators - Reference: Générique - Int. 130 mm; sets with these values: 2
Mur de base:Générique - Int. 100 mm:550272 | Niveau 1 | 0.9 | 2.075 | 0.09 | Pset_EnvironmentalImpactIndicators - Reference: PP (0.83m x 2.04m); sets with these values: 2
Mur de base:Générique - Int. 70 mm:552441 | Niveau 1 | 0.3748 | 2.512 | 2.3671 | Pset_EnvironmentalImpactIndicators - Reference: Simple panneau; sets with these values: 2
Double (R):1.63m x 2.04m:457454:1 | SS3 | 0.2 | 1.7 | 2.075
Double (R):1.63m x 2.04m:457368:1 | SS3 | 0.2 | 1.7 | 2.075
Int. Simple:PP0.93x2.04:453413:1 | SS3 | 0.2 | 1 | 2.075
Int. Simple:PP0.93x2.04:447111:1 | SS3 | 0.1 | 1 | 2.075
Int. Simple:PP0.93x2.10:445601:1 | SS3 | 0.2 | 1 | 2.135
Int. Simple:PP0.93x2.04:442730:1 | SS3 | 0.15 | 1 | 2.075
Mur de base:Générique - Int. 130 mm:559154:1 | Niveau 2 | Pset_EnvironmentalImpactIndicators - Reference: Générique - Int. 130 mm; sets with these values: 2
Mur de base:Générique - Int. 130 mm:559154:2 | Niveau 2 | Pset_EnvironmentalImpactIndicators - Reference: Générique - Int. 130 mm; sets with these values: 2
Mur de base:Générique - Ext. 220 mm:559276:1 | Niveau 2 | Pset_EnvironmentalImpactIndicators - Reference: Générique - Ext. 220 mm; sets with these values: 2
Int. Simple:PP0.93x2.04:441441:1 | SS3 | 0.15 | 1 | 2.075
Int. Simple:PP0.95x2.04 2:441158:1 | SS3 | 0.15 | 1.02 | 2.075
Int. Simple:PP0.93x2.04:438859:1 | SS3 | 0.15 | 1 | 2.075
Int. Simple:PP0.93x2.04:437693:1 | SS3 | 0.08 | 1 | 2.075
Mur de base:Générique - Int. 80:568332:1 | Niveau 2 | Pset_EnvironmentalImpactIndicators - Reference: Générique - Int. 80; sets with these values: 2
Mur de base:Générique - Int. 80:568345 | Niveau 2 | 0.6 | 1.885 | 0.08 | Pset_EnvironmentalImpactIndicators - Reference: 0.53x1.85; sets with these values: 2
Mur de base:Générique - Int. 70 mm:29644 | Niveau 2 |  | 0.18 | 0.729 | Pset_EnvironmentalImpactIndicators - Reference: Générique - Int. 70 mm; sets with these values: 2
Int. Simple:PP0.95x2.04 2:432642:1 | SS3 | 0.15 | 1.02 | 2.075
Int. Simple:PP0.93x2.04:435752:1 | SS3 | 0.15 | 1 | 2.075
Int. Simple:PP0.95x2.04 2:420991:1 | SS3 | 0.15 | 1.02 | 2.075
Mur de base:Générique - Ext. 200 mm:572727:1 | Niveau 2 | Pset_EnvironmentalImpactIndicators - Reference: Générique - Ext. 200 mm; sets with these values: 2
Mur de base:Générique - Int. 80:572784:1 | Niveau 2 | Pset_EnvironmentalImpactIndicators - Reference: Générique - Int. 80; sets with these values: 2
Int. Simple:Ext 0.95X2.04:421118:1 | SS3 | 0.15 | 1.02 | 2.075
Int. Simple:Ext 0.95X2.04:418591:1 | SS3 | 0.37 | 1.02 | 2.075
Int. Simple:PP0.95x2.04 2:420238:1 | SS3 | 0.15 | 1.02 | 2.075
Mur de base:Générique - Int. 70 mm:415258 | SS2
Mur de base:Générique - Ext. 220 mm:581503 | Niveau 2 | 0.5248 | 1.26926 | 1.9 | Pset_EnvironmentalImpactIndicators - Reference: Simple panneau; sets with these values: 2
Mur de base:Générique - Int.120:581990 | Niveau 2 | 0.12 | 0.621228 | 1.9391 | Pset_EnvironmentalImpactIndicators - Reference: Générique - Int.120; sets with these values: 2
2 x Mur de base:Générique - Int. 70 mm:414316 | SS2
Mur de base:Générique - Int. 70 mm:413057 | SS2
Mur de base:Générique - Int.50:589584 | Niveau 2 | 0.3548 | 7.60661 | 2.402 | Pset_EnvironmentalImpactIndicators - Reference: Simple panneau; sets with these values: 2
Mur de base:Générique - Int. 70 mm:412951 | SS2
Mur de base:Générique - Ext. 100 mm:396089 | Demi-niveau
Int. Simple:0.65x1.25:375898:1 | Demi-niveau | 0.2 | 0.72 | 1.185
Double (R):1.93x2.05 pvc blanc:375545:1 | Demi-niveau | 0.2 | 2 | 2.085
Mur mobile:Mur mobile:378760:1 | Niveau 0 | 0.08 | 8.15 | 2.875
Mur mobile:Mur mobile:378873:1 | Niveau 0 | 0.08 | 8.15 | 2.875
Int. Simple:PP (0.63m x 2.10m):339820:1 | Niveau 0 | 0.16 | 0.7 | 2.135
Mur de base:Générique - Ext. 200 mm:592508:1 | Niveau 2 | Pset_EnvironmentalImpactIndicators - Reference: Générique - Ext. 200 mm; sets with these values: 2
Mur de base:Générique - Ext. 200 mm:592508:2 | Niveau 2 | Pset_EnvironmentalImpactIndicators - Reference: Générique - Ext. 200 mm; sets with these values: 2
Int. Simple:PP (0.83m x 2.04m):301212:1 | Niveau 0 | 0.27 | 0.9 | 2.075
Mur de base:Générique - Ext.340:595101 | Niveau 2 | 0.6448 | 1.03318 | 1.9 | Pset_EnvironmentalImpactIndicators - Reference: Simple panneau; sets with these values: 2
Mur de base:Générique - Ext.340:595101 | Niveau 2 | 0.6448 | 1.00475 | 1.9 | Pset_EnvironmentalImpactIndicators - Reference: Simple panneau; sets with these values: 2
Int. Simple:PP (0.63m x 2.04m):301925:1 | Niveau 0 | 0.07 | 0.7 | 2.075
Int. Simple:PP (0.83m x 2.04m):299277:1 | Niveau 0 | 0.1 | 0.9 | 2.075
Mur de base:Générique - Int.180:596812:1 | Niveau 2 | Pset_EnvironmentalImpactIndicators - Reference: Générique - Int.180; sets with these values: 2
Mur de base:Générique - Int. 150 mm:610728 | SS3 | 0.15 | 0.427743 | 0.45658 | Pset_EnvironmentalImpactIndicators - Reference: Générique - Int. 150 mm; sets with these values: 2
Int. Simple:PP0.93x2.04:296976:1 | Niveau 0 | 0.1 | 1 | 2.075
Int. Simple:1.13x2.04 vitrée:293850:1 | Niveau 0 | 0.15 | 1.2 | 2.075
Mur de base:Int. Plâtre 70 mm:627683 | Niveau 2 | 0.3748 | 2.965 | 2.402 | Pset_EnvironmentalImpactIndicators - Reference: Simple panneau; sets with these values: 2
Int. Simple:PP (0.63m x 2.04m):290711:1 | Niveau 0 | 0.09 | 0.7 | 2.075
Mur de base:Générique - Ext. 200 mm:651243:1 | Niveau 2 | Pset_EnvironmentalImpactIndicators - Reference: Générique - Ext. 200 mm; sets with these values: 2
Mur de base:Générique - Ext. 200 mm:651243 | Niveau 2 | 3.048 | 0.77 | 2.075 | Pset_EnvironmentalImpactIndicators - Reference: 0.70x2.04; Pset_DoorCommon - IsExternal: yes; Reference: 0.70x2.04
Int. Simple:PP (0.83m x 2.04m):290643:1 | Niveau 0 | 0.16 | 0.9 | 2.075
Int. Simple:PP (0.83m x 2.04m):339741:1 | Niveau 0 | 0.18 | 0.9 | 2.075
Int. Simple:PP0.93x2.04:268018:1 | Niveau 0 | 0.38 | 1 | 2.075
Int. Simple:PP0.93x2.04:268812:1 | Niveau 0 | 0.38 | 1 | 2.075
Int. Simple:PP0.93x2.04:269505:1 | Niveau 0 | 0.38 | 1 | 2.075
Int. Simple:PP (0.83m x 2.04m):281242:1 | Niveau 0 | 0.07 | 0.9 | 2.075
Int. Simple:PP (0.83m x 2.04m):281249:1 | Niveau 0 | 0.07 | 0.9 | 2.075
Double (R):1.10x2.04:283497:1 | Niveau 0 | 0.13 | 1.17 | 2.075
Placard coulissante - 2 panneaux:1.65x2.75:285139:1 | Niveau 0 | 0.07 | 1.7 | 2.75
Int. Simple:PP (0.73m x 2.04m):286400:1 | Niveau 0 | 0.07 | 0.8 | 2.075

# IfcPlate: Panneau système:Plein (45)
Type - PredefinedType: CURTAIN_PANEL; Material: Verre 0.04 m
Type - Pset_EnvironmentalImpactIndicators - Reference: Plein
Type - Pset_PlateCommon - IsExternal: no; Reference: Plein; ThermalTransmittance: 3.7021 kg/K/s3
Name (Panneau système:Plein:...) | In
532530 | Niveau 1
532557 | Niveau 1
532584 | Niveau 1
532609 | Niveau 1
532632 | Niveau 1
532676 | Niveau 1
532715 | Niveau 1
532792 | Niveau 1
532811 | Niveau 1
532840 | Niveau 1
539588 | Niveau 1
539745 | Niveau 1
539782 | Niveau 1
539805 | Niveau 1
539846 | Niveau 1
540486 | Niveau 1
540787 | Niveau 1
540511 | Niveau 1
540528 | Niveau 1
540547 | Niveau 1
542010 | Niveau 1
541451 | Niveau 1
541650 | Niveau 1
541695 | Niveau 1
541486 | Niveau 1
554086 | Niveau 1
554146 | Niveau 1
554185 | Niveau 1
554255 | Niveau 1
554256 | Niveau 1
554257 | Niveau 1
554625 | Niveau 1
554594 | Niveau 1
554712 | Niveau 1
554713 | Niveau 1
554714 | Niveau 1
570753 | Niveau 2
570708 | Niveau 2
579228 | Niveau 2
579235 | Niveau 2
579232 | Niveau 2
579243 | Niveau 2
579887 | Niveau 2
589586 | Niveau 2
589593 | Niveau 2

# IfcPlate: Panneau système:Vitré (237)
Type - PredefinedType: CURTAIN_PANEL; Material: Verre 0.04 m
Type - Pset_EnvironmentalImpactIndicators - Reference: Vitré
Type - Pset_PlateCommon - IsExternal: no; Reference: Vitré; ThermalTransmittance: 6.7069 kg/K/s3
Name (Panneau système:Vitré:...) | In
312662 | Niveau 0
312979 | Niveau 0
313077 | Niveau 0
313257 | Niveau 0
313421 | Niveau 0
313542 | Niveau 0
313851 | Niveau 0
313924 | Niveau 0
314824 | Niveau 1
335788 | Niveau 1
314959 | Niveau 1
335656 | Niveau 1
335708 | Niveau 1
314966 | Niveau 1
314968 | Niveau 1
326338 | Niveau 1
335347 | Niveau 1
335302 | Niveau 1
336083 | Niveau 0
336119 | Niveau 0
340725 | Niveau 0
340791 | Niveau 0
340839 | Niveau 0
369556 | Niveau 0
369668 | Niveau 0
369850 | Niveau 0
369854 | Niveau 0
369873 | Niveau 0
369877 | Niveau 0
369896 | Niveau 0
369900 | Niveau 0
369919 | Niveau 0
369923 | Niveau 0
369942 | Niveau 0
369946 | Niveau 0
369965 | Niveau 0
369969 | Niveau 0
369988 | Niveau 0
369992 | Niveau 0
370011 | Niveau 0
370015 | Niveau 0
370034 | Niveau 0
370038 | Niveau 0
388349 | Niveau 0
388474 | Niveau 0
388448 | Niveau 0
388378 | Niveau 0
388475 | Niveau 0
388449 | Niveau 0
392093 | Niveau 0
392097 | Niveau 0
392095 | Niveau 0
392160 | Niveau 0
392382 | Niveau 0
404727 | Niveau 0
404729 | Niveau 0
404763 | Niveau 0
404765 | Niveau 0
404767 | Niveau 0
404856 | Niveau 0
404858 | Niveau 0
404860 | Niveau 0
406689 | SS2
407561 | SS2
413494 | SS2
415286 | SS2
416871 | SS2
415294 | SS2
416784 | SS2
415301 | SS2
416668 | SS2
415343 | SS2
416560 | SS2
415723 | SS2
415727 | SS2
415725 | SS2
415801 | SS2
415949 | SS2
511211 | Niveau 1
511221 | Niveau 1
511231 | Niveau 1
511241 | Niveau 1
511251 | Niveau 1
511261 | Niveau 1
511271 | Niveau 1
511281 | Niveau 1
511291 | Niveau 1
511301 | Niveau 1
511311 | Niveau 1
511321 | Niveau 1
511331 | Niveau 1
511341 | Niveau 1
512589 | Niveau 1
512766 | Niveau 1
512994 | Niveau 1
513010 | Niveau 1
513026 | Niveau 1
513042 | Niveau 1
513058 | Niveau 1
513074 | Niveau 1
513090 | Niveau 1
513106 | Niveau 1
513122 | Niveau 1
513138 | Niveau 1
513154 | Niveau 1
513170 | Niveau 1
513186 | Niveau 1
513202 | Niveau 1
513720 | Niveau 1
513726 | Niveau 1
514542 | Niveau 1
514548 | Niveau 1
518366 | Niveau 1
518437 | Niveau 1
518558 | Niveau 1
518576 | Niveau 1
518594 | Niveau 1
518612 | Niveau 1
518628 | Niveau 1
518646 | Niveau 1
518664 | Niveau 1
518682 | Niveau 1
518700 | Niveau 1
518718 | Niveau 1
518736 | Niveau 1
518754 | Niveau 1
518772 | Niveau 1
518826 | Niveau 1
519493 | Niveau 1
519528 | Niveau 1
519653 | Niveau 1
519714 | Niveau 1
519772 | Niveau 1
532940 | Niveau 1
533264 | Niveau 1
533265 | Niveau 1
533266 | Niveau 1
533267 | Niveau 1
533269 | Niveau 1
533270 | Niveau 1
533273 | Niveau 1
533274 | Niveau 1
533275 | Niveau 1
533276 | Niveau 1
533180 | Niveau 1
533094 | Niveau 1
533095 | Niveau 1
533096 | Niveau 1
533097 | Niveau 1
533098 | Niveau 1
533099 | Niveau 1
533100 | Niveau 1
533101 | Niveau 1
533102 | Niveau 1
533103 | Niveau 1
533104 | Niveau 1
533105 | Niveau 1
533106 | Niveau 1
533107 | Niveau 1
533108 | Niveau 1
539920 | Niveau 1
539921 | Niveau 1
539922 | Niveau 1
539923 | Niveau 1
539924 | Niveau 1
539875 | Niveau 1
539876 | Niveau 1
539877 | Niveau 1
539878 | Niveau 1
539879 | Niveau 1
540604 | Niveau 1
540788 | Niveau 1
540605 | Niveau 1
540606 | Niveau 1
540607 | Niveau 1
540564 | Niveau 1
540789 | Niveau 1
540565 | Niveau 1
540566 | Niveau 1
540567 | Niveau 1
542143 | Niveau 1
541930 | Niveau 1
542011 | Niveau 1
541596 | Niveau 1
541651 | Niveau 1
541696 | Niveau 1
541619 | Niveau 1
541652 | Niveau 1
541697 | Niveau 1
541567 | Niveau 1
541540 | Niveau 1
554222 | Niveau 1
554223 | Niveau 1
554224 | Niveau 1
554655 | Niveau 1
554656 | Niveau 1
570754 | Niveau 2
570709 | Niveau 2
570565 | Niveau 2
570661 | Niveau 2
579241 | Niveau 2
579239 | Niveau 2
579233 | Niveau 2
580176 | Niveau 2
582840 | Niveau 2
582927 | Niveau 2
583080 | Niveau 2
583082 | Niveau 2
583096 | Niveau 2
583098 | Niveau 2
583226 | Niveau 2
583403 | Niveau 2
583405 | Niveau 2
583419 | Niveau 2
583421 | Niveau 2
583435 | Niveau 2
583437 | Niveau 2
589599 | Niveau 2
589601 | Niveau 2
589597 | Niveau 2
589591 | Niveau 2
590434 | Niveau 2
590615 | Niveau 2
590484 | Niveau 2
591099 | Niveau 2
591109 | Niveau 2
591101 | Niveau 2
591394 | Niveau 2
595771 | Niveau 2
595974 | Niveau 2
596342 | Niveau 2
623681 | Niveau 1
623765 | Niveau 1
623771 | Niveau 1
623886 | Niveau 1
627729 | Niveau 2
627793 | Niveau 2

# IfcRailing: Garde-corps:Au Mur (14)
Material: Pin (1)
Pset_EnvironmentalImpactIndicators - Reference: Au Mur
Pset_RailingCommon - IsExternal: no; Reference: Au Mur; Height: 0.9 m
Name (Garde-corps:Au Mur:...) | In | Length (m)
346032 | Niveau 0 | 2.64817
346036 | Niveau 0 | 1.19231
351029 | Niveau 0 | 11.1877
351033 | Niveau 0 | 5.18044
400783 | SS1 | 6.61195
400787 | SS1 | 6.61195
444341 | SS3 | 2.37883
446829 | SS3 | 1.68668
446833 | SS3 | 1.69068
447453 | SS3 | 2.07621
448145 | SS2 | 3.52408
457087 | SS3 | 9.03581
458213 | SS3 | 2.92629
582549 | Niveau 1 | 11.5792

# IfcRailing: Garde-corps:Au Mur 2 (2)
Material: Acier, finition peinture, bleu
Pset_EnvironmentalImpactIndicators - Reference: Au Mur 2
Pset_RailingCommon - IsExternal: no; Reference: Au Mur 2; Height: 0.8 m
Name (Garde-corps:Au Mur 2:...) | In | Length (m)
462614 | SS2 | 3.50171
462618 | SS3 | 9.19834

# IfcRailing: Garde-corps:Remplissage Inférieur (7)
Material: Métal - Acier inoxydable, poli, Verre
Pset_EnvironmentalImpactIndicators - Reference: Remplissage Inférieur
Pset_RailingCommon - IsExternal: no; Reference: Remplissage Inférieur; Height: 0.9 m
Name (Garde-corps:Remplissage Inférieur:...) | In | Length (m)
354232 | Niveau 0 | 8.7523
432843 | SS2 | 1.242
447449 | SS3 | 2.04221
448141 | SS2 | 3.53368
448549 | SS3 | 2.01208
448606 | SS3 | 1.93082
608640 | SS1 | 3.76505

# IfcRailing: Garde-corps:Type Bateau (4)
Material: Peinture - Grise
Pset_EnvironmentalImpactIndicators - Reference: Type Bateau
Pset_RailingCommon - IsExternal: no; Reference: Type Bateau; Height: 0.9 m
Name (Garde-corps:Type Bateau:...) | In | Length (m)
271010 | Niveau 0 | 5.84137
390475 | Demi-niveau | 2.10672
427881 | SS3 | 4.4676
549375 | Niveau 1 | 1.06278

# IfcRailing: Garde-corps:Type Bateau 3 (2)
In: Niveau 0
Material: Peinture - Grise, Acier, finition peinture, bleu
Pset_EnvironmentalImpactIndicators - Reference: Type Bateau 3
Pset_RailingCommon - IsExternal: no; Reference: Type Bateau 3; Height: 0.65 m
Name (Garde-corps:Type Bateau 3:...) | Length (m)
465840 | 2.237
465873 | 7.38658

# IfcRailing: Garde-corps:Type Bateau 5, Garde-corps:Type Bateau 5:601269
In: Niveau 0
Material: Peinture - Grise
Pset_EnvironmentalImpactIndicators - Reference: Type Bateau 5
Pset_RailingCommon - IsExternal: no; Reference: Type Bateau 5; Height: 1 m
Qto_RailingBaseQuantities - Length: 74.1945 m

# IfcRailing: Garde-corps:garde corps d'entrée principale (4)
In: Niveau 0
Material: Métal - Acier inoxydable, poli
Pset_EnvironmentalImpactIndicators - Reference: garde corps d'entrée principale
Pset_RailingCommon - IsExternal: no; Reference: garde corps d'entrée principale; Height: 0.9 m
Name (Garde-corps:garde corps d'entrée principale:...) | Length (m)
638839 | 4.23947
638843 | 4.24407
639845 | 1.38794
639948 | 1.3676

# IfcRoof: Toit de base:Toit - 100 mm (3)
In: Niveau 2
Type - Pset_EnvironmentalImpactIndicators - Reference: Toit - 100 mm
Type - Pset_RoofCommon - IsExternal: yes; Reference: Toit - 100 mm; ThermalTransmittance: 38.3333 kg/K/s3
Name (Toit de base:Toit - 100 mm:...)
598684
607515 | Material: Protection humidité 0.03 m, Maçonnerie - Isolant 0.1 m, Béton - Béton coulé sur place 0.1 m
607980

# IfcRoof: Toit de base:Toit - 100 mm béton (2)
In: Niveau 2
Pset_EnvironmentalImpactIndicators - Reference: Toit - 100 mm béton
Pset_RoofCommon - IsExternal: yes; Reference: Toit - 100 mm béton
Name (Toit de base:Toit - 100 mm béton:...)
591816
596148

# IfcRoof: Toit de base:Toit - 100 mm béton, Toit de base:Toit - 100 mm béton:597835
In: Niveau 2
Type - Pset_EnvironmentalImpactIndicators - Reference: Toit - 100 mm béton
Type - Pset_RoofCommon - IsExternal: yes; Reference: Toit - 100 mm béton

# IfcRoof: Toit de base:Toit - 200 mm 2, Toit de base:Toit - 200 mm 2:600880
In: Niveau 2
Pset_EnvironmentalImpactIndicators - Reference: Toit - 200 mm 2
Pset_RoofCommon - IsExternal: yes; Reference: Toit - 200 mm 2; ThermalTransmittance: 38.3333 kg/K/s3

# IfcRoof: Toit de base:Toit - 200 mm 2 (2)
In: Niveau 2
Type - Pset_EnvironmentalImpactIndicators - Reference: Toit - 200 mm 2
Type - Pset_RoofCommon - IsExternal: yes; Reference: Toit - 200 mm 2; ThermalTransmittance: 38.3333 kg/K/s3
Name (Toit de base:Toit - 200 mm 2:...)
597087 | Material: Protection humidité 0.03 m, Maçonnerie - Isolant 0.1 m, Béton - Béton coulé sur place 0.2 m
600053

# IfcRoof: Toit de base:Toit - 200 mm 3, Toit de base:Toit - 200 mm 3:601105
In: Niveau 2
Type - Pset_EnvironmentalImpactIndicators - Reference: Toit - 200 mm 3
Type - Pset_RoofCommon - IsExternal: yes; Reference: Toit - 200 mm 3; ThermalTransmittance: 38.3333 kg/K/s3
Material: carrelage Ext 0.05 m, plot 0.45 m, Protection humidité 0.03 m, Maçonnerie - Isolant 0.1 m, Béton - Béton coulé sur place 0.2 m

# IfcRoof: Toit de base:Toit - métallique (3)
In: Niveau 1
Type - Pset_EnvironmentalImpactIndicators - Reference: Toit - métallique
Type - Pset_RoofCommon - IsExternal: yes; Reference: Toit - métallique
Material: alu finifion bleu 0.1 m
Name (Toit de base:Toit - métallique:...)
641748
642063
642191

# IfcRoof: Toit de base:Toit -760, Toit de base:Toit -760:499665
In: Demi-niveau
Type - Pset_EnvironmentalImpactIndicators - Reference: Toit -760
Type - Pset_RoofCommon - IsExternal: yes; Reference: Toit -760
Material: Béton - Béton coulé sur place 0.76 m

# IfcSlab: Sol:Dalle béton 200 finition carrelage 20 mm + moquette 15, Sol:Dalle béton 200 finition carrelage 20 mm + moquette 15:523994
In: Niveau 1
Type - PredefinedType: FLOOR; Material: moquette bleu 0.015 m, Carrelage beige 0.02 m, Béton - Béton coulé sur place 0.2 m
Type - Pset_EnvironmentalImpactIndicators - Reference: Dalle béton 200 finition carrelage 20 mm + moquette 15
Type - Pset_ReinforcementBarPitchOfSlab - Reference: Dalle béton 200 finition carrelage 20 mm + moquette 15
Type - Pset_SlabCommon - IsExternal: no; Reference: Dalle béton 200 finition carrelage 20 mm + moquette 15
Pset_EnvironmentalImpactIndicators - sets with these values: 2
Pset_SlabCommon - LoadBearing: no; PitchAngle: 0 deg
Qto_SlabBaseQuantities - NetArea: 983.193 m2; NetVolume: 111.945 m3

# IfcSlab: Sol:Dalle en béton - 66mm (2)
In: Niveau 0
Type - PredefinedType: FLOOR; Material: PVC - Blanc 0.066 m
Type - Pset_EnvironmentalImpactIndicators - Reference: Dalle en béton - 66mm
Type - Pset_ReinforcementBarPitchOfSlab - Reference: Dalle en béton - 66mm
Type - Pset_SlabCommon - IsExternal: no; Reference: Dalle en béton - 66mm
Pset_EnvironmentalImpactIndicators - sets with these values: 2
Pset_SlabCommon - LoadBearing: no; PitchAngle: 0 deg
Name (Sol:Dalle en béton - 66mm:...) | NetArea (m2) | NetVolume (m3)
335918 | 14.4916 | 0.419715
641698 | 2.94459 | 0.0778874 | Qto_SlabBaseQuantities - GrossArea: 1.18011 m2; GrossVolume: 0.0778874 m3; Perimeter: 8.85405 m; Width: 0.066 m

# IfcSlab: Sol:Dalle en béton -150mm, Sol:Dalle en béton -150mm:465462
In: Demi-niveau
Type - PredefinedType: FLOOR; Material: Béton - Béton coulé sur place 0.15 m
Type - Pset_EnvironmentalImpactIndicators - Reference: Dalle en béton -150mm
Type - Pset_ReinforcementBarPitchOfSlab - Reference: Dalle en béton -150mm
Type - Pset_SlabCommon - IsExternal: no; Reference: Dalle en béton -150mm
Pset_EnvironmentalImpactIndicators - sets with these values: 2
Pset_SlabCommon - LoadBearing: no; PitchAngle: 0 deg
Qto_SlabBaseQuantities - GrossArea: 3.48743 m2; NetArea: 8.15502 m2; GrossVolume: 0.523114 m3; NetVolume: 0.523114 m3; Perimeter: 7.86773 m; Width: 0.15 m

# IfcSlab: Sol:Dalle en béton -150mm + finition carrelage, Sol:Dalle en béton -150mm + finition carrelage:468576
In: SS1
Type - PredefinedType: FLOOR; Material: carrelage 30x30 0.02 m, Béton - Béton coulé sur place 0.15 m
Type - Pset_EnvironmentalImpactIndicators - Reference: Dalle en béton -150mm + finition carrelage
Type - Pset_ReinforcementBarPitchOfSlab - Reference: Dalle en béton -150mm + finition carrelage
Type - Pset_SlabCommon - IsExternal: no; Reference: Dalle en béton -150mm + finition carrelage
Pset_EnvironmentalImpactIndicators - sets with these values: 2
Pset_SlabCommon - LoadBearing: no; PitchAngle: 0 deg
Qto_SlabBaseQuantities - NetArea: 60.7363 m2; NetVolume: 4.81447 m3

# IfcSlab: Sol:Dalle en béton -150mm + finition carrelage noir, Sol:Dalle en béton -150mm + finition carrelage noir:477700
In: SS1
Type - PredefinedType: FLOOR; Material: carrelage noir 0.02 m, Béton - Béton coulé sur place 0.15 m
Type - Pset_EnvironmentalImpactIndicators - Reference: Dalle en béton -150mm + finition carrelage noir
Type - Pset_ReinforcementBarPitchOfSlab - Reference: Dalle en béton -150mm + finition carrelage noir
Type - Pset_SlabCommon - IsExternal: no; Reference: Dalle en béton -150mm + finition carrelage noir
Pset_EnvironmentalImpactIndicators - sets with these values: 2
Pset_SlabCommon - LoadBearing: no; PitchAngle: 0 deg
Qto_SlabBaseQuantities - GrossArea: 21.4503 m2; NetArea: 46.3686 m2; GrossVolume: 3.64655 m3; NetVolume: 3.64655 m3; Perimeter: 20.4001 m; Width: 0.17 m

# IfcSlab: Sol:Dalle en béton -250, Sol:Dalle en béton -250:455104
In: SS3
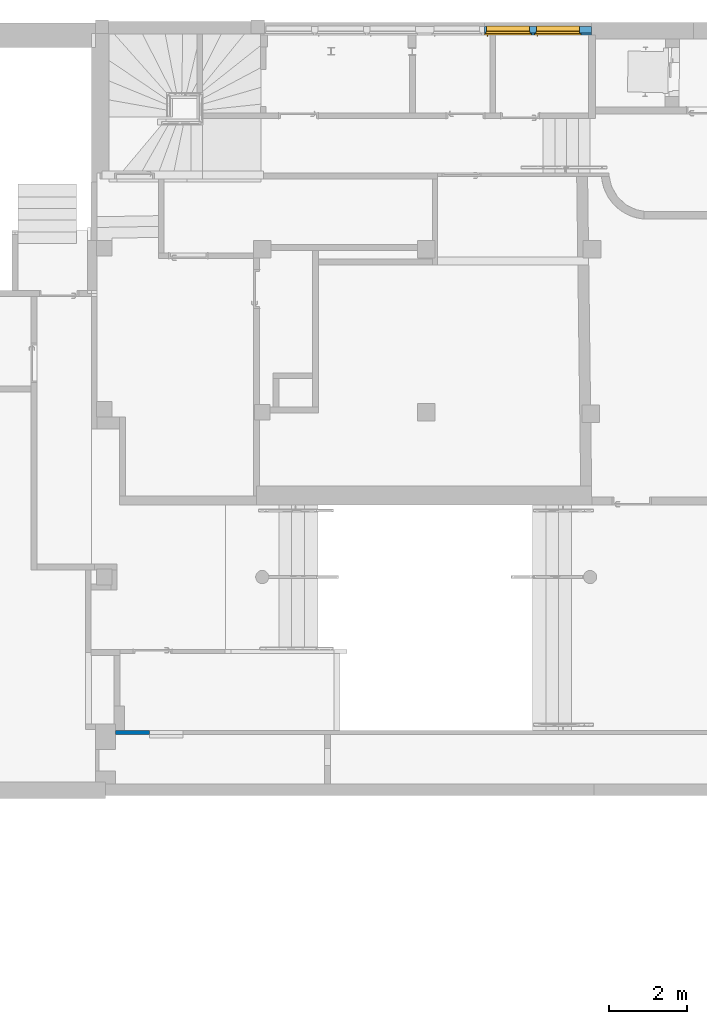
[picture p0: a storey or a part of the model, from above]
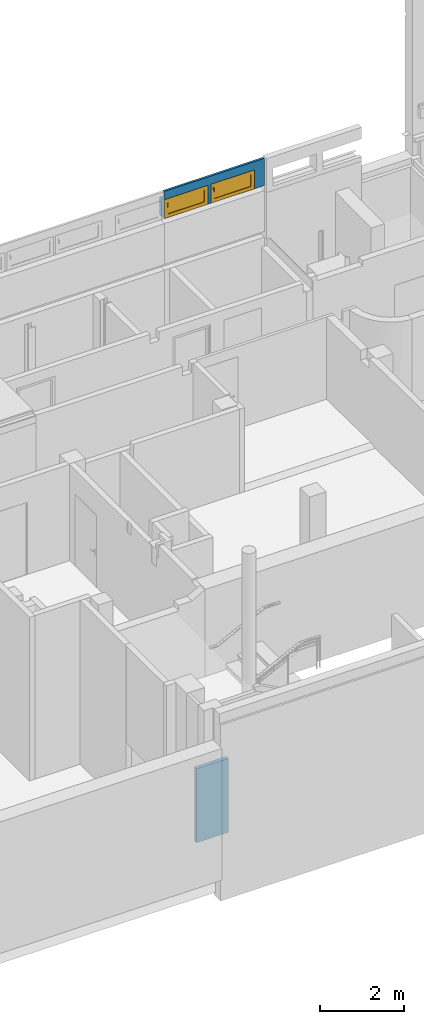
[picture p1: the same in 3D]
Properties of the parts of a building model (IFC4), part 6 of 8

# IfcSlab: Sol:Dalle en béton -250, Sol:Dalle en béton -250:455104
Pset_EnvironmentalImpactIndicators - Reference: Dalle en béton -250; sets with these values: 2
Pset_SlabCommon - IsExternal: no; LoadBearing: no; Reference: Dalle en béton -250; PitchAngle: 5.5058 deg
Qto_SlabBaseQuantities - NetArea: 344.883 m2; NetVolume: 41.2334 m3

# IfcSlab: Sol:Dalle en béton -250 (8)
Type - PredefinedType: FLOOR; Material: Béton - Béton coulé sur place 0.25 m
Type - Pset_EnvironmentalImpactIndicators - Reference: Dalle en béton -250
Type - Pset_ReinforcementBarPitchOfSlab - Reference: Dalle en béton -250
Type - Pset_SlabCommon - IsExternal: no; Reference: Dalle en béton -250
Pset_EnvironmentalImpactIndicators - sets with these values: 2
Pset_SlabCommon - LoadBearing: no; PitchAngle: 0 deg
Name (Sol:Dalle en béton -250:...) | In | NetArea (m2) | NetVolume (m3) | GrossArea (m2) | GrossVolume (m3) | Perimeter (m) | Width (m)
336427 | Niveau 0 | 1294.41 | 156.322
417427 | SS2 | 212.726 | 24.904 | 99.6161 | 24.904 | 53.9742 | 0.25
430741 | Demi-niveau | 14.7526 | 1.49951 | 5.99803 | 1.49951 | 11.0261 | 0.25
447685 | SS2 | 67.4674 | 7.72908 | 30.9163 | 7.72908 | 22.539 | 0.25
450052 | SS3 | 79.8459 | 8.66691 | 34.6676 | 8.66691 | 42.0425 | 0.25
450997 | SS3 | 4.79398 | 0.432299 | 1.7292 | 0.432299 | 5.34234 | 0.25
614864 | SS3 | 8.68426 | 0.854044 | 3.41618 | 0.854044 | 7.40764 | 0.25
650991 | SS3 | 45.8698 | 5.10263 | 20.4109 | 5.10271 | 20.1925 | 0.25

# IfcSlab: Sol:Dalle en béton -250 (5)
In: SS3
Type - PredefinedType: ROOF
Type - Pset_EnvironmentalImpactIndicators - Reference: Dalle en béton -250
Type - Pset_ReinforcementBarPitchOfSlab - Reference: Dalle en béton -250
Type - Pset_SlabCommon - IsExternal: no; Reference: Dalle en béton -250
Material: Béton - Béton coulé sur place
Pset_EnvironmentalImpactIndicators - sets with these values: 2
Pset_SlabCommon - LoadBearing: no
Qto_SlabBaseQuantities - NetArea: 344.883 m2; NetVolume: 41.2334 m3
Name (Sol:Dalle en béton -250:...) | PitchAngle (deg) | GrossArea (m2) | GrossVolume (m3) | Perimeter (m) | Width (m)
455104 | 5.5058 | 3.32959 | 0.832398 | 26.2617 | 0.25
455104 | 5.5058 | 4.17821 | 1.04455 | 28.2344 | 0.25
455104 | 88.058 | 0.0462062 | 0.000391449 | 18.2204 | 0.00847179
455104 | 2.71951 | 3.44463 | 0.860187 | 26.527 | 0.249718
455104 | 5.5058 | 4.39299 | 1.09318 | 28.732 | 0.248847

# IfcSlab: Sol:Dalle en béton -250 + vinyle (3)
In: SS3
Type - PredefinedType: FLOOR; Material: Sol en vinyl 0.04 m, Béton - Béton coulé sur place 0.25 m
Type - Pset_EnvironmentalImpactIndicators - Reference: Dalle en béton -250 + vinyle
Type - Pset_ReinforcementBarPitchOfSlab - Reference: Dalle en béton -250 + vinyle
Type - Pset_SlabCommon - IsExternal: no; Reference: Dalle en béton -250 + vinyle; ThermalTransmittance: 17.775 kg/K/s3
Pset_EnvironmentalImpactIndicators - sets with these values: 2
Pset_SlabCommon - LoadBearing: no
Name (Sol:Dalle en béton -250 + vinyle:...) | PitchAngle (deg) | GrossArea (m2) | NetArea (m2) | GrossVolume (m3) | NetVolume (m3) | Perimeter (m) | Width (m)
451388 | 0 | 46.0059 | 100.66 | 13.3417 | 13.3417 | 29.8221 | 0.29
451418 | 0 | 8.30576 | 20.0987 | 2.40867 | 2.40867 | 12.0249 | 0.29
451533 | 15.8444 |  | 4.01402 |  | 0.229749

# IfcSlab: Sol:Dalle en béton -250 finition carrelage beige (8)
Type - PredefinedType: FLOOR; Material: carrelage 30x30 0.04 m, Béton - Béton coulé sur place 0.25 m
Type - Pset_EnvironmentalImpactIndicators - Reference: Dalle en béton -250 finition carrelage beige
Type - Pset_ReinforcementBarPitchOfSlab - Reference: Dalle en béton -250 finition carrelage beige
Type - Pset_SlabCommon - IsExternal: no; Reference: Dalle en béton -250 finition carrelage beige
Pset_EnvironmentalImpactIndicators - sets with these values: 2
Pset_SlabCommon - LoadBearing: no; PitchAngle: 0 deg
Qto_SlabBaseQuantities - Width: 0.29 m
Name (Sol:Dalle en béton -250 finition carrelage beige:...) | In | GrossArea (m2) | NetArea (m2) | GrossVolume (m3) | NetVolume (m3) | Perimeter (m)
442548 | SS3 | 45.227 | 99.9762 | 13.1158 | 13.1158 | 32.8347
448750 | SS3 | 70.7089 | 152.899 | 20.5056 | 20.5056 | 39.5914
450237 | SS3 | 132.62 | 281.453 | 38.4599 | 38.4599 | 55.9065
452211 | SS3 | 21.0962 | 48.019 | 6.1179 | 6.11791 | 20.0917
452383 | SS3 | 1.05031 | 3.30887 | 0.30459 | 0.30459 | 4.16636
458439 | SS1 | 0.973271 | 3.13336 | 0.282249 | 0.282249 | 4.09249
458986 | SS1 | 5.742 | 14.5356 | 1.66518 | 1.66518 | 10.5228
459586 | SS3 | 1.83106 | 5.23513 | 0.531008 | 0.531008 | 5.42416

# IfcSlab: Sol:Dalle en béton -250 finition carrelage gris, Sol:Dalle en béton -250 finition carrelage gris:451118
In: SS3
Type - PredefinedType: FLOOR; Material: carreau 40x40 gris 0.04 m, Béton - Béton coulé sur place 0.25 m
Type - Pset_EnvironmentalImpactIndicators - Reference: Dalle en béton -250 finition carrelage gris
Type - Pset_ReinforcementBarPitchOfSlab - Reference: Dalle en béton -250 finition carrelage gris
Type - Pset_SlabCommon - IsExternal: no; Reference: Dalle en béton -250 finition carrelage gris
Pset_EnvironmentalImpactIndicators - sets with these values: 2
Pset_SlabCommon - LoadBearing: no; PitchAngle: 0 deg
Qto_SlabBaseQuantities - GrossArea: 48.329 m2; NetArea: 106.782 m2; GrossVolume: 14.0154 m3; NetVolume: 14.0154 m3; Perimeter: 34.9092 m; Width: 0.29 m

# IfcSlab: Sol:Dalle en béton 150 (3)
Type - PredefinedType: FLOOR; Material: Béton - Béton coulé sur place 0.15 m
Type - Pset_EnvironmentalImpactIndicators - Reference: Dalle en béton 150
Type - Pset_ReinforcementBarPitchOfSlab - Reference: Dalle en béton 150
Type - Pset_SlabCommon - IsExternal: no; Reference: Dalle en béton 150
Pset_EnvironmentalImpactIndicators - sets with these values: 2
Pset_SlabCommon - LoadBearing: no; PitchAngle: 0 deg
Qto_SlabBaseQuantities - Width: 0.15 m
Name (Sol:Dalle en béton 150:...) | In | GrossArea (m2) | NetArea (m2) | GrossVolume (m3) = NetVolume (m3) | Perimeter (m)
522279 | Niveau 0 | 43.443 | 91.4498 | 6.51646 | 30.4246
588206 | Niveau 2 | 184.321 | 378.314 | 27.6482 | 64.4782
588638 | Niveau 2 | 9.85881 | 21.8065 | 1.47882 | 13.9261

# IfcSlab: Sol:Dalle en béton 200 mm, Sol:Dalle en béton 200 mm:607044
In: Niveau 2
Type - PredefinedType: FLOOR; Material: Béton - Béton coulé sur place 0.2 m
Type - Pset_EnvironmentalImpactIndicators - Reference: Dalle en béton 200 mm
Type - Pset_ReinforcementBarPitchOfSlab - Reference: Dalle en béton 200 mm
Type - Pset_SlabCommon - IsExternal: no; Reference: Dalle en béton 200 mm
Pset_EnvironmentalImpactIndicators - sets with these values: 2
Pset_SlabCommon - LoadBearing: no; PitchAngle: 0 deg
Qto_SlabBaseQuantities - GrossArea: 4.95336 m2; NetArea: 12.0454 m2; GrossVolume: 0.990673 m3; NetVolume: 0.990673 m3; Perimeter: 10.6934 m; Width: 0.2 m

# IfcSlab: Sol:Finition carrelage 30x30, Sol:Finition carrelage 30x30:353333
In: Niveau 0
Type - PredefinedType: FLOOR; Material: carrelage 30x30 0.04 m
Type - Pset_EnvironmentalImpactIndicators - Reference: Finition carrelage 30x30
Type - Pset_ReinforcementBarPitchOfSlab - Reference: Finition carrelage 30x30
Type - Pset_SlabCommon - IsExternal: no; Reference: Finition carrelage 30x30
Pset_EnvironmentalImpactIndicators - sets with these values: 2
Pset_SlabCommon - LoadBearing: no; PitchAngle: 0 deg
Qto_SlabBaseQuantities - GrossArea: 5.97025 m2; NetArea: 12.3612 m2; GrossVolume: 0.23881 m3; NetVolume: 0.23881 m3; Perimeter: 10.5176 m; Width: 0.04 m

# IfcSlab: Sol:Finition carrelage 30x30 2, Sol:Finition carrelage 30x30 2:639633
In: Niveau 0
Type - PredefinedType: FLOOR; Material: carrelage 30x30 0.02 m
Type - Pset_EnvironmentalImpactIndicators - Reference: Finition carrelage 30x30 2
Type - Pset_ReinforcementBarPitchOfSlab - Reference: Finition carrelage 30x30 2
Type - Pset_SlabCommon - IsExternal: no; Reference: Finition carrelage 30x30 2
Pset_EnvironmentalImpactIndicators - sets with these values: 2
Pset_SlabCommon - LoadBearing: no; PitchAngle: 0 deg
Qto_SlabBaseQuantities - GrossArea: 8.07283 m2; NetArea: 16.3965 m2; GrossVolume: 0.161457 m3; NetVolume: 0.161457 m3; Perimeter: 12.5403 m; Width: 0.02 m

# IfcSlab: Sol:Finition carrelage blanc, Sol:Finition carrelage blanc:339896
In: Niveau 0
Type - PredefinedType: FLOOR; Material: Carreau, porcelaine, 4 po 0.04 m
Type - Pset_EnvironmentalImpactIndicators - Reference: Finition carrelage blanc
Type - Pset_ReinforcementBarPitchOfSlab - Reference: Finition carrelage blanc
Type - Pset_SlabCommon - IsExternal: no; Reference: Finition carrelage blanc; ThermalTransmittance: 30 kg/K/s3
Pset_EnvironmentalImpactIndicators - sets with these values: 2
Pset_SlabCommon - LoadBearing: no; PitchAngle: 0 deg
Qto_SlabBaseQuantities - GrossArea: 9.88943 m2; NetArea: 20.3212 m2; GrossVolume: 0.395577 m3; NetVolume: 0.395577 m3; Perimeter: 13.5581 m; Width: 0.04 m

# IfcSlab: Sol:Finition carrelage noir, Sol:Finition carrelage noir:352864
In: Niveau 0
Type - PredefinedType: FLOOR; Material: carrelage noir 0.03 m
Type - Pset_EnvironmentalImpactIndicators - Reference: Finition carrelage noir
Type - Pset_ReinforcementBarPitchOfSlab - Reference: Finition carrelage noir
Type - Pset_SlabCommon - IsExternal: no; Reference: Finition carrelage noir
Pset_EnvironmentalImpactIndicators - sets with these values: 2
Pset_SlabCommon - LoadBearing: no; PitchAngle: 0 deg
Qto_SlabBaseQuantities - GrossArea: 3.45652 m2; NetArea: 7.19409 m2; GrossVolume: 0.103696 m3; NetVolume: 0.103696 m3; Perimeter: 9.36825 m; Width: 0.03 m

# IfcSlab: Sol:Moquette Antidérapante 20 mm, Sol:Moquette Antidérapante 20 mm:344782
In: Niveau 0
Type - PredefinedType: FLOOR; Material: Moquette Antidérapante 0.02 m
Type - Pset_EnvironmentalImpactIndicators - Reference: Moquette Antidérapante 20 mm
Type - Pset_ReinforcementBarPitchOfSlab - Reference: Moquette Antidérapante 20 mm
Type - Pset_SlabCommon - IsExternal: no; Reference: Moquette Antidérapante 20 mm
Pset_EnvironmentalImpactIndicators - sets with these values: 2
Pset_SlabCommon - LoadBearing: no; PitchAngle: 0 deg
Qto_SlabBaseQuantities - GrossArea: 8.47322 m2; NetArea: 17.1904 m2; GrossVolume: 0.169464 m3; NetVolume: 0.169464 m3; Perimeter: 12.2026 m; Width: 0.02 m

# IfcSlab: Sol:Moquette grenat (2)
In: Niveau 2
Type - PredefinedType: FLOOR; Material: moquette grenat 0.035 m
Type - Pset_EnvironmentalImpactIndicators - Reference: Moquette grenat
Type - Pset_ReinforcementBarPitchOfSlab - Reference: Moquette grenat
Type - Pset_SlabCommon - IsExternal: no; Reference: Moquette grenat
Pset_EnvironmentalImpactIndicators - sets with these values: 2
Pset_SlabCommon - LoadBearing: no; PitchAngle: 0 deg
Name (Sol:Moquette grenat:...) | NetArea (m2) | NetVolume (m3)
589773 | 240.45 | 4.16473
590010 | 15.4944 | 0.26375 | Qto_SlabBaseQuantities - GrossArea: 7.5357 m2; GrossVolume: 0.26375 m3; Perimeter: 12.0843 m; Width: 0.035 m

# IfcSlab: Sol:bois 30 mm (2)
Type - PredefinedType: FLOOR; Material: Résineux, bois de construction 0.03 m
Type - Pset_EnvironmentalImpactIndicators - Reference: bois 30 mm
Type - Pset_ReinforcementBarPitchOfSlab - Reference: bois 30 mm
Type - Pset_SlabCommon - IsExternal: no; Reference: bois 30 mm; ThermalTransmittance: 4 kg/K/s3
Pset_EnvironmentalImpactIndicators - sets with these values: 2
Pset_SlabCommon - LoadBearing: no; PitchAngle: 0 deg
Qto_SlabBaseQuantities - Width: 0.03 m
Name (Sol:bois 30 mm:...) | In | GrossArea (m2) | NetArea (m2) | GrossVolume (m3) = NetVolume (m3) | Perimeter (m)
547176 | Niveau 1 | 0.62646 | 1.35898 | 0.0187938 | 3.53514
556451 | Niveau 2 | 9.4832 | 19.3768 | 0.284496 | 13.681

# IfcSlab: Sol:bois+moquette rouge, Sol:bois+moquette rouge:454572
In: SS3
Type - PredefinedType: FLOOR; Material: Moquette rouge 0.02 m, Résineux, bois de construction 0.1 m
Type - Pset_EnvironmentalImpactIndicators - Reference: bois+moquette rouge
Type - Pset_ReinforcementBarPitchOfSlab - Reference: bois+moquette rouge
Type - Pset_SlabCommon - IsExternal: no; Reference: bois+moquette rouge; ThermalTransmittance: 1.2 kg/K/s3
Pset_EnvironmentalImpactIndicators - sets with these values: 2
Pset_SlabCommon - LoadBearing: no; PitchAngle: 0 deg
Qto_SlabBaseQuantities - GrossArea: 20.6576 m2; NetArea: 44.1144 m2; GrossVolume: 2.47892 m3; NetVolume: 2.47892 m3; Perimeter: 23.3258 m; Width: 0.12 m

# IfcSlab: Sol:béton 100 (7)
Type - PredefinedType: FLOOR; Material: Béton, coulé sur place 0.1 m
Type - Pset_EnvironmentalImpactIndicators - Reference: béton 100
Type - Pset_ReinforcementBarPitchOfSlab - Reference: béton 100
Type - Pset_SlabCommon - IsExternal: no; Reference: béton 100; ThermalTransmittance: 10.46 kg/K/s3
Pset_EnvironmentalImpactIndicators - sets with these values: 2
Pset_SlabCommon - LoadBearing: no
Name (Sol:béton 100:...) | In | PitchAngle (deg) | NetArea (m2) | NetVolume (m3)
377395 | Niveau 1 | 0 | 14.894 | 0.586982
452794 | SS1 | 3.77891 | 4.77322 | 0.203734
470546 | SS1 | 0 | 2.52413 | 0.102802 | Qto_SlabBaseQuantities - GrossArea: 1.02802 m2; GrossVolume: 0.102802 m3; Perimeter: 4.68089 m; Width: 0.1 m
607184 | Niveau 2 | 0 | 2.68098 | 0.111721 | Qto_SlabBaseQuantities - GrossArea: 1.11721 m2; GrossVolume: 0.111721 m3; Perimeter: 4.46567 m; Width: 0.1 m
642624 | Niveau 2 | 0 | 4.83266 | 0.155099
656362 | Niveau 1 | 0 | 39.0289 | 1.6563
656466 | Niveau 2 | 0 | 17.3189 | 0.744082 | Qto_SlabBaseQuantities - GrossArea: 7.44082 m2; GrossVolume: 0.744082 m3; Perimeter: 24.3728 m; Width: 0.1 m

# IfcSlab: Sol:béton 100+carrelage noir, Sol:béton 100+carrelage noir:476980
In: SS1
Type - PredefinedType: FLOOR; Material: carrelage noir 0.02 m, Béton - Béton coulé sur place 0.1 m
Type - Pset_EnvironmentalImpactIndicators - Reference: béton 100+carrelage noir
Type - Pset_ReinforcementBarPitchOfSlab - Reference: béton 100+carrelage noir
Type - Pset_SlabCommon - IsExternal: no; Reference: béton 100+carrelage noir
Pset_EnvironmentalImpactIndicators - sets with these values: 2
Pset_SlabCommon - LoadBearing: no; PitchAngle: 0 deg
Qto_SlabBaseQuantities - GrossArea: 2.16781 m2; NetArea: 5.05626 m2; GrossVolume: 0.260137 m3; NetVolume: 0.260137 m3; Perimeter: 6.00539 m; Width: 0.12 m

# IfcSlab: Sol:béton 120, Sol:béton 120:388790
In: Niveau 0
Type - PredefinedType: FLOOR; Material: Béton, coulé sur place 0.12 m
Type - Pset_EnvironmentalImpactIndicators - Reference: béton 120
Type - Pset_ReinforcementBarPitchOfSlab - Reference: béton 120
Type - Pset_SlabCommon - IsExternal: no; Reference: béton 120; ThermalTransmittance: 8.71667 kg/K/s3
Pset_EnvironmentalImpactIndicators - sets with these values: 2
Pset_SlabCommon - LoadBearing: no; PitchAngle: 0 deg
Qto_SlabBaseQuantities - GrossArea: 2.53523 m2; NetArea: 6.16254 m2; GrossVolume: 0.304227 m3; NetVolume: 0.304227 m3; Perimeter: 9.1007 m; Width: 0.12 m

# IfcSlab: Sol:béton 150+carrelage (2)
Type - PredefinedType: FLOOR; Material: carrelage 30x30 0.02 m, Béton - Béton coulé sur place 0.15 m
Type - Pset_EnvironmentalImpactIndicators - Reference: béton 150+carrelage
Type - Pset_ReinforcementBarPitchOfSlab - Reference: béton 150+carrelage
Type - Pset_SlabCommon - IsExternal: no; Reference: béton 150+carrelage
Pset_EnvironmentalImpactIndicators - sets with these values: 2
Pset_SlabCommon - LoadBearing: no; PitchAngle: 0 deg
Qto_SlabBaseQuantities - Width: 0.17 m
Name (Sol:béton 150+carrelage:...) | In | GrossArea (m2) | NetArea (m2) | GrossVolume (m3) = NetVolume (m3) | Perimeter (m)
486399 | SS1 | 125.228 | 259.387 | 21.2887 | 52.5384
618899 | Demi-niveau | 4.34495 | 10.1081 | 0.738642 | 8.3425

# IfcSlab: Sol:béton 80+carrelage (2)
In: SS1
Type - PredefinedType: FLOOR; Material: carrelage 30x30 0.02 m, Béton - Béton coulé sur place 0.08 m
Type - Pset_EnvironmentalImpactIndicators - Reference: béton 80+carrelage
Type - Pset_ReinforcementBarPitchOfSlab - Reference: béton 80+carrelage
Type - Pset_SlabCommon - IsExternal: no; Reference: béton 80+carrelage
Pset_EnvironmentalImpactIndicators - sets with these values: 2
Pset_SlabCommon - LoadBearing: no; PitchAngle: 0 deg
Qto_SlabBaseQuantities - Width: 0.1 m
Name (Sol:béton 80+carrelage:...) | GrossArea (m2) | NetArea (m2) | GrossVolume (m3) = NetVolume (m3) | Perimeter (m)
485068 | 6.81508 | 14.8037 | 0.681508 | 11.7353
558249 | 5.8483 | 12.7715 | 0.58483 | 10.7491

# IfcSlab: Sol:carrelage 30x30, Sol:carrelage 30x30:447965
In: SS2
Type - PredefinedType: FLOOR; Material: carrelage 30x30 0.04 m
Type - Pset_EnvironmentalImpactIndicators - Reference: carrelage 30x30
Type - Pset_ReinforcementBarPitchOfSlab - Reference: carrelage 30x30
Type - Pset_SlabCommon - IsExternal: no; Reference: carrelage 30x30
Pset_EnvironmentalImpactIndicators - sets with these values: 2
Pset_SlabCommon - LoadBearing: no; PitchAngle: 0 deg
Qto_SlabBaseQuantities - GrossArea: 31.2037 m2; NetArea: 63.3137 m2; GrossVolume: 1.24815 m3; NetVolume: 1.24815 m3; Perimeter: 22.659 m; Width: 0.04 m

# IfcSlab: Sol:carrelage 30x30 2, Sol:carrelage 30x30 2:589260
In: Niveau 2
Type - PredefinedType: FLOOR; Material: carrelage 30x30 0.035 m
Type - Pset_EnvironmentalImpactIndicators - Reference: carrelage 30x30 2
Type - Pset_ReinforcementBarPitchOfSlab - Reference: carrelage 30x30 2
Type - Pset_SlabCommon - IsExternal: no; Reference: carrelage 30x30 2
Pset_EnvironmentalImpactIndicators - sets with these values: 2
Pset_SlabCommon - LoadBearing: no; PitchAngle: 0 deg
Qto_SlabBaseQuantities - GrossArea: 23.7062 m2; NetArea: 48.5719 m2; GrossVolume: 0.829716 m3; NetVolume: 0.829716 m3; Perimeter: 33.129 m; Width: 0.035 m

# IfcSlab: Sol:finition PARQUET 20 mm, Sol:finition PARQUET 20 mm:340255
In: Niveau 0
Type - PredefinedType: FLOOR; Material: PARQUET 0.02 m
Type - Pset_EnvironmentalImpactIndicators - Reference: finition PARQUET 20 mm
Type - Pset_ReinforcementBarPitchOfSlab - Reference: finition PARQUET 20 mm
Type - Pset_SlabCommon - IsExternal: no; Reference: finition PARQUET 20 mm
Pset_EnvironmentalImpactIndicators - sets with these values: 2
Pset_SlabCommon - LoadBearing: no; PitchAngle: 0 deg
Qto_SlabBaseQuantities - GrossArea: 178.618 m2; NetArea: 358.402 m2; GrossVolume: 3.57236 m3; NetVolume: 3.57236 m3; Perimeter: 58.3216 m; Width: 0.02 m

# IfcSlab: Sol:finition carrelage 20 mm, Sol:finition carrelage 20 mm:338233
In: Niveau 0
Type - PredefinedType: FLOOR; Material: Carrelage beige 0.02 m
Type - Pset_EnvironmentalImpactIndicators - Reference: finition carrelage 20 mm
Type - Pset_ReinforcementBarPitchOfSlab - Reference: finition carrelage 20 mm
Type - Pset_SlabCommon - IsExternal: no; Reference: finition carrelage 20 mm
Pset_EnvironmentalImpactIndicators - sets with these values: 2
Pset_SlabCommon - LoadBearing: no; PitchAngle: 0 deg
Qto_SlabBaseQuantities - GrossArea: 186.6 m2; NetArea: 375.294 m2; GrossVolume: 3.73201 m3; NetVolume: 3.73201 m3; Perimeter: 104.67 m; Width: 0.02 m

# IfcSlab: Sol:finition carrelage 20 mm + moquette 15 (2)
In: Niveau 0
Type - PredefinedType: FLOOR; Material: moquette bleu 0.015 m, Carrelage beige 0.02 m
Type - Pset_EnvironmentalImpactIndicators - Reference: finition carrelage 20 mm + moquette 15
Type - Pset_ReinforcementBarPitchOfSlab - Reference: finition carrelage 20 mm + moquette 15
Type - Pset_SlabCommon - IsExternal: no; Reference: finition carrelage 20 mm + moquette 15
Pset_EnvironmentalImpactIndicators - sets with these values: 2
Pset_SlabCommon - LoadBearing: no; PitchAngle: 0 deg
Qto_SlabBaseQuantities - Width: 0.035 m
Name (Sol:finition carrelage 20 mm + moquette 15:...) | GrossArea (m2) | NetArea (m2) | GrossVolume (m3) = NetVolume (m3) | Perimeter (m)
339136 | 160.333 | 322.693 | 5.61164 | 57.9341
339428 | 39.385 | 80.0295 | 1.37847 | 35.9861

# IfcSlab: Sol:moquette rouge, Sol:moquette rouge:455176
In: SS3
Pset_EnvironmentalImpactIndicators - Reference: moquette rouge; sets with these values: 2
Pset_SlabCommon - IsExternal: no; LoadBearing: no; Reference: moquette rouge; PitchAngle: 5.5058 deg
Qto_SlabBaseQuantities - NetArea: 270.954 m2; NetVolume: 2.68505 m3

# IfcSlab: Sol:moquette rouge (5)
In: SS3
Type - PredefinedType: ROOF
Type - Pset_EnvironmentalImpactIndicators - Reference: moquette rouge
Type - Pset_ReinforcementBarPitchOfSlab - Reference: moquette rouge
Type - Pset_SlabCommon - IsExternal: no; Reference: moquette rouge
Material: Moquette rouge
Pset_EnvironmentalImpactIndicators - sets with these values: 2
Pset_SlabCommon - LoadBearing: no
Qto_SlabBaseQuantities - NetArea: 270.954 m2; NetVolume: 2.68505 m3
Name (Sol:moquette rouge:...) | PitchAngle (deg) | GrossArea (m2) | GrossVolume (m3) | Perimeter (m) | Width (m)
455176 | 5.5058 | 3.07148 | 0.0614297 | 25.6617 | 0.02
455176 | 5.5058 | 1.58594 | 0.0317188 | 23.1213 | 0.02
455176 | 88.058 | 0.0462062 | 0.0000313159 | 18.2204 | 0.000677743
455176 | 2.71951 | 3.44463 | 0.068815 | 26.527 | 0.0199775
455176 | 5.5058 | 4.39299 | 0.0874545 | 28.732 | 0.0199077

# IfcSlab: Sol:plâtre 50 (8)
Type - PredefinedType: FLOOR; Material: Plâtre 0.05 m
Type - Pset_EnvironmentalImpactIndicators - Reference: plâtre 50
Type - Pset_ReinforcementBarPitchOfSlab - Reference: plâtre 50
Type - Pset_SlabCommon - IsExternal: no; Reference: plâtre 50; ThermalTransmittance: 10.2 kg/K/s3
Pset_EnvironmentalImpactIndicators - sets with these values: 2
Pset_SlabCommon - LoadBearing: no; PitchAngle: 0 deg
Qto_SlabBaseQuantities - Width: 0.05 m
Name (Sol:plâtre 50:...) | In | GrossArea (m2) | NetArea (m2) | GrossVolume (m3) | NetVolume (m3) | Perimeter (m)
452729 | SS1 | 1.65864 | 3.6744 | 0.0829322 | 0.0829322 | 7.14232
453672 | SS1 | 0.191846 | 0.479556 | 0.0095923 | 0.0095923 | 1.91728
453692 | SS1 | 0.191846 | 0.479556 | 0.0095923 | 0.0095923 | 1.91728
529275 | Niveau 2 | 0.318389 | 0.75678 | 0.0159195 | 0.0159195 | 2.40003
529421 | Niveau 2 | 0.259626 | 0.63208 | 0.0129813 | 0.0129813 | 2.25658
551091 | Niveau 2 | 10.313 | 21.3329 | 0.515651 | 0.515652 | 14.1362
610265 | Demi-niveau | 0.260809 | 0.709397 | 0.0130405 | 0.0130405 | 3.75558
648836 | Demi-niveau | 0.260809 | 0.709397 | 0.0130405 | 0.0130405 | 3.75558

# IfcSlab: Sol:vinyle 35 mm, Sol:vinyle 35 mm:648600
In: Niveau 2
Type - PredefinedType: FLOOR; Material: Sol en vinyl 0.035 m
Type - Pset_EnvironmentalImpactIndicators - Reference: vinyle 35 mm
Type - Pset_ReinforcementBarPitchOfSlab - Reference: vinyle 35 mm
Type - Pset_SlabCommon - IsExternal: no; Reference: vinyle 35 mm; ThermalTransmittance: 20.3143 kg/K/s3
Pset_EnvironmentalImpactIndicators - sets with these values: 2
Pset_SlabCommon - LoadBearing: no; PitchAngle: 0 deg
Qto_SlabBaseQuantities - GrossArea: 21.1713 m2; NetArea: 43.124 m2; GrossVolume: 0.740995 m3; NetVolume: 0.740995 m3; Perimeter: 22.3277 m; Width: 0.035 m

# IfcSlab: Sols 1:Sols 1, Sols 1:Sols 1:503705
In: Niveau 0
Type - PredefinedType: FLOOR; Material: Plâtre
Type - Pset_EnvironmentalImpactIndicators - Reference: Sols 1
Type - Pset_ReinforcementBarPitchOfSlab - Reference: Sols 1
Type - Pset_SlabCommon - IsExternal: no; Reference: Sols 1
Pset_EnvironmentalImpactIndicators - sets with these values: 2
Qto_SlabBaseQuantities - GrossArea: 0.050328 m2; NetArea: 11.8052 m2; GrossVolume: 0.553448 m3; NetVolume: 0.553448 m3; Perimeter: 1.06436 m; Width: 10.9968 m

# IfcSlab: Sols 2:Sols 2, Sols 2:Sols 2:504850
In: Niveau 0
Type - PredefinedType: FLOOR; Material: Plâtre
Type - Pset_EnvironmentalImpactIndicators - Reference: Sols 2
Type - Pset_ReinforcementBarPitchOfSlab - Reference: Sols 2
Type - Pset_SlabCommon - IsExternal: no; Reference: Sols 2
Pset_EnvironmentalImpactIndicators - sets with these values: 2
Qto_SlabBaseQuantities - GrossArea: 0.0600813 m2; NetArea: 0.365578 m2; GrossVolume: 0.0119052 m3; NetVolume: 0.0119052 m3; Perimeter: 1.23852 m; Width: 0.198152 m

# IfcSlab: Sols 3:Sols 3, Sols 3:Sols 3:505041
In: Niveau 1
Type - PredefinedType: FLOOR; Material: Plâtre
Type - Pset_EnvironmentalImpactIndicators - Reference: Sols 3
Type - Pset_ReinforcementBarPitchOfSlab - Reference: Sols 3
Type - Pset_SlabCommon - IsExternal: no; Reference: Sols 3
Pset_EnvironmentalImpactIndicators - sets with these values: 2
Qto_SlabBaseQuantities - GrossArea: 0.0630368 m2; NetArea: 13.3216 m2; GrossVolume: 0.673887 m3; NetVolume: 0.673887 m3; Perimeter: 1.23434 m; Width: 10.6904 m

# IfcSlab: Toit de base:Toit - 100 mm (2)
In: Niveau 2
Type - PredefinedType: ROOF
Type - Pset_EnvironmentalImpactIndicators - Reference: Toit - 100 mm
Type - Pset_ReinforcementBarPitchOfSlab - Reference: Toit - 100 mm
Type - Pset_SlabCommon - IsExternal: yes; Reference: Toit - 100 mm; ThermalTransmittance: 38.3333 kg/K/s3
Material: Béton - Béton coulé sur place; Protection humidité 0.03 m, Maçonnerie - Isolant 0.1 m, Béton - Béton coulé sur place 0.1 m
Pset_EnvironmentalImpactIndicators - sets with these values: 2
Pset_SlabCommon - PitchAngle: 0 deg
Qto_SlabBaseQuantities - Width: 0.23 m
Name (Toit de base:Toit - 100 mm:...) | GrossArea (m2) | NetArea (m2) | GrossVolume (m3) = NetVolume (m3) | Perimeter (m)
598684:1 | 6.72879 | 22.5889 | 1.54762 | 39.7015
607980:1 | 3.66165 | 12.5086 | 0.84218 | 22.5449

# IfcSlab: Toit de base:Toit - 100 mm béton (3)
In: Niveau 2
Type - PredefinedType: ROOF
Type - Pset_EnvironmentalImpactIndicators - Reference: Toit - 100 mm béton
Type - Pset_ReinforcementBarPitchOfSlab - Reference: Toit - 100 mm béton
Type - Pset_SlabCommon - IsExternal: yes; Reference: Toit - 100 mm béton
Pset_EnvironmentalImpactIndicators - sets with these values: 2
Pset_SlabCommon - PitchAngle: 0 deg
Qto_SlabBaseQuantities - Width: 0.1 m
Name (Toit de base:Toit - 100 mm béton:...) | Material | GrossArea (m2) | NetArea (m2) | GrossVolume (m3) | NetVolume (m3) | Perimeter (m)
591816 | Béton - Béton coulé sur place; Béton - Béton coulé sur place 0.1 m | 1.14195 | 26.2404 | 0.114195 | 1.22919 | 16.566
596148 | Béton - Béton coulé sur place; Béton - Béton coulé sur place 0.1 m | 0.739295 | 18.4188 | 0.0739295 | 0.795771 | 25.034
597835:1 | Finition Peinture - Blanc satiné; Béton - Béton coulé sur place 0.1 m | 10.1312 | 23.4129 | 1.01312 | 1.01312 | 31.5057

# IfcSlab: Toit de base:Toit - 200 mm 2 (2)
In: Niveau 2
Type - PredefinedType: ROOF
Type - Pset_EnvironmentalImpactIndicators - Reference: Toit - 200 mm 2
Type - Pset_ReinforcementBarPitchOfSlab - Reference: Toit - 200 mm 2
Type - Pset_SlabCommon - IsExternal: yes; Reference: Toit - 200 mm 2; ThermalTransmittance: 38.3333 kg/K/s3
Pset_EnvironmentalImpactIndicators - sets with these values: 2
Pset_SlabCommon - PitchAngle: 0 deg
Qto_SlabBaseQuantities - Width: 0.33 m
Name (Toit de base:Toit - 200 mm 2:...) | Material | GrossArea (m2) | NetArea (m2) | GrossVolume (m3) | NetVolume (m3) | Perimeter (m)
600053:1 | Béton - Béton coulé sur place; Protection humidité 0.03 m, Maçonnerie - Isolant 0.1 m, Béton - Béton coulé sur place 0.2 m | 120.518 | 293.591 | 39.771 | 39.771 | 159.257
600880 | Protection humidité 0.03 m, Maçonnerie - Isolant 0.1 m, Béton - Béton coulé sur place 0.2 m; Protection humidité | 1.37505 | 37.6739 | 0.453765 | 4.88429 | 24.4609

# IfcSlab: sol 3:sol 3, sol 3:sol 3:654134
In: Niveau 1
Type - PredefinedType: FLOOR; Material: Maçonnerie - Béton coulé sur place
Type - Pset_EnvironmentalImpactIndicators - Reference: sol 3
Type - Pset_ReinforcementBarPitchOfSlab - Reference: sol 3
Type - Pset_SlabCommon - IsExternal: no; Reference: sol 3
Pset_EnvironmentalImpactIndicators - sets with these values: 2
Qto_SlabBaseQuantities - NetArea: 38.9733 m2; NetVolume: 1.61863 m3

# IfcStair: Escalier assemblé:Escalier assemblé, Escalier assemblé:Escalier:461497
In: SS3
Type - PredefinedType: CURVED_RUN_STAIR
Type - Pset_EnvironmentalImpactIndicators - Reference: Escalier assemblé
Type - Pset_StairCommon - IsExternal: no; NosingLength: 0 m; Reference: Escalier assemblé; NumberOfRiser: 0; NumberOfTreads: 0
Type - Pset_StairFlightCommon - NosingLength: 0 m; Reference: Escalier assemblé; NumberOfRiser: 0; NumberOfTreads: 0
Pset_StairCommon - NumberOfRiser: 19; NumberOfTreads: 18; RiserHeight: 0.167328 m; TreadLength: 0.255972 m; TreadLengthAtOffset: 0.255972 m; TreadLengthAtInnerSide: 0.255972 m
Pset_StairFlightCommon - NumberOfRiser: 19; NumberOfTreads: 18; RiserHeight: 0.167328 m; TreadLength: 0.255972 m; TreadLengthAtOffset: 0.255972 m; TreadLengthAtInnerSide: 0.255972 m

# IfcStair: Escalier coulé sur place:Monobloc, Escalier coulé sur place:Escalier:269972
In: Niveau 0
Type - Pset_EnvironmentalImpactIndicators - Reference: Monobloc
Type - Pset_StairCommon - IsExternal: no; Reference: Monobloc; NumberOfRiser: 0; NumberOfTreads: 0; NosingLength: 0 m
Type - Pset_StairFlightCommon - Reference: Monobloc; NosingLength: 0 m; NumberOfRiser: 0; NumberOfTreads: 0
Pset_StairCommon - NumberOfRiser: 21; NumberOfTreads: 20; RiserHeight: 0.181076 m; TreadLength: 0.23 m; NosingLength: 0.03 m; TreadLengthAtOffset: 0.23 m; TreadLengthAtInnerSide: 0.23 m
Pset_StairFlightCommon - NumberOfRiser: 21; NumberOfTreads: 20; RiserHeight: 0.181076 m; TreadLength: 0.23 m; NosingLength: 0.03 m; TreadLengthAtOffset: 0.23 m; TreadLengthAtInnerSide: 0.23 m

# IfcStair: Escalier coulé sur place:Monobloc 2 (4)
Type - PredefinedType: STRAIGHT_RUN_STAIR
Type - Pset_EnvironmentalImpactIndicators - Reference: Monobloc 2
Type - Pset_StairCommon - IsExternal: no; NosingLength: 0 m; Reference: Monobloc 2; NumberOfRiser: 0; NumberOfTreads: 0
Type - Pset_StairFlightCommon - NosingLength: 0 m; Reference: Monobloc 2; NumberOfRiser: 0; NumberOfTreads: 0
Pset_StairCommon - NosingLength: 0.03 m
Pset_StairFlightCommon - NosingLength: 0.03 m
Name (Escalier coulé sur place:Escalier:...) | In | Pset_StairCommon, NumberOfRiser = Pset_StairFlightCommon, NumberOfRiser | Pset_StairCommon, NumberOfTreads = Pset_StairFlightCommon, NumberOfTreads | Pset_StairCommon, RiserHeight (m) = Pset_StairFlightCommon, RiserHeight (m) | Pset_StairCommon, TreadLength (m) = Pset_StairCommon, TreadLengthAtOffset (m) = Pset_StairCommon, TreadLengthAtInnerSide (m) = Pset_StairFlightCommon, TreadLength (m) = Pset_StairFlightCommon, TreadLengthAtOffset (m) = Pset_StairFlightCommon, TreadLengthAtInnerSide (m)
446541 | SS3 | 4 | 3 | 0.163351 | 0.303297
447285 | SS3 | 4 | 3 | 0.163351 | 0.303297
588333 | Niveau 2 | 4 | 3 | 0.16625 | 0.2975
638436 | Niveau 0 | 12 | 11 | 0.151783 | 0.326433

# IfcStair: Escalier coulé sur place:Monobloc 2 (3)
Type - Pset_EnvironmentalImpactIndicators - Reference: Monobloc 2
Type - Pset_StairCommon - IsExternal: no; NosingLength: 0 m; Reference: Monobloc 2; NumberOfRiser: 0; NumberOfTreads: 0
Type - Pset_StairFlightCommon - NosingLength: 0 m; Reference: Monobloc 2; NumberOfRiser: 0; NumberOfTreads: 0
Pset_StairCommon - NosingLength: 0.03 m
Pset_StairFlightCommon - NosingLength: 0.03 m
Name (Escalier coulé sur place:Escalier:...) | In | Pset_StairCommon, NumberOfRiser = Pset_StairFlightCommon, NumberOfRiser | Pset_StairCommon, NumberOfTreads = Pset_StairFlightCommon, NumberOfTreads | Pset_StairCommon, RiserHeight (m) = Pset_StairFlightCommon, RiserHeight (m) | Pset_StairCommon, TreadLength (m) = Pset_StairCommon, TreadLengthAtOffset (m) = Pset_StairCommon, TreadLengthAtInnerSide (m) = Pset_StairFlightCommon, TreadLength (m) = Pset_StairFlightCommon, TreadLengthAtOffset (m) = Pset_StairFlightCommon, TreadLengthAtInnerSide (m)
345098 | Niveau 0 | 5 | 4 | 0.174 | 0.282
350448 | Niveau 0 | 18 | 17 | 0.163418 | 0.303164
582517 | Niveau 1 | 19 | 18 | 0.168327 | 0.293346

# IfcStair: Escalier coulé sur place:Monobloc 3 (5)
In: SS3
Type - PredefinedType: STRAIGHT_RUN_STAIR
Type - Pset_EnvironmentalImpactIndicators - Reference: Monobloc 3
Type - Pset_StairCommon - IsExternal: no; NosingLength: 0 m; Reference: Monobloc 3; NumberOfRiser: 0; NumberOfTreads: 0
Type - Pset_StairFlightCommon - NosingLength: 0 m; Reference: Monobloc 3; NumberOfRiser: 0; NumberOfTreads: 0
Name (Escalier coulé sur place:Escalier:...) | Pset_StairCommon, NumberOfRiser = Pset_StairFlightCommon, NumberOfRiser | Pset_StairCommon, NumberOfTreads = Pset_StairFlightCommon, NumberOfTreads | Pset_StairCommon, RiserHeight (m) = Pset_StairFlightCommon, RiserHeight (m) | Pset_StairCommon, TreadLength (m) = Pset_StairCommon, TreadLengthAtOffset (m) = Pset_StairCommon, TreadLengthAtInnerSide (m) = Pset_StairFlightCommon, TreadLength (m) = Pset_StairFlightCommon, TreadLengthAtOffset (m) = Pset_StairFlightCommon, TreadLengthAtInnerSide (m)
444188 | 5 | 4 | 0.146 | 0.338
450683 | 3 | 2 | 0.17 | 0.29
451576 | 3 | 2 | 0.156667 | 0.316667
454590 | 4 | 3 | 0.1225 | 0.385
457968 | 8 | 7 | 0.20125 | 0.2275

# IfcStair: Escalier coulé sur place:Monobloc 3, Escalier coulé sur place:Escalier:390256
In: Demi-niveau
Type - Pset_EnvironmentalImpactIndicators - Reference: Monobloc 3
Type - Pset_StairCommon - IsExternal: no; NosingLength: 0 m; Reference: Monobloc 3; NumberOfRiser: 0; NumberOfTreads: 0
Type - Pset_StairFlightCommon - NosingLength: 0 m; Reference: Monobloc 3; NumberOfRiser: 0; NumberOfTreads: 0
Pset_StairCommon - NumberOfRiser: 8; NumberOfTreads: 7; RiserHeight: 0.175525 m; TreadLength: 0.27895 m; TreadLengthAtOffset: 0.27895 m; TreadLengthAtInnerSide: 0.27895 m
Pset_StairFlightCommon - NumberOfRiser: 8; NumberOfTreads: 7; RiserHeight: 0.175525 m; TreadLength: 0.27895 m; TreadLengthAtOffset: 0.27895 m; TreadLengthAtInnerSide: 0.27895 m

# IfcStair: Escalier coulé sur place:Monobloc 4, Escalier coulé sur place:Escalier:400493
In: SS1
Type - PredefinedType: STRAIGHT_RUN_STAIR
Type - Pset_EnvironmentalImpactIndicators - Reference: Monobloc 4
Type - Pset_StairCommon - IsExternal: no; NosingLength: 0 m; Reference: Monobloc 4; NumberOfRiser: 0; NumberOfTreads: 0
Type - Pset_StairFlightCommon - NosingLength: 0 m; Reference: Monobloc 4; NumberOfRiser: 0; NumberOfTreads: 0
Pset_StairCommon - NumberOfRiser: 16; NumberOfTreads: 15; RiserHeight: 0.168965 m; TreadLength: 0.29207 m; NosingLength: 0.03 m; TreadLengthAtOffset: 0.29207 m; TreadLengthAtInnerSide: 0.29207 m
Pset_StairFlightCommon - NumberOfRiser: 16; NumberOfTreads: 15; RiserHeight: 0.168965 m; TreadLength: 0.29207 m; NosingLength: 0.03 m; TreadLengthAtOffset: 0.29207 m; TreadLengthAtInnerSide: 0.29207 m

# IfcStair: Escalier coulé sur place:Monobloc 5 (2)
Type - PredefinedType: STRAIGHT_RUN_STAIR
Type - Pset_EnvironmentalImpactIndicators - Reference: Monobloc 5
Type - Pset_StairCommon - IsExternal: no; NosingLength: 0 m; Reference: Monobloc 5; NumberOfRiser: 0; NumberOfTreads: 0
Type - Pset_StairFlightCommon - NosingLength: 0 m; Reference: Monobloc 5; NumberOfRiser: 0; NumberOfTreads: 0
Name (Escalier coulé sur place:Escalier:...) | In | Pset_StairCommon, NumberOfRiser = Pset_StairFlightCommon, NumberOfRiser | Pset_StairCommon, NumberOfTreads = Pset_StairFlightCommon, NumberOfTreads | Pset_StairCommon, RiserHeight (m) = Pset_StairFlightCommon, RiserHeight (m) | Pset_StairCommon, TreadLength (m) = Pset_StairCommon, TreadLengthAtOffset (m) = Pset_StairCommon, TreadLengthAtInnerSide (m) = Pset_StairFlightCommon, TreadLength (m) = Pset_StairFlightCommon, TreadLengthAtOffset (m) = Pset_StairFlightCommon, TreadLengthAtInnerSide (m)
411849 | SS2 | 16 | 15 | 0.143055 | 0.343889
417900 | SS3 | 6 | 5 | 0.202681 | 0.2

# IfcStair: Escalier coulé sur place:Monobloc 5, Escalier coulé sur place:Escalier:426584
In: SS3
Type - Pset_EnvironmentalImpactIndicators - Reference: Monobloc 5
Type - Pset_StairCommon - IsExternal: no; NosingLength: 0 m; Reference: Monobloc 5; NumberOfRiser: 0; NumberOfTreads: 0
Type - Pset_StairFlightCommon - NosingLength: 0 m; Reference: Monobloc 5; NumberOfRiser: 0; NumberOfTreads: 0
Pset_StairCommon - NumberOfRiser: 22; NumberOfTreads: 21; RiserHeight: 0.163147 m; TreadLength: 0.303706 m; TreadLengthAtOffset: 0.303706 m; TreadLengthAtInnerSide: 0.303706 m
Pset_StairFlightCommon - NumberOfRiser: 22; NumberOfTreads: 21; RiserHeight: 0.163147 m; TreadLength: 0.303706 m; TreadLengthAtOffset: 0.303706 m; TreadLengthAtInnerSide: 0.303706 m

# IfcStair: Escalier coulé sur place:Monobloc 7, Escalier coulé sur place:Escalier:447979
In: SS2
Type - PredefinedType: STRAIGHT_RUN_STAIR
Type - Pset_EnvironmentalImpactIndicators - Reference: Monobloc 7
Type - Pset_StairCommon - IsExternal: no; NosingLength: 0 m; Reference: Monobloc 7; NumberOfRiser: 0; NumberOfTreads: 0
Type - Pset_StairFlightCommon - NosingLength: 0 m; Reference: Monobloc 7; NumberOfRiser: 0; NumberOfTreads: 0
Pset_StairCommon - NumberOfRiser: 11; NumberOfTreads: 10; RiserHeight: 0.166659 m; TreadLength: 0.296681 m; NosingLength: 0.03 m; TreadLengthAtOffset: 0.296681 m; TreadLengthAtInnerSide: 0.296681 m
Pset_StairFlightCommon - NumberOfRiser: 11; NumberOfTreads: 10; RiserHeight: 0.166659 m; TreadLength: 0.296681 m; NosingLength: 0.03 m; TreadLengthAtOffset: 0.296681 m; TreadLengthAtInnerSide: 0.296681 m

# IfcStair: LIMON 2:LIMON 2, LIMON 2:LIMON 2:390739
In: SS1
Type - Pset_EnvironmentalImpactIndicators - Reference: LIMON 2
Type - Pset_StairCommon - IsExternal: no; NosingLength: 0 m; Reference: LIMON 2; NumberOfRiser: 0; NumberOfTreads: 0
Type - Pset_StairFlightCommon - NosingLength: 0 m; Reference: LIMON 2; NumberOfRiser: 0; NumberOfTreads: 0
Material: Finition Peinture - Blanc satiné
Pset_EnvironmentalImpactIndicators - sets with these values: 2

# IfcStair: Limon 3:Limon 3, Limon 3:Limon 3:428860
In: SS3
Type - Pset_EnvironmentalImpactIndicators - Reference: Limon 3
Type - Pset_StairCommon - IsExternal: no; NosingLength: 0 m; Reference: Limon 3; NumberOfRiser: 0; NumberOfTreads: 0
Type - Pset_StairFlightCommon - NosingLength: 0 m; Reference: Limon 3; NumberOfRiser: 0; NumberOfTreads: 0
Material: Finition Peinture - Blanc satiné
Pset_EnvironmentalImpactIndicators - sets with these values: 2

# IfcStair: Limon 6:Limon 6, Limon 6:Limon 6:548607
In: Niveau 0
Type - Pset_EnvironmentalImpactIndicators - Reference: Limon 6
Type - Pset_StairCommon - IsExternal: no; NosingLength: 0 m; Reference: Limon 6; NumberOfRiser: 0; NumberOfTreads: 0
Type - Pset_StairFlightCommon - NosingLength: 0 m; Reference: Limon 6; NumberOfRiser: 0; NumberOfTreads: 0
Material: Finition Peinture - Blanc satiné
Pset_EnvironmentalImpactIndicators - sets with these values: 2

# IfcStair: Limon:Limon, Limon:Limon:279696
In: Niveau 0
Type - Pset_EnvironmentalImpactIndicators - Reference: Limon
Type - Pset_StairCommon - IsExternal: no; NosingLength: 0 m; Reference: Limon; NumberOfRiser: 0; NumberOfTreads: 0
Type - Pset_StairFlightCommon - NosingLength: 0 m; Reference: Limon; NumberOfRiser: 0; NumberOfTreads: 0
Material: Finition Peinture - Blanc satiné
Pset_EnvironmentalImpactIndicators - sets with these values: 2

# IfcStair: limon 4:limon 4, limon 4:limon 4:432423
In: SS1
Type - Pset_EnvironmentalImpactIndicators - Reference: limon 4
Type - Pset_StairCommon - IsExternal: no; NosingLength: 0 m; Reference: limon 4; NumberOfRiser: 0; NumberOfTreads: 0
Type - Pset_StairFlightCommon - NosingLength: 0 m; Reference: limon 4; NumberOfRiser: 0; NumberOfTreads: 0
Material: Finition Peinture - Blanc satiné
Pset_EnvironmentalImpactIndicators - sets with these values: 2

# IfcStair: limon 7:limon 7, limon 7:limon 7:608428
In: SS3
Type - Pset_EnvironmentalImpactIndicators - Reference: limon 7
Type - Pset_StairCommon - IsExternal: no; NosingLength: 0 m; Reference: limon 7; NumberOfRiser: 0; NumberOfTreads: 0
Type - Pset_StairFlightCommon - NosingLength: 0 m; Reference: limon 7; NumberOfRiser: 0; NumberOfTreads: 0
Material: Béton - Béton coulé sur place
Pset_EnvironmentalImpactIndicators - sets with these values: 2

# IfcStairFlight: Volée monobloc:Profondeur de structure 120 mm 2, Escalier coulé sur place:Escalier:400493 Run 1
In: SS1
Type - Pset_EnvironmentalImpactIndicators - Reference: Profondeur de structure 120 mm 2
Type - Pset_StairFlightCommon - Reference: Profondeur de structure 120 mm 2
Material: carrelage 30x30, Maçonnerie - Béton
Pset_StairFlightCommon - NumberOfRiser: 16; NumberOfTreads: 15; RiserHeight: 0.168965 m; TreadLength: 0.29207 m; NosingLength: 0.03 m; TreadLengthAtOffset: 0.29207 m; TreadLengthAtInnerSide: 0.29207 m
Qto_StairFlightBaseQuantities - Length: 6.10691 m; NetVolume: 2.53897 m3

# IfcStairFlight: Volée monobloc:Profondeur de structure 170 mm (3)
Type - Pset_EnvironmentalImpactIndicators - Reference: Profondeur de structure 170 mm
Type - Pset_StairFlightCommon - Reference: Profondeur de structure 170 mm
Material: Maçonnerie - Béton
Pset_StairFlightCommon - NosingLength: 0 m
Name (Escalier coulé sur place:Escalier:...) | In | NumberOfRiser | NumberOfTreads | RiserHeight (m) | TreadLength (m) = TreadLengthAtOffset (m) = TreadLengthAtInnerSide (m) | Length (m) | NetVolume (m3)
390256 Run 1 | Demi-niveau | 8 | 7 | 0.175525 | 0.27895 | 2.7683 | 0.687596
444188 Run 1 | SS3 | 5 | 4 | 0.146 | 0.338 | 1.21095 | 0.391959
457968 Run 1 | SS3 | 8 | 7 | 0.20125 | 0.2275 | 1.72885 | 0.668259

# IfcStairFlight: Volée monobloc:Profondeur de structure 170 mm 3, Escalier coulé sur place:Escalier:447979 Run 1
In: SS2
Type - Pset_EnvironmentalImpactIndicators - Reference: Profondeur de structure 170 mm 3
Type - Pset_StairFlightCommon - Reference: Profondeur de structure 170 mm 3
Material: marbre beige, Maçonnerie - Béton
Pset_StairFlightCommon - NumberOfRiser: 11; NumberOfTreads: 10; RiserHeight: 0.166659 m; TreadLength: 0.296681 m; NosingLength: 0.03 m; TreadLengthAtOffset: 0.296681 m; TreadLengthAtInnerSide: 0.296681 m
Qto_StairFlightBaseQuantities - Length: 3.10509 m; NetVolume: 1.71389 m3

# IfcStairFlight: Volée monobloc:Profondeur de structure 180 (6)
Type - Pset_EnvironmentalImpactIndicators - Reference: Profondeur de structure 180
Type - Pset_StairFlightCommon - Reference: Profondeur de structure 180
Material: carrelage 30x30, Maçonnerie - Béton
Pset_StairFlightCommon - NosingLength: 0.03 m
Name (Escalier coulé sur place:Escalier:...) | In | NumberOfRiser | NumberOfTreads | RiserHeight (m) | TreadLength (m) = TreadLengthAtOffset (m) = TreadLengthAtInnerSide (m) | Length (m) | NetVolume (m3)
345098 Run 1 | Niveau 0 | 5 | 4 | 0.174 | 0.282 | 2.26723 | 0.93241
350448 Run 1 | Niveau 0 | 18 | 17 | 0.163418 | 0.303164 | 7.46351 | 3.16177
446541 Run 1 | SS3 | 4 | 3 | 0.163351 | 0.303297 | 0.97 | 1.05572
447285 Run 1 | SS3 | 4 | 3 | 0.163351 | 0.303297 | 0.973298 | 0.941399
582517 Run 1 | Niveau 1 | 19 | 18 | 0.168327 | 0.293346 | 7.77013 | 3.33982
638436 Run 1 | Niveau 0 | 12 | 11 | 0.151783 | 0.326433 | 3.89799 | 8.56201

# IfcStairFlight: Volée monobloc:Profondeur de structure 200 2, Escalier coulé sur place:Escalier:426584 Run 1
In: SS3
Type - Pset_EnvironmentalImpactIndicators - Reference: Profondeur de structure 200 2
Type - Pset_StairFlightCommon - Reference: Profondeur de structure 200 2
Material: Maçonnerie - Béton
Pset_StairFlightCommon - NosingLength: 0 m; NumberOfRiser: 22; NumberOfTreads: 21; RiserHeight: 0.163147 m; TreadLength: 0.303706 m; TreadLengthAtOffset: 0.303706 m; TreadLengthAtInnerSide: 0.303706 m
Qto_StairFlightBaseQuantities - Length: 8.41905 m; NetVolume: 3.43529 m3

# IfcStairFlight: Volée monobloc:Profondeur de structure 250 mm, Escalier coulé sur place:Escalier:269972 Run 1
In: Niveau 0
Type - Pset_EnvironmentalImpactIndicators - Reference: Profondeur de structure 250 mm
Type - Pset_StairFlightCommon - Reference: Profondeur de structure 250 mm
Material: Dalle, carrelage 15 x 15, Maçonnerie - Béton
Pset_StairFlightCommon - NumberOfRiser: 21; NumberOfTreads: 20; RiserHeight: 0.181076 m; TreadLength: 0.23 m; NosingLength: 0.03 m; TreadLengthAtOffset: 0.23 m; TreadLengthAtInnerSide: 0.23 m
Qto_StairFlightBaseQuantities - Length: 6.88845 m; NetVolume: 2.22275 m3

# IfcStairFlight: Volée non-monobloc:250x13, Escalier assemblé:Escalier:461497 Run 1
In: SS3
Type - Pset_EnvironmentalImpactIndicators - Reference: 250x13
Type - Pset_StairFlightCommon - Reference: 250x13
Pset_StairFlightCommon - NosingLength: 0 m; NumberOfRiser: 19; NumberOfTreads: 18; RiserHeight: 0.167328 m; TreadLength: 0.255972 m; TreadLengthAtOffset: 0.255972 m; TreadLengthAtInnerSide: 0.255972 m
Qto_StairFlightBaseQuantities - Length: 5.28702 m; GrossVolume: 0.0988711 m3; NetVolume: 1.8954 m3

# IfcWall: Mur de base:Générique - Ext. 100 mm, Mur de base:Générique - Ext. 100 mm:396089
In: Demi-niveau
Type - Material: Mur par défaut 0.1 m
Type - Pset_EnvironmentalImpactIndicators - Reference: Générique - Ext. 100 mm
Type - Pset_ReinforcementBarPitchOfWall - Reference: Générique - Ext. 100 mm
Type - Pset_WallCommon - IsExternal: no; Reference: Générique - Ext. 100 mm
Qto_WallBaseQuantities - Height: 2.1542 m; Length: 1.28306 m; Width: 0.1 m; GrossFootprintArea: 0.128306 m2; NetVolume: 0.276397 m3; NetSideArea: 2.76397 m2
Pset_EnvironmentalImpactIndicators - sets with these values: 2
Pset_WallCommon - LoadBearing: no; ExtendToStructure: no; IsExternal: yes

# IfcWall: Mur de base:Générique - Ext. 130 mm, Mur de base:Générique - Ext. 130 mm:592599
In: Niveau 2
Type - Material: Mur par défaut 0.13 m
Type - Pset_EnvironmentalImpactIndicators - Reference: Générique - Ext. 130 mm
Type - Pset_ReinforcementBarPitchOfWall - Reference: Générique - Ext. 130 mm
Type - Pset_WallCommon - IsExternal: no; Reference: Générique - Ext. 130 mm
Qto_WallBaseQuantities - Height: 0.2939 m; Length: 3.14938 m; Width: 0.13 m; GrossFootprintArea: 0.409419 m2; NetVolume: 0.120328 m3; NetSideArea: 0.925603 m2
Pset_EnvironmentalImpactIndicators - sets with these values: 2
Pset_WallCommon - LoadBearing: no; ExtendToStructure: no; IsExternal: yes

# IfcWall: Mur de base:Générique - Ext. 150 mm (9)
In: Niveau 2
Type - Material: Mur par défaut 0.15 m
Type - Pset_EnvironmentalImpactIndicators - Reference: Générique - Ext. 150 mm
Type - Pset_ReinforcementBarPitchOfWall - Reference: Générique - Ext. 150 mm
Type - Pset_WallCommon - IsExternal: no; Reference: Générique - Ext. 150 mm
Qto_WallBaseQuantities - Width: 0.15 m
Pset_EnvironmentalImpactIndicators - sets with these values: 2
Pset_WallCommon - LoadBearing: no; ExtendToStructure: no; IsExternal: yes
Name (Mur de base:Générique - Ext. 150 mm:...) | Height (m) | Length (m) | GrossFootprintArea (m2) | NetVolume (m3) | NetSideArea (m2)
580901 | 2.098 | 5.27035 | 0.790552 | 1.65858 | 11.0572
582138 | 3.59195 | 1.33584 | 0.200375 | 0.719738 | 4.79825
597479 | 0.175 | 10.0895 | 1.51342 | 0.264849 | 1.76566
600107 | 0.075 | 19.7176 | 2.95763 | 0.221823 | 1.47882
600134 | 0.075 | 36.1713 | 5.4257 | 0.406928 | 2.71285
600183 | 0.075 | 5.4977 | 0.824655 | 0.0618491 | 0.412328
600227 | 0.075 | 20.8867 | 3.133 | 0.234975 | 1.5665
600834 | 0.075 | 1.21179 | 0.181769 | 0.0136327 | 0.0908844
600937 | 0.405 | 10.9887 | 0.018 | 0.667562 | 4.45042

# IfcWall: Mur de base:Générique - Ext. 200 mm (11)
Type - Material: Mur par défaut 0.2 m
Type - Pset_EnvironmentalImpactIndicators - Reference: Générique - Ext. 200 mm
Type - Pset_ReinforcementBarPitchOfWall - Reference: Générique - Ext. 200 mm
Type - Pset_WallCommon - IsExternal: no; Reference: Générique - Ext. 200 mm
Qto_WallBaseQuantities - Width: 0.2 m
Pset_EnvironmentalImpactIndicators - sets with these values: 2
Pset_WallCommon - LoadBearing: no; ExtendToStructure: no; IsExternal: yes
Name (Mur de base:Générique - Ext. 200 mm:...) | In | Height (m) | Length (m) | NetVolume (m3) | NetSideArea (m2) | GrossFootprintArea (m2)
374100 | Demi-niveau | 2.11132 | 3.90035 | 1.64698 | 8.2349
374134 | Demi-niveau | 2.10973 | 0.72238 | 0.304805 | 1.52403 | 0.144476
569561 | Niveau 2 | 2.747 | 10.871 | 5.97254 | 29.8627 | 2.17421
572727 | Niveau 2 | 2.07 | 3.901 | 1.61501 | 8.07507 | 0.7802
578642 | Niveau 2 | 3.237 | 8.00673 | 5.18356 | 25.9178 | 1.60135
592508 | Niveau 2 | 0.418 | 4.34171 | 0.362967 | 1.81483 | 0.868342
600426 | Niveau 2 | 0.547 | 17.0322 | 1.86332 | 9.31662 | 3.40644
600541 | Niveau 2 | 0.547 | 4.31075 | 0.471596 | 2.35798 | 0.862149
600585 | Niveau 2 | 0.547 | 33.2527 | 3.63785 | 18.1893 | 6.65055
600610 | Niveau 2 | 0.547 | 19.4788 | 2.13099 | 10.6549 | 3.89577
651243 | Niveau 2 | 0.487 | 7.01735 | 0.683489 | 3.41745 | 1.40347

# IfcWall: Mur de base:Générique - Ext. 220 mm (4)
Type - Material: Mur par défaut 0.22 m
Type - Pset_EnvironmentalImpactIndicators - Reference: Générique - Ext. 220 mm
Type - Pset_ReinforcementBarPitchOfWall - Reference: Générique - Ext. 220 mm
Type - Pset_WallCommon - IsExternal: no; Reference: Générique - Ext. 220 mm
Qto_WallBaseQuantities - Width: 0.22 m
Pset_EnvironmentalImpactIndicators - sets with these values: 2
Pset_WallCommon - LoadBearing: no; ExtendToStructure: no; IsExternal: yes
Name (Mur de base:Générique - Ext. 220 mm:...) | In | Height (m) | Length (m) | GrossFootprintArea (m2) | NetVolume (m3) | NetSideArea (m2)
503844 | SS3 | 0.814659 | 5.592 | 1.23024 | 1.00223 | 4.55557
503856 | SS3 | 0.814659 | 2.7464 | 0.604209 | 0.492224 | 2.23738
559276 | Niveau 2 | 3.01 | 3.65451 | 0.803992 | 2.42002 | 11.0001
581503 | Niveau 2 | 2.74 | 1.75149 | 0.385327 | 1.0558 | 4.79908

# IfcWall: Mur de base:Générique - Ext. 240 mm, Mur de base:Générique - Ext. 240 mm:559971
In: Niveau 2
Type - Material: Mur par défaut 0.24 m
Type - Pset_EnvironmentalImpactIndicators - Reference: Générique - Ext. 240 mm
Type - Pset_ReinforcementBarPitchOfWall - Reference: Générique - Ext. 240 mm
Type - Pset_WallCommon - IsExternal: no; Reference: Générique - Ext. 240 mm
Qto_WallBaseQuantities - Height: 2.992 m; Length: 1.3961 m; Width: 0.24 m; GrossFootprintArea: 0.335064 m2; NetVolume: 1.00251 m3; NetSideArea: 4.17713 m2
Pset_EnvironmentalImpactIndicators - sets with these values: 2
Pset_WallCommon - LoadBearing: no; ExtendToStructure: no; IsExternal: yes

# IfcWall: Mur de base:Générique - Ext. 250 mm (4)
Type - Material: Mur par défaut 0.25 m
Type - Pset_EnvironmentalImpactIndicators - Reference: Générique - Ext. 250 mm
Type - Pset_ReinforcementBarPitchOfWall - Reference: Générique - Ext. 250 mm
Type - Pset_WallCommon - IsExternal: no; Reference: Générique - Ext. 250 mm
Qto_WallBaseQuantities - Width: 0.25 m
Pset_EnvironmentalImpactIndicators - sets with these values: 2
Pset_WallCommon - LoadBearing: no; ExtendToStructure: no; IsExternal: yes
Name (Mur de base:Générique - Ext. 250 mm:...) | In | Height (m) | Length (m) | NetVolume (m3) | NetSideArea (m2)
465245 | SS3 | 4.18946 | 2.54976 | 2.67053 | 10.6821
466566 | SS3 | 3.45795 | 2.17232 | 1.87794 | 7.51176 | Qto_WallBaseQuantities - GrossFootprintArea: 0.543079 m2
519228 | Niveau 1 | 3.2409 | 4.38362 | 3.55171 | 14.2069
559395 | Niveau 2 | 0.858 | 9.71447 | 2.08375 | 8.33502

# IfcWall: Mur de base:Générique - Ext. 270 mm, Mur de base:Générique - Ext. 270 mm:301213
In: Niveau 0
Type - Material: Mur par défaut 0.27 m
Type - Pset_EnvironmentalImpactIndicators - Reference: Générique - Ext. 270 mm
Type - Pset_ReinforcementBarPitchOfWall - Reference: Générique - Ext. 270 mm
Type - Pset_WallCommon - IsExternal: no; Reference: Générique - Ext. 270 mm
Qto_WallBaseQuantities - Height: 3.40653 m; Length: 3.83666 m; Width: 0.27 m; GrossFootprintArea: 1.0359 m2; NetVolume: 3.52881 m3; NetSideArea: 13.0697 m2
Pset_EnvironmentalImpactIndicators - sets with these values: 2
Pset_WallCommon - LoadBearing: no; ExtendToStructure: no; IsExternal: yes

# IfcWall: Mur de base:Générique - Ext. 280mm (2)
In: Niveau 0
Type - Material: Mur par défaut 0.28 m
Type - Pset_EnvironmentalImpactIndicators - Reference: Générique - Ext. 280mm
Type - Pset_ReinforcementBarPitchOfWall - Reference: Générique - Ext. 280mm
Type - Pset_WallCommon - IsExternal: no; Reference: Générique - Ext. 280mm
Qto_WallBaseQuantities - Height: 2.00547 m; Width: 0.28 m
Pset_EnvironmentalImpactIndicators - sets with these values: 2
Pset_WallCommon - LoadBearing: no; ExtendToStructure: no; IsExternal: yes
Name (Mur de base:Générique - Ext. 280mm:...) | Length (m) | GrossFootprintArea (m2) | NetVolume (m3) | NetSideArea (m2)
637705 | 4.7626 | 1.33353 | 2.67435 | 9.55124
638187 | 4.73395 | 1.32551 | 2.65826 | 9.49377

# IfcWall: Mur de base:Générique - Ext. 300 mm (9)
Type - Material: Mur par défaut 0.3 m
Type - Pset_EnvironmentalImpactIndicators - Reference: Générique - Ext. 300 mm
Type - Pset_ReinforcementBarPitchOfWall - Reference: Générique - Ext. 300 mm
Type - Pset_WallCommon - IsExternal: no; Reference: Générique - Ext. 300 mm
Qto_WallBaseQuantities - Width: 0.3 m
Pset_EnvironmentalImpactIndicators - sets with these values: 2
Pset_WallCommon - LoadBearing: no; ExtendToStructure: no; IsExternal: yes
Name (Mur de base:Générique - Ext. 300 mm:...) | In | Height (m) | Length (m) | NetVolume (m3) | NetSideArea (m2) | GrossFootprintArea (m2)
340521 | Niveau 0 | 0.524591 | 10.682 | 1.68111 | 5.60369
404240 | SS3 | 5.40344 | 12.5168 | 20.2902 | 67.6339
404780 | Niveau 0 | 3.27 | 8.21958 | 8.0634 | 26.878 | 2.46587
405389 | SS2 | 2.59115 | 10.8469 | 8.43176 | 28.1059 | 3.25406
504326 | Demi-niveau | 0.516131 | 1.19859 | 0.185589 | 0.618632 | 0.359578
504423 | Demi-niveau | 0.516131 | 1.062 | 0.16444 | 0.548132 | 0.3186
523170 | SS3 | 5.40344 | 11.4578 | 18.5735 | 61.9117 | 3.43735
523188 | SS3 | 5.50344 | 3.81009 | 6.29058 | 20.9686 | 1.14303
623891 | Niveau 1 | 1.40518 | 10.6083 | 4.47198 | 14.9066

# IfcWall: Mur de base:Générique - Ext. 360 (4)
In: SS2
Type - Material: Mur par défaut 0.36 m
Type - Pset_EnvironmentalImpactIndicators - Reference: Générique - Ext. 360
Type - Pset_ReinforcementBarPitchOfWall - Reference: Générique - Ext. 360
Type - Pset_WallCommon - IsExternal: no; Reference: Générique - Ext. 360
Qto_WallBaseQuantities - Width: 0.36 m
Pset_EnvironmentalImpactIndicators - sets with these values: 2
Pset_WallCommon - LoadBearing: no; ExtendToStructure: no; IsExternal: yes
Name (Mur de base:Générique - Ext. 360:...) | Height (m) | Length (m) | GrossFootprintArea (m2) | NetVolume (m3) | NetSideArea (m2)
410939 | 2.66421 | 18.8154 | 6.77353 | 18.0461 | 50.1282
411018 | 2.66421 | 9.94375 | 3.57975 | 9.53722 | 26.4923
411039 | 2.66421 | 8.387 | 3.01932 | 8.04412 | 22.3448
411775 | 2.69625 | 4.92009 | 1.77123 | 4.77568 | 13.2658

# IfcWall: Mur de base:Générique - Ext.1.09m (2)
In: Niveau 0
Type - Material: Mur par défaut 1.09 m
Type - Pset_EnvironmentalImpactIndicators - Reference: Générique - Ext.1.09m
Type - Pset_ReinforcementBarPitchOfWall - Reference: Générique - Ext.1.09m
Type - Pset_WallCommon - IsExternal: no; Reference: Générique - Ext.1.09m
Qto_WallBaseQuantities - Width: 1.09 m
Pset_EnvironmentalImpactIndicators - sets with these values: 2
Pset_WallCommon - LoadBearing: no; ExtendToStructure: no; IsExternal: yes
Name (Mur de base:Générique - Ext.1.09m:...) | Height (m) | Length (m) | GrossFootprintArea (m2) | NetVolume (m3) | NetSideArea (m2)
403879 | 6.51174 | 18.3963 | 20.0519 | 130.573 | 119.792
637366 | 3.61113 | 1.07316 | 1.16974 | 4.22408 | 3.87531

# IfcWall: Mur de base:Générique - Ext.120 (2)
In: Demi-niveau
Type - Material: Mur par défaut 0.12 m
Type - Pset_EnvironmentalImpactIndicators - Reference: Générique - Ext.120
Type - Pset_ReinforcementBarPitchOfWall - Reference: Générique - Ext.120
Type - Pset_WallCommon - IsExternal: no; Reference: Générique - Ext.120
Qto_WallBaseQuantities - Height: 0.929588 m; Width: 0.12 m
Pset_EnvironmentalImpactIndicators - sets with these values: 2
Pset_WallCommon - LoadBearing: no; ExtendToStructure: no; IsExternal: yes
Name (Mur de base:Générique - Ext.120:...) | Length (m) | GrossFootprintArea (m2) | NetVolume (m3) | NetSideArea (m2)
652912 | 18.9417 | 2.27301 | 2.11296 | 17.608
655825 | 8.23066 | 0.987679 | 0.918135 | 7.65112

# IfcWall: Mur de base:Générique - Ext.140 (2)
In: Niveau 1
Type - Material: Mur par défaut 0.14 m
Type - Pset_EnvironmentalImpactIndicators - Reference: Générique - Ext.140
Type - Pset_ReinforcementBarPitchOfWall - Reference: Générique - Ext.140
Type - Pset_WallCommon - IsExternal: no; Reference: Générique - Ext.140
Qto_WallBaseQuantities - Width: 0.14 m
Pset_EnvironmentalImpactIndicators - sets with these values: 2
Pset_WallCommon - LoadBearing: no; ExtendToStructure: no; IsExternal: yes
Name (Mur de base:Générique - Ext.140:...) | Height (m) | Length (m) | NetVolume (m3) | NetSideArea (m2)
513818 | 0.686502 | 4.065 | 0.390688 | 2.79063
514692 | 3.58061 | 0.822 | 0.412057 | 2.94327 | Qto_WallBaseQuantities - GrossFootprintArea: 0.11508 m2

# IfcWall: Mur de base:Générique - Ext.180 (3)
In: SS3
Type - Material: Mur par défaut 0.18 m
Type - Pset_EnvironmentalImpactIndicators - Reference: Générique - Ext.180
Type - Pset_ReinforcementBarPitchOfWall - Reference: Générique - Ext.180
Type - Pset_WallCommon - IsExternal: no; Reference: Générique - Ext.180
Qto_WallBaseQuantities - Width: 0.18 m
Pset_EnvironmentalImpactIndicators - sets with these values: 2
Pset_WallCommon - LoadBearing: no; ExtendToStructure: no; IsExternal: yes
Name (Mur de base:Générique - Ext.180:...) | Height (m) | Length (m) | NetVolume (m3) | NetSideArea (m2) | GrossFootprintArea (m2)
461350 | 3.16191 | 3.07061 | 1.74762 | 9.70899
463302 | 3.16191 | 4.7305 | 2.69233 | 14.9574 | 0.818107
466242 | 3.01191 | 1.75519 | 0.951563 | 5.28646 | 0.315827

# IfcWall: Mur de base:Générique - Ext.210, Mur de base:Générique - Ext.210:578751
In: Niveau 2
Type - Material: Mur par défaut 0.21 m
Type - Pset_EnvironmentalImpactIndicators - Reference: Générique - Ext.210
Type - Pset_ReinforcementBarPitchOfWall - Reference: Générique - Ext.210
Type - Pset_WallCommon - IsExternal: no; Reference: Générique - Ext.210
Qto_WallBaseQuantities - Height: 3.24 m; Length: 4.38394 m; Width: 0.21 m; GrossFootprintArea: 0.920628 m2; NetVolume: 2.98284 m3; NetSideArea: 14.204 m2
Pset_EnvironmentalImpactIndicators - sets with these values: 2
Pset_WallCommon - LoadBearing: no; ExtendToStructure: no; IsExternal: yes

# IfcWall: Mur de base:Générique - Ext.260 (2)
Type - Material: Mur par défaut 0.26 m
Type - Pset_EnvironmentalImpactIndicators - Reference: Générique - Ext.260
Type - Pset_ReinforcementBarPitchOfWall - Reference: Générique - Ext.260
Type - Pset_WallCommon - IsExternal: no; Reference: Générique - Ext.260
Qto_WallBaseQuantities - Width: 0.26 m
Pset_EnvironmentalImpactIndicators - sets with these values: 2
Pset_WallCommon - LoadBearing: no; ExtendToStructure: no; IsExternal: yes
Name (Mur de base:Générique - Ext.260:...) | In | Height (m) | Length (m) | NetVolume (m3) | NetSideArea (m2)
358152 | Niveau 0 | 3.60653 | 13.8647 | 13.0009 | 50.0035
514552 | Niveau 1 | 3.23347 | 2.02606 | 1.70331 | 6.5512 | Qto_WallBaseQuantities - GrossFootprintArea: 0.526775 m2

# IfcWall: Mur de base:Générique - Ext.320 mm (7)
Type - Material: Mur par défaut 0.32 m
Type - Pset_EnvironmentalImpactIndicators - Reference: Générique - Ext.320 mm
Type - Pset_ReinforcementBarPitchOfWall - Reference: Générique - Ext.320 mm
Type - Pset_WallCommon - IsExternal: no; Reference: Générique - Ext.320 mm
Qto_WallBaseQuantities - Width: 0.32 m
Pset_EnvironmentalImpactIndicators - sets with these values: 2
Pset_WallCommon - LoadBearing: no; ExtendToStructure: no; IsExternal: yes
Name (Mur de base:Générique - Ext.320 mm:...) | In | Height (m) | Length (m) | GrossFootprintArea (m2) | NetVolume (m3) | NetSideArea (m2)
301802 | Niveau 0 | 2.63153 | 10.8761 | 3.48034 | 9.15861 | 28.6206
394421 | SS3 | 3.817 | 5.74145 |  | 7.01283 | 21.9151
395067 | SS3 | 3.817 | 2.7464 | 0.878849 | 3.35457 | 10.483
402624 | SS3 | 3.61924 | 3.653 | 1.16896 | 4.23074 | 13.2211
504103 | SS3 | 0.986437 | 2.61644 | 0.837262 | 0.825906 | 2.58096
519932 | Niveau 1 | 1.07111 | 10.6495 | 3.40783 | 3.65016 | 11.4067
561082 | Niveau 2 | 1.22371 | 11.217 | 3.58943 | 4.39243 | 13.7264

# IfcWall: Mur de base:Générique - Ext.330 mm, Mur de base:Générique - Ext.330 mm:559613
In: Niveau 2
Type - Material: Mur par défaut 0.33 m
Type - Pset_EnvironmentalImpactIndicators - Reference: Générique - Ext.330 mm
Type - Pset_ReinforcementBarPitchOfWall - Reference: Générique - Ext.330 mm
Type - Pset_WallCommon - IsExternal: no; Reference: Générique - Ext.330 mm
Qto_WallBaseQuantities - Height: 3.48474 m; Length: 4.5195 m; Width: 0.33 m; GrossFootprintArea: 1.49143 m2; NetVolume: 5.19726 m3; NetSideArea: 15.7493 m2
Pset_EnvironmentalImpactIndicators - sets with these values: 2
Pset_WallCommon - LoadBearing: no; ExtendToStructure: no; IsExternal: yes

# IfcWall: Mur de base:Générique - Ext.340, Mur de base:Générique - Ext.340:595101
In: Niveau 2
Type - Material: Mur par défaut 0.34 m
Type - Pset_EnvironmentalImpactIndicators - Reference: Générique - Ext.340
Type - Pset_ReinforcementBarPitchOfWall - Reference: Générique - Ext.340
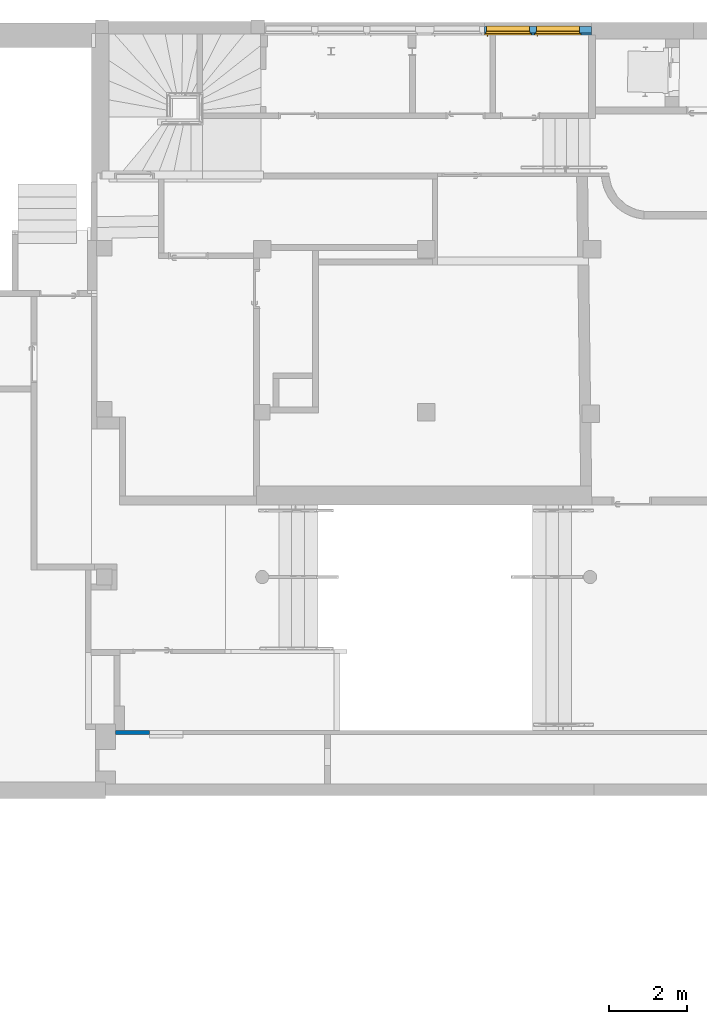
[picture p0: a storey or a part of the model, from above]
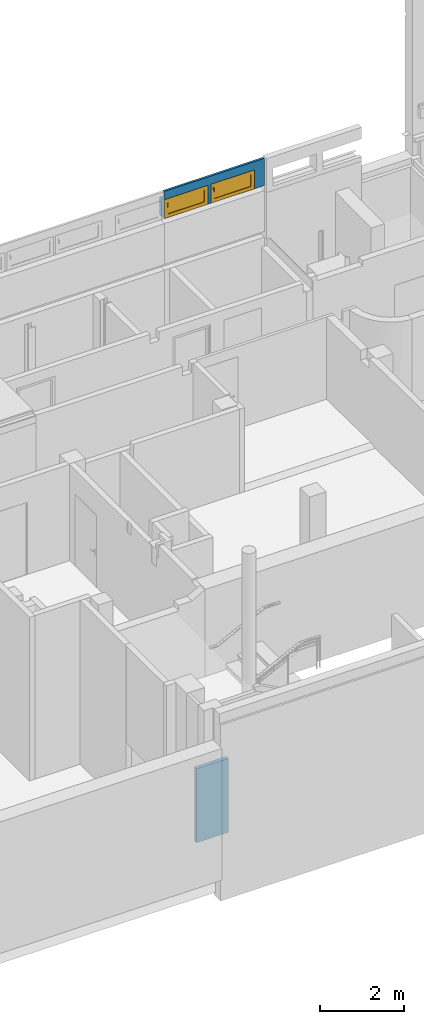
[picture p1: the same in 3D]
Properties of the parts of a building model (IFC4), part 7 of 8

# IfcWall: Mur de base:Générique - Ext.340, Mur de base:Générique - Ext.340:595101
Type - Pset_WallCommon - IsExternal: no; Reference: Générique - Ext.340
Qto_WallBaseQuantities - Height: 3.145 m; Length: 2.52212 m; Width: 0.34 m; GrossFootprintArea: 0.857521 m2; NetVolume: 2.6969 m3; NetSideArea: 7.93207 m2
Pset_EnvironmentalImpactIndicators - sets with these values: 2
Pset_WallCommon - LoadBearing: no; ExtendToStructure: no; IsExternal: yes

# IfcWall: Mur de base:Générique - Ext.350, Mur de base:Générique - Ext.350:505193
In: SS3
Type - Material: Mur par défaut 0.35 m
Type - Pset_EnvironmentalImpactIndicators - Reference: Générique - Ext.350
Type - Pset_ReinforcementBarPitchOfWall - Reference: Générique - Ext.350
Type - Pset_WallCommon - IsExternal: no; Reference: Générique - Ext.350
Qto_WallBaseQuantities - Height: 0.986437 m; Length: 10.9489 m; Width: 0.35 m; NetVolume: 3.78013 m3; NetSideArea: 10.8004 m2
Pset_EnvironmentalImpactIndicators - sets with these values: 2
Pset_WallCommon - LoadBearing: no; ExtendToStructure: no; IsExternal: yes

# IfcWall: Mur de base:Générique - Ext.370 (10)
Type - Material: Mur par défaut 0.37 m
Type - Pset_EnvironmentalImpactIndicators - Reference: Générique - Ext.370
Type - Pset_ReinforcementBarPitchOfWall - Reference: Générique - Ext.370
Type - Pset_WallCommon - IsExternal: no; Reference: Générique - Ext.370
Qto_WallBaseQuantities - Width: 0.37 m
Pset_EnvironmentalImpactIndicators - sets with these values: 2
Pset_WallCommon - LoadBearing: no; ExtendToStructure: no; IsExternal: yes
Name (Mur de base:Générique - Ext.370:...) | In | Height (m) | Length (m) | NetVolume (m3) | NetSideArea (m2) | GrossFootprintArea (m2)
308986 | Niveau 0 | 3.2711 | 8.57958 | 10.3839 | 28.0647
310119 | Niveau 0 | 3.6111 | 5.68902 | 7.60114 | 20.5436
373610 | Niveau 0 | 3.2711 | 8.3884 | 10.1526 | 27.4393 | 3.10371
373647 | Demi-niveau | 2.10973 | 0.0822075 | 0.0641711 | 0.173436 | 0.0304168
374217 | Demi-niveau | 2.34558 | 3.64879 | 3.16665 | 8.55852 | 1.35005
375386 | Demi-niveau | 2.10973 | 1.43375 | 1.11918 | 3.02482 | 0.530487
402305 | SS3 | 3.82385 | 15.2047 | 21.512 | 58.1406 | 5.62575
414112 | SS3 | 0.469297 | 1.888 | 0.327832 | 0.886033 | 0.69856
414805 | Demi-niveau | 0.469297 | 2.149 | 0.373152 | 1.00852 | 0.79513
499293 | SS3 | 0.121834 | 1.83383 | 0.082666 | 0.223421 | 0.678515

# IfcWall: Mur de base:Générique - Ext.380, Mur de base:Générique - Ext.380:513674
In: Niveau 1
Type - Material: Mur par défaut 0.38 m
Type - Pset_EnvironmentalImpactIndicators - Reference: Générique - Ext.380
Type - Pset_ReinforcementBarPitchOfWall - Reference: Générique - Ext.380
Type - Pset_WallCommon - IsExternal: no; Reference: Générique - Ext.380
Qto_WallBaseQuantities - Height: 1.36201 m; Length: 5.82969 m; Width: 0.38 m; NetVolume: 3.01724 m3; NetSideArea: 7.94011 m2
Pset_EnvironmentalImpactIndicators - sets with these values: 2
Pset_WallCommon - LoadBearing: no; ExtendToStructure: no; IsExternal: yes

# IfcWall: Mur de base:Générique - Ext.400 (2)
Type - Material: Mur par défaut 0.4 m
Type - Pset_EnvironmentalImpactIndicators - Reference: Générique - Ext.400
Type - Pset_ReinforcementBarPitchOfWall - Reference: Générique - Ext.400
Type - Pset_WallCommon - IsExternal: no; Reference: Générique - Ext.400
Qto_WallBaseQuantities - Width: 0.4 m
Pset_EnvironmentalImpactIndicators - sets with these values: 2
Pset_WallCommon - LoadBearing: no; ExtendToStructure: no; IsExternal: yes
Name (Mur de base:Générique - Ext.400:...) | In | Height (m) | Length (m) | NetVolume (m3) | NetSideArea (m2)
453091 | SS3 | 4.75792 | 10.8761 | 20.699 | 51.7474
637413 | Niveau 0 | 2.90061 | 1.07316 | 1.24513 | 3.11282 | Qto_WallBaseQuantities - GrossFootprintArea: 0.429263 m2

# IfcWall: Mur de base:Générique - Ext.420 (4)
Type - Material: Mur par défaut 0.42 m
Type - Pset_EnvironmentalImpactIndicators - Reference: Générique - Ext.420
Type - Pset_ReinforcementBarPitchOfWall - Reference: Générique - Ext.420
Type - Pset_WallCommon - IsExternal: no; Reference: Générique - Ext.420
Qto_WallBaseQuantities - Width: 0.42 m
Pset_EnvironmentalImpactIndicators - sets with these values: 2
Pset_WallCommon - LoadBearing: no; ExtendToStructure: no; IsExternal: yes
Name (Mur de base:Générique - Ext.420:...) | In | Height (m) | Length (m) | GrossFootprintArea (m2) | NetVolume (m3) | NetSideArea (m2)
394890 | SS3 | 4.757 | 2.61644 | 1.09891 | 5.2275 | 12.4464
395786 | Demi-niveau | 0.466376 | 0.352473 | 0.148039 | 0.0690416 | 0.164385
403505 | SS3 | 4.00186 | 1.63553 | 0.686924 | 2.74898 | 6.54518
404346 | SS3 | 3.82385 | 8.23066 | 3.45688 | 13.2186 | 31.4728

# IfcWall: Mur de base:Générique - Ext.440 (3)
In: Niveau 1
Type - Material: Mur par défaut 0.44 m
Type - Pset_EnvironmentalImpactIndicators - Reference: Générique - Ext.440
Type - Pset_ReinforcementBarPitchOfWall - Reference: Générique - Ext.440
Type - Pset_WallCommon - IsExternal: no; Reference: Générique - Ext.440
Qto_WallBaseQuantities - Height: 1.02203 m; Width: 0.44 m
Pset_EnvironmentalImpactIndicators - sets with these values: 2
Pset_WallCommon - LoadBearing: no; ExtendToStructure: no; IsExternal: yes
Name (Mur de base:Générique - Ext.440:...) | Length (m) | NetVolume (m3) | NetSideArea (m2)
510492 | 12.1483 | 5.46301 | 12.4159
539663 | 2.77481 | 1.24782 | 2.83595
540748 | 4.22213 | 1.89867 | 4.31516

# IfcWall: Mur de base:Générique - Ext.450, Mur de base:Générique - Ext.450:513360
In: Niveau 1
Type - Material: Mur par défaut 0.45 m
Type - Pset_EnvironmentalImpactIndicators - Reference: Générique - Ext.450
Type - Pset_ReinforcementBarPitchOfWall - Reference: Générique - Ext.450
Type - Pset_WallCommon - IsExternal: no; Reference: Générique - Ext.450
Qto_WallBaseQuantities - Height: 1.36201 m; Length: 12.512 m; Width: 0.45 m; NetVolume: 7.66867 m3; NetSideArea: 17.0415 m2
Pset_EnvironmentalImpactIndicators - sets with these values: 2
Pset_WallCommon - LoadBearing: no; ExtendToStructure: no; IsExternal: yes

# IfcWall: Mur de base:Générique - Ext.460 (2)
In: Niveau 0
Type - Material: Mur par défaut 0.46 m
Type - Pset_EnvironmentalImpactIndicators - Reference: Générique - Ext.460
Type - Pset_ReinforcementBarPitchOfWall - Reference: Générique - Ext.460
Type - Pset_WallCommon - IsExternal: no; Reference: Générique - Ext.460
Qto_WallBaseQuantities - Width: 0.46 m
Pset_EnvironmentalImpactIndicators - sets with these values: 2
Pset_WallCommon - LoadBearing: no; ExtendToStructure: no; IsExternal: yes
Name (Mur de base:Générique - Ext.460:...) | Height (m) | Length (m) | GrossFootprintArea (m2) | NetVolume (m3) | NetSideArea (m2)
395885 | 3.6111 | 1.83577 | 0.844456 | 3.04942 | 6.62917
396361 | 3.2711 | 2.69644 | 1.24036 | 4.05736 | 8.82035

# IfcWall: Mur de base:Générique - Ext.480 mm (5)
Type - Material: Mur par défaut 0.48 m
Type - Pset_EnvironmentalImpactIndicators - Reference: Générique - Ext.480 mm
Type - Pset_ReinforcementBarPitchOfWall - Reference: Générique - Ext.480 mm
Type - Pset_WallCommon - IsExternal: no; Reference: Générique - Ext.480 mm
Qto_WallBaseQuantities - Width: 0.48 m
Pset_EnvironmentalImpactIndicators - sets with these values: 2
Pset_WallCommon - LoadBearing: no; ExtendToStructure: no; IsExternal: yes
Name (Mur de base:Générique - Ext.480 mm:...) | In | Height (m) | Length (m) | GrossFootprintArea (m2) | NetVolume (m3) | NetSideArea (m2)
300032 | Niveau 0 | 3.40653 | 1.19528 | 0.573735 | 1.95444 | 4.07175
405606 | SS2 | 2.34115 | 0.796213 | 0.382182 | 0.894745 | 1.86405
410903 | SS2 | 2.66421 | 3.027 | 1.45296 | 3.871 | 8.06458
517909 | Niveau 1 | 1.36201 | 4.17948 |  | 2.7324 | 5.6925
534143 | Niveau 1 | 1.36201 | 16.8286 |  | 11.002 | 22.9208

# IfcWall: Mur de base:Générique - Ext.630 (2)
Type - Material: Mur par défaut 0.63 m
Type - Pset_EnvironmentalImpactIndicators - Reference: Générique - Ext.630
Type - Pset_ReinforcementBarPitchOfWall - Reference: Générique - Ext.630
Type - Pset_WallCommon - IsExternal: no; Reference: Générique - Ext.630
Qto_WallBaseQuantities - Width: 0.63 m
Pset_EnvironmentalImpactIndicators - sets with these values: 2
Pset_WallCommon - LoadBearing: no; ExtendToStructure: no; IsExternal: yes
Name (Mur de base:Générique - Ext.630:...) | In | Height (m) | Length (m) | GrossFootprintArea (m2) | NetVolume (m3) | NetSideArea (m2)
405704 | SS2 | 2.59115 | 4.27125 | 2.69089 | 6.97248 | 11.0674
405738 | SS3 | 3.99003 | 8.34137 | 5.25506 | 20.9679 | 33.2823

# IfcWall: Mur de base:Générique - Ext.650, Mur de base:Générique - Ext.650:403078
In: SS2
Type - Material: Mur par défaut 0.65 m
Type - Pset_EnvironmentalImpactIndicators - Reference: Générique - Ext.650
Type - Pset_ReinforcementBarPitchOfWall - Reference: Générique - Ext.650
Type - Pset_WallCommon - IsExternal: no; Reference: Générique - Ext.650
Qto_WallBaseQuantities - Height: 2.59115 m; Length: 10.5583 m; Width: 0.65 m; GrossFootprintArea: 6.86286 m2; NetVolume: 17.7827 m3; NetSideArea: 27.358 m2
Pset_EnvironmentalImpactIndicators - sets with these values: 2
Pset_WallCommon - LoadBearing: no; ExtendToStructure: no; IsExternal: yes

# IfcWall: Mur de base:Générique - Ext.70, Mur de base:Générique - Ext.70:575866
In: Niveau 2
Type - Material: Mur par défaut 0.07 m
Type - Pset_EnvironmentalImpactIndicators - Reference: Générique - Ext.70
Type - Pset_ReinforcementBarPitchOfWall - Reference: Générique - Ext.70
Type - Pset_WallCommon - IsExternal: no; Reference: Générique - Ext.70
Qto_WallBaseQuantities - Height: 2.712 m; Length: 3.234 m; Width: 0.07 m; GrossFootprintArea: 0.22638 m2; NetVolume: 0.613943 m3; NetSideArea: 8.77061 m2
Pset_EnvironmentalImpactIndicators - sets with these values: 2
Pset_WallCommon - LoadBearing: no; ExtendToStructure: no; IsExternal: yes

# IfcWall: Mur de base:Générique - Ext.920 mm, Mur de base:Générique - Ext.920 mm:454386
In: SS3
Type - Material: Mur par défaut 0.92 m
Type - Pset_EnvironmentalImpactIndicators - Reference: Générique - Ext.920 mm
Type - Pset_ReinforcementBarPitchOfWall - Reference: Générique - Ext.920 mm
Type - Pset_WallCommon - IsExternal: no; Reference: Générique - Ext.920 mm
Qto_WallBaseQuantities - Height: 5.74436 m; Length: 19.2334 m; Width: 0.92 m; NetVolume: 101.645 m3; NetSideArea: 110.484 m2
Pset_EnvironmentalImpactIndicators - sets with these values: 2
Pset_WallCommon - LoadBearing: no; ExtendToStructure: no; IsExternal: yes

# IfcWall: Mur de base:Générique - Int. 100 mm (61)
Type - Material: Mur par défaut 0.1 m
Type - Pset_EnvironmentalImpactIndicators - Reference: Générique - Int. 100 mm
Type - Pset_ReinforcementBarPitchOfWall - Reference: Générique - Int. 100 mm
Type - Pset_WallCommon - IsExternal: no; Reference: Générique - Int. 100 mm
Qto_WallBaseQuantities - Width: 0.1 m
Pset_EnvironmentalImpactIndicators - sets with these values: 2
Pset_WallCommon - LoadBearing: no; ExtendToStructure: no
Name (Mur de base:Générique - Int. 100 mm:...) | In | Height (m) | Length (m) | GrossFootprintArea (m2) | NetVolume (m3) | NetSideArea (m2)
287014 | Niveau 0 | 3.44153 | 0.462602 | 0.0462602 | 0.159206 | 1.59206
287029 | Niveau 0 | 3.44153 | 0.184741 | 0.0184741 | 0.063579 | 0.63579
287357 | Niveau 0 | 3.40653 | 0.234741 | 0.0193515 | 0.0799651 | 0.799651
287384 | Niveau 0 | 3.44153 | 0.295 | 0.0295 | 0.101525 | 1.01525
287400 | Niveau 0 | 3.44153 | 0.168225 | 0.0168225 | 0.0578952 | 0.578952
287732 | Niveau 0 | 3.40653 | 1.32461 | 0.132461 | 0.451233 | 4.51233
296963 | Niveau 0 | 3.41113 | 1.94122 | 0.194046 | 0.662176 | 6.62176
297179 | Niveau 0 | 2.32615 | 2.13832 | 0.213756 | 0.497405 | 4.97405
297194 | Niveau 0 | 3.40653 | 1.54525 | 0.154373 | 0.526393 | 5.26393
300209 | Niveau 0 | 3.41113 | 1.06441 | 0.0781067 | 0.363085 | 3.63085
300909 | Niveau 0 | 2.22615 | 1.19034 | 0.110921 | 0.264987 | 2.64987
300949 | Niveau 0 | 3.40653 | 2.94606 | 0.292563 | 1.00358 | 10.0358
301066 | Niveau 0 | 3.41113 | 0.669275 | 0.0648847 | 0.228298 | 2.28298
301627 | Niveau 0 | 3.40653 | 1.91626 | 0.181552 | 0.652779 | 6.52779
377680 | Niveau 0 | 3.41113 | 0.645839 | 0.0586441 | 0.220304 | 2.20304
377846 | Niveau 0 | 3.40653 | 1.03956 | 0.0909882 | 0.354129 | 3.54129
378018 | Niveau 0 | 1.08038 | 3.95341 | 0.393126 | 0.427117 | 4.27117
378118 | Niveau 0 | 1.18498 | 1.10363 | 0.0988987 | 0.130778 | 1.30778
378964 | Niveau 0 | 2.05143 | 3.90133 |  | 0.80033 | 8.0033
422508 | SS3 | 2.15 | 0.880411 | 0.0880411 | 0.189288 | 1.89288
423234 | SS3 | 0.517 | 0.859 | 0.0859 | 0.0444103 | 0.444103
423285 | SS3 | 2.61 | 15.4145 | 1.54145 | 4.02319 | 40.2319
433259 | Demi-niveau | 2.12104 | 3.90035 |  | 0.82728 | 8.2728
446040 | SS3 | 5.00344 | 1.44424 | 0.144424 | 0.722618 | 7.22618
446218 | SS3 | 4.75344 | 1.03275 | 0.103275 | 0.490912 | 4.90912
446275 | SS3 | 4.75344 | 0.857 | 0.0857 | 0.40737 | 4.0737
446315 | SS3 | 4.75344 | 1.95297 | 0.195297 | 0.928332 | 9.28332
446341 | SS3 | 2.50432 | 2.74133 | 0.274133 | 0.686518 | 6.86518
447086 | SS3 | 2.15 | 5.637 | 0.5637 | 1.21195 | 12.1195
452045 | SS3 | 0.179 | 1.13488 | 0.113488 | 0.0203144 | 0.203144
454750 | SS3 | 0.390919 | 7.95742 | 0.795742 | 0.311071 | 3.11071
470599 | SS1 | 2.43344 | 7.82136 | 0.782136 | 1.90328 | 19.0328
483651 | SS1 | 2.21844 | 2.5944 | 0.25931 | 0.575551 | 5.75551
483790 | SS1 | 2.23844 | 1.68029 | 0.168029 | 0.376122 | 3.76122
483821 | SS1 | 2.23844 | 2.756 | 0.2756 | 0.616913 | 6.16913
502024 | SS3 | 4.75344 | 0.757 | 0.0757 | 0.359835 | 3.59835
523696 | Niveau 1 | 3.01021 | 2.11958 | 0.211916 | 0.63804 | 6.3804
523812 | Niveau 1 | 3.21021 | 4.42797 | 0.182803 | 1.42147 | 14.2147
526922 | Niveau 1 | 3.01021 | 4.24182 | 0.407182 | 1.27688 | 12.7688
527357 | Niveau 1 | 3.01321 | 0.631575 | 0.0631575 | 0.190307 | 1.90307
527378 | Niveau 1 | 3.01021 | 1.027 | 0.1027 | 0.309149 | 3.09149
528033 | Niveau 1 | 3.01021 | 4.55401 | 0.455401 | 1.37086 | 13.7086
528080 | Niveau 1 | 3.01021 | 4.42601 | 0.442601 | 1.33233 | 13.3233
528100 | Niveau 1 | 3.01021 | 0.276 | 0.0276 | 0.0830819 | 0.830819
529186 | Niveau 1 | 3.01021 | 7.08899 | 0.708899 | 2.13394 | 21.3394
529200 | Niveau 1 | 3.01021 | 1.01871 | 0.101871 | 0.306654 | 3.06654
531175 | Niveau 1 | 3.01021 | 0.393 | 0.0393 | 0.118301 | 1.18301
531420 | Niveau 1 | 3.01021 | 4.50042 | 0.450042 | 1.35472 | 13.5472
542681 | Niveau 1 | 3.04521 | 2.75011 | 0.275011 | 0.837468 | 8.37468
543023 | Niveau 1 | 3.01021 | 1.36034 | 0.136034 | 0.409492 | 4.09492
543545 | Niveau 1 | 3.01021 | 2.36519 | 0.236519 | 0.711974 | 7.11974
546712 | Niveau 1 | 3.01021 | 2.67216 | 0.267216 | 0.804379 | 8.04379
549323 | Niveau 1 | 3.01021 | 1.62783 | 0.162741 | 0.490013 | 4.90013
549468 | Niveau 1 | 3.01021 | 1.59101 |  | 0.478929 | 4.78929
549729 | Niveau 1 | 3.01021 | 5.69134 | 0.569134 | 1.71322 | 17.1322
549848 | Niveau 1 | 3.01021 | 0.23987 | 0.023987 | 0.072206 | 0.72206
550272 | Niveau 1 | 3.01321 | 3.34084 | 0.334084 | 1.00667 | 10.0667
550300 | Niveau 1 | 3.01021 | 2.11939 | 0.211939 | 0.637982 | 6.37982
581347 | Niveau 2 | 2.822 | 2.67598 |  | 0.755161 | 7.55161
609094 | SS2 | 0.763406 | 1.317 | 0.1317 | 0.100541 | 1.00541
626732 | Niveau 1 | 0.829515 | 1.53365 | 0.153365 | 0.127218 | 1.27218

# IfcWall: Mur de base:Générique - Int. 115 mm, Mur de base:Générique - Int. 115 mm:287103
In: Niveau 0
Type - Material: Mur par défaut 0.115 m
Type - Pset_EnvironmentalImpactIndicators - Reference: Générique - Int. 115 mm
Type - Pset_ReinforcementBarPitchOfWall - Reference: Générique - Int. 115 mm
Type - Pset_WallCommon - IsExternal: no; Reference: Générique - Int. 115 mm
Qto_WallBaseQuantities - Height: 3.44153 m; Length: 2.77162 m; Width: 0.115 m; GrossFootprintArea: 0.317592 m2; NetVolume: 1.09694 m3; NetSideArea: 9.5386 m2
Pset_EnvironmentalImpactIndicators - sets with these values: 2
Pset_WallCommon - LoadBearing: no; ExtendToStructure: no

# IfcWall: Mur de base:Générique - Int. 130 mm (15)
Type - Material: Mur par défaut 0.13 m
Type - Pset_EnvironmentalImpactIndicators - Reference: Générique - Int. 130 mm
Type - Pset_ReinforcementBarPitchOfWall - Reference: Générique - Int. 130 mm
Type - Pset_WallCommon - IsExternal: no; Reference: Générique - Int. 130 mm
Qto_WallBaseQuantities - Width: 0.13 m
Pset_EnvironmentalImpactIndicators - sets with these values: 2
Pset_WallCommon - LoadBearing: no; ExtendToStructure: no
Name (Mur de base:Générique - Int. 130 mm:...) | In | Height (m) | Length (m) | GrossFootprintArea (m2) | NetVolume (m3) | NetSideArea (m2)
287607 | Niveau 0 | 3.14471 | 4.53967 | 0.590157 | 1.85587 | 14.2759
287933 | Niveau 0 | 3.44153 | 0.930149 | 0.120919 | 0.416147 | 3.20113
296611 | Niveau 0 | 3.40653 | 2.74508 | 0.34841 | 1.21565 | 9.35118
299928 | Niveau 0 | 3.41113 | 0.471597 | 0.0613076 | 0.209128 | 1.60868
437117 | SS3 | 2.894 | 2.20536 |  | 0.829702 | 6.38232
470375 | SS1 | 2.53344 | 17.1539 | 2.23001 | 5.64959 | 43.4584
496119 | SS1 | 2.43344 | 4.48922 | 0.583599 | 1.42015 | 10.9242
521318 | Niveau 1 | 2.86504 | 4.20967 | 0.547257 | 1.56791 | 12.0609
525951 | Niveau 1 | 3.01021 | 5.73131 | 0.74507 | 2.24282 | 17.2525
527953 | Niveau 1 | 3.01021 | 5.52131 | 0.71777 | 2.16064 | 16.6203
542770 | Niveau 1 | 3.01021 | 7.95758 | 1.03449 | 3.11402 | 23.954
542790 | Niveau 1 | 3.01021 | 2.30011 | 0.299015 | 0.900098 | 6.92383
548371 | Niveau 1 | 3.01021 | 6.96979 | 0.906072 | 2.72747 | 20.9805
549609 | Niveau 1 | 3.01021 | 3.70525 | 0.481682 | 1.44997 | 11.1536
559154 | Niveau 2 | 3.4719 | 4.17967 | 0.543357 | 1.88648 | 14.5114

# IfcWall: Mur de base:Générique - Int. 150 mm (61)
Type - Material: Mur par défaut 0.15 m
Type - Pset_EnvironmentalImpactIndicators - Reference: Générique - Int. 150 mm
Type - Pset_ReinforcementBarPitchOfWall - Reference: Générique - Int. 150 mm
Type - Pset_WallCommon - IsExternal: no; Reference: Générique - Int. 150 mm
Qto_WallBaseQuantities - Width: 0.15 m
Pset_EnvironmentalImpactIndicators - sets with these values: 2
Pset_WallCommon - LoadBearing: no
Name (Mur de base:Générique - Int. 150 mm:...) | In | Height (m) | Length (m) | NetVolume (m3) | NetSideArea (m2) | ExtendToStructure | GrossFootprintArea (m2)
293835 | Niveau 0 | 3.40653 | 1.49188 | 0.762321 | 5.08214 | no
354039 | Niveau 0 | 0.166621 | 6.779 | 0.169429 | 1.12953 | no | 1.01685
354071 | Niveau 0 | 0.739058 | 2.0743 | 0.229955 | 1.53303 | no | 0.311146
374407 | Niveau 0 | 3.0041 | 3.93135 | 1.77153 | 11.8102 | no | 0.589702
417319 | SS2 | 3.74003 | 5.99036 | 3.36062 | 22.4041 | no | 0.898554
417336 | SS3 | 4.75344 | 1.50301 | 1.07167 | 7.14446 | no | 0.225451
417363 | SS3 | 4.75344 | 8.01336 | 5.71365 | 38.091 | no | 1.202
419986 | SS3 | 4.75344 | 7.01 | 4.99824 | 33.3216 | no | 1.0515
420009 | SS3 | 4.75344 | 1.542 | 1.09947 | 7.3298 | no | 0.2313
420024 | SS3 | 2.15 | 0.508 | 0.16383 | 1.0922 | no | 0.0762
420037 | SS3 | 2.15 | 0.512 | 0.16512 | 1.1008 | no | 0.0768
420066 | SS3 | 4.75344 | 2.18617 | 1.55877 | 10.3918 | no | 0.327926
420139 | SS3 | 2.15 | 0.735927 | 0.237337 | 1.58224 | no | 0.110389
420171 | SS3 | 4.75344 | 1.38145 | 0.984995 | 6.56663 | no | 0.207217
420199 | SS3 | 4.75344 | 2.29567 | 1.63685 | 10.9123 | no | 0.34435
420924 | SS3 | 5.18344 | 1.49693 | 1.16389 | 7.75926 | no | 0.22454
421214 | SS3 | 4.75344 | 1.086 | 0.774335 | 5.16223 | no | 0.136919
421273 | SS3 | 4.75344 | 0.257299 | 0.183458 | 1.22306 | no | 0.0385949
422586 | SS3 | 2.15 | 1.29352 | 0.417159 | 2.78106 | no | 0.194028
423369 | SS3 | 0.503189 | 0.859 | 0.0648359 | 0.432239 | no | 0.12885
424317 | SS3 | 2.58 | 2.01741 | 0.780739 | 5.20493 | no | 0.302612
425912 | SS3 | 2.995 | 6.09831 | 2.73967 | 18.2644 | no
425987 | SS3 | 2.795 | 2.446 | 1.02549 | 6.83657 | no | 0.3669
426003 | SS3 | 2.96399 | 1.89211 | 0.841231 | 5.6082 | no | 0.283817
432641 | SS3 | 2.89399 | 4.45248 | 1.93281 | 12.8854 | no | 0.667872
432759 | SS2 | 0.763406 | 0.445423 | 0.0510058 | 0.340039 | no | 0.0668135
432763 | SS2 | 0.763406 | 1.396 | 0.159857 | 1.06571 | no | 0.2094
436409 | SS3 | 2.5 | 3.75 | 1.40625 | 9.375 | no
436741 | SS3 | 2.675 | 4.18535 | 1.67937 | 11.1958 | no | 0.627802
438018 | SS3 | 2.46399 | 2.92021 | 1.07931 | 7.19538 | no | 0.438032
438700 | SS3 | 2.795 | 1.012 | 0.424281 | 2.82854 | no | 0.1518
438739 | SS3 | 2.795 | 0.727 | 0.304795 | 2.03196 | no | 0.10905
438777 | SS3 | 2.499 | 1.23666 | 0.463564 | 3.09042 | no | 0.1855
439052 | SS3 | 2.49 | 4.01299 | 1.49885 | 9.99235 | no | 0.601949
440551 | SS3 | 3.11399 | 9.95912 | 4.65189 | 31.0126 | no | 1.49387
440639 | SS3 | 1.14455 | 1.50233 | 0.257925 | 1.7195 | no | 0.225349
440930 | SS3 | 1.94 | 0.156 | 0.045396 | 0.30264 | no | 0.0234
441135 | SS3 | 1.94 | 0.582 | 0.169362 | 1.12908 | no | 0.0873
441271 | SS3 | 2.38399 | 1.47314 | 0.526794 | 3.51196 | no | 0.220971
441985 | SS3 | 2.38399 | 1.98714 | 0.710599 | 4.73733 | no | 0.298071
443458 | SS3 | 4.00184 | 1.91647 | 1.15041 | 7.66939 | no | 0.28747
459240 | SS3 | 4.75344 | 1.29424 | 0.922816 | 6.15211 | no | 0.194137
469397 | SS3 | 2.15 | 0.581783 | 0.187625 | 1.25083 | no | 0.0872674
470510 | SS3 | 2.82054 | 1.82952 | 0.774035 | 5.16023 | no | 0.263178
489757 | SS1 | 2.11951 | 2.08462 | 0.662757 | 4.41838 | no | 0.312694
489779 | SS1 | 2.11945 | 1.18588 | 0.37701 | 2.5134 | no | 0.177881
491792 | Niveau 0 | 3.66113 | 1.68469 | 0.925177 | 6.16785 | no | 0.0309779
542559 | Niveau 1 | 3.69821 | 1.55084 | 0.860299 | 5.73533 | no | 0.210125
543692 | Niveau 1 | 3.01021 | 3.31938 | 1.49881 | 9.99204 | no | 0.497907
543735 | Niveau 1 | 3.01021 | 1.277 | 0.576607 | 3.84404 | no | 0.19155
543764 | Niveau 1 | 3.04521 | 1.38685 | 0.633486 | 4.22324 | no | 0.208027
550415 | Niveau 1 | 3.01321 | 0.433714 | 0.196031 | 1.30687 | no | 0.0650571
556102 | Niveau 1 | 3.01021 | 2.65629 | 1.1994 | 7.99602 | no | 0.398444
559117 | Niveau 2 | 2.088 | 4.19171 | 1.31284 | 8.75229 | no | 0.628757
560189 | Niveau 2 | 2.992 | 1.84 | 0.825792 | 5.50528 | yes | 0.276
580951 | Niveau 2 | 2.7999 | 1.447 | 0.607718 | 4.05146 | no | 0.21705
581039 | Niveau 2 | 2.7999 | 2.91284 | 1.22335 | 8.15565 | no | 0.436925
581174 | Niveau 2 | 2.7999 | 0.760293 | 0.319312 | 2.12874 | no | 0.114044
608798 | SS1 | 0.179854 | 3.76505 | 0.101574 | 0.67716 | no | 0.564758
610728 | SS3 | 4.75344 | 1.27179 | 0.906808 | 6.04539 | no | 0.190769
617595 | SS3 | 0.363406 | 1.97552 | 0.107687 | 0.717915 | no | 0.296328

# IfcWall: Mur de base:Générique - Int. 250 mm (3)
Type - Material: Mur par défaut 0.25 m
Type - Pset_EnvironmentalImpactIndicators - Reference: Générique - Int. 250 mm
Type - Pset_ReinforcementBarPitchOfWall - Reference: Générique - Int. 250 mm
Type - Pset_WallCommon - IsExternal: no; Reference: Générique - Int. 250 mm
Qto_WallBaseQuantities - Width: 0.25 m
Pset_EnvironmentalImpactIndicators - sets with these values: 2
Pset_WallCommon - LoadBearing: no; ExtendToStructure: no
Name (Mur de base:Générique - Int. 250 mm:...) | In | Height (m) | Length (m) | GrossFootprintArea (m2) | NetVolume (m3) | NetSideArea (m2)
403375 | Demi-niveau | 1.37925 | 2.7508 | 0.687701 | 0.948509 | 3.79404
420532 | SS3 | 5.18344 | 1.35432 |  | 1.75501 | 7.02002
524470 | Niveau 1 | 3.24821 | 16.0875 | 4.02189 | 13.064 | 52.2558

# IfcWall: Mur de base:Générique - Int. 270 mm, Mur de base:Générique - Int. 270 mm:422432
In: SS3
Type - Material: Mur par défaut 0.27 m
Type - Pset_EnvironmentalImpactIndicators - Reference: Générique - Int. 270 mm
Type - Pset_ReinforcementBarPitchOfWall - Reference: Générique - Int. 270 mm
Type - Pset_WallCommon - IsExternal: no; Reference: Générique - Int. 270 mm
Qto_WallBaseQuantities - Height: 2.15 m; Length: 0.632 m; Width: 0.27 m; GrossFootprintArea: 0.165238 m2; NetVolume: 0.366876 m3; NetSideArea: 1.3588 m2
Pset_EnvironmentalImpactIndicators - sets with these values: 2
Pset_WallCommon - LoadBearing: no; ExtendToStructure: no

# IfcWall: Mur de base:Générique - Int. 280mm (3)
Type - Material: Mur par défaut 0.28 m
Type - Pset_EnvironmentalImpactIndicators - Reference: Générique - Int. 280mm
Type - Pset_ReinforcementBarPitchOfWall - Reference: Générique - Int. 280mm
Type - Pset_WallCommon - IsExternal: no; Reference: Générique - Int. 280mm
Qto_WallBaseQuantities - Width: 0.28 m
Pset_EnvironmentalImpactIndicators - sets with these values: 2
Pset_WallCommon - LoadBearing: no; ExtendToStructure: no
Name (Mur de base:Générique - Int. 280mm:...) | In | Height (m) | Length (m) | NetVolume (m3) | NetSideArea (m2)
434794 | SS3 | 0.807483 | 3.90035 | 0.88185 | 3.14947
437546 | SS3 | 3.19 | 7.94461 | 7.09612 | 25.3433
493031 | SS1 | 2.11945 | 4.274 | 2.53638 | 9.05851 | Qto_WallBaseQuantities - GrossFootprintArea: 1.19672 m2

# IfcWall: Mur de base:Générique - Int. 300 mm (8)
Type - Material: Mur par défaut 0.3 m
Type - Pset_EnvironmentalImpactIndicators - Reference: Générique - Int. 300 mm
Type - Pset_ReinforcementBarPitchOfWall - Reference: Générique - Int. 300 mm
Type - Pset_WallCommon - IsExternal: no; Reference: Générique - Int. 300 mm
Qto_WallBaseQuantities - Width: 0.3 m
Pset_EnvironmentalImpactIndicators - sets with these values: 2
Pset_WallCommon - LoadBearing: no; ExtendToStructure: no
Name (Mur de base:Générique - Int. 300 mm:...) | In | Height (m) | Length (m) | GrossFootprintArea (m2) | NetVolume (m3) | NetSideArea (m2)
296892 | Niveau 0 | 3.41113 | 0.648724 | 0.177933 | 0.663864 | 2.21288
301415 | Niveau 0 | 3.40653 | 5.31467 | 1.5944 | 5.43137 | 18.1046
304151 | Niveau 0 | 3.41113 | 0.550575 | 0.165173 | 0.563424 | 1.87808
424333 | SS3 | 2.58 | 0.574215 | 0.172265 | 0.444443 | 1.48148
445899 | SS3 | 4.75344 | 9.26083 | 2.77825 | 13.2062 | 44.0208
527695 | Niveau 1 | 3.01021 | 0.25 | 0.075 | 0.225766 | 0.752554
550144 | Niveau 1 | 3.01021 | 0.727429 | 0.218229 | 0.656915 | 2.18972
550446 | Niveau 1 | 3.01021 | 0.27 | 0.081 | 0.243827 | 0.812758

# IfcWall: Mur de base:Générique - Int. 360 (3)
Type - Material: Mur par défaut 0.36 m
Type - Pset_EnvironmentalImpactIndicators - Reference: Générique - Int. 360
Type - Pset_ReinforcementBarPitchOfWall - Reference: Générique - Int. 360
Type - Pset_WallCommon - IsExternal: no; Reference: Générique - Int. 360
Qto_WallBaseQuantities - Width: 0.36 m
Pset_EnvironmentalImpactIndicators - sets with these values: 2
Pset_WallCommon - LoadBearing: no; ExtendToStructure: no
Name (Mur de base:Générique - Int. 360:...) | In | Height (m) | Length (m) | GrossFootprintArea (m2) | NetVolume (m3) | NetSideArea (m2)
299546 | Demi-niveau | 5.0581 | 1.92002 | 0.68996 | 3.4962 | 9.71166
443555 | SS3 | 3.83184 | 1.74001 | 0.625157 | 2.40028 | 6.66744
569601 | Niveau 2 | 0.729 | 6.81525 | 2.45349 | 1.78859 | 4.96832

# IfcWall: Mur de base:Générique - Int. 480 mm (3)
Type - Material: Mur par défaut 0.48 m
Type - Pset_EnvironmentalImpactIndicators - Reference: Générique - Int. 480 mm
Type - Pset_ReinforcementBarPitchOfWall - Reference: Générique - Int. 480 mm
Type - Pset_WallCommon - IsExternal: no; Reference: Générique - Int. 480 mm
Qto_WallBaseQuantities - Width: 0.48 m
Pset_EnvironmentalImpactIndicators - sets with these values: 2
Pset_WallCommon - LoadBearing: no; ExtendToStructure: no
Name (Mur de base:Générique - Int. 480 mm:...) | In | Height (m) | Length (m) | GrossFootprintArea (m2) | NetVolume (m3) | NetSideArea (m2)
296772 | Niveau 0 | 3.44153 | 4.75877 | 2.28421 | 7.86116 | 16.3774
424109 | SS3 | 3.17848 | 8.66279 |  | 13.2165 | 27.5345
479177 | SS1 | 1.63501 | 4.50703 | 2.16337 | 3.53714 | 7.36903

# IfcWall: Mur de base:Générique - Int. 50, Mur de base:Générique - Int. 50:547069
In: Niveau 1
Type - Material: Mur par défaut 0.05 m
Type - Pset_EnvironmentalImpactIndicators - Reference: Générique - Int. 50
Type - Pset_ReinforcementBarPitchOfWall - Reference: Générique - Int. 50
Type - Pset_WallCommon - IsExternal: no; Reference: Générique - Int. 50
Qto_WallBaseQuantities - Height: 0.405138 m; Length: 1.27556 m; Width: 0.05 m; GrossFootprintArea: 0.0637779 m2; NetVolume: 0.0258388 m3; NetSideArea: 0.516777 m2
Pset_EnvironmentalImpactIndicators - sets with these values: 2
Pset_WallCommon - LoadBearing: no; ExtendToStructure: no

# IfcWall: Mur de base:Générique - Int. 560 mm, Mur de base:Générique - Int. 560 mm:480579
In: SS1
Type - Material: Mur par défaut 0.56 m
Type - Pset_EnvironmentalImpactIndicators - Reference: Générique - Int. 560 mm
Type - Pset_ReinforcementBarPitchOfWall - Reference: Générique - Int. 560 mm
Type - Pset_WallCommon - IsExternal: no; Reference: Générique - Int. 560 mm
Qto_WallBaseQuantities - Height: 2.32496 m; Length: 4.665 m; Width: 0.56 m; NetVolume: 6.07373 m3; NetSideArea: 10.8459 m2
Pset_EnvironmentalImpactIndicators - sets with these values: 2
Pset_WallCommon - LoadBearing: no; ExtendToStructure: no

# IfcWall: Mur de base:Générique - Int. 650 (2)
In: Niveau 0
Type - Material: Mur par défaut 0.65 m
Type - Pset_EnvironmentalImpactIndicators - Reference: Générique - Int. 650
Type - Pset_ReinforcementBarPitchOfWall - Reference: Générique - Int. 650
Type - Pset_WallCommon - IsExternal: no; Reference: Générique - Int. 650
Qto_WallBaseQuantities - Height: 3.40653 m; Width: 0.65 m
Pset_EnvironmentalImpactIndicators - sets with these values: 2
Pset_WallCommon - LoadBearing: no; ExtendToStructure: no
Name (Mur de base:Générique - Int. 650:...) | Length (m) | GrossFootprintArea (m2) | NetVolume (m3) | NetSideArea (m2)
301504 | 4.77655 | 3.10476 | 10.5764 | 16.2714
303721 | 3.26042 | 2.11928 | 7.21937 | 11.1067

# IfcWall: Mur de base:Générique - Int. 70 mm (52)
Type - Material: Mur par défaut 0.07 m
Type - Pset_EnvironmentalImpactIndicators - Reference: Générique - Int. 70 mm
Type - Pset_ReinforcementBarPitchOfWall - Reference: Générique - Int. 70 mm
Type - Pset_WallCommon - IsExternal: no; Reference: Générique - Int. 70 mm
Qto_WallBaseQuantities - Width: 0.07 m
Pset_EnvironmentalImpactIndicators - sets with these values: 2
Pset_WallCommon - LoadBearing: no
Name (Mur de base:Générique - Int. 70 mm:...) | In | Height (m) | Length (m) | GrossFootprintArea (m2) | NetVolume (m3) | NetSideArea (m2) | ExtendToStructure
269643 | Niveau 0 | 3.42153 | 0.420489 | 0.0294096 | 0.10071 | 1.43871 | no
412951 | SS2 | 2.34113 | 1.18825 | 0.0831776 | 0.19473 | 2.78185 | no
413010 | SS2 | 2.34113 | 2.989 | 0.20923 | 0.489835 | 6.99764 | no
413057 | SS2 | 2.34113 | 3.013 | 0.21091 | 0.493768 | 7.05383 | no
414316 | SS2 | 2.34113 | 2.23817 | 0.156672 | 0.36679 | 5.23986 | no
414738 | SS2 | 3.74003 | 1.78983 | 0.125288 | 0.46858 | 6.694 | yes
415202 | SS2 | 3.74003 | 1.92239 | 0.134567 | 0.503285 | 7.18979 | yes
415258 | SS2 | 2.34113 | 5.03443 | 0.35241 | 0.825038 | 11.7863 | no
415275 | SS2 | 2.34113 | 0.092677 | 0.00648645 | 0.0151878 | 0.216969 | no
453338 | SS3 | 4.93344 | 1.10853 | 0.077597 | 0.38282 | 5.46886 | no
453356 | SS3 | 4.93344 | 0.554366 | 0.0388057 | 0.191445 | 2.73493 | no
453509 | SS3 | 0.329 | 0.354638 | 0.0248246 | 0.00816731 | 0.116676 | no
453618 | SS3 | 0.329 | 0.674 | 0.04718 | 0.0155222 | 0.221746 | no
485296 | SS1 | 2.11945 | 1.44736 | 0.101315 | 0.214732 | 3.0676 | no
487963 | SS1 | 2.21844 | 0.499997 | 0.0349998 | 0.0776448 | 1.10921 | no
487991 | SS1 | 2.21844 | 0.521125 | 0.0364788 | 0.0809258 | 1.15608 | no
488103 | SS1 | 2.21844 | 0.472539 | 0.0330778 | 0.0733809 | 1.0483 | no
489633 | SS1 | 2.11945 | 0.785793 | 0.0501953 | 0.116581 | 1.66545 | no
489679 | SS1 | 2.11945 | 6.89833 | 0.477137 | 1.02344 | 14.6206 | no
489731 | SS1 | 2.11945 | 1.33038 | 0.0881664 | 0.197377 | 2.81967 | no
489998 | SS1 | 2.13944 | 0.303112 | 0.0148767 | 0.0453943 | 0.64849 | no
490052 | SS1 | 2.11945 | 2.7275 | 0.190925 | 0.404655 | 5.78079 | no
491976 | SS1 | 2.11945 | 4.6935 | 0.29938 | 0.696333 | 9.94762 | no
492029 | SS1 | 2.13944 | 4.15073 | 0.290494 | 0.621616 | 8.88023 | no
492114 | SS1 | 2.11945 | 7.48501 | 0.523951 | 1.11048 | 15.8641 | no
492212 | SS1 | 2.11945 | 2.30342 | 0.161239 | 0.341738 | 4.88198 | no
492271 | SS1 | 2.11945 | 2.39762 | 0.167834 | 0.355714 | 5.08163 | no
492486 | SS1 | 2.11945 | 1.612 | 0.11284 | 0.239158 | 3.41655 | no
492504 | SS1 | 2.11945 | 2.13129 | 0.149161 | 0.3162 | 4.51715 | no
492563 | SS1 | 2.21945 | 1.83224 | 0.122802 | 0.284658 | 4.06655 | no
492597 | SS1 | 2.11945 | 1.75692 | 0.119699 | 0.260658 | 3.72369 | no
492644 | SS1 | 1.93098 | 2.81788 |  | 0.380889 | 5.44128 | no
493138 | SS1 | 2.13944 | 0.149987 | 0.0104991 | 0.0224621 | 0.320887 | no
493181 | SS1 | 2.13944 | 0.503404 | 0.0352382 | 0.07539 | 1.077 | no
493786 | SS1 | 2.11945 | 3.413 | 0.23891 | 0.506358 | 7.23368 | no
493800 | SS1 | 2.38945 | 0.266 | 0.01862 | 0.0444915 | 0.635593 | no
493815 | SS1 | 2.11945 | 0.996216 | 0.0697351 | 0.1478 | 2.11143 | no
497283 | SS1 | 1.54861 | 2.09789 | 0.106082 | 0.227418 | 3.24883 | no
532197 | Niveau 1 | 3.01021 | 3.9387 | 0.275709 | 0.829943 | 11.8563 | no
535769 | Niveau 1 | 3.01021 | 4.08848 | 0.286193 | 0.861504 | 12.3072 | no
546864 | Niveau 1 | 3.01021 | 0.244791 | 0.0171354 | 0.0515811 | 0.736873 | no
546891 | Niveau 1 | 3.01021 | 0.484417 | 0.0339092 | 0.102074 | 1.4582 | no
552193 | Niveau 1 | 3.01021 | 3.1564 | 0.220948 | 0.6651 | 9.50143 | no
552364 | Niveau 1 | 3.01021 | 2.908 | 0.20356 | 0.612759 | 8.7537 | no
552384 | Niveau 1 | 3.01021 | 0.707671 | 0.049537 | 0.149117 | 2.13024 | no
552441 | Niveau 1 | 0.643118 | 2.512 | 0.17584 | 0.113086 | 1.61551 | no
569513 | Niveau 2 | 2.957 | 4.13394 | 0.289376 | 0.855685 | 12.2241 | no
575731 | Niveau 2 | 0.729 | 0.743868 | 0.0520708 | 0.0379596 | 0.54228 | no
579520 | Niveau 2 | 2.747 | 3.30288 | 0.231202 | 0.635112 | 9.07302 | no
579636 | Niveau 2 | 2.957 | 3.30288 | 0.231202 | 0.683664 | 9.76663 | no
579764 | Niveau 2 | 2.992 | 3.30288 | 0.231202 | 0.691756 | 9.88223 | no
609710 | SS2 | 3.74003 | 0.069115 | 0.00483736 | 0.0180945 | 0.258492 | yes

# IfcWall: Mur de base:Générique - Int. 70 mm bois (2)
In: Niveau 1
Type - Material: Résineux, bois de construction 0.07 m
Type - Pset_EnvironmentalImpactIndicators - Reference: Générique - Int. 70 mm bois
Type - Pset_ReinforcementBarPitchOfWall - Reference: Générique - Int. 70 mm bois
Type - Pset_WallCommon - IsExternal: no; Reference: Générique - Int. 70 mm bois; ThermalTransmittance: 1.71429 kg/K/s3
Qto_WallBaseQuantities - Length: 1.932 m; Width: 0.07 m; GrossFootprintArea: 0.13524 m2
Pset_EnvironmentalImpactIndicators - sets with these values: 2
Pset_WallCommon - LoadBearing: no; ExtendToStructure: no
Name (Mur de base:Générique - Int. 70 mm bois:...) | Height (m) | NetVolume (m3) | NetSideArea (m2)
527819 | 2.43242 | 0.32896 | 4.69943
556596 | 2.46742 | 0.333693 | 4.76705

# IfcWall: Mur de base:Générique - Int. 80 (38)
Type - Material: Mur par défaut 0.08 m
Type - Pset_EnvironmentalImpactIndicators - Reference: Générique - Int. 80
Type - Pset_ReinforcementBarPitchOfWall - Reference: Générique - Int. 80
Type - Pset_WallCommon - IsExternal: no; Reference: Générique - Int. 80
Qto_WallBaseQuantities - Width: 0.08 m
Pset_EnvironmentalImpactIndicators - sets with these values: 2
Pset_WallCommon - LoadBearing: no
Name (Mur de base:Générique - Int. 80:...) | In | Height (m) | Length (m) | GrossFootprintArea (m2) | NetVolume (m3) | NetSideArea (m2) | ExtendToStructure
358369 | Niveau 0 | 3.44153 | 8.21958 | 0.653156 | 2.26303 | 28.2879 | no
369174 | Niveau 0 | 3.44153 | 8.10933 | 0.648746 | 2.23268 | 27.9085 | no
421837 | SS3 | 4.75344 | 0.542 | 0.04336 | 0.206109 | 2.57636 | no
437674 | SS3 | 3.11399 | 4.40301 | 0.352037 | 1.09687 | 13.7109 | no
454885 | SS3 | 5.44436 | 1.8421 | 0.147368 | 0.802325 | 10.0291 | no
476637 | SS1 | 2.43344 | 3.09033 | 0.247226 | 0.60161 | 7.52012 | no
483675 | SS1 | 2.21844 | 3.62735 | 0.290146 | 0.643764 | 8.04704 | no
483706 | SS1 | 2.43344 | 0.397642 | 0.0318114 | 0.077411 | 0.967638 | no
483844 | SS1 | 2.43344 | 0.573598 | 0.0458878 | 0.111665 | 1.39581 | no
483865 | SS1 | 2.43344 | 0.433763 | 0.0347011 | 0.0844429 | 1.05554 | no
487454 | SS1 | 2.21844 | 1.32109 | 0.105687 | 0.234461 | 2.93076 | no
487492 | SS1 | 2.21844 | 1.32109 | 0.105687 | 0.234461 | 2.93076 | no
489289 | SS1 | 2.11945 | 1.32109 | 0.105687 | 0.223999 | 2.79998 | no
490141 | SS1 | 2.11945 | 1.51 | 0.1208 | 0.256029 | 3.20036 | no
493645 | SS1 | 2.13945 | 7.692 | 0.61536 | 1.31653 | 16.4566 | no
493926 | SS1 | 2.13944 | 0.49 | 0.0392 | 0.0838659 | 1.04832 | no
494024 | SS1 | 2.13944 | 2.40391 | 0.192313 | 0.411441 | 5.14301 | no
521540 | Niveau 1 | 3.21021 | 1.49534 | 0.095574 | 0.38403 | 4.80037 | no
523832 | Niveau 1 | 3.01021 | 8.10407 | 0.648326 | 1.9516 | 24.395 | no
526133 | Niveau 1 | 3.01021 | 3.51829 | 0.281463 | 0.847264 | 10.5908 | no
526612 | Niveau 1 | 3.01021 | 0.986 | 0.07888 | 0.237446 | 2.96807 | no
527006 | Niveau 1 | 3.01021 | 1.88 | 0.1316 | 0.452736 | 5.6592 | no
527033 | Niveau 1 | 3.01321 | 0.777 | 0.06216 | 0.187301 | 2.34127 | no
528545 | Niveau 1 | 3.01021 | 5.73938 | 0.45915 | 1.38214 | 17.2768 | no
529026 | Niveau 1 | 3.01021 | 0.276 | 0.02208 | 0.0664655 | 0.830819 | no
530981 | Niveau 1 | 3.01021 | 1.73126 | 0.138501 | 0.416918 | 5.21147 | no
542593 | Niveau 1 | 3.01021 | 1.68433 | 0.134746 | 0.405615 | 5.07019 | no
550823 | Niveau 1 | 3.01321 | 0.709219 | 0.0567375 | 0.170962 | 2.13703 | no
556192 | Niveau 1 | 3.01021 | 0.707671 | 0.0566137 | 0.170419 | 2.13024 | no
556207 | Niveau 1 | 3.04521 | 0.290732 | 0.0232586 | 0.0708273 | 0.885341 | no
568238 | Niveau 2 | 2.992 | 1.64785 | 0.131828 | 0.394429 | 4.93036 | no
568260 | Niveau 2 | 2.992 | 2.62158 | 0.194353 | 0.627501 | 7.84376 | no
568332 | Niveau 2 | 2.992 | 3.28644 | 0.262915 | 0.786642 | 9.83302 | no
568345 | Niveau 2 | 2.992 | 0.752859 | 0.0602287 | 0.180204 | 2.25255 | no
572304 | Niveau 2 | 2.992 | 1.34076 | 0.107261 | 0.320924 | 4.01155 | no
572784 | Niveau 2 | 2.992 | 0.857507 | 0.0686006 | 0.205253 | 2.56566 | yes
580760 | Niveau 2 | 2.957 | 0.430986 | 0.0344789 | 0.101954 | 1.27443 | yes
590137 | Niveau 2 | 2.422 | 2.09711 | 0.167768 | 0.406335 | 5.07919 | yes

# IfcWall: Mur de base:Générique - Int. 90 (19)
Type - Material: Mur par défaut 0.09 m
Type - Pset_EnvironmentalImpactIndicators - Reference: Générique - Int. 90
Type - Pset_ReinforcementBarPitchOfWall - Reference: Générique - Int. 90
Type - Pset_WallCommon - IsExternal: no; Reference: Générique - Int. 90
Qto_WallBaseQuantities - Width: 0.09 m
Pset_EnvironmentalImpactIndicators - sets with these values: 2
Pset_WallCommon - LoadBearing: no; ExtendToStructure: no
Name (Mur de base:Générique - Int. 90:...) | In | Height (m) | Length (m) | GrossFootprintArea (m2) | NetVolume (m3) | NetSideArea (m2)
287494 | Niveau 0 | 3.40653 | 1.61735 | 0.145562 | 0.49586 | 5.50956
401872 | SS1 | 2.68344 | 6.32091 | 0.568882 | 1.52656 | 16.9618
458542 | SS1 | 2.85221 | 1.29424 | 0.116482 | 0.332231 | 3.69146
459323 | SS1 | 2.85221 | 1.29424 | 0.116482 | 0.332231 | 3.69146
483488 | SS1 | 2.21844 | 4.01397 | 0.361257 | 0.801426 | 8.90473
530655 | Niveau 1 | 3.01021 | 0.257349 | 0.0231614 | 0.0697207 | 0.774675
530723 | Niveau 1 | 3.01021 | 0.253 | 0.02277 | 0.0685426 | 0.761584
530779 | Niveau 1 | 3.01021 | 0.257349 | 0.0231614 | 0.0697207 | 0.774675
531186 | Niveau 1 | 3.01021 | 0.28937 | 0.0260433 | 0.0783959 | 0.871065
531331 | Niveau 1 | 3.01021 | 0.339336 | 0.0305403 | 0.0919328 | 1.02148
531382 | Niveau 1 | 3.01021 | 0.339336 | 0.0305403 | 0.0919328 | 1.02148
531875 | Niveau 1 | 3.01021 | 0.694523 | 0.0625071 | 0.18816 | 2.09066
531989 | Niveau 1 | 3.01021 | 1.03896 | 0.093506 | 0.281473 | 3.12748
532425 | Niveau 1 | 0.313254 | 13.7939 | 1.24145 | 0.388891 | 4.32101
546515 | Niveau 1 | 3.01021 | 1.85955 | 0.167359 | 0.503788 | 5.59764
550862 | Niveau 1 | 3.01321 | 3.75003 | 0.333002 | 1.01697 | 11.2996
567895 | Niveau 2 | 3.087 | 2.99 | 0.2691 | 0.830712 | 9.23013
568079 | Niveau 2 | 2.992 | 3.32888 | 0.2996 | 0.896402 | 9.96002
580657 | Niveau 2 | 2.957 | 5.62311 | 0.50608 | 1.49648 | 16.6275

# IfcWall: Mur de base:Générique - Int.120 (5)
Type - Material: Mur par défaut 0.12 m
Type - Pset_EnvironmentalImpactIndicators - Reference: Générique - Int.120
Type - Pset_ReinforcementBarPitchOfWall - Reference: Générique - Int.120
Type - Pset_WallCommon - IsExternal: no; Reference: Générique - Int.120
Qto_WallBaseQuantities - Width: 0.12 m
Pset_EnvironmentalImpactIndicators - sets with these values: 2
Pset_WallCommon - LoadBearing: no; ExtendToStructure: no
Name (Mur de base:Générique - Int.120:...) | In | Height (m) | Length (m) | NetVolume (m3) | NetSideArea (m2) | GrossFootprintArea (m2)
312358 | Niveau 0 | 3.07853 | 4.41443 | 1.63079 | 13.5899
314682 | Niveau 0 | 2.336 | 8.12341 | 2.27716 | 18.9763 | 0.97481
532020 | Niveau 1 | 3.01021 | 5.54481 | 2.00293 | 16.6911 | 0.665377
548118 | Niveau 1 | 3.01021 | 2.72216 | 0.983316 | 8.1943 | 0.32666
581990 | Niveau 2 | 2.7419 | 1.46584 | 0.482301 | 4.01918 | 0.1759

# IfcWall: Mur de base:Générique - Int.140 (2)
Type - Material: Mur par défaut 0.14 m
Type - Pset_EnvironmentalImpactIndicators - Reference: Générique - Int.140
Type - Pset_ReinforcementBarPitchOfWall - Reference: Générique - Int.140
Type - Pset_WallCommon - IsExternal: no; Reference: Générique - Int.140
Qto_WallBaseQuantities - Width: 0.14 m
Pset_EnvironmentalImpactIndicators - sets with these values: 2
Pset_WallCommon - LoadBearing: no; ExtendToStructure: no
Name (Mur de base:Générique - Int.140:...) | In | Height (m) | Length (m) | GrossFootprintArea (m2) | NetVolume (m3) | NetSideArea (m2)
417391 | SS3 | 2.75 | 3.47222 | 0.480703 | 1.33681 | 9.54861
468942 | SS1 | 2.43344 | 3.76967 | 0.527754 | 1.28426 | 9.17325

# IfcWall: Mur de base:Générique - Int.160 (3)
Type - Material: Mur par défaut 0.16 m
Type - Pset_EnvironmentalImpactIndicators - Reference: Générique - Int.160
Type - Pset_ReinforcementBarPitchOfWall - Reference: Générique - Int.160
Type - Pset_WallCommon - IsExternal: no; Reference: Générique - Int.160
Qto_WallBaseQuantities - Width: 0.16 m
Pset_EnvironmentalImpactIndicators - sets with these values: 2
Pset_WallCommon - LoadBearing: no; ExtendToStructure: no
Name (Mur de base:Générique - Int.160:...) | In | Height (m) | Length (m) | GrossFootprintArea (m2) | NetVolume (m3) | NetSideArea (m2)
286858 | Niveau 0 | 3.40653 | 2.14985 | 0.343977 | 1.17177 | 7.32354
287855 | Niveau 0 | 3.44153 | 2.38232 | 0.381171 | 1.31181 | 8.19881
546621 | Niveau 1 | 3.01021 | 1.24516 | 0.199226 | 0.599714 | 3.74821

# IfcWall: Mur de base:Générique - Int.180 (37)
Type - Material: Mur par défaut 0.18 m
Type - Pset_EnvironmentalImpactIndicators - Reference: Générique - Int.180
Type - Pset_ReinforcementBarPitchOfWall - Reference: Générique - Int.180
Type - Pset_WallCommon - IsExternal: no; Reference: Générique - Int.180
Qto_WallBaseQuantities - Width: 0.18 m
Pset_EnvironmentalImpactIndicators - sets with these values: 2
Pset_WallCommon - LoadBearing: no; ExtendToStructure: no
Name (Mur de base:Générique - Int.180:...) | In | Height (m) | Length (m) | GrossFootprintArea (m2) | NetVolume (m3) | NetSideArea (m2)
286774 | Niveau 0 | 3.40653 | 2.56982 | 0.462567 | 1.57575 | 8.75416
286945 | Niveau 0 | 3.40653 | 1.39685 | 0.251433 | 0.856514 | 4.75841
287532 | Niveau 0 | 3.38653 | 4.22682 | 0.760828 | 2.57656 | 14.3142
297050 | Niveau 0 | 3.40653 | 1.72338 | 0.309896 | 1.05673 | 5.87073
297286 | SS1 | 2.28945 | 4.37222 |  | 1.80179 | 10.01
305953 | Niveau 0 | 3.44153 | 1.75543 | 0.315978 | 1.08745 | 6.04136
305999 | Niveau 0 | 3.44153 | 0.456 | 0.08208 | 0.282481 | 1.56934
345037 | Niveau 0 | 3.42153 | 1.39543 | 0.251178 | 0.859411 | 4.77451
352589 | Niveau 0 | 0.646 | 1.94825 |  | 0.226542 | 1.25857
353781 | Niveau 0 | 3.44153 | 1.99603 | 0.359285 | 1.23649 | 6.86938
401334 | SS1 | 2.82344 | 8.16817 | 1.47027 | 4.15121 | 23.0623
441314 | SS3 | 1.94 | 0.301 | 0.05418 | 0.105109 | 0.58394
451944 | SS3 | 3.41 | 2.13714 | 0.384686 | 1.31178 | 7.28765
490944 | SS1 | 2.11945 | 1.27588 | 0.229658 | 0.486747 | 2.70415
491488 | SS3 | 3.11399 | 3.86666 | 0.695999 | 2.16734 | 12.0408
491625 | SS1 | 3.66113 | 1.77896 | 0.0327361 | 1.17234 | 6.51299
493605 | SS1 | 2.13945 | 0.531311 | 0.095636 | 0.204608 | 1.13671
500696 | Niveau 0 | 3.40653 | 3.73203 | 0.671766 | 2.28839 | 12.7133
521526 | Niveau 1 | 3.21021 | 1.93453 | 0.348215 | 1.11784 | 6.21024
521527 | Niveau 1 | 3.21021 | 1.93453 | 0.348215 | 1.11784 | 6.21024
521647 | Niveau 1 | 3.21021 | 0.276 | 0.04968 | 0.159483 | 0.886019
521735 | Niveau 1 | 3.21021 | 0.636 | 0.11448 | 0.367505 | 2.0417
549959 | Niveau 1 | 3.01021 | 3.11769 | 0.561184 | 1.68928 | 9.38491
550060 | Niveau 1 | 3.01021 | 2.27898 | 0.410061 | 1.23484 | 6.86022
559310 | Niveau 2 | 3.01 | 2.11453 | 0.380615 | 1.14565 | 6.36472
559311 | Niveau 2 | 3.01 | 2.11453 | 0.380615 | 1.14565 | 6.36472
559468 | Niveau 2 | 3.145 | 0.276 | 0.04968 | 0.156244 | 0.86802
559469 | Niveau 2 | 3.01 | 0.276 | 0.04968 | 0.149537 | 0.83076
559754 | Niveau 2 | 3.145 | 2.06047 | 0.370884 | 1.16643 | 6.48017
581235 | Niveau 2 | 2.857 | 4.08898 | 0.736016 | 2.1028 | 11.6822
596579 | Niveau 2 | 1.1404 | 4.63276 | 0.833897 | 0.95098 | 5.28322
596812 | Niveau 2 | 1.1404 | 4.45198 | 0.801356 | 0.91387 | 5.07706
596918 | Niveau 2 | 1.1404 | 1.88087 | 0.338557 | 0.386092 | 2.14496
596960 | Niveau 2 | 1.1404 | 4.71796 | 0.849233 | 0.96847 | 5.38039
598041 | Niveau 2 | 1.0454 | 8.93911 | 1.60904 | 1.6821 | 9.34499
598143 | Niveau 2 | 1.0454 | 10.771 | 1.93878 | 2.02681 | 11.26
598161 | Niveau 2 | 1.0454 | 11.217 | 2.01906 | 2.11073 | 11.7263

# IfcWall: Mur de base:Générique - Int.200 (10)
Type - Material: Mur par défaut 0.2 m
Type - Pset_EnvironmentalImpactIndicators - Reference: Générique - Int.200
Type - Pset_ReinforcementBarPitchOfWall - Reference: Générique - Int.200
Type - Pset_WallCommon - IsExternal: no; Reference: Générique - Int.200
Qto_WallBaseQuantities - Width: 0.2 m
Pset_EnvironmentalImpactIndicators - sets with these values: 2
Pset_WallCommon - LoadBearing: no; ExtendToStructure: no
Name (Mur de base:Générique - Int.200:...) | In | Height (m) | Length (m) | GrossFootprintArea (m2) | NetVolume (m3) | NetSideArea (m2)
431973 | SS3 | 0.285 | 4.14035 | 0.82807 | 0.236 | 1.18
441432 | SS3 | 2.38 | 0.324 | 0.0648 | 0.154224 | 0.77112
444674 | SS3 | 3.11399 | 1.53703 | 0.305078 | 0.957259 | 4.78629
445123 | SS3 | 4.93728 | 0.833583 | 0.166717 | 0.823127 | 4.11563
445600 | SS3 | 2.5285 | 4.94619 | 0.568599 | 2.50129 | 12.5064
446089 | SS3 | 5.69436 | 5.99205 |  | 6.82418 | 34.1209
449061 | SS3 | 2.46399 | 6.12531 |  | 3.01854 | 15.0927
449342 | SS3 | 3.12 | 3.6137 | 0.683847 | 2.25495 | 11.2748
449450 | SS3 | 5.69436 | 3.32237 | 0.664474 | 3.78375 | 18.9188
490913 | SS1 | 2.28344 | 1.82647 | 0.365293 | 0.834124 | 4.17062

# IfcWall: Mur de base:Générique - Int.220, Mur de base:Générique - Int.220:453239
In: SS3
Type - Material: Mur par défaut 0.22 m
Type - Pset_EnvironmentalImpactIndicators - Reference: Générique - Int.220
Type - Pset_ReinforcementBarPitchOfWall - Reference: Générique - Int.220
Type - Pset_WallCommon - IsExternal: no; Reference: Générique - Int.220
Qto_WallBaseQuantities - Height: 5.69436 m; Length: 10.2944 m; Width: 0.22 m; GrossFootprintArea: 2.26477 m2; NetVolume: 12.8964 m3; NetSideArea: 58.6201 m2
Pset_EnvironmentalImpactIndicators - sets with these values: 2
Pset_WallCommon - LoadBearing: no; ExtendToStructure: no

# IfcWall: Mur de base:Générique - Int.230 (5)
Type - Material: Mur par défaut 0.23 m
Type - Pset_EnvironmentalImpactIndicators - Reference: Générique - Int.230
Type - Pset_ReinforcementBarPitchOfWall - Reference: Générique - Int.230
Type - Pset_WallCommon - IsExternal: no; Reference: Générique - Int.230
Qto_WallBaseQuantities - Width: 0.23 m
Pset_EnvironmentalImpactIndicators - sets with these values: 2
Pset_WallCommon - LoadBearing: no
Name (Mur de base:Générique - Int.230:...) | In | Height (m) | Length (m) | GrossFootprintArea (m2) | NetVolume (m3) | NetSideArea (m2) | ExtendToStructure
423739 | SS3 | 2.9484 | 3.51561 | 0.808591 | 2.38405 | 10.3654 | no
433368 | Demi-niveau | 1.63969 | 2.65548 | 0.610761 | 1.00146 | 4.35416 | no
434864 | Niveau 0 | 0.637427 | 3.96135 | 0.91111 | 0.580766 | 2.52507 | no
445572 | SS1 | 2.32494 | 4.57639 | 1.05257 | 2.44716 | 10.6398 | no
559720 | Niveau 2 | 3.145 | 1.95198 | 0.448955 | 1.41196 | 6.13897 | yes

# IfcWall: Mur de base:Générique - Int.330 mm, Mur de base:Générique - Int.330 mm:560600
In: Niveau 2
Type - Material: Mur par défaut 0.33 m
Type - Pset_EnvironmentalImpactIndicators - Reference: Générique - Int.330 mm
Type - Pset_ReinforcementBarPitchOfWall - Reference: Générique - Int.330 mm
Type - Pset_WallCommon - IsExternal: no; Reference: Générique - Int.330 mm
Qto_WallBaseQuantities - Height: 2.957 m; Length: 3.31446 m; Width: 0.33 m; GrossFootprintArea: 1.04571 m2; NetVolume: 3.23429 m3; NetSideArea: 9.80087 m2
Pset_EnvironmentalImpactIndicators - sets with these values: 2
Pset_WallCommon - LoadBearing: no; ExtendToStructure: no

# IfcWall: Mur de base:Générique - Int.350 (3)
Type - Material: Mur par défaut 0.35 m
Type - Pset_EnvironmentalImpactIndicators - Reference: Générique - Int.350
Type - Pset_ReinforcementBarPitchOfWall - Reference: Générique - Int.350
Type - Pset_WallCommon - IsExternal: no; Reference: Générique - Int.350
Qto_WallBaseQuantities - Width: 0.35 m
Pset_EnvironmentalImpactIndicators - sets with these values: 2
Pset_WallCommon - LoadBearing: no; ExtendToStructure: no
Name (Mur de base:Générique - Int.350:...) | In | Height (m) | Length (m) | GrossFootprintArea (m2) | NetVolume (m3) | NetSideArea (m2)
255816 | Niveau 0 | 3.62153 | 3.86407 | 1.2998 | 4.89784 | 13.9938
523632 | Niveau 1 | 3.01021 | 2.1614 | 0.755973 | 2.2772 | 6.50628
525097 | Niveau 1 | 3.24521 | 0.933177 | 0.160357 | 1.05993 | 3.02836

# IfcWall: Mur de base:Générique - Int.380, Mur de base:Générique - Int.380:255699
In: Niveau 0
Type - Material: Mur par défaut 0.38 m
Type - Pset_EnvironmentalImpactIndicators - Reference: Générique - Int.380
Type - Pset_ReinforcementBarPitchOfWall - Reference: Générique - Int.380
Type - Pset_WallCommon - Reference: Générique - Int.380; IsExternal: no
Qto_WallBaseQuantities - Height: 3.40653 m; Length: 15.6804 m; Width: 0.38 m; GrossFootprintArea: 5.95854 m2; NetVolume: 20.2979 m3; NetSideArea: 53.4156 m2
Pset_EnvironmentalImpactIndicators - sets with these values: 2
Pset_WallCommon - LoadBearing: no; ExtendToStructure: no

# IfcWall: Mur de base:Générique - Int.400 (4)
Type - Material: Mur par défaut 0.4 m
Type - Pset_EnvironmentalImpactIndicators - Reference: Générique - Int.400
Type - Pset_ReinforcementBarPitchOfWall - Reference: Générique - Int.400
Type - Pset_WallCommon - IsExternal: no; Reference: Générique - Int.400
Qto_WallBaseQuantities - Width: 0.4 m
Pset_EnvironmentalImpactIndicators - sets with these values: 2
Pset_WallCommon - LoadBearing: no
Name (Mur de base:Générique - Int.400:...) | In | Height (m) | Length (m) | GrossFootprintArea (m2) | NetVolume (m3) | NetSideArea (m2) | ExtendToStructure
524782 | Niveau 1 | 3.24521 | 1.43702 | 0.574807 | 1.86537 | 4.66343 | no
524962 | Niveau 1 | 3.24521 | 1.06687 | 0.426749 | 1.38489 | 3.46223 | no
527638 | Niveau 1 | 3.01021 | 0.687031 | 0.274812 | 0.827244 | 2.06811 | no
559772 | Niveau 2 | 3.145 | 1.7344 | 0.692219 | 2.18187 | 5.45468 | yes

# IfcWall: Mur de base:Générique - Int.420 (2)
In: Niveau 1
Type - Material: Mur par défaut 0.42 m
Type - Pset_EnvironmentalImpactIndicators - Reference: Générique - Int.420
Type - Pset_ReinforcementBarPitchOfWall - Reference: Générique - Int.420
Type - Pset_WallCommon - IsExternal: no; Reference: Générique - Int.420
Qto_WallBaseQuantities - Width: 0.42 m
Pset_EnvironmentalImpactIndicators - sets with these values: 2
Pset_WallCommon - LoadBearing: no; ExtendToStructure: no
Name (Mur de base:Générique - Int.420:...) | Height (m) | Length (m) | NetVolume (m3) | NetSideArea (m2)
523545 | 3.21021 | 3.732 | 5.03182 | 11.9805 | Qto_WallBaseQuantities - GrossFootprintArea: 1.56744 m2
526078 | 3.01021 | 5.8149 | 7.35172 | 17.5041

# IfcWall: Mur de base:Générique - Int.440, Mur de base:Générique - Int.440:420778
In: SS3
Type - Material: Mur par défaut 0.44 m
Type - Pset_EnvironmentalImpactIndicators - Reference: Générique - Int.440
Type - Pset_ReinforcementBarPitchOfWall - Reference: Générique - Int.440
Type - Pset_WallCommon - IsExternal: no; Reference: Générique - Int.440
Qto_WallBaseQuantities - Height: 5.45344 m; Length: 3.8137 m; Width: 0.44 m; GrossFootprintArea: 1.67803 m2; NetVolume: 9.15102 m3; NetSideArea: 20.7978 m2
Pset_EnvironmentalImpactIndicators - sets with these values: 2
Pset_WallCommon - LoadBearing: no; ExtendToStructure: no

# IfcWall: Mur de base:Générique - Int.50 (13)
Type - Material: Mur par défaut 0.05 m
Type - Pset_EnvironmentalImpactIndicators - Reference: Générique - Int.50
Type - Pset_ReinforcementBarPitchOfWall - Reference: Générique - Int.50
Type - Pset_WallCommon - IsExternal: no; Reference: Générique - Int.50
Qto_WallBaseQuantities - Width: 0.05 m
Pset_EnvironmentalImpactIndicators - sets with these values: 2
Pset_WallCommon - LoadBearing: no
Name (Mur de base:Générique - Int.50:...) | In | Height (m) | Length (m) | GrossFootprintArea (m2) | NetVolume (m3) | NetSideArea (m2) | ExtendToStructure
268664 | Niveau 0 | 3.41113 | 0.203735 | 0.0101867 | 0.0347483 | 0.694965 | no
268687 | Niveau 0 | 3.40653 | 0.803977 | 0.0401988 | 0.136938 | 2.73877 | no
297109 | Niveau 0 | 3.41113 | 0.150858 | 0.00753088 | 0.0257298 | 0.514597 | no
297131 | Niveau 0 | 3.41113 | 0.726 | 0.0363 | 0.123824 | 2.47648 | no
300566 | Niveau 0 | 2.20792 | 0.458477 | 0.0204049 | 0.0506139 | 1.01228 | no
300868 | Niveau 0 | 2.20792 | 0.46024 | 0.0228734 | 0.0508085 | 1.01617 | no
301564 | Niveau 0 | 2.20792 | 0.452 | 0.0224686 | 0.0498989 | 0.997978 | no
500593 | Niveau 0 | 2.20792 | 0.460585 | 0.0230293 | 0.0508467 | 1.01693 | no
528187 | Niveau 1 | 3.01021 | 0.644711 | 0.0322355 | 0.0970359 | 1.94072 | no
529001 | Niveau 1 | 3.01021 | 0.990965 | 0.0495482 | 0.149151 | 2.98302 | no
530905 | Niveau 1 | 3.01021 | 1.03896 | 0.0519478 | 0.156374 | 3.12748 | no
579148 | Niveau 2 | 2.992 | 8.09112 | 0.403575 | 1.21043 | 24.2086 | no
589584 | Niveau 2 | 3.087 | 8.5374 | 0.42687 | 1.31775 | 26.3549 | yes

# IfcWall: Mur de base:Générique - Int.500 (4)
Type - Material: Mur par défaut 0.5 m
Type - Pset_EnvironmentalImpactIndicators - Reference: Générique - Int.500
Type - Pset_ReinforcementBarPitchOfWall - Reference: Générique - Int.500
Type - Pset_WallCommon - IsExternal: no; Reference: Générique - Int.500
Qto_WallBaseQuantities - Width: 0.5 m
Pset_EnvironmentalImpactIndicators - sets with these values: 2
Pset_WallCommon - LoadBearing: no; ExtendToStructure: no
Name (Mur de base:Générique - Int.500:...) | In | Height (m) | Length (m) | GrossFootprintArea (m2) | NetVolume (m3) | NetSideArea (m2)
421952 | SS3 | 4.75344 | 0.338 | 0.1565 | 0.803331 | 1.60666
421953 | SS3 | 4.75344 | 0.662793 | 0.331397 | 1.57527 | 3.15055
525078 | Niveau 1 | 3.24521 | 1.028 | 0.514 | 1.66804 | 3.33608
550551 | Niveau 1 | 3.01021 | 1.73536 | 0.865274 | 2.6119 | 5.2238

# IfcWall: Mur de base:Générique - Int.530 (5)
Type - Material: Mur par défaut 0.53 m
Type - Pset_EnvironmentalImpactIndicators - Reference: Générique - Int.530
Type - Pset_ReinforcementBarPitchOfWall - Reference: Générique - Int.530
Type - Pset_WallCommon - IsExternal: no; Reference: Générique - Int.530
Qto_WallBaseQuantities - Width: 0.53 m
Pset_EnvironmentalImpactIndicators - sets with these values: 2
Pset_WallCommon - LoadBearing: no; ExtendToStructure: no
Name (Mur de base:Générique - Int.530:...) | In | Height (m) | Length (m) | GrossFootprintArea (m2) | NetVolume (m3) | NetSideArea (m2)
299899 | Niveau 0 | 3.65653 | 0.92887 | 0.0668786 | 1.80011 | 3.39644
353549 | Niveau 0 | 3.42153 | 3.37542 | 1.74657 | 6.12101 | 11.5491
443683 | Demi-niveau | 1.4016 | 1.75677 | 0.924394 | 1.30502 | 2.46229
527397 | Niveau 1 | 3.01321 | 1.753 |  | 2.79955 | 5.28217
542851 | Niveau 1 | 3.21021 | 2.30424 | 0.154975 | 3.92047 | 7.39711

# IfcWall: Mur de base:Générique - Int.550, Mur de base:Générique - Int.550:526641
In: Niveau 1
Type - Material: Mur par défaut 0.55 m
Type - Pset_EnvironmentalImpactIndicators - Reference: Générique - Int.550
Type - Pset_ReinforcementBarPitchOfWall - Reference: Générique - Int.550
Type - Pset_WallCommon - IsExternal: no; Reference: Générique - Int.550
Qto_WallBaseQuantities - Height: 3.01021 m; Length: 0.817 m; Width: 0.55 m; GrossFootprintArea: 0.44935 m2; NetVolume: 1.35264 m3; NetSideArea: 2.45935 m2
Pset_EnvironmentalImpactIndicators - sets with these values: 2
Pset_WallCommon - LoadBearing: no; ExtendToStructure: no

# IfcWall: Mur de base:Générique - Int.580 (3)
Type - Material: Mur par défaut 0.58 m
Type - Pset_EnvironmentalImpactIndicators - Reference: Générique - Int.580
Type - Pset_ReinforcementBarPitchOfWall - Reference: Générique - Int.580
Type - Pset_WallCommon - IsExternal: no; Reference: Générique - Int.580
Qto_WallBaseQuantities - Width: 0.58 m
Pset_EnvironmentalImpactIndicators - sets with these values: 2
Pset_WallCommon - LoadBearing: no; ExtendToStructure: no
Name (Mur de base:Générique - Int.580:...) | In | Height (m) | Length (m) | NetVolume (m3) | NetSideArea (m2)
449164 | SS3 | 5.69436 | 7.30917 | 24.1402 | 41.621
482787 | SS1 | 2.37127 | 4.34075 | 5.96999 | 10.2931
550609 | Niveau 1 | 3.01321 | 1.26236 | 2.20619 | 3.80377 | Qto_WallBaseQuantities - GrossFootprintArea: 0.730552 m2

# IfcWall: Mur de base:Int. Plâtre 100 mm (2)
In: Niveau 0
Type - Material: Mur par défaut 0.1 m
Type - Pset_EnvironmentalImpactIndicators - Reference: Int. Plâtre 100 mm
Type - Pset_ReinforcementBarPitchOfWall - Reference: Int. Plâtre 100 mm
Type - Pset_WallCommon - IsExternal: no; Reference: Int. Plâtre 100 mm
Qto_WallBaseQuantities - Height: 1.08038 m; Width: 0.1 m
Pset_EnvironmentalImpactIndicators - sets with these values: 2
Pset_WallCommon - LoadBearing: no; ExtendToStructure: no
Name (Mur de base:Int. Plâtre 100 mm:...) | Length (m) | GrossFootprintArea (m2) | NetVolume (m3) | NetSideArea (m2)
376763 | 3.16928 | 0.316928 | 0.342401 | 3.42401
376934 | 3.17242 | 0.317242 | 0.342741 | 3.42741

# IfcWall: Mur de base:Int. Plâtre 130 mm (3)
Type - Material: Mur par défaut 0.13 m
Type - Pset_EnvironmentalImpactIndicators - Reference: Int. Plâtre 130 mm
Type - Pset_ReinforcementBarPitchOfWall - Reference: Int. Plâtre 130 mm
Type - Pset_WallCommon - IsExternal: no; Reference: Int. Plâtre 130 mm
Qto_WallBaseQuantities - Width: 0.13 m
Pset_EnvironmentalImpactIndicators - sets with these values: 2
Pset_WallCommon - LoadBearing: no; ExtendToStructure: no
Name (Mur de base:Int. Plâtre 130 mm:...) | In | Height (m) | Length (m) | GrossFootprintArea (m2) | NetVolume (m3) | NetSideArea (m2)
281708 | Niveau 0 | 3.40653 | 3.12624 | 0.406412 | 1.38445 | 10.6496
375137 | SS1 | 2.16945 | 4.05774 | 0.00663 | 1.1444 | 8.80306
501970 | Niveau 0 | 3.40653 | 1.08799 | 0.141354 | 0.481815 | 3.70627

# IfcWall: Mur de base:Int. Plâtre 70 mm (32)
Type - Material: Mur par défaut 0.07 m
Type - Pset_EnvironmentalImpactIndicators - Reference: Int. Plâtre 70 mm
Type - Pset_ReinforcementBarPitchOfWall - Reference: Int. Plâtre 70 mm
Type - Pset_WallCommon - IsExternal: no; Reference: Int. Plâtre 70 mm
Qto_WallBaseQuantities - Width: 0.07 m
Pset_EnvironmentalImpactIndicators - sets with these values: 2
Pset_WallCommon - LoadBearing: no; ExtendToStructure: no
Name (Mur de base:Int. Plâtre 70 mm:...) | In | Height (m) | Length (m) | GrossFootprintArea (m2) | NetVolume (m3) | NetSideArea (m2)
281198 | Niveau 0 | 3.40653 | 2.01819 | 0.141224 | 0.48125 | 6.87501
281226 | Niveau 0 | 3.40653 | 1.42739 | 0.0999176 | 0.340372 | 4.86246
281318 | Niveau 0 | 3.40653 | 0.997799 | 0.069846 | 0.237932 | 3.39903
281781 | Niveau 0 | 3.40653 | 3.79752 | 0.265827 | 0.905546 | 12.9364
285107 | Niveau 0 | 3.40653 | 0.350608 | 0.0245425 | 0.0836048 | 1.19435
286139 | Niveau 0 | 3.40653 | 4.70432 | 0.329303 | 1.12178 | 16.0254
286175 | Niveau 0 | 3.07113 | 0.742 | 0.05194 | 0.159514 | 2.27878
286210 | Niveau 0 | 3.07113 | 0.450595 | 0.0315416 | 0.0968683 | 1.38383
286237 | Niveau 0 | 3.07113 | 0.250595 | 0.0175416 | 0.0538725 | 0.769608
300977 | Niveau 0 | 3.40653 | 1.16477 | 0.0729713 | 0.277748 | 3.96782
301229 | Niveau 0 | 3.41113 | 0.569377 | 0.0395282 | 0.135955 | 1.94222
301260 | Niveau 0 | 3.40653 | 1.14876 | 0.0680797 | 0.27393 | 3.91329
528507 | Niveau 1 | 3.01021 | 0.865491 | 0.0605844 | 0.182372 | 2.60531
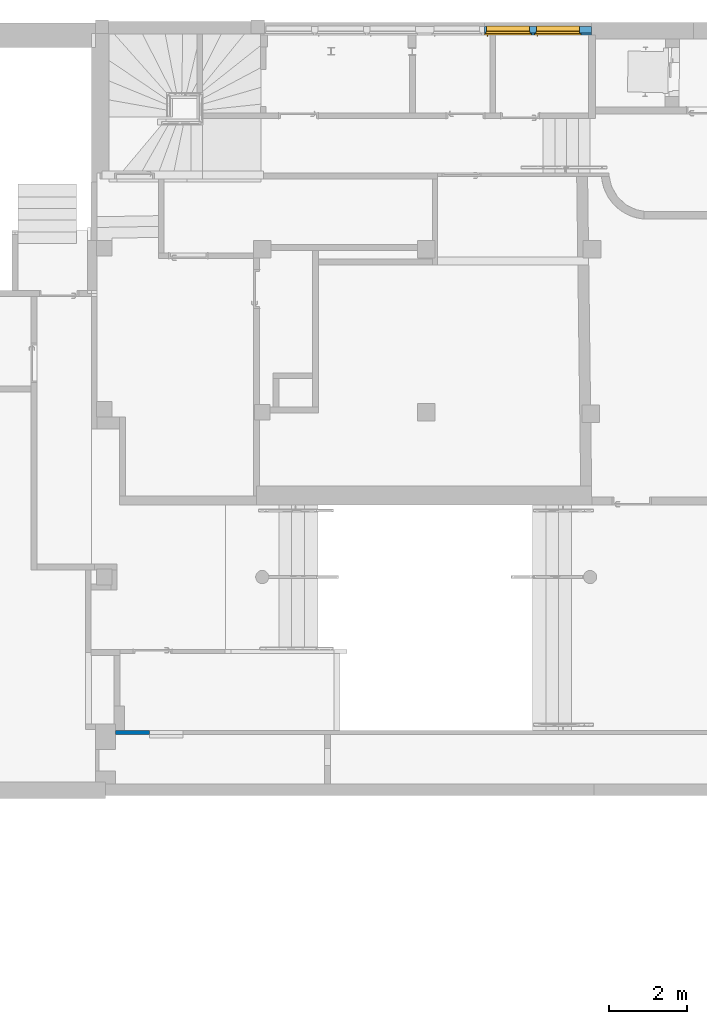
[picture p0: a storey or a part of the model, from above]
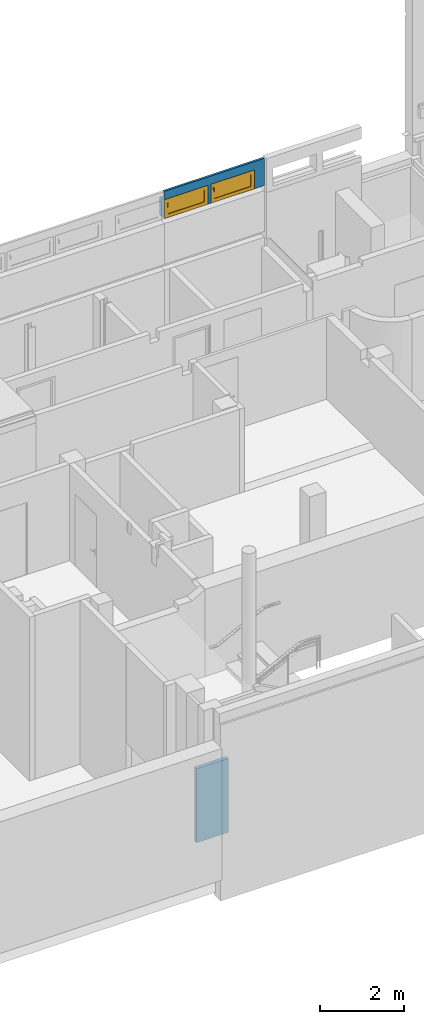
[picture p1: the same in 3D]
Properties of the parts of a building model (IFC4), part 8 of 8

# IfcWall: Mur de base:Int. Plâtre 70 mm (32)
Name (Mur de base:Int. Plâtre 70 mm:...) | In | Height (m) | Length (m) | GrossFootprintArea (m2) | NetVolume (m3) | NetSideArea (m2)
528633 | Niveau 1 | 3.01021 | 0.322 | 0.02254 | 0.0678502 | 0.969289
528656 | Niveau 1 | 3.01021 | 0.922 | 0.06454 | 0.194279 | 2.77542
528888 | Niveau 1 | 3.01021 | 0.252 | 0.01764 | 0.0531002 | 0.758574
529526 | Niveau 1 | 3.01021 | 0.83139 | 0.0581973 | 0.175186 | 2.50266
529558 | Niveau 1 | 3.01021 | 0.233655 | 0.0163558 | 0.0492345 | 0.70335
529574 | Niveau 1 | 3.01021 | 0.200153 | 0.0140107 | 0.0421753 | 0.602504
529653 | Niveau 1 | 3.01021 | 4.20838 | 0.294587 | 0.88677 | 12.6681
530625 | Niveau 1 | 3.01021 | 3.55638 | 0.248946 | 0.749382 | 10.7055
531080 | Niveau 1 | 3.01021 | 4.09363 | 0.286554 | 0.862589 | 12.3227
542896 | Niveau 1 | 3.04521 | 2.83011 | 0.198108 | 0.603281 | 8.6183
552035 | Niveau 1 | 3.01021 | 1.28966 | 0.0902765 | 0.271752 | 3.88216
552485 | Niveau 1 | 2.37021 | 2.838 | 0.19866 | 0.470867 | 6.72667
581704 | Niveau 2 | 2.857 | 0.922331 | 0.0645632 | 0.184457 | 2.6351
582193 | Niveau 2 | 2.857 | 1.54003 | 0.107802 | 0.30799 | 4.39986
610163 | SS2 | 0.360991 | 1.79675 | 0.125772 | 0.0454027 | 0.64861
610182 | SS2 | 0.360991 | 0.15104 | 0.0105728 | 0.00381669 | 0.0545242
617096 | SS1 | 1.54753 | 5.7459 | 0.402213 | 0.622435 | 8.89192
618468 | SS1 | 2.11945 | 1.51546 | 0.106082 | 0.224836 | 3.21194
627683 | Niveau 2 | 2.992 | 2.965 | 0.20755 | 0.62099 | 8.87128

# IfcWall: Murs 1:Murs 1, Murs 1:Murs 1:463818
In: SS2
Type - Material: Mur par défaut
Type - Pset_EnvironmentalImpactIndicators - Reference: Murs 1
Type - Pset_ReinforcementBarPitchOfWall - Reference: Murs 1
Type - Pset_WallCommon - IsExternal: no; Reference: Murs 1
Pset_EnvironmentalImpactIndicators - sets with these values: 2

# IfcWall: mur-rideau1:mur-rideau, mur-rideau1:mur-rideau:636675
In: Demi-niveau
Type - Material: alu finifion bleu
Type - Pset_EnvironmentalImpactIndicators - Reference: mur-rideau
Type - Pset_ReinforcementBarPitchOfWall - Reference: mur-rideau
Type - Pset_WallCommon - IsExternal: no; Reference: mur-rideau
Pset_EnvironmentalImpactIndicators - sets with these values: 2

# IfcWall: mur-rideau:mur-rideau, mur-rideau:mur-rideau:341718
In: Demi-niveau
Type - Material: alu finifion bleu
Type - Pset_EnvironmentalImpactIndicators - Reference: mur-rideau
Type - Pset_ReinforcementBarPitchOfWall - Reference: mur-rideau
Type - Pset_WallCommon - IsExternal: no; Reference: mur-rideau
Pset_EnvironmentalImpactIndicators - sets with these values: 2

# IfcWindow: 1 Vantail - Droit:1.10x0.5 2 (2)
In: Demi-niveau
Type - PredefinedType: WINDOW; Material: PVC - Blanc (4), Fenêtre - Appui
Type - Pset_EnvironmentalImpactIndicators - Reference: 1.10x0.5 2
Type - Pset_WindowCommon - IsExternal: no; Reference: 1.10x0.5 2
OverallHeight: 1.08 m; OverallWidth: 1.2 m; Material: PVC - Blanc, Fenêtre - Appui
Pset_WindowCommon - IsExternal: yes
Qto_WindowBaseQuantities - Height: 0.5 m; Width: 1.1 m; Area: 0.55 m2
Name (1 Vantail - Droit:1.10x0.5 2:...)
503975
504044

# IfcWindow: 1 Vantail - Droit:1.17x0.5 (4)
In: Demi-niveau
Type - PredefinedType: WINDOW; Material: PVC - Blanc (4), Fenêtre - Appui
Type - Pset_EnvironmentalImpactIndicators - Reference: 1.17x0.5
Type - Pset_WindowCommon - IsExternal: no; Reference: 1.17x0.5
OverallHeight: 1.08 m; OverallWidth: 1.27 m; Material: PVC - Blanc, Fenêtre - Appui
Pset_WindowCommon - IsExternal: yes
Qto_WindowBaseQuantities - Height: 0.5 m; Width: 1.17 m; Area: 0.585 m2
Name (1 Vantail - Droit:1.17x0.5:...)
503840
503841
503842
503843

# IfcWindow: 1 Vantail - Droit:1.20x1.70, 1 Vantail - Droit:1.20x1.70:560308
In: Niveau 2
Type - PredefinedType: WINDOW; Material: PVC - Blanc (4), Fenêtre - Appui
Type - Pset_EnvironmentalImpactIndicators - Reference: 1.20x1.70
Type - Pset_WindowCommon - IsExternal: no; Reference: 1.20x1.70
OverallHeight: 1.83 m; OverallWidth: 1.3 m; Material: PVC - Blanc, Fenêtre - Appui
Pset_WindowCommon - IsExternal: yes
Qto_WindowBaseQuantities - Height: 1.7 m; Width: 1.2 m; Area: 2.04 m2

# IfcWindow: 2 Vantaux coulissants - Droits:1.45x3.15 pvc (2)
In: SS2
Type - PredefinedType: WINDOW; Material: PVC, souple (4), Fenêtre - Vitrage
Type - Pset_EnvironmentalImpactIndicators - Reference: 1.45x3.15 pvc
Type - Pset_WindowCommon - IsExternal: no; Reference: 1.45x3.15 pvc; ThermalTransmittance: 3.6886 kg/K/s3
OverallHeight: 1.58 m; OverallWidth: 3.25 m; Material: PVC, souple, Fenêtre - Vitrage
Pset_WindowCommon - IsExternal: yes
Qto_WindowBaseQuantities - Height: 1.45 m; Width: 3.15 m; Area: 4.5675 m2
Name (2 Vantaux coulissants - Droits:1.45x3.15 pvc:...)
410691
410843

# IfcWindow: MR 1 Vantail:MR 1 Vantail (76)
Type - PredefinedType: WINDOW; Material: PVC - Blanc (2)
Type - Pset_EnvironmentalImpactIndicators - Reference: MR 1 Vantail
Type - Pset_WindowCommon - IsExternal: no; Reference: MR 1 Vantail; ThermalTransmittance: 3.6886 kg/K/s3
Material: PVC - Blanc, Fenêtre - Vitrage
Name (MR 1 Vantail:MR 1 Vantail:...) | In | OverallHeight (m) | OverallWidth (m) = Width (m) | Height (m) | Area (m2)
369643 | Niveau 0 | 1.434 | 1.1236 | 1.434 | 1.61124
369852 | Niveau 0 | 1.434 | 1.06 | 1.434 | 1.52004
369875 | Niveau 0 | 1.434 | 1.06 | 1.434 | 1.52004
369898 | Niveau 0 | 1.434 | 1.06 | 1.434 | 1.52004
369921 | Niveau 0 | 1.434 | 1.06 | 1.434 | 1.52004
369944 | Niveau 0 | 1.434 | 1.06 | 1.434 | 1.52004
369967 | Niveau 0 | 1.434 | 1.06 | 1.434 | 1.52004
369990 | Niveau 0 | 1.434 | 1.06 | 1.434 | 1.52004
370013 | Niveau 0 | 1.434 | 1.06 | 1.434 | 1.52004
370036 | Niveau 0 | 1.434 | 1.02113 | 1.434 | 1.46429
392099 | Niveau 0 | 0.948266 | 1.23064 | 0.948266 | 1.16698
392100 | Niveau 0 | 0.948266 | 1.27764 | 0.948266 | 1.21155
392101 | Niveau 0 | 0.948266 | 1.023 | 0.948266 | 0.970076
392166 | Niveau 0 | 0.948266 | 1.1375 | 0.948266 | 1.07865
392383 | Niveau 0 | 0.948266 | 1.1375 | 0.948266 | 1.07865
404731 | Niveau 0 | 1.916 | 0.714369 | 1.916 | 1.36873
511213 | Niveau 1 | 1.42586 | 1.15588 | 1.42586 | 1.64813
511223 | Niveau 1 | 1.42586 | 1.13 | 1.42586 | 1.61122
511233 | Niveau 1 | 1.42586 | 1.13 | 1.42586 | 1.61122
511243 | Niveau 1 | 1.42586 | 1.13 | 1.42586 | 1.61122
511253 | Niveau 1 | 1.42586 | 1.13 | 1.42586 | 1.61122
511263 | Niveau 1 | 1.42586 | 1.13 | 1.42586 | 1.61122
511273 | Niveau 1 | 1.42586 | 1.01113 | 1.42586 | 1.44172
511283 | Niveau 1 | 1.42586 | 1.13 | 1.42586 | 1.61122
511293 | Niveau 1 | 1.42586 | 1.13 | 1.42586 | 1.61122
511303 | Niveau 1 | 1.42586 | 1.13 | 1.42586 | 1.61122
511313 | Niveau 1 | 1.42586 | 1.16219 | 1.42586 | 1.65712
511323 | Niveau 1 | 1.42586 | 1.13 | 1.42586 | 1.61122
511333 | Niveau 1 | 1.42586 | 1.16865 | 1.42586 | 1.66634
511343 | Niveau 1 | 1.42586 | 1.13 | 1.42586 | 1.61122
512591 | Niveau 1 | 1.42586 | 1.10568 | 1.42586 | 1.57655
512768 | Niveau 1 | 1.42586 | 1.06 | 1.42586 | 1.51141
512996 | Niveau 1 | 1.42586 | 1.07702 | 1.42586 | 1.53568
513012 | Niveau 1 | 1.42586 | 1.12298 | 1.42586 | 1.60122
513028 | Niveau 1 | 1.42586 | 1.06 | 1.42586 | 1.51141
513044 | Niveau 1 | 1.42586 | 1.09428 | 1.42586 | 1.56029
513060 | Niveau 1 | 1.42586 | 1.12572 | 1.42586 | 1.60512
513076 | Niveau 1 | 1.42586 | 1.06 | 1.42586 | 1.51141
513092 | Niveau 1 | 1.42586 | 1.07728 | 1.42586 | 1.53604
513108 | Niveau 1 | 1.42586 | 1.16272 | 1.42586 | 1.65788
513124 | Niveau 1 | 1.42586 | 1.06 | 1.42586 | 1.51141
513140 | Niveau 1 | 1.42586 | 1.06 | 1.42586 | 1.51141
513156 | Niveau 1 | 1.42586 | 1.07 | 1.42586 | 1.52567
513172 | Niveau 1 | 1.42537 | 1.125 | 1.42537 | 1.60354
513188 | Niveau 1 | 1.42537 | 1.06 | 1.42537 | 1.51089
513204 | Niveau 1 | 1.42537 | 1.06 | 1.42537 | 1.51089
518368 | Niveau 1 | 1.42586 | 1.11256 | 1.42586 | 1.58636
518439 | Niveau 1 | 1.42586 | 1.06 | 1.42586 | 1.51141
518560 | Niveau 1 | 1.42586 | 1.06 | 1.42586 | 1.51141
518578 | Niveau 1 | 1.42586 | 1.06 | 1.42586 | 1.51141
518596 | Niveau 1 | 1.42586 | 1.06 | 1.42586 | 1.51141
518614 | Niveau 1 | 1.42586 | 1.08165 | 1.42586 | 1.54228
518630 | Niveau 1 | 1.42586 | 1.06 | 1.42586 | 1.51141
518648 | Niveau 1 | 1.42586 | 1.06 | 1.42586 | 1.51141
518666 | Niveau 1 | 1.42586 | 1.06 | 1.42586 | 1.51141
518684 | Niveau 1 | 1.42586 | 1.05735 | 1.42586 | 1.50764
518702 | Niveau 1 | 1.42586 | 1.06 | 1.42586 | 1.51141
518720 | Niveau 1 | 1.42586 | 1.06 | 1.42586 | 1.51141
518738 | Niveau 1 | 1.42586 | 1.06 | 1.42586 | 1.51141
518756 | Niveau 1 | 1.42586 | 1.06 | 1.42586 | 1.51141
518774 | Niveau 1 | 1.42586 | 1.06 | 1.42586 | 1.51141
518828 | Niveau 1 | 1.42586 | 1.2559 | 1.42586 | 1.79074
561133 | Niveau 2 | 1.53629 | 0.86 | 1.53629 | 1.32121
561696 | Niveau 2 | 1.54129 | 1.01912 | 1.54129 | 1.57075
562054 | Niveau 2 | 1.54129 | 0.904 | 1.54129 | 1.39332
564060 | Niveau 2 | 1.54129 | 1.01942 | 1.54129 | 1.57121
564065 | Niveau 2 | 1.54129 | 0.904 | 1.54129 | 1.39332
583228 | Niveau 2 | 1.05789 | 1.16697 | 1.05789 | 1.23453
590535 | Niveau 2 | 1.492 | 0.649 | 1.492 | 0.968308
590511 | Niveau 2 | 0.49 | 1.928 | 0.422 | 0.813616
591106 | Niveau 2 | 1.492 | 0.609 | 1.492 | 0.908628
591103 | Niveau 2 | 0.49 | 1.896 | 0.422 | 0.800112
591471 | Niveau 2 | 0.652629 | 1.047 | 0.652629 | 0.683302
595798 | Niveau 2 | 0.49 | 0.913176 | 0.476 | 0.434672
595977 | Niveau 2 | 0.49 | 0.884745 | 0.476 | 0.421139
596385 | Niveau 2 | 0.49 | 1.14926 | 0.476 | 0.547046

# IfcWindow: MR2 :MR2 (3)
In: Niveau 2
Type - PredefinedType: WINDOW; Material: PVC - Blanc (2)
Type - Pset_EnvironmentalImpactIndicators - Reference: MR2
Type - Pset_WindowCommon - IsExternal: no; Reference: MR2; ThermalTransmittance: 3.6886 kg/K/s3
Material: PVC - Blanc, Fenêtre - Vitrage
Name (MR2 :MR2:...) | OverallHeight (m) = Height (m) | OverallWidth (m) = Width (m) | Area (m2)
607801 | 1.53629 | 1.69611 | 2.60572
562003 | 1.54129 | 1.727 | 2.6618
564063 | 1.54129 | 1.727 | 2.6618

# IfcWindow: Skydome:1100x1100 (3)
In: Niveau 2
Type - PredefinedType: WINDOW; Material: Métal - Aluminium, Verre
Type - Pset_EnvironmentalImpactIndicators - Reference: 1100x1100
Type - Pset_WindowCommon - IsExternal: no; Reference: 1100x1100; ThermalTransmittance: 3.6886 kg/K/s3
OverallHeight: 1.08 m; OverallWidth: 1.29715 m; Material: Verre, Métal - Aluminium
Pset_WindowCommon - IsExternal: yes
Qto_WindowBaseQuantities - Height: 0 m; Width: 1.1 m; Area: 0 m2
Name (Skydome:1100x1100:...)
629907
629966
630306

# IfcWindow: grille fenetre1:grille fenetre, grille fenetre1:grille fenetre:505833
In: Demi-niveau
Type - PredefinedType: WINDOW; Material: Plâtre
Type - Pset_EnvironmentalImpactIndicators - Reference: grille fenetre
Type - Pset_WindowCommon - IsExternal: no; Reference: grille fenetre
OverallHeight: 0.512948 m; OverallWidth: 2.68995 m
Qto_WindowBaseQuantities - Area: 0.0148085 m2

# IfcWindow: grille fenetre2:grille fenetre, grille fenetre2:grille fenetre:505965
In: Demi-niveau
Type - PredefinedType: WINDOW; Material: PVC, souple
Type - Pset_EnvironmentalImpactIndicators - Reference: grille fenetre
Type - Pset_WindowCommon - IsExternal: no; Reference: grille fenetre
OverallHeight: 0.512948 m; OverallWidth: 2.68995 m; Material: PVC, souple, Plâtre

# IfcWindow: grille fenetre:grille fenetre, grille fenetre:grille fenetre:505805
In: Demi-niveau
Type - PredefinedType: WINDOW; Material: Plâtre
Type - Pset_EnvironmentalImpactIndicators - Reference: grille fenetre
Type - Pset_WindowCommon - IsExternal: no; Reference: grille fenetre
OverallHeight: 0.512948 m; OverallWidth: 2.68995 m
Qto_WindowBaseQuantities - Area: 0.0148085 m2

# IfcStairFlightType, no part of this type: Volée monobloc:Profondeur de structure 170 mm
Pset_EnvironmentalImpactIndicators - Reference: Profondeur de structure 170 mm
Pset_StairFlightCommon - Reference: Profondeur de structure 170 mm

# IfcStairFlightType, no part of this type: Volée monobloc:Profondeur de structure 170 mm
Pset_EnvironmentalImpactIndicators - Reference: Profondeur de structure 170 mm
Pset_StairFlightCommon - Reference: Profondeur de structure 170 mm

# IfcStairFlightType, no part of this type: Volée monobloc:Profondeur de structure 170 mm
Pset_EnvironmentalImpactIndicators - Reference: Profondeur de structure 170 mm
Pset_StairFlightCommon - Reference: Profondeur de structure 170 mm

# IfcStairFlightType, no part of this type: Volée monobloc:Profondeur de structure 180
Pset_EnvironmentalImpactIndicators - Reference: Profondeur de structure 180
Pset_StairFlightCommon - Reference: Profondeur de structure 180

# IfcStairFlightType, no part of this type: Volée monobloc:Profondeur de structure 200 2
Pset_EnvironmentalImpactIndicators - Reference: Profondeur de structure 200 2
Pset_StairFlightCommon - Reference: Profondeur de structure 200 2

# IfcStairFlightType, no part of this type: Volée monobloc:Profondeur de structure 200 2
Pset_EnvironmentalImpactIndicators - Reference: Profondeur de structure 200 2
Pset_StairFlightCommon - Reference: Profondeur de structure 200 2
